VERSION 5.8 ;
BUSBITCHARS "[]" ;
DIVIDERCHAR "/" ;
UNITS
    DATABASE MICRONS 1000 ;
END UNITS

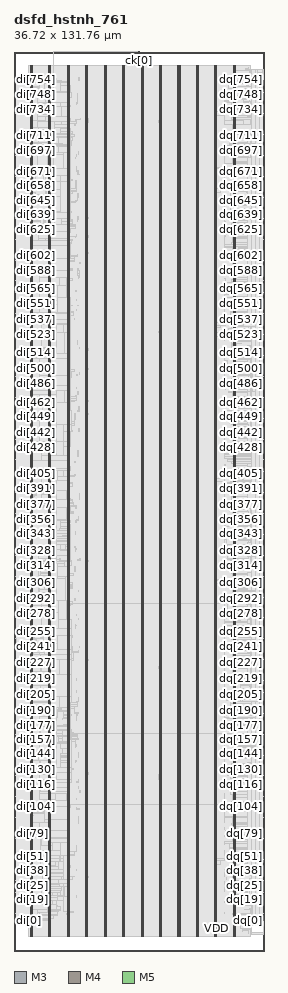
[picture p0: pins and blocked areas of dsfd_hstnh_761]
MACRO dsfd_hstnh_761
  FOREIGN dsfd_hstnh_761 0 0 ;
  CLASS BLOCK ;
  SIZE 36.72 BY 131.76 ;
  PIN ck[0]
    DIRECTION INPUT ;
    USE SIGNAL ;
    PORT
      LAYER M3 ;
        RECT  18.36 131.616 18.378 131.76 ;
    END
    PORT
      LAYER M3 ;
        RECT  18.18 131.593 18.378 131.628 ;
    END
  END ck[0]
  PIN di[0]
    DIRECTION INPUT ;
    USE SIGNAL ;
    PORT
      LAYER M4 ;
        RECT  0 4.416 0.192 4.44 ;
    END
  END di[0]
  PIN di[100]
    DIRECTION INPUT ;
    USE SIGNAL ;
    PORT
      LAYER M4 ;
        RECT  0 20.592 0.192 20.616 ;
    END
  END di[100]
  PIN di[101]
    DIRECTION INPUT ;
    USE SIGNAL ;
    PORT
      LAYER M4 ;
        RECT  0 20.736 0.192 20.76 ;
    END
  END di[101]
  PIN di[102]
    DIRECTION INPUT ;
    USE SIGNAL ;
    PORT
      LAYER M4 ;
        RECT  0 20.928 0.192 20.952 ;
    END
  END di[102]
  PIN di[103]
    DIRECTION INPUT ;
    USE SIGNAL ;
    PORT
      LAYER M4 ;
        RECT  0 21.072 0.192 21.096 ;
    END
  END di[103]
  PIN di[104]
    DIRECTION INPUT ;
    USE SIGNAL ;
    PORT
      LAYER M4 ;
        RECT  0 21.216 0.192 21.24 ;
    END
  END di[104]
  PIN di[105]
    DIRECTION INPUT ;
    USE SIGNAL ;
    PORT
      LAYER M4 ;
        RECT  0 21.408 0.192 21.432 ;
    END
  END di[105]
  PIN di[106]
    DIRECTION INPUT ;
    USE SIGNAL ;
    PORT
      LAYER M4 ;
        RECT  0 21.552 0.192 21.576 ;
    END
  END di[106]
  PIN di[107]
    DIRECTION INPUT ;
    USE SIGNAL ;
    PORT
      LAYER M4 ;
        RECT  0 21.744 0.192 21.768 ;
    END
  END di[107]
  PIN di[108]
    DIRECTION INPUT ;
    USE SIGNAL ;
    PORT
      LAYER M4 ;
        RECT  0 21.888 0.192 21.912 ;
    END
  END di[108]
  PIN di[109]
    DIRECTION INPUT ;
    USE SIGNAL ;
    PORT
      LAYER M4 ;
        RECT  0 22.032 0.192 22.056 ;
    END
  END di[109]
  PIN di[10]
    DIRECTION INPUT ;
    USE SIGNAL ;
    PORT
      LAYER M4 ;
        RECT  0 6.048 0.192 6.072 ;
    END
  END di[10]
  PIN di[110]
    DIRECTION INPUT ;
    USE SIGNAL ;
    PORT
      LAYER M4 ;
        RECT  0 22.224 0.192 22.248 ;
    END
  END di[110]
  PIN di[111]
    DIRECTION INPUT ;
    USE SIGNAL ;
    PORT
      LAYER M4 ;
        RECT  0 22.368 0.192 22.392 ;
    END
  END di[111]
  PIN di[112]
    DIRECTION INPUT ;
    USE SIGNAL ;
    PORT
      LAYER M4 ;
        RECT  0 22.512 0.192 22.536 ;
    END
  END di[112]
  PIN di[113]
    DIRECTION INPUT ;
    USE SIGNAL ;
    PORT
      LAYER M4 ;
        RECT  0 22.704 0.192 22.728 ;
    END
  END di[113]
  PIN di[114]
    DIRECTION INPUT ;
    USE SIGNAL ;
    PORT
      LAYER M4 ;
        RECT  0 22.848 0.192 22.872 ;
    END
  END di[114]
  PIN di[115]
    DIRECTION INPUT ;
    USE SIGNAL ;
    PORT
      LAYER M4 ;
        RECT  0 23.04 0.192 23.064 ;
    END
  END di[115]
  PIN di[116]
    DIRECTION INPUT ;
    USE SIGNAL ;
    PORT
      LAYER M4 ;
        RECT  0 23.184 0.192 23.208 ;
    END
  END di[116]
  PIN di[117]
    DIRECTION INPUT ;
    USE SIGNAL ;
    PORT
      LAYER M4 ;
        RECT  0 23.328 0.192 23.352 ;
    END
  END di[117]
  PIN di[118]
    DIRECTION INPUT ;
    USE SIGNAL ;
    PORT
      LAYER M4 ;
        RECT  0 23.52 0.192 23.544 ;
    END
  END di[118]
  PIN di[119]
    DIRECTION INPUT ;
    USE SIGNAL ;
    PORT
      LAYER M4 ;
        RECT  0 23.664 0.192 23.688 ;
    END
  END di[119]
  PIN di[11]
    DIRECTION INPUT ;
    USE SIGNAL ;
    PORT
      LAYER M4 ;
        RECT  0 6.192 0.192 6.216 ;
    END
  END di[11]
  PIN di[120]
    DIRECTION INPUT ;
    USE SIGNAL ;
    PORT
      LAYER M4 ;
        RECT  0 23.808 0.192 23.832 ;
    END
  END di[120]
  PIN di[121]
    DIRECTION INPUT ;
    USE SIGNAL ;
    PORT
      LAYER M4 ;
        RECT  0 24 0.192 24.024 ;
    END
  END di[121]
  PIN di[122]
    DIRECTION INPUT ;
    USE SIGNAL ;
    PORT
      LAYER M4 ;
        RECT  0 24.144 0.192 24.168 ;
    END
  END di[122]
  PIN di[123]
    DIRECTION INPUT ;
    USE SIGNAL ;
    PORT
      LAYER M4 ;
        RECT  0 24.336 0.192 24.36 ;
    END
  END di[123]
  PIN di[124]
    DIRECTION INPUT ;
    USE SIGNAL ;
    PORT
      LAYER M4 ;
        RECT  0 24.48 0.192 24.504 ;
    END
  END di[124]
  PIN di[125]
    DIRECTION INPUT ;
    USE SIGNAL ;
    PORT
      LAYER M4 ;
        RECT  0 24.624 0.192 24.648 ;
    END
  END di[125]
  PIN di[126]
    DIRECTION INPUT ;
    USE SIGNAL ;
    PORT
      LAYER M4 ;
        RECT  0 24.816 0.192 24.84 ;
    END
  END di[126]
  PIN di[127]
    DIRECTION INPUT ;
    USE SIGNAL ;
    PORT
      LAYER M4 ;
        RECT  0 24.96 0.192 24.984 ;
    END
  END di[127]
  PIN di[128]
    DIRECTION INPUT ;
    USE SIGNAL ;
    PORT
      LAYER M4 ;
        RECT  0 25.104 0.192 25.128 ;
    END
  END di[128]
  PIN di[129]
    DIRECTION INPUT ;
    USE SIGNAL ;
    PORT
      LAYER M4 ;
        RECT  0 25.296 0.192 25.32 ;
    END
  END di[129]
  PIN di[12]
    DIRECTION INPUT ;
    USE SIGNAL ;
    PORT
      LAYER M4 ;
        RECT  0 6.336 0.192 6.36 ;
    END
  END di[12]
  PIN di[130]
    DIRECTION INPUT ;
    USE SIGNAL ;
    PORT
      LAYER M4 ;
        RECT  0 25.44 0.192 25.464 ;
    END
  END di[130]
  PIN di[131]
    DIRECTION INPUT ;
    USE SIGNAL ;
    PORT
      LAYER M4 ;
        RECT  0 25.584 0.192 25.608 ;
    END
  END di[131]
  PIN di[132]
    DIRECTION INPUT ;
    USE SIGNAL ;
    PORT
      LAYER M4 ;
        RECT  0 25.776 0.192 25.8 ;
    END
  END di[132]
  PIN di[133]
    DIRECTION INPUT ;
    USE SIGNAL ;
    PORT
      LAYER M4 ;
        RECT  0 25.92 0.192 25.944 ;
    END
  END di[133]
  PIN di[134]
    DIRECTION INPUT ;
    USE SIGNAL ;
    PORT
      LAYER M4 ;
        RECT  0 26.112 0.192 26.136 ;
    END
  END di[134]
  PIN di[135]
    DIRECTION INPUT ;
    USE SIGNAL ;
    PORT
      LAYER M4 ;
        RECT  0 26.256 0.192 26.28 ;
    END
  END di[135]
  PIN di[136]
    DIRECTION INPUT ;
    USE SIGNAL ;
    PORT
      LAYER M4 ;
        RECT  0 26.4 0.192 26.424 ;
    END
  END di[136]
  PIN di[137]
    DIRECTION INPUT ;
    USE SIGNAL ;
    PORT
      LAYER M4 ;
        RECT  0 26.592 0.192 26.616 ;
    END
  END di[137]
  PIN di[138]
    DIRECTION INPUT ;
    USE SIGNAL ;
    PORT
      LAYER M4 ;
        RECT  0 26.736 0.192 26.76 ;
    END
  END di[138]
  PIN di[139]
    DIRECTION INPUT ;
    USE SIGNAL ;
    PORT
      LAYER M4 ;
        RECT  0 26.88 0.192 26.904 ;
    END
  END di[139]
  PIN di[13]
    DIRECTION INPUT ;
    USE SIGNAL ;
    PORT
      LAYER M4 ;
        RECT  0 6.528 0.192 6.552 ;
    END
  END di[13]
  PIN di[140]
    DIRECTION INPUT ;
    USE SIGNAL ;
    PORT
      LAYER M4 ;
        RECT  0 27.072 0.192 27.096 ;
    END
  END di[140]
  PIN di[141]
    DIRECTION INPUT ;
    USE SIGNAL ;
    PORT
      LAYER M4 ;
        RECT  0 27.216 0.192 27.24 ;
    END
  END di[141]
  PIN di[142]
    DIRECTION INPUT ;
    USE SIGNAL ;
    PORT
      LAYER M4 ;
        RECT  0 27.408 0.192 27.432 ;
    END
  END di[142]
  PIN di[143]
    DIRECTION INPUT ;
    USE SIGNAL ;
    PORT
      LAYER M4 ;
        RECT  0 27.552 0.192 27.576 ;
    END
  END di[143]
  PIN di[144]
    DIRECTION INPUT ;
    USE SIGNAL ;
    PORT
      LAYER M4 ;
        RECT  0 27.696 0.192 27.72 ;
    END
  END di[144]
  PIN di[145]
    DIRECTION INPUT ;
    USE SIGNAL ;
    PORT
      LAYER M4 ;
        RECT  0 27.888 0.192 27.912 ;
    END
  END di[145]
  PIN di[146]
    DIRECTION INPUT ;
    USE SIGNAL ;
    PORT
      LAYER M4 ;
        RECT  0 28.032 0.192 28.056 ;
    END
  END di[146]
  PIN di[147]
    DIRECTION INPUT ;
    USE SIGNAL ;
    PORT
      LAYER M4 ;
        RECT  0 28.176 0.192 28.2 ;
    END
  END di[147]
  PIN di[148]
    DIRECTION INPUT ;
    USE SIGNAL ;
    PORT
      LAYER M4 ;
        RECT  0 28.368 0.192 28.392 ;
    END
  END di[148]
  PIN di[149]
    DIRECTION INPUT ;
    USE SIGNAL ;
    PORT
      LAYER M4 ;
        RECT  0 28.512 0.192 28.536 ;
    END
  END di[149]
  PIN di[14]
    DIRECTION INPUT ;
    USE SIGNAL ;
    PORT
      LAYER M4 ;
        RECT  0 6.672 0.192 6.696 ;
    END
  END di[14]
  PIN di[150]
    DIRECTION INPUT ;
    USE SIGNAL ;
    PORT
      LAYER M4 ;
        RECT  0 28.704 0.192 28.728 ;
    END
  END di[150]
  PIN di[151]
    DIRECTION INPUT ;
    USE SIGNAL ;
    PORT
      LAYER M4 ;
        RECT  0 28.848 0.192 28.872 ;
    END
  END di[151]
  PIN di[152]
    DIRECTION INPUT ;
    USE SIGNAL ;
    PORT
      LAYER M4 ;
        RECT  0 28.992 0.192 29.016 ;
    END
  END di[152]
  PIN di[153]
    DIRECTION INPUT ;
    USE SIGNAL ;
    PORT
      LAYER M4 ;
        RECT  0 29.184 0.192 29.208 ;
    END
  END di[153]
  PIN di[154]
    DIRECTION INPUT ;
    USE SIGNAL ;
    PORT
      LAYER M4 ;
        RECT  0 29.328 0.192 29.352 ;
    END
  END di[154]
  PIN di[155]
    DIRECTION INPUT ;
    USE SIGNAL ;
    PORT
      LAYER M4 ;
        RECT  0 29.472 0.192 29.496 ;
    END
  END di[155]
  PIN di[156]
    DIRECTION INPUT ;
    USE SIGNAL ;
    PORT
      LAYER M4 ;
        RECT  0 29.664 0.192 29.688 ;
    END
  END di[156]
  PIN di[157]
    DIRECTION INPUT ;
    USE SIGNAL ;
    PORT
      LAYER M4 ;
        RECT  0 29.808 0.192 29.832 ;
    END
  END di[157]
  PIN di[158]
    DIRECTION INPUT ;
    USE SIGNAL ;
    PORT
      LAYER M4 ;
        RECT  0 29.952 0.192 29.976 ;
    END
  END di[158]
  PIN di[159]
    DIRECTION INPUT ;
    USE SIGNAL ;
    PORT
      LAYER M4 ;
        RECT  0 30.144 0.192 30.168 ;
    END
  END di[159]
  PIN di[15]
    DIRECTION INPUT ;
    USE SIGNAL ;
    PORT
      LAYER M4 ;
        RECT  0 6.816 0.192 6.84 ;
    END
  END di[15]
  PIN di[160]
    DIRECTION INPUT ;
    USE SIGNAL ;
    PORT
      LAYER M4 ;
        RECT  0 30.288 0.192 30.312 ;
    END
  END di[160]
  PIN di[161]
    DIRECTION INPUT ;
    USE SIGNAL ;
    PORT
      LAYER M4 ;
        RECT  0 30.48 0.192 30.504 ;
    END
  END di[161]
  PIN di[162]
    DIRECTION INPUT ;
    USE SIGNAL ;
    PORT
      LAYER M4 ;
        RECT  0 30.624 0.192 30.648 ;
    END
  END di[162]
  PIN di[163]
    DIRECTION INPUT ;
    USE SIGNAL ;
    PORT
      LAYER M4 ;
        RECT  0 30.768 0.192 30.792 ;
    END
  END di[163]
  PIN di[164]
    DIRECTION INPUT ;
    USE SIGNAL ;
    PORT
      LAYER M4 ;
        RECT  0 30.96 0.192 30.984 ;
    END
  END di[164]
  PIN di[165]
    DIRECTION INPUT ;
    USE SIGNAL ;
    PORT
      LAYER M4 ;
        RECT  0 31.104 0.192 31.128 ;
    END
  END di[165]
  PIN di[166]
    DIRECTION INPUT ;
    USE SIGNAL ;
    PORT
      LAYER M4 ;
        RECT  0 31.248 0.192 31.272 ;
    END
  END di[166]
  PIN di[167]
    DIRECTION INPUT ;
    USE SIGNAL ;
    PORT
      LAYER M4 ;
        RECT  0 31.44 0.192 31.464 ;
    END
  END di[167]
  PIN di[168]
    DIRECTION INPUT ;
    USE SIGNAL ;
    PORT
      LAYER M4 ;
        RECT  0 31.584 0.192 31.608 ;
    END
  END di[168]
  PIN di[169]
    DIRECTION INPUT ;
    USE SIGNAL ;
    PORT
      LAYER M4 ;
        RECT  0 31.776 0.192 31.8 ;
    END
  END di[169]
  PIN di[16]
    DIRECTION INPUT ;
    USE SIGNAL ;
    PORT
      LAYER M4 ;
        RECT  0 7.008 0.192 7.032 ;
    END
  END di[16]
  PIN di[170]
    DIRECTION INPUT ;
    USE SIGNAL ;
    PORT
      LAYER M4 ;
        RECT  0 31.92 0.192 31.944 ;
    END
  END di[170]
  PIN di[171]
    DIRECTION INPUT ;
    USE SIGNAL ;
    PORT
      LAYER M4 ;
        RECT  0 32.064 0.192 32.088 ;
    END
  END di[171]
  PIN di[172]
    DIRECTION INPUT ;
    USE SIGNAL ;
    PORT
      LAYER M4 ;
        RECT  0 32.256 0.192 32.28 ;
    END
  END di[172]
  PIN di[173]
    DIRECTION INPUT ;
    USE SIGNAL ;
    PORT
      LAYER M4 ;
        RECT  0 32.4 0.192 32.424 ;
    END
  END di[173]
  PIN di[174]
    DIRECTION INPUT ;
    USE SIGNAL ;
    PORT
      LAYER M4 ;
        RECT  0 32.544 0.192 32.568 ;
    END
  END di[174]
  PIN di[175]
    DIRECTION INPUT ;
    USE SIGNAL ;
    PORT
      LAYER M4 ;
        RECT  0 32.736 0.192 32.76 ;
    END
  END di[175]
  PIN di[176]
    DIRECTION INPUT ;
    USE SIGNAL ;
    PORT
      LAYER M4 ;
        RECT  0 32.88 0.192 32.904 ;
    END
  END di[176]
  PIN di[177]
    DIRECTION INPUT ;
    USE SIGNAL ;
    PORT
      LAYER M4 ;
        RECT  0 33.072 0.192 33.096 ;
    END
  END di[177]
  PIN di[178]
    DIRECTION INPUT ;
    USE SIGNAL ;
    PORT
      LAYER M4 ;
        RECT  0 33.216 0.192 33.24 ;
    END
  END di[178]
  PIN di[179]
    DIRECTION INPUT ;
    USE SIGNAL ;
    PORT
      LAYER M4 ;
        RECT  0 33.36 0.192 33.384 ;
    END
  END di[179]
  PIN di[17]
    DIRECTION INPUT ;
    USE SIGNAL ;
    PORT
      LAYER M4 ;
        RECT  0 7.152 0.192 7.176 ;
    END
  END di[17]
  PIN di[180]
    DIRECTION INPUT ;
    USE SIGNAL ;
    PORT
      LAYER M4 ;
        RECT  0 33.552 0.192 33.576 ;
    END
  END di[180]
  PIN di[181]
    DIRECTION INPUT ;
    USE SIGNAL ;
    PORT
      LAYER M4 ;
        RECT  0 33.696 0.192 33.72 ;
    END
  END di[181]
  PIN di[182]
    DIRECTION INPUT ;
    USE SIGNAL ;
    PORT
      LAYER M4 ;
        RECT  0 33.84 0.192 33.864 ;
    END
  END di[182]
  PIN di[183]
    DIRECTION INPUT ;
    USE SIGNAL ;
    PORT
      LAYER M4 ;
        RECT  0 34.032 0.192 34.056 ;
    END
  END di[183]
  PIN di[184]
    DIRECTION INPUT ;
    USE SIGNAL ;
    PORT
      LAYER M4 ;
        RECT  0 34.176 0.192 34.2 ;
    END
  END di[184]
  PIN di[185]
    DIRECTION INPUT ;
    USE SIGNAL ;
    PORT
      LAYER M4 ;
        RECT  0 34.32 0.192 34.344 ;
    END
  END di[185]
  PIN di[186]
    DIRECTION INPUT ;
    USE SIGNAL ;
    PORT
      LAYER M4 ;
        RECT  0 34.512 0.192 34.536 ;
    END
  END di[186]
  PIN di[187]
    DIRECTION INPUT ;
    USE SIGNAL ;
    PORT
      LAYER M4 ;
        RECT  0 34.656 0.192 34.68 ;
    END
  END di[187]
  PIN di[188]
    DIRECTION INPUT ;
    USE SIGNAL ;
    PORT
      LAYER M4 ;
        RECT  0 34.848 0.192 34.872 ;
    END
  END di[188]
  PIN di[189]
    DIRECTION INPUT ;
    USE SIGNAL ;
    PORT
      LAYER M4 ;
        RECT  0 34.992 0.192 35.016 ;
    END
  END di[189]
  PIN di[18]
    DIRECTION INPUT ;
    USE SIGNAL ;
    PORT
      LAYER M4 ;
        RECT  0 7.344 0.192 7.368 ;
    END
  END di[18]
  PIN di[190]
    DIRECTION INPUT ;
    USE SIGNAL ;
    PORT
      LAYER M4 ;
        RECT  0 35.136 0.192 35.16 ;
    END
  END di[190]
  PIN di[191]
    DIRECTION INPUT ;
    USE SIGNAL ;
    PORT
      LAYER M4 ;
        RECT  0 35.328 0.192 35.352 ;
    END
  END di[191]
  PIN di[192]
    DIRECTION INPUT ;
    USE SIGNAL ;
    PORT
      LAYER M4 ;
        RECT  0 35.472 0.192 35.496 ;
    END
  END di[192]
  PIN di[193]
    DIRECTION INPUT ;
    USE SIGNAL ;
    PORT
      LAYER M4 ;
        RECT  0 35.616 0.192 35.64 ;
    END
  END di[193]
  PIN di[194]
    DIRECTION INPUT ;
    USE SIGNAL ;
    PORT
      LAYER M4 ;
        RECT  0 35.808 0.192 35.832 ;
    END
  END di[194]
  PIN di[195]
    DIRECTION INPUT ;
    USE SIGNAL ;
    PORT
      LAYER M4 ;
        RECT  0 35.952 0.192 35.976 ;
    END
  END di[195]
  PIN di[196]
    DIRECTION INPUT ;
    USE SIGNAL ;
    PORT
      LAYER M4 ;
        RECT  0 36.144 0.192 36.168 ;
    END
  END di[196]
  PIN di[197]
    DIRECTION INPUT ;
    USE SIGNAL ;
    PORT
      LAYER M4 ;
        RECT  0 36.288 0.192 36.312 ;
    END
  END di[197]
  PIN di[198]
    DIRECTION INPUT ;
    USE SIGNAL ;
    PORT
      LAYER M4 ;
        RECT  0 36.432 0.192 36.456 ;
    END
  END di[198]
  PIN di[199]
    DIRECTION INPUT ;
    USE SIGNAL ;
    PORT
      LAYER M4 ;
        RECT  0 36.624 0.192 36.648 ;
    END
  END di[199]
  PIN di[19]
    DIRECTION INPUT ;
    USE SIGNAL ;
    PORT
      LAYER M4 ;
        RECT  0 7.488 0.192 7.512 ;
    END
  END di[19]
  PIN di[1]
    DIRECTION INPUT ;
    USE SIGNAL ;
    PORT
      LAYER M4 ;
        RECT  0 4.56 0.192 4.584 ;
    END
  END di[1]
  PIN di[200]
    DIRECTION INPUT ;
    USE SIGNAL ;
    PORT
      LAYER M4 ;
        RECT  0 36.768 0.192 36.792 ;
    END
  END di[200]
  PIN di[201]
    DIRECTION INPUT ;
    USE SIGNAL ;
    PORT
      LAYER M4 ;
        RECT  0 36.912 0.192 36.936 ;
    END
  END di[201]
  PIN di[202]
    DIRECTION INPUT ;
    USE SIGNAL ;
    PORT
      LAYER M4 ;
        RECT  0 37.104 0.192 37.128 ;
    END
  END di[202]
  PIN di[203]
    DIRECTION INPUT ;
    USE SIGNAL ;
    PORT
      LAYER M4 ;
        RECT  0 37.248 0.192 37.272 ;
    END
  END di[203]
  PIN di[204]
    DIRECTION INPUT ;
    USE SIGNAL ;
    PORT
      LAYER M4 ;
        RECT  0 37.44 0.192 37.464 ;
    END
  END di[204]
  PIN di[205]
    DIRECTION INPUT ;
    USE SIGNAL ;
    PORT
      LAYER M4 ;
        RECT  0 37.584 0.192 37.608 ;
    END
  END di[205]
  PIN di[206]
    DIRECTION INPUT ;
    USE SIGNAL ;
    PORT
      LAYER M4 ;
        RECT  0 37.728 0.192 37.752 ;
    END
  END di[206]
  PIN di[207]
    DIRECTION INPUT ;
    USE SIGNAL ;
    PORT
      LAYER M4 ;
        RECT  0 37.92 0.192 37.944 ;
    END
  END di[207]
  PIN di[208]
    DIRECTION INPUT ;
    USE SIGNAL ;
    PORT
      LAYER M4 ;
        RECT  0 38.064 0.192 38.088 ;
    END
  END di[208]
  PIN di[209]
    DIRECTION INPUT ;
    USE SIGNAL ;
    PORT
      LAYER M4 ;
        RECT  0 38.208 0.192 38.232 ;
    END
  END di[209]
  PIN di[20]
    DIRECTION INPUT ;
    USE SIGNAL ;
    PORT
      LAYER M4 ;
        RECT  0 7.632 0.192 7.656 ;
    END
  END di[20]
  PIN di[210]
    DIRECTION INPUT ;
    USE SIGNAL ;
    PORT
      LAYER M4 ;
        RECT  0 38.4 0.192 38.424 ;
    END
  END di[210]
  PIN di[211]
    DIRECTION INPUT ;
    USE SIGNAL ;
    PORT
      LAYER M4 ;
        RECT  0 38.544 0.192 38.568 ;
    END
  END di[211]
  PIN di[212]
    DIRECTION INPUT ;
    USE SIGNAL ;
    PORT
      LAYER M4 ;
        RECT  0 38.688 0.192 38.712 ;
    END
  END di[212]
  PIN di[213]
    DIRECTION INPUT ;
    USE SIGNAL ;
    PORT
      LAYER M4 ;
        RECT  0 38.88 0.192 38.904 ;
    END
  END di[213]
  PIN di[214]
    DIRECTION INPUT ;
    USE SIGNAL ;
    PORT
      LAYER M4 ;
        RECT  0 39.024 0.192 39.048 ;
    END
  END di[214]
  PIN di[215]
    DIRECTION INPUT ;
    USE SIGNAL ;
    PORT
      LAYER M4 ;
        RECT  0 39.216 0.192 39.24 ;
    END
  END di[215]
  PIN di[216]
    DIRECTION INPUT ;
    USE SIGNAL ;
    PORT
      LAYER M4 ;
        RECT  0 39.36 0.192 39.384 ;
    END
  END di[216]
  PIN di[217]
    DIRECTION INPUT ;
    USE SIGNAL ;
    PORT
      LAYER M4 ;
        RECT  0 39.504 0.192 39.528 ;
    END
  END di[217]
  PIN di[218]
    DIRECTION INPUT ;
    USE SIGNAL ;
    PORT
      LAYER M4 ;
        RECT  0 39.696 0.192 39.72 ;
    END
  END di[218]
  PIN di[219]
    DIRECTION INPUT ;
    USE SIGNAL ;
    PORT
      LAYER M4 ;
        RECT  0 39.84 0.192 39.864 ;
    END
  END di[219]
  PIN di[21]
    DIRECTION INPUT ;
    USE SIGNAL ;
    PORT
      LAYER M4 ;
        RECT  0 7.824 0.192 7.848 ;
    END
  END di[21]
  PIN di[220]
    DIRECTION INPUT ;
    USE SIGNAL ;
    PORT
      LAYER M4 ;
        RECT  0 39.984 0.192 40.008 ;
    END
  END di[220]
  PIN di[221]
    DIRECTION INPUT ;
    USE SIGNAL ;
    PORT
      LAYER M4 ;
        RECT  0 40.176 0.192 40.2 ;
    END
  END di[221]
  PIN di[222]
    DIRECTION INPUT ;
    USE SIGNAL ;
    PORT
      LAYER M4 ;
        RECT  0 40.32 0.192 40.344 ;
    END
  END di[222]
  PIN di[223]
    DIRECTION INPUT ;
    USE SIGNAL ;
    PORT
      LAYER M4 ;
        RECT  0 40.512 0.192 40.536 ;
    END
  END di[223]
  PIN di[224]
    DIRECTION INPUT ;
    USE SIGNAL ;
    PORT
      LAYER M4 ;
        RECT  0 40.656 0.192 40.68 ;
    END
  END di[224]
  PIN di[225]
    DIRECTION INPUT ;
    USE SIGNAL ;
    PORT
      LAYER M4 ;
        RECT  0 40.8 0.192 40.824 ;
    END
  END di[225]
  PIN di[226]
    DIRECTION INPUT ;
    USE SIGNAL ;
    PORT
      LAYER M4 ;
        RECT  0 40.992 0.192 41.016 ;
    END
  END di[226]
  PIN di[227]
    DIRECTION INPUT ;
    USE SIGNAL ;
    PORT
      LAYER M4 ;
        RECT  0 41.136 0.192 41.16 ;
    END
  END di[227]
  PIN di[228]
    DIRECTION INPUT ;
    USE SIGNAL ;
    PORT
      LAYER M4 ;
        RECT  0 41.28 0.192 41.304 ;
    END
  END di[228]
  PIN di[229]
    DIRECTION INPUT ;
    USE SIGNAL ;
    PORT
      LAYER M4 ;
        RECT  0 41.472 0.192 41.496 ;
    END
  END di[229]
  PIN di[22]
    DIRECTION INPUT ;
    USE SIGNAL ;
    PORT
      LAYER M4 ;
        RECT  0 7.968 0.192 7.992 ;
    END
  END di[22]
  PIN di[230]
    DIRECTION INPUT ;
    USE SIGNAL ;
    PORT
      LAYER M4 ;
        RECT  0 41.616 0.192 41.64 ;
    END
  END di[230]
  PIN di[231]
    DIRECTION INPUT ;
    USE SIGNAL ;
    PORT
      LAYER M4 ;
        RECT  0 41.808 0.192 41.832 ;
    END
  END di[231]
  PIN di[232]
    DIRECTION INPUT ;
    USE SIGNAL ;
    PORT
      LAYER M4 ;
        RECT  0 41.952 0.192 41.976 ;
    END
  END di[232]
  PIN di[233]
    DIRECTION INPUT ;
    USE SIGNAL ;
    PORT
      LAYER M4 ;
        RECT  0 42.096 0.192 42.12 ;
    END
  END di[233]
  PIN di[234]
    DIRECTION INPUT ;
    USE SIGNAL ;
    PORT
      LAYER M4 ;
        RECT  0 42.288 0.192 42.312 ;
    END
  END di[234]
  PIN di[235]
    DIRECTION INPUT ;
    USE SIGNAL ;
    PORT
      LAYER M4 ;
        RECT  0 42.432 0.192 42.456 ;
    END
  END di[235]
  PIN di[236]
    DIRECTION INPUT ;
    USE SIGNAL ;
    PORT
      LAYER M4 ;
        RECT  0 42.576 0.192 42.6 ;
    END
  END di[236]
  PIN di[237]
    DIRECTION INPUT ;
    USE SIGNAL ;
    PORT
      LAYER M4 ;
        RECT  0 42.768 0.192 42.792 ;
    END
  END di[237]
  PIN di[238]
    DIRECTION INPUT ;
    USE SIGNAL ;
    PORT
      LAYER M4 ;
        RECT  0 42.912 0.192 42.936 ;
    END
  END di[238]
  PIN di[239]
    DIRECTION INPUT ;
    USE SIGNAL ;
    PORT
      LAYER M4 ;
        RECT  0 43.104 0.192 43.128 ;
    END
  END di[239]
  PIN di[23]
    DIRECTION INPUT ;
    USE SIGNAL ;
    PORT
      LAYER M4 ;
        RECT  0 8.112 0.192 8.136 ;
    END
  END di[23]
  PIN di[240]
    DIRECTION INPUT ;
    USE SIGNAL ;
    PORT
      LAYER M4 ;
        RECT  0 43.248 0.192 43.272 ;
    END
  END di[240]
  PIN di[241]
    DIRECTION INPUT ;
    USE SIGNAL ;
    PORT
      LAYER M4 ;
        RECT  0 43.392 0.192 43.416 ;
    END
  END di[241]
  PIN di[242]
    DIRECTION INPUT ;
    USE SIGNAL ;
    PORT
      LAYER M4 ;
        RECT  0 43.584 0.192 43.608 ;
    END
  END di[242]
  PIN di[243]
    DIRECTION INPUT ;
    USE SIGNAL ;
    PORT
      LAYER M4 ;
        RECT  0 43.728 0.192 43.752 ;
    END
  END di[243]
  PIN di[244]
    DIRECTION INPUT ;
    USE SIGNAL ;
    PORT
      LAYER M4 ;
        RECT  0 43.872 0.192 43.896 ;
    END
  END di[244]
  PIN di[245]
    DIRECTION INPUT ;
    USE SIGNAL ;
    PORT
      LAYER M4 ;
        RECT  0 44.064 0.192 44.088 ;
    END
  END di[245]
  PIN di[246]
    DIRECTION INPUT ;
    USE SIGNAL ;
    PORT
      LAYER M4 ;
        RECT  0 44.208 0.192 44.232 ;
    END
  END di[246]
  PIN di[247]
    DIRECTION INPUT ;
    USE SIGNAL ;
    PORT
      LAYER M4 ;
        RECT  0 44.352 0.192 44.376 ;
    END
  END di[247]
  PIN di[248]
    DIRECTION INPUT ;
    USE SIGNAL ;
    PORT
      LAYER M4 ;
        RECT  0 44.544 0.192 44.568 ;
    END
  END di[248]
  PIN di[249]
    DIRECTION INPUT ;
    USE SIGNAL ;
    PORT
      LAYER M4 ;
        RECT  0 44.688 0.192 44.712 ;
    END
  END di[249]
  PIN di[24]
    DIRECTION INPUT ;
    USE SIGNAL ;
    PORT
      LAYER M4 ;
        RECT  0 8.304 0.192 8.328 ;
    END
  END di[24]
  PIN di[250]
    DIRECTION INPUT ;
    USE SIGNAL ;
    PORT
      LAYER M4 ;
        RECT  0 44.88 0.192 44.904 ;
    END
  END di[250]
  PIN di[251]
    DIRECTION INPUT ;
    USE SIGNAL ;
    PORT
      LAYER M4 ;
        RECT  0 45.024 0.192 45.048 ;
    END
  END di[251]
  PIN di[252]
    DIRECTION INPUT ;
    USE SIGNAL ;
    PORT
      LAYER M4 ;
        RECT  0 45.168 0.192 45.192 ;
    END
  END di[252]
  PIN di[253]
    DIRECTION INPUT ;
    USE SIGNAL ;
    PORT
      LAYER M4 ;
        RECT  0 45.36 0.192 45.384 ;
    END
  END di[253]
  PIN di[254]
    DIRECTION INPUT ;
    USE SIGNAL ;
    PORT
      LAYER M4 ;
        RECT  0 45.504 0.192 45.528 ;
    END
  END di[254]
  PIN di[255]
    DIRECTION INPUT ;
    USE SIGNAL ;
    PORT
      LAYER M4 ;
        RECT  0 45.648 0.192 45.672 ;
    END
  END di[255]
  PIN di[256]
    DIRECTION INPUT ;
    USE SIGNAL ;
    PORT
      LAYER M4 ;
        RECT  0 45.84 0.192 45.864 ;
    END
  END di[256]
  PIN di[257]
    DIRECTION INPUT ;
    USE SIGNAL ;
    PORT
      LAYER M4 ;
        RECT  0 45.984 0.192 46.008 ;
    END
  END di[257]
  PIN di[258]
    DIRECTION INPUT ;
    USE SIGNAL ;
    PORT
      LAYER M4 ;
        RECT  0 46.176 0.192 46.2 ;
    END
  END di[258]
  PIN di[259]
    DIRECTION INPUT ;
    USE SIGNAL ;
    PORT
      LAYER M4 ;
        RECT  0 46.32 0.192 46.344 ;
    END
  END di[259]
  PIN di[25]
    DIRECTION INPUT ;
    USE SIGNAL ;
    PORT
      LAYER M4 ;
        RECT  0 8.448 0.192 8.472 ;
    END
  END di[25]
  PIN di[260]
    DIRECTION INPUT ;
    USE SIGNAL ;
    PORT
      LAYER M4 ;
        RECT  0 46.464 0.192 46.488 ;
    END
  END di[260]
  PIN di[261]
    DIRECTION INPUT ;
    USE SIGNAL ;
    PORT
      LAYER M4 ;
        RECT  0 46.656 0.192 46.68 ;
    END
  END di[261]
  PIN di[262]
    DIRECTION INPUT ;
    USE SIGNAL ;
    PORT
      LAYER M4 ;
        RECT  0 46.8 0.192 46.824 ;
    END
  END di[262]
  PIN di[263]
    DIRECTION INPUT ;
    USE SIGNAL ;
    PORT
      LAYER M4 ;
        RECT  0 46.944 0.192 46.968 ;
    END
  END di[263]
  PIN di[264]
    DIRECTION INPUT ;
    USE SIGNAL ;
    PORT
      LAYER M4 ;
        RECT  0 47.136 0.192 47.16 ;
    END
  END di[264]
  PIN di[265]
    DIRECTION INPUT ;
    USE SIGNAL ;
    PORT
      LAYER M4 ;
        RECT  0 47.28 0.192 47.304 ;
    END
  END di[265]
  PIN di[266]
    DIRECTION INPUT ;
    USE SIGNAL ;
    PORT
      LAYER M4 ;
        RECT  0 47.472 0.192 47.496 ;
    END
  END di[266]
  PIN di[267]
    DIRECTION INPUT ;
    USE SIGNAL ;
    PORT
      LAYER M4 ;
        RECT  0 47.616 0.192 47.64 ;
    END
  END di[267]
  PIN di[268]
    DIRECTION INPUT ;
    USE SIGNAL ;
    PORT
      LAYER M4 ;
        RECT  0 47.76 0.192 47.784 ;
    END
  END di[268]
  PIN di[269]
    DIRECTION INPUT ;
    USE SIGNAL ;
    PORT
      LAYER M4 ;
        RECT  0 47.952 0.192 47.976 ;
    END
  END di[269]
  PIN di[26]
    DIRECTION INPUT ;
    USE SIGNAL ;
    PORT
      LAYER M4 ;
        RECT  0 8.64 0.192 8.664 ;
    END
  END di[26]
  PIN di[270]
    DIRECTION INPUT ;
    USE SIGNAL ;
    PORT
      LAYER M4 ;
        RECT  0 48.096 0.192 48.12 ;
    END
  END di[270]
  PIN di[271]
    DIRECTION INPUT ;
    USE SIGNAL ;
    PORT
      LAYER M4 ;
        RECT  0 48.24 0.192 48.264 ;
    END
  END di[271]
  PIN di[272]
    DIRECTION INPUT ;
    USE SIGNAL ;
    PORT
      LAYER M4 ;
        RECT  0 48.432 0.192 48.456 ;
    END
  END di[272]
  PIN di[273]
    DIRECTION INPUT ;
    USE SIGNAL ;
    PORT
      LAYER M4 ;
        RECT  0 48.576 0.192 48.6 ;
    END
  END di[273]
  PIN di[274]
    DIRECTION INPUT ;
    USE SIGNAL ;
    PORT
      LAYER M4 ;
        RECT  0 48.72 0.192 48.744 ;
    END
  END di[274]
  PIN di[275]
    DIRECTION INPUT ;
    USE SIGNAL ;
    PORT
      LAYER M4 ;
        RECT  0 48.912 0.192 48.936 ;
    END
  END di[275]
  PIN di[276]
    DIRECTION INPUT ;
    USE SIGNAL ;
    PORT
      LAYER M4 ;
        RECT  0 49.056 0.192 49.08 ;
    END
  END di[276]
  PIN di[277]
    DIRECTION INPUT ;
    USE SIGNAL ;
    PORT
      LAYER M4 ;
        RECT  0 49.248 0.192 49.272 ;
    END
  END di[277]
  PIN di[278]
    DIRECTION INPUT ;
    USE SIGNAL ;
    PORT
      LAYER M4 ;
        RECT  0 49.392 0.192 49.416 ;
    END
  END di[278]
  PIN di[279]
    DIRECTION INPUT ;
    USE SIGNAL ;
    PORT
      LAYER M4 ;
        RECT  0 49.536 0.192 49.56 ;
    END
  END di[279]
  PIN di[27]
    DIRECTION INPUT ;
    USE SIGNAL ;
    PORT
      LAYER M4 ;
        RECT  0 8.784 0.192 8.808 ;
    END
  END di[27]
  PIN di[280]
    DIRECTION INPUT ;
    USE SIGNAL ;
    PORT
      LAYER M4 ;
        RECT  0 49.728 0.192 49.752 ;
    END
  END di[280]
  PIN di[281]
    DIRECTION INPUT ;
    USE SIGNAL ;
    PORT
      LAYER M4 ;
        RECT  0 49.872 0.192 49.896 ;
    END
  END di[281]
  PIN di[282]
    DIRECTION INPUT ;
    USE SIGNAL ;
    PORT
      LAYER M4 ;
        RECT  0 50.016 0.192 50.04 ;
    END
  END di[282]
  PIN di[283]
    DIRECTION INPUT ;
    USE SIGNAL ;
    PORT
      LAYER M4 ;
        RECT  0 50.208 0.192 50.232 ;
    END
  END di[283]
  PIN di[284]
    DIRECTION INPUT ;
    USE SIGNAL ;
    PORT
      LAYER M4 ;
        RECT  0 50.352 0.192 50.376 ;
    END
  END di[284]
  PIN di[285]
    DIRECTION INPUT ;
    USE SIGNAL ;
    PORT
      LAYER M4 ;
        RECT  0 50.544 0.192 50.568 ;
    END
  END di[285]
  PIN di[286]
    DIRECTION INPUT ;
    USE SIGNAL ;
    PORT
      LAYER M4 ;
        RECT  0 50.688 0.192 50.712 ;
    END
  END di[286]
  PIN di[287]
    DIRECTION INPUT ;
    USE SIGNAL ;
    PORT
      LAYER M4 ;
        RECT  0 50.832 0.192 50.856 ;
    END
  END di[287]
  PIN di[288]
    DIRECTION INPUT ;
    USE SIGNAL ;
    PORT
      LAYER M4 ;
        RECT  0 51.024 0.192 51.048 ;
    END
  END di[288]
  PIN di[289]
    DIRECTION INPUT ;
    USE SIGNAL ;
    PORT
      LAYER M4 ;
        RECT  0 51.168 0.192 51.192 ;
    END
  END di[289]
  PIN di[28]
    DIRECTION INPUT ;
    USE SIGNAL ;
    PORT
      LAYER M4 ;
        RECT  0 8.928 0.192 8.952 ;
    END
  END di[28]
  PIN di[290]
    DIRECTION INPUT ;
    USE SIGNAL ;
    PORT
      LAYER M4 ;
        RECT  0 51.312 0.192 51.336 ;
    END
  END di[290]
  PIN di[291]
    DIRECTION INPUT ;
    USE SIGNAL ;
    PORT
      LAYER M4 ;
        RECT  0 51.504 0.192 51.528 ;
    END
  END di[291]
  PIN di[292]
    DIRECTION INPUT ;
    USE SIGNAL ;
    PORT
      LAYER M4 ;
        RECT  0 51.648 0.192 51.672 ;
    END
  END di[292]
  PIN di[293]
    DIRECTION INPUT ;
    USE SIGNAL ;
    PORT
      LAYER M4 ;
        RECT  0 51.84 0.192 51.864 ;
    END
  END di[293]
  PIN di[294]
    DIRECTION INPUT ;
    USE SIGNAL ;
    PORT
      LAYER M4 ;
        RECT  0 51.984 0.192 52.008 ;
    END
  END di[294]
  PIN di[295]
    DIRECTION INPUT ;
    USE SIGNAL ;
    PORT
      LAYER M4 ;
        RECT  0 52.128 0.192 52.152 ;
    END
  END di[295]
  PIN di[296]
    DIRECTION INPUT ;
    USE SIGNAL ;
    PORT
      LAYER M4 ;
        RECT  0 52.32 0.192 52.344 ;
    END
  END di[296]
  PIN di[297]
    DIRECTION INPUT ;
    USE SIGNAL ;
    PORT
      LAYER M4 ;
        RECT  0 52.464 0.192 52.488 ;
    END
  END di[297]
  PIN di[298]
    DIRECTION INPUT ;
    USE SIGNAL ;
    PORT
      LAYER M4 ;
        RECT  0 52.608 0.192 52.632 ;
    END
  END di[298]
  PIN di[299]
    DIRECTION INPUT ;
    USE SIGNAL ;
    PORT
      LAYER M4 ;
        RECT  0 52.8 0.192 52.824 ;
    END
  END di[299]
  PIN di[29]
    DIRECTION INPUT ;
    USE SIGNAL ;
    PORT
      LAYER M4 ;
        RECT  0 9.12 0.192 9.144 ;
    END
  END di[29]
  PIN di[2]
    DIRECTION INPUT ;
    USE SIGNAL ;
    PORT
      LAYER M4 ;
        RECT  0 4.752 0.192 4.776 ;
    END
  END di[2]
  PIN di[300]
    DIRECTION INPUT ;
    USE SIGNAL ;
    PORT
      LAYER M4 ;
        RECT  0 52.944 0.192 52.968 ;
    END
  END di[300]
  PIN di[301]
    DIRECTION INPUT ;
    USE SIGNAL ;
    PORT
      LAYER M4 ;
        RECT  0 53.088 0.192 53.112 ;
    END
  END di[301]
  PIN di[302]
    DIRECTION INPUT ;
    USE SIGNAL ;
    PORT
      LAYER M4 ;
        RECT  0 53.28 0.192 53.304 ;
    END
  END di[302]
  PIN di[303]
    DIRECTION INPUT ;
    USE SIGNAL ;
    PORT
      LAYER M4 ;
        RECT  0 53.424 0.192 53.448 ;
    END
  END di[303]
  PIN di[304]
    DIRECTION INPUT ;
    USE SIGNAL ;
    PORT
      LAYER M4 ;
        RECT  0 53.616 0.192 53.64 ;
    END
  END di[304]
  PIN di[305]
    DIRECTION INPUT ;
    USE SIGNAL ;
    PORT
      LAYER M4 ;
        RECT  0 53.76 0.192 53.784 ;
    END
  END di[305]
  PIN di[306]
    DIRECTION INPUT ;
    USE SIGNAL ;
    PORT
      LAYER M4 ;
        RECT  0 53.904 0.192 53.928 ;
    END
  END di[306]
  PIN di[307]
    DIRECTION INPUT ;
    USE SIGNAL ;
    PORT
      LAYER M4 ;
        RECT  0 54.096 0.192 54.12 ;
    END
  END di[307]
  PIN di[308]
    DIRECTION INPUT ;
    USE SIGNAL ;
    PORT
      LAYER M4 ;
        RECT  0 54.24 0.192 54.264 ;
    END
  END di[308]
  PIN di[309]
    DIRECTION INPUT ;
    USE SIGNAL ;
    PORT
      LAYER M4 ;
        RECT  0 54.384 0.192 54.408 ;
    END
  END di[309]
  PIN di[30]
    DIRECTION INPUT ;
    USE SIGNAL ;
    PORT
      LAYER M4 ;
        RECT  0 9.264 0.192 9.288 ;
    END
  END di[30]
  PIN di[310]
    DIRECTION INPUT ;
    USE SIGNAL ;
    PORT
      LAYER M4 ;
        RECT  0 54.576 0.192 54.6 ;
    END
  END di[310]
  PIN di[311]
    DIRECTION INPUT ;
    USE SIGNAL ;
    PORT
      LAYER M4 ;
        RECT  0 54.72 0.192 54.744 ;
    END
  END di[311]
  PIN di[312]
    DIRECTION INPUT ;
    USE SIGNAL ;
    PORT
      LAYER M4 ;
        RECT  0 54.912 0.192 54.936 ;
    END
  END di[312]
  PIN di[313]
    DIRECTION INPUT ;
    USE SIGNAL ;
    PORT
      LAYER M4 ;
        RECT  0 55.056 0.192 55.08 ;
    END
  END di[313]
  PIN di[314]
    DIRECTION INPUT ;
    USE SIGNAL ;
    PORT
      LAYER M4 ;
        RECT  0 55.2 0.192 55.224 ;
    END
  END di[314]
  PIN di[315]
    DIRECTION INPUT ;
    USE SIGNAL ;
    PORT
      LAYER M4 ;
        RECT  0 55.392 0.192 55.416 ;
    END
  END di[315]
  PIN di[316]
    DIRECTION INPUT ;
    USE SIGNAL ;
    PORT
      LAYER M4 ;
        RECT  0 55.536 0.192 55.56 ;
    END
  END di[316]
  PIN di[317]
    DIRECTION INPUT ;
    USE SIGNAL ;
    PORT
      LAYER M4 ;
        RECT  0 55.68 0.192 55.704 ;
    END
  END di[317]
  PIN di[318]
    DIRECTION INPUT ;
    USE SIGNAL ;
    PORT
      LAYER M4 ;
        RECT  0 55.872 0.192 55.896 ;
    END
  END di[318]
  PIN di[319]
    DIRECTION INPUT ;
    USE SIGNAL ;
    PORT
      LAYER M4 ;
        RECT  0 56.016 0.192 56.04 ;
    END
  END di[319]
  PIN di[31]
    DIRECTION INPUT ;
    USE SIGNAL ;
    PORT
      LAYER M4 ;
        RECT  0 9.408 0.192 9.432 ;
    END
  END di[31]
  PIN di[320]
    DIRECTION INPUT ;
    USE SIGNAL ;
    PORT
      LAYER M4 ;
        RECT  0 56.208 0.192 56.232 ;
    END
  END di[320]
  PIN di[321]
    DIRECTION INPUT ;
    USE SIGNAL ;
    PORT
      LAYER M4 ;
        RECT  0 56.352 0.192 56.376 ;
    END
  END di[321]
  PIN di[322]
    DIRECTION INPUT ;
    USE SIGNAL ;
    PORT
      LAYER M4 ;
        RECT  0 56.496 0.192 56.52 ;
    END
  END di[322]
  PIN di[323]
    DIRECTION INPUT ;
    USE SIGNAL ;
    PORT
      LAYER M4 ;
        RECT  0 56.688 0.192 56.712 ;
    END
  END di[323]
  PIN di[324]
    DIRECTION INPUT ;
    USE SIGNAL ;
    PORT
      LAYER M4 ;
        RECT  0 56.832 0.192 56.856 ;
    END
  END di[324]
  PIN di[325]
    DIRECTION INPUT ;
    USE SIGNAL ;
    PORT
      LAYER M4 ;
        RECT  0 56.976 0.192 57 ;
    END
  END di[325]
  PIN di[326]
    DIRECTION INPUT ;
    USE SIGNAL ;
    PORT
      LAYER M4 ;
        RECT  0 57.168 0.192 57.192 ;
    END
  END di[326]
  PIN di[327]
    DIRECTION INPUT ;
    USE SIGNAL ;
    PORT
      LAYER M4 ;
        RECT  0 57.312 0.192 57.336 ;
    END
  END di[327]
  PIN di[328]
    DIRECTION INPUT ;
    USE SIGNAL ;
    PORT
      LAYER M4 ;
        RECT  0 57.456 0.192 57.48 ;
    END
  END di[328]
  PIN di[329]
    DIRECTION INPUT ;
    USE SIGNAL ;
    PORT
      LAYER M4 ;
        RECT  0 57.648 0.192 57.672 ;
    END
  END di[329]
  PIN di[32]
    DIRECTION INPUT ;
    USE SIGNAL ;
    PORT
      LAYER M4 ;
        RECT  0 9.6 0.192 9.624 ;
    END
  END di[32]
  PIN di[330]
    DIRECTION INPUT ;
    USE SIGNAL ;
    PORT
      LAYER M4 ;
        RECT  0 57.792 0.192 57.816 ;
    END
  END di[330]
  PIN di[331]
    DIRECTION INPUT ;
    USE SIGNAL ;
    PORT
      LAYER M4 ;
        RECT  0 57.984 0.192 58.008 ;
    END
  END di[331]
  PIN di[332]
    DIRECTION INPUT ;
    USE SIGNAL ;
    PORT
      LAYER M4 ;
        RECT  0 58.128 0.192 58.152 ;
    END
  END di[332]
  PIN di[333]
    DIRECTION INPUT ;
    USE SIGNAL ;
    PORT
      LAYER M4 ;
        RECT  0 58.272 0.192 58.296 ;
    END
  END di[333]
  PIN di[334]
    DIRECTION INPUT ;
    USE SIGNAL ;
    PORT
      LAYER M4 ;
        RECT  0 58.464 0.192 58.488 ;
    END
  END di[334]
  PIN di[335]
    DIRECTION INPUT ;
    USE SIGNAL ;
    PORT
      LAYER M4 ;
        RECT  0 58.608 0.192 58.632 ;
    END
  END di[335]
  PIN di[336]
    DIRECTION INPUT ;
    USE SIGNAL ;
    PORT
      LAYER M4 ;
        RECT  0 58.752 0.192 58.776 ;
    END
  END di[336]
  PIN di[337]
    DIRECTION INPUT ;
    USE SIGNAL ;
    PORT
      LAYER M4 ;
        RECT  0 58.944 0.192 58.968 ;
    END
  END di[337]
  PIN di[338]
    DIRECTION INPUT ;
    USE SIGNAL ;
    PORT
      LAYER M4 ;
        RECT  0 59.088 0.192 59.112 ;
    END
  END di[338]
  PIN di[339]
    DIRECTION INPUT ;
    USE SIGNAL ;
    PORT
      LAYER M4 ;
        RECT  0 59.28 0.192 59.304 ;
    END
  END di[339]
  PIN di[33]
    DIRECTION INPUT ;
    USE SIGNAL ;
    PORT
      LAYER M4 ;
        RECT  0 9.744 0.192 9.768 ;
    END
  END di[33]
  PIN di[340]
    DIRECTION INPUT ;
    USE SIGNAL ;
    PORT
      LAYER M4 ;
        RECT  0 59.424 0.192 59.448 ;
    END
  END di[340]
  PIN di[341]
    DIRECTION INPUT ;
    USE SIGNAL ;
    PORT
      LAYER M4 ;
        RECT  0 59.568 0.192 59.592 ;
    END
  END di[341]
  PIN di[342]
    DIRECTION INPUT ;
    USE SIGNAL ;
    PORT
      LAYER M4 ;
        RECT  0 59.76 0.192 59.784 ;
    END
  END di[342]
  PIN di[343]
    DIRECTION INPUT ;
    USE SIGNAL ;
    PORT
      LAYER M4 ;
        RECT  0 59.904 0.192 59.928 ;
    END
  END di[343]
  PIN di[344]
    DIRECTION INPUT ;
    USE SIGNAL ;
    PORT
      LAYER M4 ;
        RECT  0 60.048 0.192 60.072 ;
    END
  END di[344]
  PIN di[345]
    DIRECTION INPUT ;
    USE SIGNAL ;
    PORT
      LAYER M4 ;
        RECT  0 60.24 0.192 60.264 ;
    END
  END di[345]
  PIN di[346]
    DIRECTION INPUT ;
    USE SIGNAL ;
    PORT
      LAYER M4 ;
        RECT  0 60.384 0.192 60.408 ;
    END
  END di[346]
  PIN di[347]
    DIRECTION INPUT ;
    USE SIGNAL ;
    PORT
      LAYER M4 ;
        RECT  0 60.576 0.192 60.6 ;
    END
  END di[347]
  PIN di[348]
    DIRECTION INPUT ;
    USE SIGNAL ;
    PORT
      LAYER M4 ;
        RECT  0 60.72 0.192 60.744 ;
    END
  END di[348]
  PIN di[349]
    DIRECTION INPUT ;
    USE SIGNAL ;
    PORT
      LAYER M4 ;
        RECT  0 60.864 0.192 60.888 ;
    END
  END di[349]
  PIN di[34]
    DIRECTION INPUT ;
    USE SIGNAL ;
    PORT
      LAYER M4 ;
        RECT  0 9.936 0.192 9.96 ;
    END
  END di[34]
  PIN di[350]
    DIRECTION INPUT ;
    USE SIGNAL ;
    PORT
      LAYER M4 ;
        RECT  0 61.056 0.192 61.08 ;
    END
  END di[350]
  PIN di[351]
    DIRECTION INPUT ;
    USE SIGNAL ;
    PORT
      LAYER M4 ;
        RECT  0 61.2 0.192 61.224 ;
    END
  END di[351]
  PIN di[352]
    DIRECTION INPUT ;
    USE SIGNAL ;
    PORT
      LAYER M4 ;
        RECT  0 61.344 0.192 61.368 ;
    END
  END di[352]
  PIN di[353]
    DIRECTION INPUT ;
    USE SIGNAL ;
    PORT
      LAYER M4 ;
        RECT  0 61.536 0.192 61.56 ;
    END
  END di[353]
  PIN di[354]
    DIRECTION INPUT ;
    USE SIGNAL ;
    PORT
      LAYER M4 ;
        RECT  0 61.68 0.192 61.704 ;
    END
  END di[354]
  PIN di[355]
    DIRECTION INPUT ;
    USE SIGNAL ;
    PORT
      LAYER M4 ;
        RECT  0 61.824 0.192 61.848 ;
    END
  END di[355]
  PIN di[356]
    DIRECTION INPUT ;
    USE SIGNAL ;
    PORT
      LAYER M4 ;
        RECT  0 62.016 0.192 62.04 ;
    END
  END di[356]
  PIN di[357]
    DIRECTION INPUT ;
    USE SIGNAL ;
    PORT
      LAYER M4 ;
        RECT  0 62.16 0.192 62.184 ;
    END
  END di[357]
  PIN di[358]
    DIRECTION INPUT ;
    USE SIGNAL ;
    PORT
      LAYER M4 ;
        RECT  0 62.352 0.192 62.376 ;
    END
  END di[358]
  PIN di[359]
    DIRECTION INPUT ;
    USE SIGNAL ;
    PORT
      LAYER M4 ;
        RECT  0 62.496 0.192 62.52 ;
    END
  END di[359]
  PIN di[35]
    DIRECTION INPUT ;
    USE SIGNAL ;
    PORT
      LAYER M4 ;
        RECT  0 10.08 0.192 10.104 ;
    END
  END di[35]
  PIN di[360]
    DIRECTION INPUT ;
    USE SIGNAL ;
    PORT
      LAYER M4 ;
        RECT  0 62.64 0.192 62.664 ;
    END
  END di[360]
  PIN di[361]
    DIRECTION INPUT ;
    USE SIGNAL ;
    PORT
      LAYER M4 ;
        RECT  0 62.832 0.192 62.856 ;
    END
  END di[361]
  PIN di[362]
    DIRECTION INPUT ;
    USE SIGNAL ;
    PORT
      LAYER M4 ;
        RECT  0 62.976 0.192 63 ;
    END
  END di[362]
  PIN di[363]
    DIRECTION INPUT ;
    USE SIGNAL ;
    PORT
      LAYER M4 ;
        RECT  0 63.12 0.192 63.144 ;
    END
  END di[363]
  PIN di[364]
    DIRECTION INPUT ;
    USE SIGNAL ;
    PORT
      LAYER M4 ;
        RECT  0 63.312 0.192 63.336 ;
    END
  END di[364]
  PIN di[365]
    DIRECTION INPUT ;
    USE SIGNAL ;
    PORT
      LAYER M4 ;
        RECT  0 63.456 0.192 63.48 ;
    END
  END di[365]
  PIN di[366]
    DIRECTION INPUT ;
    USE SIGNAL ;
    PORT
      LAYER M4 ;
        RECT  0 63.648 0.192 63.672 ;
    END
  END di[366]
  PIN di[367]
    DIRECTION INPUT ;
    USE SIGNAL ;
    PORT
      LAYER M4 ;
        RECT  0 63.792 0.192 63.816 ;
    END
  END di[367]
  PIN di[368]
    DIRECTION INPUT ;
    USE SIGNAL ;
    PORT
      LAYER M4 ;
        RECT  0 63.936 0.192 63.96 ;
    END
  END di[368]
  PIN di[369]
    DIRECTION INPUT ;
    USE SIGNAL ;
    PORT
      LAYER M4 ;
        RECT  0 64.128 0.192 64.152 ;
    END
  END di[369]
  PIN di[36]
    DIRECTION INPUT ;
    USE SIGNAL ;
    PORT
      LAYER M4 ;
        RECT  0 10.224 0.192 10.248 ;
    END
  END di[36]
  PIN di[370]
    DIRECTION INPUT ;
    USE SIGNAL ;
    PORT
      LAYER M4 ;
        RECT  0 64.272 0.192 64.296 ;
    END
  END di[370]
  PIN di[371]
    DIRECTION INPUT ;
    USE SIGNAL ;
    PORT
      LAYER M4 ;
        RECT  0 64.416 0.192 64.44 ;
    END
  END di[371]
  PIN di[372]
    DIRECTION INPUT ;
    USE SIGNAL ;
    PORT
      LAYER M4 ;
        RECT  0 64.608 0.192 64.632 ;
    END
  END di[372]
  PIN di[373]
    DIRECTION INPUT ;
    USE SIGNAL ;
    PORT
      LAYER M4 ;
        RECT  0 64.752 0.192 64.776 ;
    END
  END di[373]
  PIN di[374]
    DIRECTION INPUT ;
    USE SIGNAL ;
    PORT
      LAYER M4 ;
        RECT  0 64.944 0.192 64.968 ;
    END
  END di[374]
  PIN di[375]
    DIRECTION INPUT ;
    USE SIGNAL ;
    PORT
      LAYER M4 ;
        RECT  0 65.088 0.192 65.112 ;
    END
  END di[375]
  PIN di[376]
    DIRECTION INPUT ;
    USE SIGNAL ;
    PORT
      LAYER M4 ;
        RECT  0 65.232 0.192 65.256 ;
    END
  END di[376]
  PIN di[377]
    DIRECTION INPUT ;
    USE SIGNAL ;
    PORT
      LAYER M4 ;
        RECT  0 65.424 0.192 65.448 ;
    END
  END di[377]
  PIN di[378]
    DIRECTION INPUT ;
    USE SIGNAL ;
    PORT
      LAYER M4 ;
        RECT  0 65.568 0.192 65.592 ;
    END
  END di[378]
  PIN di[379]
    DIRECTION INPUT ;
    USE SIGNAL ;
    PORT
      LAYER M4 ;
        RECT  0 65.712 0.192 65.736 ;
    END
  END di[379]
  PIN di[37]
    DIRECTION INPUT ;
    USE SIGNAL ;
    PORT
      LAYER M4 ;
        RECT  0 10.416 0.192 10.44 ;
    END
  END di[37]
  PIN di[380]
    DIRECTION INPUT ;
    USE SIGNAL ;
    PORT
      LAYER M4 ;
        RECT  0 65.904 0.192 65.928 ;
    END
  END di[380]
  PIN di[381]
    DIRECTION INPUT ;
    USE SIGNAL ;
    PORT
      LAYER M4 ;
        RECT  0 66.048 0.192 66.072 ;
    END
  END di[381]
  PIN di[382]
    DIRECTION INPUT ;
    USE SIGNAL ;
    PORT
      LAYER M4 ;
        RECT  0 66.192 0.192 66.216 ;
    END
  END di[382]
  PIN di[383]
    DIRECTION INPUT ;
    USE SIGNAL ;
    PORT
      LAYER M4 ;
        RECT  0 66.384 0.192 66.408 ;
    END
  END di[383]
  PIN di[384]
    DIRECTION INPUT ;
    USE SIGNAL ;
    PORT
      LAYER M4 ;
        RECT  0 66.528 0.192 66.552 ;
    END
  END di[384]
  PIN di[385]
    DIRECTION INPUT ;
    USE SIGNAL ;
    PORT
      LAYER M4 ;
        RECT  0 66.72 0.192 66.744 ;
    END
  END di[385]
  PIN di[386]
    DIRECTION INPUT ;
    USE SIGNAL ;
    PORT
      LAYER M4 ;
        RECT  0 66.864 0.192 66.888 ;
    END
  END di[386]
  PIN di[387]
    DIRECTION INPUT ;
    USE SIGNAL ;
    PORT
      LAYER M4 ;
        RECT  0 67.008 0.192 67.032 ;
    END
  END di[387]
  PIN di[388]
    DIRECTION INPUT ;
    USE SIGNAL ;
    PORT
      LAYER M4 ;
        RECT  0 67.2 0.192 67.224 ;
    END
  END di[388]
  PIN di[389]
    DIRECTION INPUT ;
    USE SIGNAL ;
    PORT
      LAYER M4 ;
        RECT  0 67.344 0.192 67.368 ;
    END
  END di[389]
  PIN di[38]
    DIRECTION INPUT ;
    USE SIGNAL ;
    PORT
      LAYER M4 ;
        RECT  0 10.56 0.192 10.584 ;
    END
  END di[38]
  PIN di[390]
    DIRECTION INPUT ;
    USE SIGNAL ;
    PORT
      LAYER M4 ;
        RECT  0 67.488 0.192 67.512 ;
    END
  END di[390]
  PIN di[391]
    DIRECTION INPUT ;
    USE SIGNAL ;
    PORT
      LAYER M4 ;
        RECT  0 67.68 0.192 67.704 ;
    END
  END di[391]
  PIN di[392]
    DIRECTION INPUT ;
    USE SIGNAL ;
    PORT
      LAYER M4 ;
        RECT  0 67.824 0.192 67.848 ;
    END
  END di[392]
  PIN di[393]
    DIRECTION INPUT ;
    USE SIGNAL ;
    PORT
      LAYER M4 ;
        RECT  0 68.016 0.192 68.04 ;
    END
  END di[393]
  PIN di[394]
    DIRECTION INPUT ;
    USE SIGNAL ;
    PORT
      LAYER M4 ;
        RECT  0 68.16 0.192 68.184 ;
    END
  END di[394]
  PIN di[395]
    DIRECTION INPUT ;
    USE SIGNAL ;
    PORT
      LAYER M4 ;
        RECT  0 68.304 0.192 68.328 ;
    END
  END di[395]
  PIN di[396]
    DIRECTION INPUT ;
    USE SIGNAL ;
    PORT
      LAYER M4 ;
        RECT  0 68.496 0.192 68.52 ;
    END
  END di[396]
  PIN di[397]
    DIRECTION INPUT ;
    USE SIGNAL ;
    PORT
      LAYER M4 ;
        RECT  0 68.64 0.192 68.664 ;
    END
  END di[397]
  PIN di[398]
    DIRECTION INPUT ;
    USE SIGNAL ;
    PORT
      LAYER M4 ;
        RECT  0 68.784 0.192 68.808 ;
    END
  END di[398]
  PIN di[399]
    DIRECTION INPUT ;
    USE SIGNAL ;
    PORT
      LAYER M4 ;
        RECT  0 68.976 0.192 69 ;
    END
  END di[399]
  PIN di[39]
    DIRECTION INPUT ;
    USE SIGNAL ;
    PORT
      LAYER M4 ;
        RECT  0 10.704 0.192 10.728 ;
    END
  END di[39]
  PIN di[3]
    DIRECTION INPUT ;
    USE SIGNAL ;
    PORT
      LAYER M4 ;
        RECT  0 4.896 0.192 4.92 ;
    END
  END di[3]
  PIN di[400]
    DIRECTION INPUT ;
    USE SIGNAL ;
    PORT
      LAYER M4 ;
        RECT  0 69.12 0.192 69.144 ;
    END
  END di[400]
  PIN di[401]
    DIRECTION INPUT ;
    USE SIGNAL ;
    PORT
      LAYER M4 ;
        RECT  0 69.312 0.192 69.336 ;
    END
  END di[401]
  PIN di[402]
    DIRECTION INPUT ;
    USE SIGNAL ;
    PORT
      LAYER M4 ;
        RECT  0 69.456 0.192 69.48 ;
    END
  END di[402]
  PIN di[403]
    DIRECTION INPUT ;
    USE SIGNAL ;
    PORT
      LAYER M4 ;
        RECT  0 69.6 0.192 69.624 ;
    END
  END di[403]
  PIN di[404]
    DIRECTION INPUT ;
    USE SIGNAL ;
    PORT
      LAYER M4 ;
        RECT  0 69.792 0.192 69.816 ;
    END
  END di[404]
  PIN di[405]
    DIRECTION INPUT ;
    USE SIGNAL ;
    PORT
      LAYER M4 ;
        RECT  0 69.936 0.192 69.96 ;
    END
  END di[405]
  PIN di[406]
    DIRECTION INPUT ;
    USE SIGNAL ;
    PORT
      LAYER M4 ;
        RECT  0 70.08 0.192 70.104 ;
    END
  END di[406]
  PIN di[407]
    DIRECTION INPUT ;
    USE SIGNAL ;
    PORT
      LAYER M4 ;
        RECT  0 70.272 0.192 70.296 ;
    END
  END di[407]
  PIN di[408]
    DIRECTION INPUT ;
    USE SIGNAL ;
    PORT
      LAYER M4 ;
        RECT  0 70.416 0.192 70.44 ;
    END
  END di[408]
  PIN di[409]
    DIRECTION INPUT ;
    USE SIGNAL ;
    PORT
      LAYER M4 ;
        RECT  0 70.56 0.192 70.584 ;
    END
  END di[409]
  PIN di[40]
    DIRECTION INPUT ;
    USE SIGNAL ;
    PORT
      LAYER M4 ;
        RECT  0 10.896 0.192 10.92 ;
    END
  END di[40]
  PIN di[410]
    DIRECTION INPUT ;
    USE SIGNAL ;
    PORT
      LAYER M4 ;
        RECT  0 70.752 0.192 70.776 ;
    END
  END di[410]
  PIN di[411]
    DIRECTION INPUT ;
    USE SIGNAL ;
    PORT
      LAYER M4 ;
        RECT  0 70.896 0.192 70.92 ;
    END
  END di[411]
  PIN di[412]
    DIRECTION INPUT ;
    USE SIGNAL ;
    PORT
      LAYER M4 ;
        RECT  0 71.088 0.192 71.112 ;
    END
  END di[412]
  PIN di[413]
    DIRECTION INPUT ;
    USE SIGNAL ;
    PORT
      LAYER M4 ;
        RECT  0 71.232 0.192 71.256 ;
    END
  END di[413]
  PIN di[414]
    DIRECTION INPUT ;
    USE SIGNAL ;
    PORT
      LAYER M4 ;
        RECT  0 71.376 0.192 71.4 ;
    END
  END di[414]
  PIN di[415]
    DIRECTION INPUT ;
    USE SIGNAL ;
    PORT
      LAYER M4 ;
        RECT  0 71.568 0.192 71.592 ;
    END
  END di[415]
  PIN di[416]
    DIRECTION INPUT ;
    USE SIGNAL ;
    PORT
      LAYER M4 ;
        RECT  0 71.712 0.192 71.736 ;
    END
  END di[416]
  PIN di[417]
    DIRECTION INPUT ;
    USE SIGNAL ;
    PORT
      LAYER M4 ;
        RECT  0 71.856 0.192 71.88 ;
    END
  END di[417]
  PIN di[418]
    DIRECTION INPUT ;
    USE SIGNAL ;
    PORT
      LAYER M4 ;
        RECT  0 72.048 0.192 72.072 ;
    END
  END di[418]
  PIN di[419]
    DIRECTION INPUT ;
    USE SIGNAL ;
    PORT
      LAYER M4 ;
        RECT  0 72.192 0.192 72.216 ;
    END
  END di[419]
  PIN di[41]
    DIRECTION INPUT ;
    USE SIGNAL ;
    PORT
      LAYER M4 ;
        RECT  0 11.04 0.192 11.064 ;
    END
  END di[41]
  PIN di[420]
    DIRECTION INPUT ;
    USE SIGNAL ;
    PORT
      LAYER M4 ;
        RECT  0 72.384 0.192 72.408 ;
    END
  END di[420]
  PIN di[421]
    DIRECTION INPUT ;
    USE SIGNAL ;
    PORT
      LAYER M4 ;
        RECT  0 72.528 0.192 72.552 ;
    END
  END di[421]
  PIN di[422]
    DIRECTION INPUT ;
    USE SIGNAL ;
    PORT
      LAYER M4 ;
        RECT  0 72.672 0.192 72.696 ;
    END
  END di[422]
  PIN di[423]
    DIRECTION INPUT ;
    USE SIGNAL ;
    PORT
      LAYER M4 ;
        RECT  0 72.864 0.192 72.888 ;
    END
  END di[423]
  PIN di[424]
    DIRECTION INPUT ;
    USE SIGNAL ;
    PORT
      LAYER M4 ;
        RECT  0 73.008 0.192 73.032 ;
    END
  END di[424]
  PIN di[425]
    DIRECTION INPUT ;
    USE SIGNAL ;
    PORT
      LAYER M4 ;
        RECT  0 73.152 0.192 73.176 ;
    END
  END di[425]
  PIN di[426]
    DIRECTION INPUT ;
    USE SIGNAL ;
    PORT
      LAYER M4 ;
        RECT  0 73.344 0.192 73.368 ;
    END
  END di[426]
  PIN di[427]
    DIRECTION INPUT ;
    USE SIGNAL ;
    PORT
      LAYER M4 ;
        RECT  0 73.488 0.192 73.512 ;
    END
  END di[427]
  PIN di[428]
    DIRECTION INPUT ;
    USE SIGNAL ;
    PORT
      LAYER M4 ;
        RECT  0 73.68 0.192 73.704 ;
    END
  END di[428]
  PIN di[429]
    DIRECTION INPUT ;
    USE SIGNAL ;
    PORT
      LAYER M4 ;
        RECT  0 73.824 0.192 73.848 ;
    END
  END di[429]
  PIN di[42]
    DIRECTION INPUT ;
    USE SIGNAL ;
    PORT
      LAYER M4 ;
        RECT  0 11.184 0.192 11.208 ;
    END
  END di[42]
  PIN di[430]
    DIRECTION INPUT ;
    USE SIGNAL ;
    PORT
      LAYER M4 ;
        RECT  0 73.968 0.192 73.992 ;
    END
  END di[430]
  PIN di[431]
    DIRECTION INPUT ;
    USE SIGNAL ;
    PORT
      LAYER M4 ;
        RECT  0 74.16 0.192 74.184 ;
    END
  END di[431]
  PIN di[432]
    DIRECTION INPUT ;
    USE SIGNAL ;
    PORT
      LAYER M4 ;
        RECT  0 74.304 0.192 74.328 ;
    END
  END di[432]
  PIN di[433]
    DIRECTION INPUT ;
    USE SIGNAL ;
    PORT
      LAYER M4 ;
        RECT  0 74.448 0.192 74.472 ;
    END
  END di[433]
  PIN di[434]
    DIRECTION INPUT ;
    USE SIGNAL ;
    PORT
      LAYER M4 ;
        RECT  0 74.64 0.192 74.664 ;
    END
  END di[434]
  PIN di[435]
    DIRECTION INPUT ;
    USE SIGNAL ;
    PORT
      LAYER M4 ;
        RECT  0 74.784 0.192 74.808 ;
    END
  END di[435]
  PIN di[436]
    DIRECTION INPUT ;
    USE SIGNAL ;
    PORT
      LAYER M4 ;
        RECT  0 74.976 0.192 75 ;
    END
  END di[436]
  PIN di[437]
    DIRECTION INPUT ;
    USE SIGNAL ;
    PORT
      LAYER M4 ;
        RECT  0 75.12 0.192 75.144 ;
    END
  END di[437]
  PIN di[438]
    DIRECTION INPUT ;
    USE SIGNAL ;
    PORT
      LAYER M4 ;
        RECT  0 75.264 0.192 75.288 ;
    END
  END di[438]
  PIN di[439]
    DIRECTION INPUT ;
    USE SIGNAL ;
    PORT
      LAYER M4 ;
        RECT  0 75.456 0.192 75.48 ;
    END
  END di[439]
  PIN di[43]
    DIRECTION INPUT ;
    USE SIGNAL ;
    PORT
      LAYER M4 ;
        RECT  0 11.376 0.192 11.4 ;
    END
  END di[43]
  PIN di[440]
    DIRECTION INPUT ;
    USE SIGNAL ;
    PORT
      LAYER M4 ;
        RECT  0 75.6 0.192 75.624 ;
    END
  END di[440]
  PIN di[441]
    DIRECTION INPUT ;
    USE SIGNAL ;
    PORT
      LAYER M4 ;
        RECT  0 75.744 0.192 75.768 ;
    END
  END di[441]
  PIN di[442]
    DIRECTION INPUT ;
    USE SIGNAL ;
    PORT
      LAYER M4 ;
        RECT  0 75.936 0.192 75.96 ;
    END
  END di[442]
  PIN di[443]
    DIRECTION INPUT ;
    USE SIGNAL ;
    PORT
      LAYER M4 ;
        RECT  0 76.08 0.192 76.104 ;
    END
  END di[443]
  PIN di[444]
    DIRECTION INPUT ;
    USE SIGNAL ;
    PORT
      LAYER M4 ;
        RECT  0 76.224 0.192 76.248 ;
    END
  END di[444]
  PIN di[445]
    DIRECTION INPUT ;
    USE SIGNAL ;
    PORT
      LAYER M4 ;
        RECT  0 76.416 0.192 76.44 ;
    END
  END di[445]
  PIN di[446]
    DIRECTION INPUT ;
    USE SIGNAL ;
    PORT
      LAYER M4 ;
        RECT  0 76.56 0.192 76.584 ;
    END
  END di[446]
  PIN di[447]
    DIRECTION INPUT ;
    USE SIGNAL ;
    PORT
      LAYER M4 ;
        RECT  0 76.752 0.192 76.776 ;
    END
  END di[447]
  PIN di[448]
    DIRECTION INPUT ;
    USE SIGNAL ;
    PORT
      LAYER M4 ;
        RECT  0 76.896 0.192 76.92 ;
    END
  END di[448]
  PIN di[449]
    DIRECTION INPUT ;
    USE SIGNAL ;
    PORT
      LAYER M4 ;
        RECT  0 77.04 0.192 77.064 ;
    END
  END di[449]
  PIN di[44]
    DIRECTION INPUT ;
    USE SIGNAL ;
    PORT
      LAYER M4 ;
        RECT  0 11.52 0.192 11.544 ;
    END
  END di[44]
  PIN di[450]
    DIRECTION INPUT ;
    USE SIGNAL ;
    PORT
      LAYER M4 ;
        RECT  0 77.232 0.192 77.256 ;
    END
  END di[450]
  PIN di[451]
    DIRECTION INPUT ;
    USE SIGNAL ;
    PORT
      LAYER M4 ;
        RECT  0 77.376 0.192 77.4 ;
    END
  END di[451]
  PIN di[452]
    DIRECTION INPUT ;
    USE SIGNAL ;
    PORT
      LAYER M4 ;
        RECT  0 77.52 0.192 77.544 ;
    END
  END di[452]
  PIN di[453]
    DIRECTION INPUT ;
    USE SIGNAL ;
    PORT
      LAYER M4 ;
        RECT  0 77.712 0.192 77.736 ;
    END
  END di[453]
  PIN di[454]
    DIRECTION INPUT ;
    USE SIGNAL ;
    PORT
      LAYER M4 ;
        RECT  0 77.856 0.192 77.88 ;
    END
  END di[454]
  PIN di[455]
    DIRECTION INPUT ;
    USE SIGNAL ;
    PORT
      LAYER M4 ;
        RECT  0 78.048 0.192 78.072 ;
    END
  END di[455]
  PIN di[456]
    DIRECTION INPUT ;
    USE SIGNAL ;
    PORT
      LAYER M4 ;
        RECT  0 78.192 0.192 78.216 ;
    END
  END di[456]
  PIN di[457]
    DIRECTION INPUT ;
    USE SIGNAL ;
    PORT
      LAYER M4 ;
        RECT  0 78.336 0.192 78.36 ;
    END
  END di[457]
  PIN di[458]
    DIRECTION INPUT ;
    USE SIGNAL ;
    PORT
      LAYER M4 ;
        RECT  0 78.528 0.192 78.552 ;
    END
  END di[458]
  PIN di[459]
    DIRECTION INPUT ;
    USE SIGNAL ;
    PORT
      LAYER M4 ;
        RECT  0 78.672 0.192 78.696 ;
    END
  END di[459]
  PIN di[45]
    DIRECTION INPUT ;
    USE SIGNAL ;
    PORT
      LAYER M4 ;
        RECT  0 11.712 0.192 11.736 ;
    END
  END di[45]
  PIN di[460]
    DIRECTION INPUT ;
    USE SIGNAL ;
    PORT
      LAYER M4 ;
        RECT  0 78.816 0.192 78.84 ;
    END
  END di[460]
  PIN di[461]
    DIRECTION INPUT ;
    USE SIGNAL ;
    PORT
      LAYER M4 ;
        RECT  0 79.008 0.192 79.032 ;
    END
  END di[461]
  PIN di[462]
    DIRECTION INPUT ;
    USE SIGNAL ;
    PORT
      LAYER M4 ;
        RECT  0 79.152 0.192 79.176 ;
    END
  END di[462]
  PIN di[463]
    DIRECTION INPUT ;
    USE SIGNAL ;
    PORT
      LAYER M4 ;
        RECT  0 79.344 0.192 79.368 ;
    END
  END di[463]
  PIN di[464]
    DIRECTION INPUT ;
    USE SIGNAL ;
    PORT
      LAYER M4 ;
        RECT  0 79.488 0.192 79.512 ;
    END
  END di[464]
  PIN di[465]
    DIRECTION INPUT ;
    USE SIGNAL ;
    PORT
      LAYER M4 ;
        RECT  0 79.632 0.192 79.656 ;
    END
  END di[465]
  PIN di[466]
    DIRECTION INPUT ;
    USE SIGNAL ;
    PORT
      LAYER M4 ;
        RECT  0 79.824 0.192 79.848 ;
    END
  END di[466]
  PIN di[467]
    DIRECTION INPUT ;
    USE SIGNAL ;
    PORT
      LAYER M4 ;
        RECT  0 79.968 0.192 79.992 ;
    END
  END di[467]
  PIN di[468]
    DIRECTION INPUT ;
    USE SIGNAL ;
    PORT
      LAYER M4 ;
        RECT  0 80.112 0.192 80.136 ;
    END
  END di[468]
  PIN di[469]
    DIRECTION INPUT ;
    USE SIGNAL ;
    PORT
      LAYER M4 ;
        RECT  0 80.304 0.192 80.328 ;
    END
  END di[469]
  PIN di[46]
    DIRECTION INPUT ;
    USE SIGNAL ;
    PORT
      LAYER M4 ;
        RECT  0 11.856 0.192 11.88 ;
    END
  END di[46]
  PIN di[470]
    DIRECTION INPUT ;
    USE SIGNAL ;
    PORT
      LAYER M4 ;
        RECT  0 80.448 0.192 80.472 ;
    END
  END di[470]
  PIN di[471]
    DIRECTION INPUT ;
    USE SIGNAL ;
    PORT
      LAYER M4 ;
        RECT  0 80.592 0.192 80.616 ;
    END
  END di[471]
  PIN di[472]
    DIRECTION INPUT ;
    USE SIGNAL ;
    PORT
      LAYER M4 ;
        RECT  0 80.784 0.192 80.808 ;
    END
  END di[472]
  PIN di[473]
    DIRECTION INPUT ;
    USE SIGNAL ;
    PORT
      LAYER M4 ;
        RECT  0 80.928 0.192 80.952 ;
    END
  END di[473]
  PIN di[474]
    DIRECTION INPUT ;
    USE SIGNAL ;
    PORT
      LAYER M4 ;
        RECT  0 81.12 0.192 81.144 ;
    END
  END di[474]
  PIN di[475]
    DIRECTION INPUT ;
    USE SIGNAL ;
    PORT
      LAYER M4 ;
        RECT  0 81.264 0.192 81.288 ;
    END
  END di[475]
  PIN di[476]
    DIRECTION INPUT ;
    USE SIGNAL ;
    PORT
      LAYER M4 ;
        RECT  0 81.408 0.192 81.432 ;
    END
  END di[476]
  PIN di[477]
    DIRECTION INPUT ;
    USE SIGNAL ;
    PORT
      LAYER M4 ;
        RECT  0 81.6 0.192 81.624 ;
    END
  END di[477]
  PIN di[478]
    DIRECTION INPUT ;
    USE SIGNAL ;
    PORT
      LAYER M4 ;
        RECT  0 81.744 0.192 81.768 ;
    END
  END di[478]
  PIN di[479]
    DIRECTION INPUT ;
    USE SIGNAL ;
    PORT
      LAYER M4 ;
        RECT  0 81.888 0.192 81.912 ;
    END
  END di[479]
  PIN di[47]
    DIRECTION INPUT ;
    USE SIGNAL ;
    PORT
      LAYER M4 ;
        RECT  0 12 0.192 12.024 ;
    END
  END di[47]
  PIN di[480]
    DIRECTION INPUT ;
    USE SIGNAL ;
    PORT
      LAYER M4 ;
        RECT  0 82.08 0.192 82.104 ;
    END
  END di[480]
  PIN di[481]
    DIRECTION INPUT ;
    USE SIGNAL ;
    PORT
      LAYER M4 ;
        RECT  0 82.224 0.192 82.248 ;
    END
  END di[481]
  PIN di[482]
    DIRECTION INPUT ;
    USE SIGNAL ;
    PORT
      LAYER M4 ;
        RECT  0 82.416 0.192 82.44 ;
    END
  END di[482]
  PIN di[483]
    DIRECTION INPUT ;
    USE SIGNAL ;
    PORT
      LAYER M4 ;
        RECT  0 82.56 0.192 82.584 ;
    END
  END di[483]
  PIN di[484]
    DIRECTION INPUT ;
    USE SIGNAL ;
    PORT
      LAYER M4 ;
        RECT  0 82.704 0.192 82.728 ;
    END
  END di[484]
  PIN di[485]
    DIRECTION INPUT ;
    USE SIGNAL ;
    PORT
      LAYER M4 ;
        RECT  0 82.896 0.192 82.92 ;
    END
  END di[485]
  PIN di[486]
    DIRECTION INPUT ;
    USE SIGNAL ;
    PORT
      LAYER M4 ;
        RECT  0 83.04 0.192 83.064 ;
    END
  END di[486]
  PIN di[487]
    DIRECTION INPUT ;
    USE SIGNAL ;
    PORT
      LAYER M4 ;
        RECT  0 83.184 0.192 83.208 ;
    END
  END di[487]
  PIN di[488]
    DIRECTION INPUT ;
    USE SIGNAL ;
    PORT
      LAYER M4 ;
        RECT  0 83.376 0.192 83.4 ;
    END
  END di[488]
  PIN di[489]
    DIRECTION INPUT ;
    USE SIGNAL ;
    PORT
      LAYER M4 ;
        RECT  0 83.52 0.192 83.544 ;
    END
  END di[489]
  PIN di[48]
    DIRECTION INPUT ;
    USE SIGNAL ;
    PORT
      LAYER M4 ;
        RECT  0 12.192 0.192 12.216 ;
    END
  END di[48]
  PIN di[490]
    DIRECTION INPUT ;
    USE SIGNAL ;
    PORT
      LAYER M4 ;
        RECT  0 83.712 0.192 83.736 ;
    END
  END di[490]
  PIN di[491]
    DIRECTION INPUT ;
    USE SIGNAL ;
    PORT
      LAYER M4 ;
        RECT  0 83.856 0.192 83.88 ;
    END
  END di[491]
  PIN di[492]
    DIRECTION INPUT ;
    USE SIGNAL ;
    PORT
      LAYER M4 ;
        RECT  0 84 0.192 84.024 ;
    END
  END di[492]
  PIN di[493]
    DIRECTION INPUT ;
    USE SIGNAL ;
    PORT
      LAYER M4 ;
        RECT  0 84.192 0.192 84.216 ;
    END
  END di[493]
  PIN di[494]
    DIRECTION INPUT ;
    USE SIGNAL ;
    PORT
      LAYER M4 ;
        RECT  0 84.336 0.192 84.36 ;
    END
  END di[494]
  PIN di[495]
    DIRECTION INPUT ;
    USE SIGNAL ;
    PORT
      LAYER M4 ;
        RECT  0 84.48 0.192 84.504 ;
    END
  END di[495]
  PIN di[496]
    DIRECTION INPUT ;
    USE SIGNAL ;
    PORT
      LAYER M4 ;
        RECT  0 84.672 0.192 84.696 ;
    END
  END di[496]
  PIN di[497]
    DIRECTION INPUT ;
    USE SIGNAL ;
    PORT
      LAYER M4 ;
        RECT  0 84.816 0.192 84.84 ;
    END
  END di[497]
  PIN di[498]
    DIRECTION INPUT ;
    USE SIGNAL ;
    PORT
      LAYER M4 ;
        RECT  0 84.96 0.192 84.984 ;
    END
  END di[498]
  PIN di[499]
    DIRECTION INPUT ;
    USE SIGNAL ;
    PORT
      LAYER M4 ;
        RECT  0 85.152 0.192 85.176 ;
    END
  END di[499]
  PIN di[49]
    DIRECTION INPUT ;
    USE SIGNAL ;
    PORT
      LAYER M4 ;
        RECT  0 12.336 0.192 12.36 ;
    END
  END di[49]
  PIN di[4]
    DIRECTION INPUT ;
    USE SIGNAL ;
    PORT
      LAYER M4 ;
        RECT  0 5.04 0.192 5.064 ;
    END
  END di[4]
  PIN di[500]
    DIRECTION INPUT ;
    USE SIGNAL ;
    PORT
      LAYER M4 ;
        RECT  0 85.296 0.192 85.32 ;
    END
  END di[500]
  PIN di[501]
    DIRECTION INPUT ;
    USE SIGNAL ;
    PORT
      LAYER M4 ;
        RECT  0 85.488 0.192 85.512 ;
    END
  END di[501]
  PIN di[502]
    DIRECTION INPUT ;
    USE SIGNAL ;
    PORT
      LAYER M4 ;
        RECT  0 85.632 0.192 85.656 ;
    END
  END di[502]
  PIN di[503]
    DIRECTION INPUT ;
    USE SIGNAL ;
    PORT
      LAYER M4 ;
        RECT  0 85.776 0.192 85.8 ;
    END
  END di[503]
  PIN di[504]
    DIRECTION INPUT ;
    USE SIGNAL ;
    PORT
      LAYER M4 ;
        RECT  0 85.968 0.192 85.992 ;
    END
  END di[504]
  PIN di[505]
    DIRECTION INPUT ;
    USE SIGNAL ;
    PORT
      LAYER M4 ;
        RECT  0 86.112 0.192 86.136 ;
    END
  END di[505]
  PIN di[506]
    DIRECTION INPUT ;
    USE SIGNAL ;
    PORT
      LAYER M4 ;
        RECT  0 86.256 0.192 86.28 ;
    END
  END di[506]
  PIN di[507]
    DIRECTION INPUT ;
    USE SIGNAL ;
    PORT
      LAYER M4 ;
        RECT  0 86.448 0.192 86.472 ;
    END
  END di[507]
  PIN di[508]
    DIRECTION INPUT ;
    USE SIGNAL ;
    PORT
      LAYER M4 ;
        RECT  0 86.592 0.192 86.616 ;
    END
  END di[508]
  PIN di[509]
    DIRECTION INPUT ;
    USE SIGNAL ;
    PORT
      LAYER M4 ;
        RECT  0 86.784 0.192 86.808 ;
    END
  END di[509]
  PIN di[50]
    DIRECTION INPUT ;
    USE SIGNAL ;
    PORT
      LAYER M4 ;
        RECT  0 12.48 0.192 12.504 ;
    END
  END di[50]
  PIN di[510]
    DIRECTION INPUT ;
    USE SIGNAL ;
    PORT
      LAYER M4 ;
        RECT  0 86.928 0.192 86.952 ;
    END
  END di[510]
  PIN di[511]
    DIRECTION INPUT ;
    USE SIGNAL ;
    PORT
      LAYER M4 ;
        RECT  0 87.072 0.192 87.096 ;
    END
  END di[511]
  PIN di[512]
    DIRECTION INPUT ;
    USE SIGNAL ;
    PORT
      LAYER M4 ;
        RECT  0 87.264 0.192 87.288 ;
    END
  END di[512]
  PIN di[513]
    DIRECTION INPUT ;
    USE SIGNAL ;
    PORT
      LAYER M4 ;
        RECT  0 87.408 0.192 87.432 ;
    END
  END di[513]
  PIN di[514]
    DIRECTION INPUT ;
    USE SIGNAL ;
    PORT
      LAYER M4 ;
        RECT  0 87.552 0.192 87.576 ;
    END
  END di[514]
  PIN di[515]
    DIRECTION INPUT ;
    USE SIGNAL ;
    PORT
      LAYER M4 ;
        RECT  0 87.744 0.192 87.768 ;
    END
  END di[515]
  PIN di[516]
    DIRECTION INPUT ;
    USE SIGNAL ;
    PORT
      LAYER M4 ;
        RECT  0 87.888 0.192 87.912 ;
    END
  END di[516]
  PIN di[517]
    DIRECTION INPUT ;
    USE SIGNAL ;
    PORT
      LAYER M4 ;
        RECT  0 88.08 0.192 88.104 ;
    END
  END di[517]
  PIN di[518]
    DIRECTION INPUT ;
    USE SIGNAL ;
    PORT
      LAYER M4 ;
        RECT  0 88.224 0.192 88.248 ;
    END
  END di[518]
  PIN di[519]
    DIRECTION INPUT ;
    USE SIGNAL ;
    PORT
      LAYER M4 ;
        RECT  0 88.368 0.192 88.392 ;
    END
  END di[519]
  PIN di[51]
    DIRECTION INPUT ;
    USE SIGNAL ;
    PORT
      LAYER M4 ;
        RECT  0 12.672 0.192 12.696 ;
    END
  END di[51]
  PIN di[520]
    DIRECTION INPUT ;
    USE SIGNAL ;
    PORT
      LAYER M4 ;
        RECT  0 88.56 0.192 88.584 ;
    END
  END di[520]
  PIN di[521]
    DIRECTION INPUT ;
    USE SIGNAL ;
    PORT
      LAYER M4 ;
        RECT  0 88.704 0.192 88.728 ;
    END
  END di[521]
  PIN di[522]
    DIRECTION INPUT ;
    USE SIGNAL ;
    PORT
      LAYER M4 ;
        RECT  0 88.848 0.192 88.872 ;
    END
  END di[522]
  PIN di[523]
    DIRECTION INPUT ;
    USE SIGNAL ;
    PORT
      LAYER M4 ;
        RECT  0 89.04 0.192 89.064 ;
    END
  END di[523]
  PIN di[524]
    DIRECTION INPUT ;
    USE SIGNAL ;
    PORT
      LAYER M4 ;
        RECT  0 89.184 0.192 89.208 ;
    END
  END di[524]
  PIN di[525]
    DIRECTION INPUT ;
    USE SIGNAL ;
    PORT
      LAYER M4 ;
        RECT  0 89.328 0.192 89.352 ;
    END
  END di[525]
  PIN di[526]
    DIRECTION INPUT ;
    USE SIGNAL ;
    PORT
      LAYER M4 ;
        RECT  0 89.52 0.192 89.544 ;
    END
  END di[526]
  PIN di[527]
    DIRECTION INPUT ;
    USE SIGNAL ;
    PORT
      LAYER M4 ;
        RECT  0 89.664 0.192 89.688 ;
    END
  END di[527]
  PIN di[528]
    DIRECTION INPUT ;
    USE SIGNAL ;
    PORT
      LAYER M4 ;
        RECT  0 89.856 0.192 89.88 ;
    END
  END di[528]
  PIN di[529]
    DIRECTION INPUT ;
    USE SIGNAL ;
    PORT
      LAYER M4 ;
        RECT  0 90 0.192 90.024 ;
    END
  END di[529]
  PIN di[52]
    DIRECTION INPUT ;
    USE SIGNAL ;
    PORT
      LAYER M4 ;
        RECT  0 12.816 0.192 12.84 ;
    END
  END di[52]
  PIN di[530]
    DIRECTION INPUT ;
    USE SIGNAL ;
    PORT
      LAYER M4 ;
        RECT  0 90.144 0.192 90.168 ;
    END
  END di[530]
  PIN di[531]
    DIRECTION INPUT ;
    USE SIGNAL ;
    PORT
      LAYER M4 ;
        RECT  0 90.336 0.192 90.36 ;
    END
  END di[531]
  PIN di[532]
    DIRECTION INPUT ;
    USE SIGNAL ;
    PORT
      LAYER M4 ;
        RECT  0 90.48 0.192 90.504 ;
    END
  END di[532]
  PIN di[533]
    DIRECTION INPUT ;
    USE SIGNAL ;
    PORT
      LAYER M4 ;
        RECT  0 90.624 0.192 90.648 ;
    END
  END di[533]
  PIN di[534]
    DIRECTION INPUT ;
    USE SIGNAL ;
    PORT
      LAYER M4 ;
        RECT  0 90.816 0.192 90.84 ;
    END
  END di[534]
  PIN di[535]
    DIRECTION INPUT ;
    USE SIGNAL ;
    PORT
      LAYER M4 ;
        RECT  0 90.96 0.192 90.984 ;
    END
  END di[535]
  PIN di[536]
    DIRECTION INPUT ;
    USE SIGNAL ;
    PORT
      LAYER M4 ;
        RECT  0 91.152 0.192 91.176 ;
    END
  END di[536]
  PIN di[537]
    DIRECTION INPUT ;
    USE SIGNAL ;
    PORT
      LAYER M4 ;
        RECT  0 91.296 0.192 91.32 ;
    END
  END di[537]
  PIN di[538]
    DIRECTION INPUT ;
    USE SIGNAL ;
    PORT
      LAYER M4 ;
        RECT  0 91.44 0.192 91.464 ;
    END
  END di[538]
  PIN di[539]
    DIRECTION INPUT ;
    USE SIGNAL ;
    PORT
      LAYER M4 ;
        RECT  0 91.632 0.192 91.656 ;
    END
  END di[539]
  PIN di[53]
    DIRECTION INPUT ;
    USE SIGNAL ;
    PORT
      LAYER M4 ;
        RECT  0 13.008 0.192 13.032 ;
    END
  END di[53]
  PIN di[540]
    DIRECTION INPUT ;
    USE SIGNAL ;
    PORT
      LAYER M4 ;
        RECT  0 91.776 0.192 91.8 ;
    END
  END di[540]
  PIN di[541]
    DIRECTION INPUT ;
    USE SIGNAL ;
    PORT
      LAYER M4 ;
        RECT  0 91.92 0.192 91.944 ;
    END
  END di[541]
  PIN di[542]
    DIRECTION INPUT ;
    USE SIGNAL ;
    PORT
      LAYER M4 ;
        RECT  0 92.112 0.192 92.136 ;
    END
  END di[542]
  PIN di[543]
    DIRECTION INPUT ;
    USE SIGNAL ;
    PORT
      LAYER M4 ;
        RECT  0 92.256 0.192 92.28 ;
    END
  END di[543]
  PIN di[544]
    DIRECTION INPUT ;
    USE SIGNAL ;
    PORT
      LAYER M4 ;
        RECT  0 92.448 0.192 92.472 ;
    END
  END di[544]
  PIN di[545]
    DIRECTION INPUT ;
    USE SIGNAL ;
    PORT
      LAYER M4 ;
        RECT  0 92.592 0.192 92.616 ;
    END
  END di[545]
  PIN di[546]
    DIRECTION INPUT ;
    USE SIGNAL ;
    PORT
      LAYER M4 ;
        RECT  0 92.736 0.192 92.76 ;
    END
  END di[546]
  PIN di[547]
    DIRECTION INPUT ;
    USE SIGNAL ;
    PORT
      LAYER M4 ;
        RECT  0 92.928 0.192 92.952 ;
    END
  END di[547]
  PIN di[548]
    DIRECTION INPUT ;
    USE SIGNAL ;
    PORT
      LAYER M4 ;
        RECT  0 93.072 0.192 93.096 ;
    END
  END di[548]
  PIN di[549]
    DIRECTION INPUT ;
    USE SIGNAL ;
    PORT
      LAYER M4 ;
        RECT  0 93.216 0.192 93.24 ;
    END
  END di[549]
  PIN di[54]
    DIRECTION INPUT ;
    USE SIGNAL ;
    PORT
      LAYER M4 ;
        RECT  0 13.152 0.192 13.176 ;
    END
  END di[54]
  PIN di[550]
    DIRECTION INPUT ;
    USE SIGNAL ;
    PORT
      LAYER M4 ;
        RECT  0 93.408 0.192 93.432 ;
    END
  END di[550]
  PIN di[551]
    DIRECTION INPUT ;
    USE SIGNAL ;
    PORT
      LAYER M4 ;
        RECT  0 93.552 0.192 93.576 ;
    END
  END di[551]
  PIN di[552]
    DIRECTION INPUT ;
    USE SIGNAL ;
    PORT
      LAYER M4 ;
        RECT  0 93.696 0.192 93.72 ;
    END
  END di[552]
  PIN di[553]
    DIRECTION INPUT ;
    USE SIGNAL ;
    PORT
      LAYER M4 ;
        RECT  0 93.888 0.192 93.912 ;
    END
  END di[553]
  PIN di[554]
    DIRECTION INPUT ;
    USE SIGNAL ;
    PORT
      LAYER M4 ;
        RECT  0 94.032 0.192 94.056 ;
    END
  END di[554]
  PIN di[555]
    DIRECTION INPUT ;
    USE SIGNAL ;
    PORT
      LAYER M4 ;
        RECT  0 94.224 0.192 94.248 ;
    END
  END di[555]
  PIN di[556]
    DIRECTION INPUT ;
    USE SIGNAL ;
    PORT
      LAYER M4 ;
        RECT  0 94.368 0.192 94.392 ;
    END
  END di[556]
  PIN di[557]
    DIRECTION INPUT ;
    USE SIGNAL ;
    PORT
      LAYER M4 ;
        RECT  0 94.512 0.192 94.536 ;
    END
  END di[557]
  PIN di[558]
    DIRECTION INPUT ;
    USE SIGNAL ;
    PORT
      LAYER M4 ;
        RECT  0 94.704 0.192 94.728 ;
    END
  END di[558]
  PIN di[559]
    DIRECTION INPUT ;
    USE SIGNAL ;
    PORT
      LAYER M4 ;
        RECT  0 94.848 0.192 94.872 ;
    END
  END di[559]
  PIN di[55]
    DIRECTION INPUT ;
    USE SIGNAL ;
    PORT
      LAYER M4 ;
        RECT  0 13.296 0.192 13.32 ;
    END
  END di[55]
  PIN di[560]
    DIRECTION INPUT ;
    USE SIGNAL ;
    PORT
      LAYER M4 ;
        RECT  0 94.992 0.192 95.016 ;
    END
  END di[560]
  PIN di[561]
    DIRECTION INPUT ;
    USE SIGNAL ;
    PORT
      LAYER M4 ;
        RECT  0 95.184 0.192 95.208 ;
    END
  END di[561]
  PIN di[562]
    DIRECTION INPUT ;
    USE SIGNAL ;
    PORT
      LAYER M4 ;
        RECT  0 95.328 0.192 95.352 ;
    END
  END di[562]
  PIN di[563]
    DIRECTION INPUT ;
    USE SIGNAL ;
    PORT
      LAYER M4 ;
        RECT  0 95.52 0.192 95.544 ;
    END
  END di[563]
  PIN di[564]
    DIRECTION INPUT ;
    USE SIGNAL ;
    PORT
      LAYER M4 ;
        RECT  0 95.664 0.192 95.688 ;
    END
  END di[564]
  PIN di[565]
    DIRECTION INPUT ;
    USE SIGNAL ;
    PORT
      LAYER M4 ;
        RECT  0 95.808 0.192 95.832 ;
    END
  END di[565]
  PIN di[566]
    DIRECTION INPUT ;
    USE SIGNAL ;
    PORT
      LAYER M4 ;
        RECT  0 96 0.192 96.024 ;
    END
  END di[566]
  PIN di[567]
    DIRECTION INPUT ;
    USE SIGNAL ;
    PORT
      LAYER M4 ;
        RECT  0 96.144 0.192 96.168 ;
    END
  END di[567]
  PIN di[568]
    DIRECTION INPUT ;
    USE SIGNAL ;
    PORT
      LAYER M4 ;
        RECT  0 96.288 0.192 96.312 ;
    END
  END di[568]
  PIN di[569]
    DIRECTION INPUT ;
    USE SIGNAL ;
    PORT
      LAYER M4 ;
        RECT  0 96.48 0.192 96.504 ;
    END
  END di[569]
  PIN di[56]
    DIRECTION INPUT ;
    USE SIGNAL ;
    PORT
      LAYER M4 ;
        RECT  0 13.488 0.192 13.512 ;
    END
  END di[56]
  PIN di[570]
    DIRECTION INPUT ;
    USE SIGNAL ;
    PORT
      LAYER M4 ;
        RECT  0 96.624 0.192 96.648 ;
    END
  END di[570]
  PIN di[571]
    DIRECTION INPUT ;
    USE SIGNAL ;
    PORT
      LAYER M4 ;
        RECT  0 96.816 0.192 96.84 ;
    END
  END di[571]
  PIN di[572]
    DIRECTION INPUT ;
    USE SIGNAL ;
    PORT
      LAYER M4 ;
        RECT  0 96.96 0.192 96.984 ;
    END
  END di[572]
  PIN di[573]
    DIRECTION INPUT ;
    USE SIGNAL ;
    PORT
      LAYER M4 ;
        RECT  0 97.104 0.192 97.128 ;
    END
  END di[573]
  PIN di[574]
    DIRECTION INPUT ;
    USE SIGNAL ;
    PORT
      LAYER M4 ;
        RECT  0 97.296 0.192 97.32 ;
    END
  END di[574]
  PIN di[575]
    DIRECTION INPUT ;
    USE SIGNAL ;
    PORT
      LAYER M4 ;
        RECT  0 97.44 0.192 97.464 ;
    END
  END di[575]
  PIN di[576]
    DIRECTION INPUT ;
    USE SIGNAL ;
    PORT
      LAYER M4 ;
        RECT  0 97.584 0.192 97.608 ;
    END
  END di[576]
  PIN di[577]
    DIRECTION INPUT ;
    USE SIGNAL ;
    PORT
      LAYER M4 ;
        RECT  0 97.776 0.192 97.8 ;
    END
  END di[577]
  PIN di[578]
    DIRECTION INPUT ;
    USE SIGNAL ;
    PORT
      LAYER M4 ;
        RECT  0 97.92 0.192 97.944 ;
    END
  END di[578]
  PIN di[579]
    DIRECTION INPUT ;
    USE SIGNAL ;
    PORT
      LAYER M4 ;
        RECT  0 98.064 0.192 98.088 ;
    END
  END di[579]
  PIN di[57]
    DIRECTION INPUT ;
    USE SIGNAL ;
    PORT
      LAYER M4 ;
        RECT  0 13.632 0.192 13.656 ;
    END
  END di[57]
  PIN di[580]
    DIRECTION INPUT ;
    USE SIGNAL ;
    PORT
      LAYER M4 ;
        RECT  0 98.256 0.192 98.28 ;
    END
  END di[580]
  PIN di[581]
    DIRECTION INPUT ;
    USE SIGNAL ;
    PORT
      LAYER M4 ;
        RECT  0 98.4 0.192 98.424 ;
    END
  END di[581]
  PIN di[582]
    DIRECTION INPUT ;
    USE SIGNAL ;
    PORT
      LAYER M4 ;
        RECT  0 98.592 0.192 98.616 ;
    END
  END di[582]
  PIN di[583]
    DIRECTION INPUT ;
    USE SIGNAL ;
    PORT
      LAYER M4 ;
        RECT  0 98.736 0.192 98.76 ;
    END
  END di[583]
  PIN di[584]
    DIRECTION INPUT ;
    USE SIGNAL ;
    PORT
      LAYER M4 ;
        RECT  0 98.88 0.192 98.904 ;
    END
  END di[584]
  PIN di[585]
    DIRECTION INPUT ;
    USE SIGNAL ;
    PORT
      LAYER M4 ;
        RECT  0 99.072 0.192 99.096 ;
    END
  END di[585]
  PIN di[586]
    DIRECTION INPUT ;
    USE SIGNAL ;
    PORT
      LAYER M4 ;
        RECT  0 99.216 0.192 99.24 ;
    END
  END di[586]
  PIN di[587]
    DIRECTION INPUT ;
    USE SIGNAL ;
    PORT
      LAYER M4 ;
        RECT  0 99.36 0.192 99.384 ;
    END
  END di[587]
  PIN di[588]
    DIRECTION INPUT ;
    USE SIGNAL ;
    PORT
      LAYER M4 ;
        RECT  0 99.552 0.192 99.576 ;
    END
  END di[588]
  PIN di[589]
    DIRECTION INPUT ;
    USE SIGNAL ;
    PORT
      LAYER M4 ;
        RECT  0 99.696 0.192 99.72 ;
    END
  END di[589]
  PIN di[58]
    DIRECTION INPUT ;
    USE SIGNAL ;
    PORT
      LAYER M4 ;
        RECT  0 13.776 0.192 13.8 ;
    END
  END di[58]
  PIN di[590]
    DIRECTION INPUT ;
    USE SIGNAL ;
    PORT
      LAYER M4 ;
        RECT  0 99.888 0.192 99.912 ;
    END
  END di[590]
  PIN di[591]
    DIRECTION INPUT ;
    USE SIGNAL ;
    PORT
      LAYER M4 ;
        RECT  0 100.032 0.192 100.056 ;
    END
  END di[591]
  PIN di[592]
    DIRECTION INPUT ;
    USE SIGNAL ;
    PORT
      LAYER M4 ;
        RECT  0 100.176 0.192 100.2 ;
    END
  END di[592]
  PIN di[593]
    DIRECTION INPUT ;
    USE SIGNAL ;
    PORT
      LAYER M4 ;
        RECT  0 100.368 0.192 100.392 ;
    END
  END di[593]
  PIN di[594]
    DIRECTION INPUT ;
    USE SIGNAL ;
    PORT
      LAYER M4 ;
        RECT  0 100.512 0.192 100.536 ;
    END
  END di[594]
  PIN di[595]
    DIRECTION INPUT ;
    USE SIGNAL ;
    PORT
      LAYER M4 ;
        RECT  0 100.656 0.192 100.68 ;
    END
  END di[595]
  PIN di[596]
    DIRECTION INPUT ;
    USE SIGNAL ;
    PORT
      LAYER M4 ;
        RECT  0 100.848 0.192 100.872 ;
    END
  END di[596]
  PIN di[597]
    DIRECTION INPUT ;
    USE SIGNAL ;
    PORT
      LAYER M4 ;
        RECT  0 100.992 0.192 101.016 ;
    END
  END di[597]
  PIN di[598]
    DIRECTION INPUT ;
    USE SIGNAL ;
    PORT
      LAYER M4 ;
        RECT  0 101.184 0.192 101.208 ;
    END
  END di[598]
  PIN di[599]
    DIRECTION INPUT ;
    USE SIGNAL ;
    PORT
      LAYER M4 ;
        RECT  0 101.328 0.192 101.352 ;
    END
  END di[599]
  PIN di[59]
    DIRECTION INPUT ;
    USE SIGNAL ;
    PORT
      LAYER M4 ;
        RECT  0 13.968 0.192 13.992 ;
    END
  END di[59]
  PIN di[5]
    DIRECTION INPUT ;
    USE SIGNAL ;
    PORT
      LAYER M4 ;
        RECT  0 5.232 0.192 5.256 ;
    END
  END di[5]
  PIN di[600]
    DIRECTION INPUT ;
    USE SIGNAL ;
    PORT
      LAYER M4 ;
        RECT  0 101.472 0.192 101.496 ;
    END
  END di[600]
  PIN di[601]
    DIRECTION INPUT ;
    USE SIGNAL ;
    PORT
      LAYER M4 ;
        RECT  0 101.664 0.192 101.688 ;
    END
  END di[601]
  PIN di[602]
    DIRECTION INPUT ;
    USE SIGNAL ;
    PORT
      LAYER M4 ;
        RECT  0 101.808 0.192 101.832 ;
    END
  END di[602]
  PIN di[603]
    DIRECTION INPUT ;
    USE SIGNAL ;
    PORT
      LAYER M4 ;
        RECT  0 101.952 0.192 101.976 ;
    END
  END di[603]
  PIN di[604]
    DIRECTION INPUT ;
    USE SIGNAL ;
    PORT
      LAYER M4 ;
        RECT  0 102.144 0.192 102.168 ;
    END
  END di[604]
  PIN di[605]
    DIRECTION INPUT ;
    USE SIGNAL ;
    PORT
      LAYER M4 ;
        RECT  0 102.288 0.192 102.312 ;
    END
  END di[605]
  PIN di[606]
    DIRECTION INPUT ;
    USE SIGNAL ;
    PORT
      LAYER M4 ;
        RECT  0 102.432 0.192 102.456 ;
    END
  END di[606]
  PIN di[607]
    DIRECTION INPUT ;
    USE SIGNAL ;
    PORT
      LAYER M4 ;
        RECT  0 102.624 0.192 102.648 ;
    END
  END di[607]
  PIN di[608]
    DIRECTION INPUT ;
    USE SIGNAL ;
    PORT
      LAYER M4 ;
        RECT  0 102.768 0.192 102.792 ;
    END
  END di[608]
  PIN di[609]
    DIRECTION INPUT ;
    USE SIGNAL ;
    PORT
      LAYER M4 ;
        RECT  0 102.96 0.192 102.984 ;
    END
  END di[609]
  PIN di[60]
    DIRECTION INPUT ;
    USE SIGNAL ;
    PORT
      LAYER M4 ;
        RECT  0 14.112 0.192 14.136 ;
    END
  END di[60]
  PIN di[610]
    DIRECTION INPUT ;
    USE SIGNAL ;
    PORT
      LAYER M4 ;
        RECT  0 103.104 0.192 103.128 ;
    END
  END di[610]
  PIN di[611]
    DIRECTION INPUT ;
    USE SIGNAL ;
    PORT
      LAYER M4 ;
        RECT  0 103.248 0.192 103.272 ;
    END
  END di[611]
  PIN di[612]
    DIRECTION INPUT ;
    USE SIGNAL ;
    PORT
      LAYER M4 ;
        RECT  0 103.44 0.192 103.464 ;
    END
  END di[612]
  PIN di[613]
    DIRECTION INPUT ;
    USE SIGNAL ;
    PORT
      LAYER M4 ;
        RECT  0 103.584 0.192 103.608 ;
    END
  END di[613]
  PIN di[614]
    DIRECTION INPUT ;
    USE SIGNAL ;
    PORT
      LAYER M4 ;
        RECT  0 103.728 0.192 103.752 ;
    END
  END di[614]
  PIN di[615]
    DIRECTION INPUT ;
    USE SIGNAL ;
    PORT
      LAYER M4 ;
        RECT  0 103.92 0.192 103.944 ;
    END
  END di[615]
  PIN di[616]
    DIRECTION INPUT ;
    USE SIGNAL ;
    PORT
      LAYER M4 ;
        RECT  0 104.064 0.192 104.088 ;
    END
  END di[616]
  PIN di[617]
    DIRECTION INPUT ;
    USE SIGNAL ;
    PORT
      LAYER M4 ;
        RECT  0 104.256 0.192 104.28 ;
    END
  END di[617]
  PIN di[618]
    DIRECTION INPUT ;
    USE SIGNAL ;
    PORT
      LAYER M4 ;
        RECT  0 104.4 0.192 104.424 ;
    END
  END di[618]
  PIN di[619]
    DIRECTION INPUT ;
    USE SIGNAL ;
    PORT
      LAYER M4 ;
        RECT  0 104.544 0.192 104.568 ;
    END
  END di[619]
  PIN di[61]
    DIRECTION INPUT ;
    USE SIGNAL ;
    PORT
      LAYER M4 ;
        RECT  0 14.304 0.192 14.328 ;
    END
  END di[61]
  PIN di[620]
    DIRECTION INPUT ;
    USE SIGNAL ;
    PORT
      LAYER M4 ;
        RECT  0 104.736 0.192 104.76 ;
    END
  END di[620]
  PIN di[621]
    DIRECTION INPUT ;
    USE SIGNAL ;
    PORT
      LAYER M4 ;
        RECT  0 104.88 0.192 104.904 ;
    END
  END di[621]
  PIN di[622]
    DIRECTION INPUT ;
    USE SIGNAL ;
    PORT
      LAYER M4 ;
        RECT  0 105.024 0.192 105.048 ;
    END
  END di[622]
  PIN di[623]
    DIRECTION INPUT ;
    USE SIGNAL ;
    PORT
      LAYER M4 ;
        RECT  0 105.216 0.192 105.24 ;
    END
  END di[623]
  PIN di[624]
    DIRECTION INPUT ;
    USE SIGNAL ;
    PORT
      LAYER M4 ;
        RECT  0 105.36 0.192 105.384 ;
    END
  END di[624]
  PIN di[625]
    DIRECTION INPUT ;
    USE SIGNAL ;
    PORT
      LAYER M4 ;
        RECT  0 105.552 0.192 105.576 ;
    END
  END di[625]
  PIN di[626]
    DIRECTION INPUT ;
    USE SIGNAL ;
    PORT
      LAYER M4 ;
        RECT  0 105.696 0.192 105.72 ;
    END
  END di[626]
  PIN di[627]
    DIRECTION INPUT ;
    USE SIGNAL ;
    PORT
      LAYER M4 ;
        RECT  0 105.84 0.192 105.864 ;
    END
  END di[627]
  PIN di[628]
    DIRECTION INPUT ;
    USE SIGNAL ;
    PORT
      LAYER M4 ;
        RECT  0 106.032 0.192 106.056 ;
    END
  END di[628]
  PIN di[629]
    DIRECTION INPUT ;
    USE SIGNAL ;
    PORT
      LAYER M4 ;
        RECT  0 106.176 0.192 106.2 ;
    END
  END di[629]
  PIN di[62]
    DIRECTION INPUT ;
    USE SIGNAL ;
    PORT
      LAYER M4 ;
        RECT  0 14.448 0.192 14.472 ;
    END
  END di[62]
  PIN di[630]
    DIRECTION INPUT ;
    USE SIGNAL ;
    PORT
      LAYER M4 ;
        RECT  0 106.32 0.192 106.344 ;
    END
  END di[630]
  PIN di[631]
    DIRECTION INPUT ;
    USE SIGNAL ;
    PORT
      LAYER M4 ;
        RECT  0 106.512 0.192 106.536 ;
    END
  END di[631]
  PIN di[632]
    DIRECTION INPUT ;
    USE SIGNAL ;
    PORT
      LAYER M4 ;
        RECT  0 106.656 0.192 106.68 ;
    END
  END di[632]
  PIN di[633]
    DIRECTION INPUT ;
    USE SIGNAL ;
    PORT
      LAYER M4 ;
        RECT  0 106.848 0.192 106.872 ;
    END
  END di[633]
  PIN di[634]
    DIRECTION INPUT ;
    USE SIGNAL ;
    PORT
      LAYER M4 ;
        RECT  0 106.992 0.192 107.016 ;
    END
  END di[634]
  PIN di[635]
    DIRECTION INPUT ;
    USE SIGNAL ;
    PORT
      LAYER M4 ;
        RECT  0 107.136 0.192 107.16 ;
    END
  END di[635]
  PIN di[636]
    DIRECTION INPUT ;
    USE SIGNAL ;
    PORT
      LAYER M4 ;
        RECT  0 107.328 0.192 107.352 ;
    END
  END di[636]
  PIN di[637]
    DIRECTION INPUT ;
    USE SIGNAL ;
    PORT
      LAYER M4 ;
        RECT  0 107.472 0.192 107.496 ;
    END
  END di[637]
  PIN di[638]
    DIRECTION INPUT ;
    USE SIGNAL ;
    PORT
      LAYER M4 ;
        RECT  0 107.616 0.192 107.64 ;
    END
  END di[638]
  PIN di[639]
    DIRECTION INPUT ;
    USE SIGNAL ;
    PORT
      LAYER M4 ;
        RECT  0 107.808 0.192 107.832 ;
    END
  END di[639]
  PIN di[63]
    DIRECTION INPUT ;
    USE SIGNAL ;
    PORT
      LAYER M4 ;
        RECT  0 14.592 0.192 14.616 ;
    END
  END di[63]
  PIN di[640]
    DIRECTION INPUT ;
    USE SIGNAL ;
    PORT
      LAYER M4 ;
        RECT  0 107.952 0.192 107.976 ;
    END
  END di[640]
  PIN di[641]
    DIRECTION INPUT ;
    USE SIGNAL ;
    PORT
      LAYER M4 ;
        RECT  0 108.096 0.192 108.12 ;
    END
  END di[641]
  PIN di[642]
    DIRECTION INPUT ;
    USE SIGNAL ;
    PORT
      LAYER M4 ;
        RECT  0 108.288 0.192 108.312 ;
    END
  END di[642]
  PIN di[643]
    DIRECTION INPUT ;
    USE SIGNAL ;
    PORT
      LAYER M4 ;
        RECT  0 108.432 0.192 108.456 ;
    END
  END di[643]
  PIN di[644]
    DIRECTION INPUT ;
    USE SIGNAL ;
    PORT
      LAYER M4 ;
        RECT  0 108.624 0.192 108.648 ;
    END
  END di[644]
  PIN di[645]
    DIRECTION INPUT ;
    USE SIGNAL ;
    PORT
      LAYER M4 ;
        RECT  0 108.768 0.192 108.792 ;
    END
  END di[645]
  PIN di[646]
    DIRECTION INPUT ;
    USE SIGNAL ;
    PORT
      LAYER M4 ;
        RECT  0 108.912 0.192 108.936 ;
    END
  END di[646]
  PIN di[647]
    DIRECTION INPUT ;
    USE SIGNAL ;
    PORT
      LAYER M4 ;
        RECT  0 109.104 0.192 109.128 ;
    END
  END di[647]
  PIN di[648]
    DIRECTION INPUT ;
    USE SIGNAL ;
    PORT
      LAYER M4 ;
        RECT  0 109.248 0.192 109.272 ;
    END
  END di[648]
  PIN di[649]
    DIRECTION INPUT ;
    USE SIGNAL ;
    PORT
      LAYER M4 ;
        RECT  0 109.392 0.192 109.416 ;
    END
  END di[649]
  PIN di[64]
    DIRECTION INPUT ;
    USE SIGNAL ;
    PORT
      LAYER M4 ;
        RECT  0 14.784 0.192 14.808 ;
    END
  END di[64]
  PIN di[650]
    DIRECTION INPUT ;
    USE SIGNAL ;
    PORT
      LAYER M4 ;
        RECT  0 109.584 0.192 109.608 ;
    END
  END di[650]
  PIN di[651]
    DIRECTION INPUT ;
    USE SIGNAL ;
    PORT
      LAYER M4 ;
        RECT  0 109.728 0.192 109.752 ;
    END
  END di[651]
  PIN di[652]
    DIRECTION INPUT ;
    USE SIGNAL ;
    PORT
      LAYER M4 ;
        RECT  0 109.92 0.192 109.944 ;
    END
  END di[652]
  PIN di[653]
    DIRECTION INPUT ;
    USE SIGNAL ;
    PORT
      LAYER M4 ;
        RECT  0 110.064 0.192 110.088 ;
    END
  END di[653]
  PIN di[654]
    DIRECTION INPUT ;
    USE SIGNAL ;
    PORT
      LAYER M4 ;
        RECT  0 110.208 0.192 110.232 ;
    END
  END di[654]
  PIN di[655]
    DIRECTION INPUT ;
    USE SIGNAL ;
    PORT
      LAYER M4 ;
        RECT  0 110.4 0.192 110.424 ;
    END
  END di[655]
  PIN di[656]
    DIRECTION INPUT ;
    USE SIGNAL ;
    PORT
      LAYER M4 ;
        RECT  0 110.544 0.192 110.568 ;
    END
  END di[656]
  PIN di[657]
    DIRECTION INPUT ;
    USE SIGNAL ;
    PORT
      LAYER M4 ;
        RECT  0 110.688 0.192 110.712 ;
    END
  END di[657]
  PIN di[658]
    DIRECTION INPUT ;
    USE SIGNAL ;
    PORT
      LAYER M4 ;
        RECT  0 110.88 0.192 110.904 ;
    END
  END di[658]
  PIN di[659]
    DIRECTION INPUT ;
    USE SIGNAL ;
    PORT
      LAYER M4 ;
        RECT  0 111.024 0.192 111.048 ;
    END
  END di[659]
  PIN di[65]
    DIRECTION INPUT ;
    USE SIGNAL ;
    PORT
      LAYER M4 ;
        RECT  0 14.928 0.192 14.952 ;
    END
  END di[65]
  PIN di[660]
    DIRECTION INPUT ;
    USE SIGNAL ;
    PORT
      LAYER M4 ;
        RECT  0 111.216 0.192 111.24 ;
    END
  END di[660]
  PIN di[661]
    DIRECTION INPUT ;
    USE SIGNAL ;
    PORT
      LAYER M4 ;
        RECT  0 111.36 0.192 111.384 ;
    END
  END di[661]
  PIN di[662]
    DIRECTION INPUT ;
    USE SIGNAL ;
    PORT
      LAYER M4 ;
        RECT  0 111.504 0.192 111.528 ;
    END
  END di[662]
  PIN di[663]
    DIRECTION INPUT ;
    USE SIGNAL ;
    PORT
      LAYER M4 ;
        RECT  0 111.696 0.192 111.72 ;
    END
  END di[663]
  PIN di[664]
    DIRECTION INPUT ;
    USE SIGNAL ;
    PORT
      LAYER M4 ;
        RECT  0 111.84 0.192 111.864 ;
    END
  END di[664]
  PIN di[665]
    DIRECTION INPUT ;
    USE SIGNAL ;
    PORT
      LAYER M4 ;
        RECT  0 111.984 0.192 112.008 ;
    END
  END di[665]
  PIN di[666]
    DIRECTION INPUT ;
    USE SIGNAL ;
    PORT
      LAYER M4 ;
        RECT  0 112.176 0.192 112.2 ;
    END
  END di[666]
  PIN di[667]
    DIRECTION INPUT ;
    USE SIGNAL ;
    PORT
      LAYER M4 ;
        RECT  0 112.32 0.192 112.344 ;
    END
  END di[667]
  PIN di[668]
    DIRECTION INPUT ;
    USE SIGNAL ;
    PORT
      LAYER M4 ;
        RECT  0 112.464 0.192 112.488 ;
    END
  END di[668]
  PIN di[669]
    DIRECTION INPUT ;
    USE SIGNAL ;
    PORT
      LAYER M4 ;
        RECT  0 112.656 0.192 112.68 ;
    END
  END di[669]
  PIN di[66]
    DIRECTION INPUT ;
    USE SIGNAL ;
    PORT
      LAYER M4 ;
        RECT  0 15.072 0.192 15.096 ;
    END
  END di[66]
  PIN di[670]
    DIRECTION INPUT ;
    USE SIGNAL ;
    PORT
      LAYER M4 ;
        RECT  0 112.8 0.192 112.824 ;
    END
  END di[670]
  PIN di[671]
    DIRECTION INPUT ;
    USE SIGNAL ;
    PORT
      LAYER M4 ;
        RECT  0 112.992 0.192 113.016 ;
    END
  END di[671]
  PIN di[672]
    DIRECTION INPUT ;
    USE SIGNAL ;
    PORT
      LAYER M4 ;
        RECT  0 113.136 0.192 113.16 ;
    END
  END di[672]
  PIN di[673]
    DIRECTION INPUT ;
    USE SIGNAL ;
    PORT
      LAYER M4 ;
        RECT  0 113.28 0.192 113.304 ;
    END
  END di[673]
  PIN di[674]
    DIRECTION INPUT ;
    USE SIGNAL ;
    PORT
      LAYER M4 ;
        RECT  0 113.472 0.192 113.496 ;
    END
  END di[674]
  PIN di[675]
    DIRECTION INPUT ;
    USE SIGNAL ;
    PORT
      LAYER M4 ;
        RECT  0 113.616 0.192 113.64 ;
    END
  END di[675]
  PIN di[676]
    DIRECTION INPUT ;
    USE SIGNAL ;
    PORT
      LAYER M4 ;
        RECT  0 113.76 0.192 113.784 ;
    END
  END di[676]
  PIN di[677]
    DIRECTION INPUT ;
    USE SIGNAL ;
    PORT
      LAYER M4 ;
        RECT  0 113.952 0.192 113.976 ;
    END
  END di[677]
  PIN di[678]
    DIRECTION INPUT ;
    USE SIGNAL ;
    PORT
      LAYER M4 ;
        RECT  0 114.096 0.192 114.12 ;
    END
  END di[678]
  PIN di[679]
    DIRECTION INPUT ;
    USE SIGNAL ;
    PORT
      LAYER M4 ;
        RECT  0 114.288 0.192 114.312 ;
    END
  END di[679]
  PIN di[67]
    DIRECTION INPUT ;
    USE SIGNAL ;
    PORT
      LAYER M4 ;
        RECT  0 15.264 0.192 15.288 ;
    END
  END di[67]
  PIN di[680]
    DIRECTION INPUT ;
    USE SIGNAL ;
    PORT
      LAYER M4 ;
        RECT  0 114.432 0.192 114.456 ;
    END
  END di[680]
  PIN di[681]
    DIRECTION INPUT ;
    USE SIGNAL ;
    PORT
      LAYER M4 ;
        RECT  0 114.576 0.192 114.6 ;
    END
  END di[681]
  PIN di[682]
    DIRECTION INPUT ;
    USE SIGNAL ;
    PORT
      LAYER M4 ;
        RECT  0 114.768 0.192 114.792 ;
    END
  END di[682]
  PIN di[683]
    DIRECTION INPUT ;
    USE SIGNAL ;
    PORT
      LAYER M4 ;
        RECT  0 114.912 0.192 114.936 ;
    END
  END di[683]
  PIN di[684]
    DIRECTION INPUT ;
    USE SIGNAL ;
    PORT
      LAYER M4 ;
        RECT  0 115.056 0.192 115.08 ;
    END
  END di[684]
  PIN di[685]
    DIRECTION INPUT ;
    USE SIGNAL ;
    PORT
      LAYER M4 ;
        RECT  0 115.248 0.192 115.272 ;
    END
  END di[685]
  PIN di[686]
    DIRECTION INPUT ;
    USE SIGNAL ;
    PORT
      LAYER M4 ;
        RECT  0 115.392 0.192 115.416 ;
    END
  END di[686]
  PIN di[687]
    DIRECTION INPUT ;
    USE SIGNAL ;
    PORT
      LAYER M4 ;
        RECT  0 115.584 0.192 115.608 ;
    END
  END di[687]
  PIN di[688]
    DIRECTION INPUT ;
    USE SIGNAL ;
    PORT
      LAYER M4 ;
        RECT  0 115.728 0.192 115.752 ;
    END
  END di[688]
  PIN di[689]
    DIRECTION INPUT ;
    USE SIGNAL ;
    PORT
      LAYER M4 ;
        RECT  0 115.872 0.192 115.896 ;
    END
  END di[689]
  PIN di[68]
    DIRECTION INPUT ;
    USE SIGNAL ;
    PORT
      LAYER M4 ;
        RECT  0 15.408 0.192 15.432 ;
    END
  END di[68]
  PIN di[690]
    DIRECTION INPUT ;
    USE SIGNAL ;
    PORT
      LAYER M4 ;
        RECT  0 116.064 0.192 116.088 ;
    END
  END di[690]
  PIN di[691]
    DIRECTION INPUT ;
    USE SIGNAL ;
    PORT
      LAYER M4 ;
        RECT  0 116.208 0.192 116.232 ;
    END
  END di[691]
  PIN di[692]
    DIRECTION INPUT ;
    USE SIGNAL ;
    PORT
      LAYER M4 ;
        RECT  0 116.352 0.192 116.376 ;
    END
  END di[692]
  PIN di[693]
    DIRECTION INPUT ;
    USE SIGNAL ;
    PORT
      LAYER M4 ;
        RECT  0 116.544 0.192 116.568 ;
    END
  END di[693]
  PIN di[694]
    DIRECTION INPUT ;
    USE SIGNAL ;
    PORT
      LAYER M4 ;
        RECT  0 116.688 0.192 116.712 ;
    END
  END di[694]
  PIN di[695]
    DIRECTION INPUT ;
    USE SIGNAL ;
    PORT
      LAYER M4 ;
        RECT  0 116.832 0.192 116.856 ;
    END
  END di[695]
  PIN di[696]
    DIRECTION INPUT ;
    USE SIGNAL ;
    PORT
      LAYER M4 ;
        RECT  0 117.024 0.192 117.048 ;
    END
  END di[696]
  PIN di[697]
    DIRECTION INPUT ;
    USE SIGNAL ;
    PORT
      LAYER M4 ;
        RECT  0 117.168 0.192 117.192 ;
    END
  END di[697]
  PIN di[698]
    DIRECTION INPUT ;
    USE SIGNAL ;
    PORT
      LAYER M4 ;
        RECT  0 117.36 0.192 117.384 ;
    END
  END di[698]
  PIN di[699]
    DIRECTION INPUT ;
    USE SIGNAL ;
    PORT
      LAYER M4 ;
        RECT  0 117.504 0.192 117.528 ;
    END
  END di[699]
  PIN di[69]
    DIRECTION INPUT ;
    USE SIGNAL ;
    PORT
      LAYER M4 ;
        RECT  0 15.6 0.192 15.624 ;
    END
  END di[69]
  PIN di[6]
    DIRECTION INPUT ;
    USE SIGNAL ;
    PORT
      LAYER M4 ;
        RECT  0 5.376 0.192 5.4 ;
    END
  END di[6]
  PIN di[700]
    DIRECTION INPUT ;
    USE SIGNAL ;
    PORT
      LAYER M4 ;
        RECT  0 117.648 0.192 117.672 ;
    END
  END di[700]
  PIN di[701]
    DIRECTION INPUT ;
    USE SIGNAL ;
    PORT
      LAYER M4 ;
        RECT  0 117.84 0.192 117.864 ;
    END
  END di[701]
  PIN di[702]
    DIRECTION INPUT ;
    USE SIGNAL ;
    PORT
      LAYER M4 ;
        RECT  0 117.984 0.192 118.008 ;
    END
  END di[702]
  PIN di[703]
    DIRECTION INPUT ;
    USE SIGNAL ;
    PORT
      LAYER M4 ;
        RECT  0 118.128 0.192 118.152 ;
    END
  END di[703]
  PIN di[704]
    DIRECTION INPUT ;
    USE SIGNAL ;
    PORT
      LAYER M4 ;
        RECT  0 118.32 0.192 118.344 ;
    END
  END di[704]
  PIN di[705]
    DIRECTION INPUT ;
    USE SIGNAL ;
    PORT
      LAYER M4 ;
        RECT  0 118.464 0.192 118.488 ;
    END
  END di[705]
  PIN di[706]
    DIRECTION INPUT ;
    USE SIGNAL ;
    PORT
      LAYER M4 ;
        RECT  0 118.656 0.192 118.68 ;
    END
  END di[706]
  PIN di[707]
    DIRECTION INPUT ;
    USE SIGNAL ;
    PORT
      LAYER M4 ;
        RECT  0 118.8 0.192 118.824 ;
    END
  END di[707]
  PIN di[708]
    DIRECTION INPUT ;
    USE SIGNAL ;
    PORT
      LAYER M4 ;
        RECT  0 118.944 0.192 118.968 ;
    END
  END di[708]
  PIN di[709]
    DIRECTION INPUT ;
    USE SIGNAL ;
    PORT
      LAYER M4 ;
        RECT  0 119.136 0.192 119.16 ;
    END
  END di[709]
  PIN di[70]
    DIRECTION INPUT ;
    USE SIGNAL ;
    PORT
      LAYER M4 ;
        RECT  0 15.744 0.192 15.768 ;
    END
  END di[70]
  PIN di[710]
    DIRECTION INPUT ;
    USE SIGNAL ;
    PORT
      LAYER M4 ;
        RECT  0 119.28 0.192 119.304 ;
    END
  END di[710]
  PIN di[711]
    DIRECTION INPUT ;
    USE SIGNAL ;
    PORT
      LAYER M4 ;
        RECT  0 119.424 0.192 119.448 ;
    END
  END di[711]
  PIN di[712]
    DIRECTION INPUT ;
    USE SIGNAL ;
    PORT
      LAYER M4 ;
        RECT  0 119.616 0.192 119.64 ;
    END
  END di[712]
  PIN di[713]
    DIRECTION INPUT ;
    USE SIGNAL ;
    PORT
      LAYER M4 ;
        RECT  0 119.76 0.192 119.784 ;
    END
  END di[713]
  PIN di[714]
    DIRECTION INPUT ;
    USE SIGNAL ;
    PORT
      LAYER M4 ;
        RECT  0 119.952 0.192 119.976 ;
    END
  END di[714]
  PIN di[715]
    DIRECTION INPUT ;
    USE SIGNAL ;
    PORT
      LAYER M4 ;
        RECT  0 120.096 0.192 120.12 ;
    END
  END di[715]
  PIN di[716]
    DIRECTION INPUT ;
    USE SIGNAL ;
    PORT
      LAYER M4 ;
        RECT  0 120.24 0.192 120.264 ;
    END
  END di[716]
  PIN di[717]
    DIRECTION INPUT ;
    USE SIGNAL ;
    PORT
      LAYER M4 ;
        RECT  0 120.432 0.192 120.456 ;
    END
  END di[717]
  PIN di[718]
    DIRECTION INPUT ;
    USE SIGNAL ;
    PORT
      LAYER M4 ;
        RECT  0 120.576 0.192 120.6 ;
    END
  END di[718]
  PIN di[719]
    DIRECTION INPUT ;
    USE SIGNAL ;
    PORT
      LAYER M4 ;
        RECT  0 120.72 0.192 120.744 ;
    END
  END di[719]
  PIN di[71]
    DIRECTION INPUT ;
    USE SIGNAL ;
    PORT
      LAYER M4 ;
        RECT  0 15.888 0.192 15.912 ;
    END
  END di[71]
  PIN di[720]
    DIRECTION INPUT ;
    USE SIGNAL ;
    PORT
      LAYER M4 ;
        RECT  0 120.912 0.192 120.936 ;
    END
  END di[720]
  PIN di[721]
    DIRECTION INPUT ;
    USE SIGNAL ;
    PORT
      LAYER M4 ;
        RECT  0 121.056 0.192 121.08 ;
    END
  END di[721]
  PIN di[722]
    DIRECTION INPUT ;
    USE SIGNAL ;
    PORT
      LAYER M4 ;
        RECT  0 121.2 0.192 121.224 ;
    END
  END di[722]
  PIN di[723]
    DIRECTION INPUT ;
    USE SIGNAL ;
    PORT
      LAYER M4 ;
        RECT  0 121.392 0.192 121.416 ;
    END
  END di[723]
  PIN di[724]
    DIRECTION INPUT ;
    USE SIGNAL ;
    PORT
      LAYER M4 ;
        RECT  0 121.536 0.192 121.56 ;
    END
  END di[724]
  PIN di[725]
    DIRECTION INPUT ;
    USE SIGNAL ;
    PORT
      LAYER M4 ;
        RECT  0 121.728 0.192 121.752 ;
    END
  END di[725]
  PIN di[726]
    DIRECTION INPUT ;
    USE SIGNAL ;
    PORT
      LAYER M4 ;
        RECT  0 121.872 0.192 121.896 ;
    END
  END di[726]
  PIN di[727]
    DIRECTION INPUT ;
    USE SIGNAL ;
    PORT
      LAYER M4 ;
        RECT  0 122.016 0.192 122.04 ;
    END
  END di[727]
  PIN di[728]
    DIRECTION INPUT ;
    USE SIGNAL ;
    PORT
      LAYER M4 ;
        RECT  0 122.208 0.192 122.232 ;
    END
  END di[728]
  PIN di[729]
    DIRECTION INPUT ;
    USE SIGNAL ;
    PORT
      LAYER M4 ;
        RECT  0 122.352 0.192 122.376 ;
    END
  END di[729]
  PIN di[72]
    DIRECTION INPUT ;
    USE SIGNAL ;
    PORT
      LAYER M4 ;
        RECT  0 16.08 0.192 16.104 ;
    END
  END di[72]
  PIN di[730]
    DIRECTION INPUT ;
    USE SIGNAL ;
    PORT
      LAYER M4 ;
        RECT  0 122.496 0.192 122.52 ;
    END
  END di[730]
  PIN di[731]
    DIRECTION INPUT ;
    USE SIGNAL ;
    PORT
      LAYER M4 ;
        RECT  0 122.688 0.192 122.712 ;
    END
  END di[731]
  PIN di[732]
    DIRECTION INPUT ;
    USE SIGNAL ;
    PORT
      LAYER M4 ;
        RECT  0 122.832 0.192 122.856 ;
    END
  END di[732]
  PIN di[733]
    DIRECTION INPUT ;
    USE SIGNAL ;
    PORT
      LAYER M4 ;
        RECT  0 123.024 0.192 123.048 ;
    END
  END di[733]
  PIN di[734]
    DIRECTION INPUT ;
    USE SIGNAL ;
    PORT
      LAYER M4 ;
        RECT  0 123.168 0.192 123.192 ;
    END
  END di[734]
  PIN di[735]
    DIRECTION INPUT ;
    USE SIGNAL ;
    PORT
      LAYER M4 ;
        RECT  0 123.312 0.192 123.336 ;
    END
  END di[735]
  PIN di[736]
    DIRECTION INPUT ;
    USE SIGNAL ;
    PORT
      LAYER M4 ;
        RECT  0 123.504 0.192 123.528 ;
    END
  END di[736]
  PIN di[737]
    DIRECTION INPUT ;
    USE SIGNAL ;
    PORT
      LAYER M4 ;
        RECT  0 123.648 0.192 123.672 ;
    END
  END di[737]
  PIN di[738]
    DIRECTION INPUT ;
    USE SIGNAL ;
    PORT
      LAYER M4 ;
        RECT  0 123.792 0.192 123.816 ;
    END
  END di[738]
  PIN di[739]
    DIRECTION INPUT ;
    USE SIGNAL ;
    PORT
      LAYER M4 ;
        RECT  0 123.984 0.192 124.008 ;
    END
  END di[739]
  PIN di[73]
    DIRECTION INPUT ;
    USE SIGNAL ;
    PORT
      LAYER M4 ;
        RECT  0 16.224 0.192 16.248 ;
    END
  END di[73]
  PIN di[740]
    DIRECTION INPUT ;
    USE SIGNAL ;
    PORT
      LAYER M4 ;
        RECT  0 124.128 0.192 124.152 ;
    END
  END di[740]
  PIN di[741]
    DIRECTION INPUT ;
    USE SIGNAL ;
    PORT
      LAYER M4 ;
        RECT  0 124.32 0.192 124.344 ;
    END
  END di[741]
  PIN di[742]
    DIRECTION INPUT ;
    USE SIGNAL ;
    PORT
      LAYER M4 ;
        RECT  0 124.464 0.192 124.488 ;
    END
  END di[742]
  PIN di[743]
    DIRECTION INPUT ;
    USE SIGNAL ;
    PORT
      LAYER M4 ;
        RECT  0 124.608 0.192 124.632 ;
    END
  END di[743]
  PIN di[744]
    DIRECTION INPUT ;
    USE SIGNAL ;
    PORT
      LAYER M4 ;
        RECT  0 124.8 0.192 124.824 ;
    END
  END di[744]
  PIN di[745]
    DIRECTION INPUT ;
    USE SIGNAL ;
    PORT
      LAYER M4 ;
        RECT  0 124.944 0.192 124.968 ;
    END
  END di[745]
  PIN di[746]
    DIRECTION INPUT ;
    USE SIGNAL ;
    PORT
      LAYER M4 ;
        RECT  0 125.088 0.192 125.112 ;
    END
  END di[746]
  PIN di[747]
    DIRECTION INPUT ;
    USE SIGNAL ;
    PORT
      LAYER M4 ;
        RECT  0 125.28 0.192 125.304 ;
    END
  END di[747]
  PIN di[748]
    DIRECTION INPUT ;
    USE SIGNAL ;
    PORT
      LAYER M4 ;
        RECT  0 125.424 0.192 125.448 ;
    END
  END di[748]
  PIN di[749]
    DIRECTION INPUT ;
    USE SIGNAL ;
    PORT
      LAYER M4 ;
        RECT  0 125.568 0.192 125.592 ;
    END
  END di[749]
  PIN di[74]
    DIRECTION INPUT ;
    USE SIGNAL ;
    PORT
      LAYER M4 ;
        RECT  0 16.368 0.192 16.392 ;
    END
  END di[74]
  PIN di[750]
    DIRECTION INPUT ;
    USE SIGNAL ;
    PORT
      LAYER M4 ;
        RECT  0 125.76 0.192 125.784 ;
    END
  END di[750]
  PIN di[751]
    DIRECTION INPUT ;
    USE SIGNAL ;
    PORT
      LAYER M4 ;
        RECT  0 125.904 0.192 125.928 ;
    END
  END di[751]
  PIN di[752]
    DIRECTION INPUT ;
    USE SIGNAL ;
    PORT
      LAYER M4 ;
        RECT  0 126.096 0.192 126.12 ;
    END
  END di[752]
  PIN di[753]
    DIRECTION INPUT ;
    USE SIGNAL ;
    PORT
      LAYER M4 ;
        RECT  0 126.24 0.192 126.264 ;
    END
  END di[753]
  PIN di[754]
    DIRECTION INPUT ;
    USE SIGNAL ;
    PORT
      LAYER M4 ;
        RECT  0 126.384 0.192 126.408 ;
    END
  END di[754]
  PIN di[755]
    DIRECTION INPUT ;
    USE SIGNAL ;
    PORT
      LAYER M4 ;
        RECT  0 126.576 0.192 126.6 ;
    END
  END di[755]
  PIN di[756]
    DIRECTION INPUT ;
    USE SIGNAL ;
    PORT
      LAYER M4 ;
        RECT  0 126.72 0.192 126.744 ;
    END
  END di[756]
  PIN di[757]
    DIRECTION INPUT ;
    USE SIGNAL ;
    PORT
      LAYER M4 ;
        RECT  0 126.864 0.192 126.888 ;
    END
  END di[757]
  PIN di[758]
    DIRECTION INPUT ;
    USE SIGNAL ;
    PORT
      LAYER M4 ;
        RECT  0 127.056 0.192 127.08 ;
    END
  END di[758]
  PIN di[759]
    DIRECTION INPUT ;
    USE SIGNAL ;
    PORT
      LAYER M4 ;
        RECT  0 127.2 0.192 127.224 ;
    END
  END di[759]
  PIN di[75]
    DIRECTION INPUT ;
    USE SIGNAL ;
    PORT
      LAYER M4 ;
        RECT  0 16.56 0.192 16.584 ;
    END
  END di[75]
  PIN di[760]
    DIRECTION INPUT ;
    USE SIGNAL ;
    PORT
      LAYER M4 ;
        RECT  0 127.392 0.192 127.416 ;
    END
  END di[760]
  PIN di[76]
    DIRECTION INPUT ;
    USE SIGNAL ;
    PORT
      LAYER M4 ;
        RECT  0 16.704 0.192 16.728 ;
    END
  END di[76]
  PIN di[77]
    DIRECTION INPUT ;
    USE SIGNAL ;
    PORT
      LAYER M4 ;
        RECT  0 16.848 0.192 16.872 ;
    END
  END di[77]
  PIN di[78]
    DIRECTION INPUT ;
    USE SIGNAL ;
    PORT
      LAYER M4 ;
        RECT  0 17.04 0.192 17.064 ;
    END
  END di[78]
  PIN di[79]
    DIRECTION INPUT ;
    USE SIGNAL ;
    PORT
      LAYER M4 ;
        RECT  0 17.184 0.192 17.208 ;
    END
  END di[79]
  PIN di[7]
    DIRECTION INPUT ;
    USE SIGNAL ;
    PORT
      LAYER M4 ;
        RECT  0 5.568 0.192 5.592 ;
    END
  END di[7]
  PIN di[80]
    DIRECTION INPUT ;
    USE SIGNAL ;
    PORT
      LAYER M4 ;
        RECT  0 17.376 0.192 17.4 ;
    END
  END di[80]
  PIN di[81]
    DIRECTION INPUT ;
    USE SIGNAL ;
    PORT
      LAYER M4 ;
        RECT  0 17.52 0.192 17.544 ;
    END
  END di[81]
  PIN di[82]
    DIRECTION INPUT ;
    USE SIGNAL ;
    PORT
      LAYER M4 ;
        RECT  0 17.664 0.192 17.688 ;
    END
  END di[82]
  PIN di[83]
    DIRECTION INPUT ;
    USE SIGNAL ;
    PORT
      LAYER M4 ;
        RECT  0 17.856 0.192 17.88 ;
    END
  END di[83]
  PIN di[84]
    DIRECTION INPUT ;
    USE SIGNAL ;
    PORT
      LAYER M4 ;
        RECT  0 18 0.192 18.024 ;
    END
  END di[84]
  PIN di[85]
    DIRECTION INPUT ;
    USE SIGNAL ;
    PORT
      LAYER M4 ;
        RECT  0 18.144 0.192 18.168 ;
    END
  END di[85]
  PIN di[86]
    DIRECTION INPUT ;
    USE SIGNAL ;
    PORT
      LAYER M4 ;
        RECT  0 18.336 0.192 18.36 ;
    END
  END di[86]
  PIN di[87]
    DIRECTION INPUT ;
    USE SIGNAL ;
    PORT
      LAYER M4 ;
        RECT  0 18.48 0.192 18.504 ;
    END
  END di[87]
  PIN di[88]
    DIRECTION INPUT ;
    USE SIGNAL ;
    PORT
      LAYER M4 ;
        RECT  0 18.672 0.192 18.696 ;
    END
  END di[88]
  PIN di[89]
    DIRECTION INPUT ;
    USE SIGNAL ;
    PORT
      LAYER M4 ;
        RECT  0 18.816 0.192 18.84 ;
    END
  END di[89]
  PIN di[8]
    DIRECTION INPUT ;
    USE SIGNAL ;
    PORT
      LAYER M4 ;
        RECT  0 5.712 0.192 5.736 ;
    END
  END di[8]
  PIN di[90]
    DIRECTION INPUT ;
    USE SIGNAL ;
    PORT
      LAYER M4 ;
        RECT  0 18.96 0.192 18.984 ;
    END
  END di[90]
  PIN di[91]
    DIRECTION INPUT ;
    USE SIGNAL ;
    PORT
      LAYER M4 ;
        RECT  0 19.152 0.192 19.176 ;
    END
  END di[91]
  PIN di[92]
    DIRECTION INPUT ;
    USE SIGNAL ;
    PORT
      LAYER M4 ;
        RECT  0 19.296 0.192 19.32 ;
    END
  END di[92]
  PIN di[93]
    DIRECTION INPUT ;
    USE SIGNAL ;
    PORT
      LAYER M4 ;
        RECT  0 19.44 0.192 19.464 ;
    END
  END di[93]
  PIN di[94]
    DIRECTION INPUT ;
    USE SIGNAL ;
    PORT
      LAYER M4 ;
        RECT  0 19.632 0.192 19.656 ;
    END
  END di[94]
  PIN di[95]
    DIRECTION INPUT ;
    USE SIGNAL ;
    PORT
      LAYER M4 ;
        RECT  0 19.776 0.192 19.8 ;
    END
  END di[95]
  PIN di[96]
    DIRECTION INPUT ;
    USE SIGNAL ;
    PORT
      LAYER M4 ;
        RECT  0 19.968 0.192 19.992 ;
    END
  END di[96]
  PIN di[97]
    DIRECTION INPUT ;
    USE SIGNAL ;
    PORT
      LAYER M4 ;
        RECT  0 20.112 0.192 20.136 ;
    END
  END di[97]
  PIN di[98]
    DIRECTION INPUT ;
    USE SIGNAL ;
    PORT
      LAYER M4 ;
        RECT  0 20.256 0.192 20.28 ;
    END
  END di[98]
  PIN di[99]
    DIRECTION INPUT ;
    USE SIGNAL ;
    PORT
      LAYER M4 ;
        RECT  0 20.448 0.192 20.472 ;
    END
  END di[99]
  PIN di[9]
    DIRECTION INPUT ;
    USE SIGNAL ;
    PORT
      LAYER M4 ;
        RECT  0 5.856 0.192 5.88 ;
    END
  END di[9]
  PIN dq[0]
    DIRECTION OUTPUT ;
    USE SIGNAL ;
    PORT
      LAYER M4 ;
        RECT  36.528 4.416 36.72 4.44 ;
    END
  END dq[0]
  PIN dq[100]
    DIRECTION OUTPUT ;
    USE SIGNAL ;
    PORT
      LAYER M4 ;
        RECT  36.528 20.592 36.72 20.616 ;
    END
  END dq[100]
  PIN dq[101]
    DIRECTION OUTPUT ;
    USE SIGNAL ;
    PORT
      LAYER M4 ;
        RECT  36.528 20.736 36.72 20.76 ;
    END
  END dq[101]
  PIN dq[102]
    DIRECTION OUTPUT ;
    USE SIGNAL ;
    PORT
      LAYER M4 ;
        RECT  36.528 20.928 36.72 20.952 ;
    END
  END dq[102]
  PIN dq[103]
    DIRECTION OUTPUT ;
    USE SIGNAL ;
    PORT
      LAYER M4 ;
        RECT  36.528 21.072 36.72 21.096 ;
    END
  END dq[103]
  PIN dq[104]
    DIRECTION OUTPUT ;
    USE SIGNAL ;
    PORT
      LAYER M4 ;
        RECT  36.528 21.216 36.72 21.24 ;
    END
  END dq[104]
  PIN dq[105]
    DIRECTION OUTPUT ;
    USE SIGNAL ;
    PORT
      LAYER M4 ;
        RECT  36.528 21.408 36.72 21.432 ;
    END
  END dq[105]
  PIN dq[106]
    DIRECTION OUTPUT ;
    USE SIGNAL ;
    PORT
      LAYER M4 ;
        RECT  36.528 21.552 36.72 21.576 ;
    END
  END dq[106]
  PIN dq[107]
    DIRECTION OUTPUT ;
    USE SIGNAL ;
    PORT
      LAYER M4 ;
        RECT  36.528 21.744 36.72 21.768 ;
    END
  END dq[107]
  PIN dq[108]
    DIRECTION OUTPUT ;
    USE SIGNAL ;
    PORT
      LAYER M4 ;
        RECT  36.528 21.888 36.72 21.912 ;
    END
  END dq[108]
  PIN dq[109]
    DIRECTION OUTPUT ;
    USE SIGNAL ;
    PORT
      LAYER M4 ;
        RECT  36.528 22.032 36.72 22.056 ;
    END
  END dq[109]
  PIN dq[10]
    DIRECTION OUTPUT ;
    USE SIGNAL ;
    PORT
      LAYER M4 ;
        RECT  36.528 6.048 36.72 6.072 ;
    END
  END dq[10]
  PIN dq[110]
    DIRECTION OUTPUT ;
    USE SIGNAL ;
    PORT
      LAYER M4 ;
        RECT  36.528 22.224 36.72 22.248 ;
    END
  END dq[110]
  PIN dq[111]
    DIRECTION OUTPUT ;
    USE SIGNAL ;
    PORT
      LAYER M4 ;
        RECT  36.528 22.368 36.72 22.392 ;
    END
  END dq[111]
  PIN dq[112]
    DIRECTION OUTPUT ;
    USE SIGNAL ;
    PORT
      LAYER M4 ;
        RECT  36.528 22.512 36.72 22.536 ;
    END
  END dq[112]
  PIN dq[113]
    DIRECTION OUTPUT ;
    USE SIGNAL ;
    PORT
      LAYER M4 ;
        RECT  36.528 22.704 36.72 22.728 ;
    END
  END dq[113]
  PIN dq[114]
    DIRECTION OUTPUT ;
    USE SIGNAL ;
    PORT
      LAYER M4 ;
        RECT  36.528 22.848 36.72 22.872 ;
    END
  END dq[114]
  PIN dq[115]
    DIRECTION OUTPUT ;
    USE SIGNAL ;
    PORT
      LAYER M4 ;
        RECT  36.528 23.04 36.72 23.064 ;
    END
  END dq[115]
  PIN dq[116]
    DIRECTION OUTPUT ;
    USE SIGNAL ;
    PORT
      LAYER M4 ;
        RECT  36.528 23.184 36.72 23.208 ;
    END
  END dq[116]
  PIN dq[117]
    DIRECTION OUTPUT ;
    USE SIGNAL ;
    PORT
      LAYER M4 ;
        RECT  36.528 23.328 36.72 23.352 ;
    END
  END dq[117]
  PIN dq[118]
    DIRECTION OUTPUT ;
    USE SIGNAL ;
    PORT
      LAYER M4 ;
        RECT  36.528 23.52 36.72 23.544 ;
    END
  END dq[118]
  PIN dq[119]
    DIRECTION OUTPUT ;
    USE SIGNAL ;
    PORT
      LAYER M4 ;
        RECT  36.528 23.664 36.72 23.688 ;
    END
  END dq[119]
  PIN dq[11]
    DIRECTION OUTPUT ;
    USE SIGNAL ;
    PORT
      LAYER M4 ;
        RECT  36.528 6.192 36.72 6.216 ;
    END
  END dq[11]
  PIN dq[120]
    DIRECTION OUTPUT ;
    USE SIGNAL ;
    PORT
      LAYER M4 ;
        RECT  36.528 23.808 36.72 23.832 ;
    END
  END dq[120]
  PIN dq[121]
    DIRECTION OUTPUT ;
    USE SIGNAL ;
    PORT
      LAYER M4 ;
        RECT  36.528 24 36.72 24.024 ;
    END
  END dq[121]
  PIN dq[122]
    DIRECTION OUTPUT ;
    USE SIGNAL ;
    PORT
      LAYER M4 ;
        RECT  36.528 24.144 36.72 24.168 ;
    END
  END dq[122]
  PIN dq[123]
    DIRECTION OUTPUT ;
    USE SIGNAL ;
    PORT
      LAYER M4 ;
        RECT  36.528 24.336 36.72 24.36 ;
    END
  END dq[123]
  PIN dq[124]
    DIRECTION OUTPUT ;
    USE SIGNAL ;
    PORT
      LAYER M4 ;
        RECT  36.528 24.48 36.72 24.504 ;
    END
  END dq[124]
  PIN dq[125]
    DIRECTION OUTPUT ;
    USE SIGNAL ;
    PORT
      LAYER M4 ;
        RECT  36.528 24.624 36.72 24.648 ;
    END
  END dq[125]
  PIN dq[126]
    DIRECTION OUTPUT ;
    USE SIGNAL ;
    PORT
      LAYER M4 ;
        RECT  36.528 24.816 36.72 24.84 ;
    END
  END dq[126]
  PIN dq[127]
    DIRECTION OUTPUT ;
    USE SIGNAL ;
    PORT
      LAYER M4 ;
        RECT  36.528 24.96 36.72 24.984 ;
    END
  END dq[127]
  PIN dq[128]
    DIRECTION OUTPUT ;
    USE SIGNAL ;
    PORT
      LAYER M4 ;
        RECT  36.528 25.104 36.72 25.128 ;
    END
  END dq[128]
  PIN dq[129]
    DIRECTION OUTPUT ;
    USE SIGNAL ;
    PORT
      LAYER M4 ;
        RECT  36.528 25.296 36.72 25.32 ;
    END
  END dq[129]
  PIN dq[12]
    DIRECTION OUTPUT ;
    USE SIGNAL ;
    PORT
      LAYER M4 ;
        RECT  36.528 6.336 36.72 6.36 ;
    END
  END dq[12]
  PIN dq[130]
    DIRECTION OUTPUT ;
    USE SIGNAL ;
    PORT
      LAYER M4 ;
        RECT  36.528 25.44 36.72 25.464 ;
    END
  END dq[130]
  PIN dq[131]
    DIRECTION OUTPUT ;
    USE SIGNAL ;
    PORT
      LAYER M4 ;
        RECT  36.528 25.584 36.72 25.608 ;
    END
  END dq[131]
  PIN dq[132]
    DIRECTION OUTPUT ;
    USE SIGNAL ;
    PORT
      LAYER M4 ;
        RECT  36.528 25.776 36.72 25.8 ;
    END
  END dq[132]
  PIN dq[133]
    DIRECTION OUTPUT ;
    USE SIGNAL ;
    PORT
      LAYER M4 ;
        RECT  36.528 25.92 36.72 25.944 ;
    END
  END dq[133]
  PIN dq[134]
    DIRECTION OUTPUT ;
    USE SIGNAL ;
    PORT
      LAYER M4 ;
        RECT  36.528 26.112 36.72 26.136 ;
    END
  END dq[134]
  PIN dq[135]
    DIRECTION OUTPUT ;
    USE SIGNAL ;
    PORT
      LAYER M4 ;
        RECT  36.528 26.256 36.72 26.28 ;
    END
  END dq[135]
  PIN dq[136]
    DIRECTION OUTPUT ;
    USE SIGNAL ;
    PORT
      LAYER M4 ;
        RECT  36.528 26.4 36.72 26.424 ;
    END
  END dq[136]
  PIN dq[137]
    DIRECTION OUTPUT ;
    USE SIGNAL ;
    PORT
      LAYER M4 ;
        RECT  36.528 26.592 36.72 26.616 ;
    END
  END dq[137]
  PIN dq[138]
    DIRECTION OUTPUT ;
    USE SIGNAL ;
    PORT
      LAYER M4 ;
        RECT  36.528 26.736 36.72 26.76 ;
    END
  END dq[138]
  PIN dq[139]
    DIRECTION OUTPUT ;
    USE SIGNAL ;
    PORT
      LAYER M4 ;
        RECT  36.528 26.88 36.72 26.904 ;
    END
  END dq[139]
  PIN dq[13]
    DIRECTION OUTPUT ;
    USE SIGNAL ;
    PORT
      LAYER M4 ;
        RECT  36.528 6.528 36.72 6.552 ;
    END
  END dq[13]
  PIN dq[140]
    DIRECTION OUTPUT ;
    USE SIGNAL ;
    PORT
      LAYER M4 ;
        RECT  36.528 27.072 36.72 27.096 ;
    END
  END dq[140]
  PIN dq[141]
    DIRECTION OUTPUT ;
    USE SIGNAL ;
    PORT
      LAYER M4 ;
        RECT  36.528 27.216 36.72 27.24 ;
    END
  END dq[141]
  PIN dq[142]
    DIRECTION OUTPUT ;
    USE SIGNAL ;
    PORT
      LAYER M4 ;
        RECT  36.528 27.408 36.72 27.432 ;
    END
  END dq[142]
  PIN dq[143]
    DIRECTION OUTPUT ;
    USE SIGNAL ;
    PORT
      LAYER M4 ;
        RECT  36.528 27.552 36.72 27.576 ;
    END
  END dq[143]
  PIN dq[144]
    DIRECTION OUTPUT ;
    USE SIGNAL ;
    PORT
      LAYER M4 ;
        RECT  36.528 27.696 36.72 27.72 ;
    END
  END dq[144]
  PIN dq[145]
    DIRECTION OUTPUT ;
    USE SIGNAL ;
    PORT
      LAYER M4 ;
        RECT  36.528 27.888 36.72 27.912 ;
    END
  END dq[145]
  PIN dq[146]
    DIRECTION OUTPUT ;
    USE SIGNAL ;
    PORT
      LAYER M4 ;
        RECT  36.528 28.032 36.72 28.056 ;
    END
  END dq[146]
  PIN dq[147]
    DIRECTION OUTPUT ;
    USE SIGNAL ;
    PORT
      LAYER M4 ;
        RECT  36.528 28.176 36.72 28.2 ;
    END
  END dq[147]
  PIN dq[148]
    DIRECTION OUTPUT ;
    USE SIGNAL ;
    PORT
      LAYER M4 ;
        RECT  36.528 28.368 36.72 28.392 ;
    END
  END dq[148]
  PIN dq[149]
    DIRECTION OUTPUT ;
    USE SIGNAL ;
    PORT
      LAYER M4 ;
        RECT  36.528 28.512 36.72 28.536 ;
    END
  END dq[149]
  PIN dq[14]
    DIRECTION OUTPUT ;
    USE SIGNAL ;
    PORT
      LAYER M4 ;
        RECT  36.528 6.672 36.72 6.696 ;
    END
  END dq[14]
  PIN dq[150]
    DIRECTION OUTPUT ;
    USE SIGNAL ;
    PORT
      LAYER M4 ;
        RECT  36.528 28.704 36.72 28.728 ;
    END
  END dq[150]
  PIN dq[151]
    DIRECTION OUTPUT ;
    USE SIGNAL ;
    PORT
      LAYER M4 ;
        RECT  36.528 28.848 36.72 28.872 ;
    END
  END dq[151]
  PIN dq[152]
    DIRECTION OUTPUT ;
    USE SIGNAL ;
    PORT
      LAYER M4 ;
        RECT  36.528 28.992 36.72 29.016 ;
    END
  END dq[152]
  PIN dq[153]
    DIRECTION OUTPUT ;
    USE SIGNAL ;
    PORT
      LAYER M4 ;
        RECT  36.528 29.184 36.72 29.208 ;
    END
  END dq[153]
  PIN dq[154]
    DIRECTION OUTPUT ;
    USE SIGNAL ;
    PORT
      LAYER M4 ;
        RECT  36.528 29.328 36.72 29.352 ;
    END
  END dq[154]
  PIN dq[155]
    DIRECTION OUTPUT ;
    USE SIGNAL ;
    PORT
      LAYER M4 ;
        RECT  36.528 29.472 36.72 29.496 ;
    END
  END dq[155]
  PIN dq[156]
    DIRECTION OUTPUT ;
    USE SIGNAL ;
    PORT
      LAYER M4 ;
        RECT  36.528 29.664 36.72 29.688 ;
    END
  END dq[156]
  PIN dq[157]
    DIRECTION OUTPUT ;
    USE SIGNAL ;
    PORT
      LAYER M4 ;
        RECT  36.528 29.808 36.72 29.832 ;
    END
  END dq[157]
  PIN dq[158]
    DIRECTION OUTPUT ;
    USE SIGNAL ;
    PORT
      LAYER M4 ;
        RECT  36.528 29.952 36.72 29.976 ;
    END
  END dq[158]
  PIN dq[159]
    DIRECTION OUTPUT ;
    USE SIGNAL ;
    PORT
      LAYER M4 ;
        RECT  36.528 30.144 36.72 30.168 ;
    END
  END dq[159]
  PIN dq[15]
    DIRECTION OUTPUT ;
    USE SIGNAL ;
    PORT
      LAYER M4 ;
        RECT  36.528 6.816 36.72 6.84 ;
    END
  END dq[15]
  PIN dq[160]
    DIRECTION OUTPUT ;
    USE SIGNAL ;
    PORT
      LAYER M4 ;
        RECT  36.528 30.288 36.72 30.312 ;
    END
  END dq[160]
  PIN dq[161]
    DIRECTION OUTPUT ;
    USE SIGNAL ;
    PORT
      LAYER M4 ;
        RECT  36.528 30.48 36.72 30.504 ;
    END
  END dq[161]
  PIN dq[162]
    DIRECTION OUTPUT ;
    USE SIGNAL ;
    PORT
      LAYER M4 ;
        RECT  36.528 30.624 36.72 30.648 ;
    END
  END dq[162]
  PIN dq[163]
    DIRECTION OUTPUT ;
    USE SIGNAL ;
    PORT
      LAYER M4 ;
        RECT  36.528 30.768 36.72 30.792 ;
    END
  END dq[163]
  PIN dq[164]
    DIRECTION OUTPUT ;
    USE SIGNAL ;
    PORT
      LAYER M4 ;
        RECT  36.528 30.96 36.72 30.984 ;
    END
  END dq[164]
  PIN dq[165]
    DIRECTION OUTPUT ;
    USE SIGNAL ;
    PORT
      LAYER M4 ;
        RECT  36.528 31.104 36.72 31.128 ;
    END
  END dq[165]
  PIN dq[166]
    DIRECTION OUTPUT ;
    USE SIGNAL ;
    PORT
      LAYER M4 ;
        RECT  36.528 31.248 36.72 31.272 ;
    END
  END dq[166]
  PIN dq[167]
    DIRECTION OUTPUT ;
    USE SIGNAL ;
    PORT
      LAYER M4 ;
        RECT  36.528 31.44 36.72 31.464 ;
    END
  END dq[167]
  PIN dq[168]
    DIRECTION OUTPUT ;
    USE SIGNAL ;
    PORT
      LAYER M4 ;
        RECT  36.528 31.584 36.72 31.608 ;
    END
  END dq[168]
  PIN dq[169]
    DIRECTION OUTPUT ;
    USE SIGNAL ;
    PORT
      LAYER M4 ;
        RECT  36.528 31.776 36.72 31.8 ;
    END
  END dq[169]
  PIN dq[16]
    DIRECTION OUTPUT ;
    USE SIGNAL ;
    PORT
      LAYER M4 ;
        RECT  36.528 7.008 36.72 7.032 ;
    END
  END dq[16]
  PIN dq[170]
    DIRECTION OUTPUT ;
    USE SIGNAL ;
    PORT
      LAYER M4 ;
        RECT  36.528 31.92 36.72 31.944 ;
    END
  END dq[170]
  PIN dq[171]
    DIRECTION OUTPUT ;
    USE SIGNAL ;
    PORT
      LAYER M4 ;
        RECT  36.528 32.064 36.72 32.088 ;
    END
  END dq[171]
  PIN dq[172]
    DIRECTION OUTPUT ;
    USE SIGNAL ;
    PORT
      LAYER M4 ;
        RECT  36.528 32.256 36.72 32.28 ;
    END
  END dq[172]
  PIN dq[173]
    DIRECTION OUTPUT ;
    USE SIGNAL ;
    PORT
      LAYER M4 ;
        RECT  36.528 32.4 36.72 32.424 ;
    END
  END dq[173]
  PIN dq[174]
    DIRECTION OUTPUT ;
    USE SIGNAL ;
    PORT
      LAYER M4 ;
        RECT  36.528 32.544 36.72 32.568 ;
    END
  END dq[174]
  PIN dq[175]
    DIRECTION OUTPUT ;
    USE SIGNAL ;
    PORT
      LAYER M4 ;
        RECT  36.528 32.736 36.72 32.76 ;
    END
  END dq[175]
  PIN dq[176]
    DIRECTION OUTPUT ;
    USE SIGNAL ;
    PORT
      LAYER M4 ;
        RECT  36.528 32.88 36.72 32.904 ;
    END
  END dq[176]
  PIN dq[177]
    DIRECTION OUTPUT ;
    USE SIGNAL ;
    PORT
      LAYER M4 ;
        RECT  36.528 33.072 36.72 33.096 ;
    END
  END dq[177]
  PIN dq[178]
    DIRECTION OUTPUT ;
    USE SIGNAL ;
    PORT
      LAYER M4 ;
        RECT  36.528 33.216 36.72 33.24 ;
    END
  END dq[178]
  PIN dq[179]
    DIRECTION OUTPUT ;
    USE SIGNAL ;
    PORT
      LAYER M4 ;
        RECT  36.528 33.36 36.72 33.384 ;
    END
  END dq[179]
  PIN dq[17]
    DIRECTION OUTPUT ;
    USE SIGNAL ;
    PORT
      LAYER M4 ;
        RECT  36.528 7.152 36.72 7.176 ;
    END
  END dq[17]
  PIN dq[180]
    DIRECTION OUTPUT ;
    USE SIGNAL ;
    PORT
      LAYER M4 ;
        RECT  36.528 33.552 36.72 33.576 ;
    END
  END dq[180]
  PIN dq[181]
    DIRECTION OUTPUT ;
    USE SIGNAL ;
    PORT
      LAYER M4 ;
        RECT  36.528 33.696 36.72 33.72 ;
    END
  END dq[181]
  PIN dq[182]
    DIRECTION OUTPUT ;
    USE SIGNAL ;
    PORT
      LAYER M4 ;
        RECT  36.528 33.84 36.72 33.864 ;
    END
  END dq[182]
  PIN dq[183]
    DIRECTION OUTPUT ;
    USE SIGNAL ;
    PORT
      LAYER M4 ;
        RECT  36.528 34.032 36.72 34.056 ;
    END
  END dq[183]
  PIN dq[184]
    DIRECTION OUTPUT ;
    USE SIGNAL ;
    PORT
      LAYER M4 ;
        RECT  36.528 34.176 36.72 34.2 ;
    END
  END dq[184]
  PIN dq[185]
    DIRECTION OUTPUT ;
    USE SIGNAL ;
    PORT
      LAYER M4 ;
        RECT  36.528 34.32 36.72 34.344 ;
    END
  END dq[185]
  PIN dq[186]
    DIRECTION OUTPUT ;
    USE SIGNAL ;
    PORT
      LAYER M4 ;
        RECT  36.528 34.512 36.72 34.536 ;
    END
  END dq[186]
  PIN dq[187]
    DIRECTION OUTPUT ;
    USE SIGNAL ;
    PORT
      LAYER M4 ;
        RECT  36.528 34.656 36.72 34.68 ;
    END
  END dq[187]
  PIN dq[188]
    DIRECTION OUTPUT ;
    USE SIGNAL ;
    PORT
      LAYER M4 ;
        RECT  36.528 34.848 36.72 34.872 ;
    END
  END dq[188]
  PIN dq[189]
    DIRECTION OUTPUT ;
    USE SIGNAL ;
    PORT
      LAYER M4 ;
        RECT  36.528 34.992 36.72 35.016 ;
    END
  END dq[189]
  PIN dq[18]
    DIRECTION OUTPUT ;
    USE SIGNAL ;
    PORT
      LAYER M4 ;
        RECT  36.528 7.344 36.72 7.368 ;
    END
  END dq[18]
  PIN dq[190]
    DIRECTION OUTPUT ;
    USE SIGNAL ;
    PORT
      LAYER M4 ;
        RECT  36.528 35.136 36.72 35.16 ;
    END
  END dq[190]
  PIN dq[191]
    DIRECTION OUTPUT ;
    USE SIGNAL ;
    PORT
      LAYER M4 ;
        RECT  36.528 35.328 36.72 35.352 ;
    END
  END dq[191]
  PIN dq[192]
    DIRECTION OUTPUT ;
    USE SIGNAL ;
    PORT
      LAYER M4 ;
        RECT  36.528 35.472 36.72 35.496 ;
    END
  END dq[192]
  PIN dq[193]
    DIRECTION OUTPUT ;
    USE SIGNAL ;
    PORT
      LAYER M4 ;
        RECT  36.528 35.616 36.72 35.64 ;
    END
  END dq[193]
  PIN dq[194]
    DIRECTION OUTPUT ;
    USE SIGNAL ;
    PORT
      LAYER M4 ;
        RECT  36.528 35.808 36.72 35.832 ;
    END
  END dq[194]
  PIN dq[195]
    DIRECTION OUTPUT ;
    USE SIGNAL ;
    PORT
      LAYER M4 ;
        RECT  36.528 35.952 36.72 35.976 ;
    END
  END dq[195]
  PIN dq[196]
    DIRECTION OUTPUT ;
    USE SIGNAL ;
    PORT
      LAYER M4 ;
        RECT  36.528 36.144 36.72 36.168 ;
    END
  END dq[196]
  PIN dq[197]
    DIRECTION OUTPUT ;
    USE SIGNAL ;
    PORT
      LAYER M4 ;
        RECT  36.528 36.288 36.72 36.312 ;
    END
  END dq[197]
  PIN dq[198]
    DIRECTION OUTPUT ;
    USE SIGNAL ;
    PORT
      LAYER M4 ;
        RECT  36.528 36.432 36.72 36.456 ;
    END
  END dq[198]
  PIN dq[199]
    DIRECTION OUTPUT ;
    USE SIGNAL ;
    PORT
      LAYER M4 ;
        RECT  36.528 36.624 36.72 36.648 ;
    END
  END dq[199]
  PIN dq[19]
    DIRECTION OUTPUT ;
    USE SIGNAL ;
    PORT
      LAYER M4 ;
        RECT  36.528 7.488 36.72 7.512 ;
    END
  END dq[19]
  PIN dq[1]
    DIRECTION OUTPUT ;
    USE SIGNAL ;
    PORT
      LAYER M4 ;
        RECT  36.528 4.56 36.72 4.584 ;
    END
  END dq[1]
  PIN dq[200]
    DIRECTION OUTPUT ;
    USE SIGNAL ;
    PORT
      LAYER M4 ;
        RECT  36.528 36.768 36.72 36.792 ;
    END
  END dq[200]
  PIN dq[201]
    DIRECTION OUTPUT ;
    USE SIGNAL ;
    PORT
      LAYER M4 ;
        RECT  36.528 36.912 36.72 36.936 ;
    END
  END dq[201]
  PIN dq[202]
    DIRECTION OUTPUT ;
    USE SIGNAL ;
    PORT
      LAYER M4 ;
        RECT  36.528 37.104 36.72 37.128 ;
    END
  END dq[202]
  PIN dq[203]
    DIRECTION OUTPUT ;
    USE SIGNAL ;
    PORT
      LAYER M4 ;
        RECT  36.528 37.248 36.72 37.272 ;
    END
  END dq[203]
  PIN dq[204]
    DIRECTION OUTPUT ;
    USE SIGNAL ;
    PORT
      LAYER M4 ;
        RECT  36.528 37.44 36.72 37.464 ;
    END
  END dq[204]
  PIN dq[205]
    DIRECTION OUTPUT ;
    USE SIGNAL ;
    PORT
      LAYER M4 ;
        RECT  36.528 37.584 36.72 37.608 ;
    END
  END dq[205]
  PIN dq[206]
    DIRECTION OUTPUT ;
    USE SIGNAL ;
    PORT
      LAYER M4 ;
        RECT  36.528 37.728 36.72 37.752 ;
    END
  END dq[206]
  PIN dq[207]
    DIRECTION OUTPUT ;
    USE SIGNAL ;
    PORT
      LAYER M4 ;
        RECT  36.528 37.92 36.72 37.944 ;
    END
  END dq[207]
  PIN dq[208]
    DIRECTION OUTPUT ;
    USE SIGNAL ;
    PORT
      LAYER M4 ;
        RECT  36.528 38.064 36.72 38.088 ;
    END
  END dq[208]
  PIN dq[209]
    DIRECTION OUTPUT ;
    USE SIGNAL ;
    PORT
      LAYER M4 ;
        RECT  36.528 38.208 36.72 38.232 ;
    END
  END dq[209]
  PIN dq[20]
    DIRECTION OUTPUT ;
    USE SIGNAL ;
    PORT
      LAYER M4 ;
        RECT  36.528 7.632 36.72 7.656 ;
    END
  END dq[20]
  PIN dq[210]
    DIRECTION OUTPUT ;
    USE SIGNAL ;
    PORT
      LAYER M4 ;
        RECT  36.528 38.4 36.72 38.424 ;
    END
  END dq[210]
  PIN dq[211]
    DIRECTION OUTPUT ;
    USE SIGNAL ;
    PORT
      LAYER M4 ;
        RECT  36.528 38.544 36.72 38.568 ;
    END
  END dq[211]
  PIN dq[212]
    DIRECTION OUTPUT ;
    USE SIGNAL ;
    PORT
      LAYER M4 ;
        RECT  36.528 38.688 36.72 38.712 ;
    END
  END dq[212]
  PIN dq[213]
    DIRECTION OUTPUT ;
    USE SIGNAL ;
    PORT
      LAYER M4 ;
        RECT  36.528 38.88 36.72 38.904 ;
    END
  END dq[213]
  PIN dq[214]
    DIRECTION OUTPUT ;
    USE SIGNAL ;
    PORT
      LAYER M4 ;
        RECT  36.528 39.024 36.72 39.048 ;
    END
  END dq[214]
  PIN dq[215]
    DIRECTION OUTPUT ;
    USE SIGNAL ;
    PORT
      LAYER M4 ;
        RECT  36.528 39.216 36.72 39.24 ;
    END
  END dq[215]
  PIN dq[216]
    DIRECTION OUTPUT ;
    USE SIGNAL ;
    PORT
      LAYER M4 ;
        RECT  36.528 39.36 36.72 39.384 ;
    END
  END dq[216]
  PIN dq[217]
    DIRECTION OUTPUT ;
    USE SIGNAL ;
    PORT
      LAYER M4 ;
        RECT  36.528 39.504 36.72 39.528 ;
    END
  END dq[217]
  PIN dq[218]
    DIRECTION OUTPUT ;
    USE SIGNAL ;
    PORT
      LAYER M4 ;
        RECT  36.528 39.696 36.72 39.72 ;
    END
  END dq[218]
  PIN dq[219]
    DIRECTION OUTPUT ;
    USE SIGNAL ;
    PORT
      LAYER M4 ;
        RECT  36.528 39.84 36.72 39.864 ;
    END
  END dq[219]
  PIN dq[21]
    DIRECTION OUTPUT ;
    USE SIGNAL ;
    PORT
      LAYER M4 ;
        RECT  36.528 7.824 36.72 7.848 ;
    END
  END dq[21]
  PIN dq[220]
    DIRECTION OUTPUT ;
    USE SIGNAL ;
    PORT
      LAYER M4 ;
        RECT  36.528 39.984 36.72 40.008 ;
    END
  END dq[220]
  PIN dq[221]
    DIRECTION OUTPUT ;
    USE SIGNAL ;
    PORT
      LAYER M4 ;
        RECT  36.528 40.176 36.72 40.2 ;
    END
  END dq[221]
  PIN dq[222]
    DIRECTION OUTPUT ;
    USE SIGNAL ;
    PORT
      LAYER M4 ;
        RECT  36.528 40.32 36.72 40.344 ;
    END
  END dq[222]
  PIN dq[223]
    DIRECTION OUTPUT ;
    USE SIGNAL ;
    PORT
      LAYER M4 ;
        RECT  36.528 40.512 36.72 40.536 ;
    END
  END dq[223]
  PIN dq[224]
    DIRECTION OUTPUT ;
    USE SIGNAL ;
    PORT
      LAYER M4 ;
        RECT  36.528 40.656 36.72 40.68 ;
    END
  END dq[224]
  PIN dq[225]
    DIRECTION OUTPUT ;
    USE SIGNAL ;
    PORT
      LAYER M4 ;
        RECT  36.528 40.8 36.72 40.824 ;
    END
  END dq[225]
  PIN dq[226]
    DIRECTION OUTPUT ;
    USE SIGNAL ;
    PORT
      LAYER M4 ;
        RECT  36.528 40.992 36.72 41.016 ;
    END
  END dq[226]
  PIN dq[227]
    DIRECTION OUTPUT ;
    USE SIGNAL ;
    PORT
      LAYER M4 ;
        RECT  36.528 41.136 36.72 41.16 ;
    END
  END dq[227]
  PIN dq[228]
    DIRECTION OUTPUT ;
    USE SIGNAL ;
    PORT
      LAYER M4 ;
        RECT  36.528 41.28 36.72 41.304 ;
    END
  END dq[228]
  PIN dq[229]
    DIRECTION OUTPUT ;
    USE SIGNAL ;
    PORT
      LAYER M4 ;
        RECT  36.528 41.472 36.72 41.496 ;
    END
  END dq[229]
  PIN dq[22]
    DIRECTION OUTPUT ;
    USE SIGNAL ;
    PORT
      LAYER M4 ;
        RECT  36.528 7.968 36.72 7.992 ;
    END
  END dq[22]
  PIN dq[230]
    DIRECTION OUTPUT ;
    USE SIGNAL ;
    PORT
      LAYER M4 ;
        RECT  36.528 41.616 36.72 41.64 ;
    END
  END dq[230]
  PIN dq[231]
    DIRECTION OUTPUT ;
    USE SIGNAL ;
    PORT
      LAYER M4 ;
        RECT  36.528 41.808 36.72 41.832 ;
    END
  END dq[231]
  PIN dq[232]
    DIRECTION OUTPUT ;
    USE SIGNAL ;
    PORT
      LAYER M4 ;
        RECT  36.528 41.952 36.72 41.976 ;
    END
  END dq[232]
  PIN dq[233]
    DIRECTION OUTPUT ;
    USE SIGNAL ;
    PORT
      LAYER M4 ;
        RECT  36.528 42.096 36.72 42.12 ;
    END
  END dq[233]
  PIN dq[234]
    DIRECTION OUTPUT ;
    USE SIGNAL ;
    PORT
      LAYER M4 ;
        RECT  36.528 42.288 36.72 42.312 ;
    END
  END dq[234]
  PIN dq[235]
    DIRECTION OUTPUT ;
    USE SIGNAL ;
    PORT
      LAYER M4 ;
        RECT  36.528 42.432 36.72 42.456 ;
    END
  END dq[235]
  PIN dq[236]
    DIRECTION OUTPUT ;
    USE SIGNAL ;
    PORT
      LAYER M4 ;
        RECT  36.528 42.576 36.72 42.6 ;
    END
  END dq[236]
  PIN dq[237]
    DIRECTION OUTPUT ;
    USE SIGNAL ;
    PORT
      LAYER M4 ;
        RECT  36.528 42.768 36.72 42.792 ;
    END
  END dq[237]
  PIN dq[238]
    DIRECTION OUTPUT ;
    USE SIGNAL ;
    PORT
      LAYER M4 ;
        RECT  36.528 42.912 36.72 42.936 ;
    END
  END dq[238]
  PIN dq[239]
    DIRECTION OUTPUT ;
    USE SIGNAL ;
    PORT
      LAYER M4 ;
        RECT  36.528 43.104 36.72 43.128 ;
    END
  END dq[239]
  PIN dq[23]
    DIRECTION OUTPUT ;
    USE SIGNAL ;
    PORT
      LAYER M4 ;
        RECT  36.528 8.112 36.72 8.136 ;
    END
  END dq[23]
  PIN dq[240]
    DIRECTION OUTPUT ;
    USE SIGNAL ;
    PORT
      LAYER M4 ;
        RECT  36.528 43.248 36.72 43.272 ;
    END
  END dq[240]
  PIN dq[241]
    DIRECTION OUTPUT ;
    USE SIGNAL ;
    PORT
      LAYER M4 ;
        RECT  36.528 43.392 36.72 43.416 ;
    END
  END dq[241]
  PIN dq[242]
    DIRECTION OUTPUT ;
    USE SIGNAL ;
    PORT
      LAYER M4 ;
        RECT  36.528 43.584 36.72 43.608 ;
    END
  END dq[242]
  PIN dq[243]
    DIRECTION OUTPUT ;
    USE SIGNAL ;
    PORT
      LAYER M4 ;
        RECT  36.528 43.728 36.72 43.752 ;
    END
  END dq[243]
  PIN dq[244]
    DIRECTION OUTPUT ;
    USE SIGNAL ;
    PORT
      LAYER M4 ;
        RECT  36.528 43.872 36.72 43.896 ;
    END
  END dq[244]
  PIN dq[245]
    DIRECTION OUTPUT ;
    USE SIGNAL ;
    PORT
      LAYER M4 ;
        RECT  36.528 44.064 36.72 44.088 ;
    END
  END dq[245]
  PIN dq[246]
    DIRECTION OUTPUT ;
    USE SIGNAL ;
    PORT
      LAYER M4 ;
        RECT  36.528 44.208 36.72 44.232 ;
    END
  END dq[246]
  PIN dq[247]
    DIRECTION OUTPUT ;
    USE SIGNAL ;
    PORT
      LAYER M4 ;
        RECT  36.528 44.352 36.72 44.376 ;
    END
  END dq[247]
  PIN dq[248]
    DIRECTION OUTPUT ;
    USE SIGNAL ;
    PORT
      LAYER M4 ;
        RECT  36.528 44.544 36.72 44.568 ;
    END
  END dq[248]
  PIN dq[249]
    DIRECTION OUTPUT ;
    USE SIGNAL ;
    PORT
      LAYER M4 ;
        RECT  36.528 44.688 36.72 44.712 ;
    END
  END dq[249]
  PIN dq[24]
    DIRECTION OUTPUT ;
    USE SIGNAL ;
    PORT
      LAYER M4 ;
        RECT  36.528 8.304 36.72 8.328 ;
    END
  END dq[24]
  PIN dq[250]
    DIRECTION OUTPUT ;
    USE SIGNAL ;
    PORT
      LAYER M4 ;
        RECT  36.528 44.88 36.72 44.904 ;
    END
  END dq[250]
  PIN dq[251]
    DIRECTION OUTPUT ;
    USE SIGNAL ;
    PORT
      LAYER M4 ;
        RECT  36.528 45.024 36.72 45.048 ;
    END
  END dq[251]
  PIN dq[252]
    DIRECTION OUTPUT ;
    USE SIGNAL ;
    PORT
      LAYER M4 ;
        RECT  36.528 45.168 36.72 45.192 ;
    END
  END dq[252]
  PIN dq[253]
    DIRECTION OUTPUT ;
    USE SIGNAL ;
    PORT
      LAYER M4 ;
        RECT  36.528 45.36 36.72 45.384 ;
    END
  END dq[253]
  PIN dq[254]
    DIRECTION OUTPUT ;
    USE SIGNAL ;
    PORT
      LAYER M4 ;
        RECT  36.528 45.504 36.72 45.528 ;
    END
  END dq[254]
  PIN dq[255]
    DIRECTION OUTPUT ;
    USE SIGNAL ;
    PORT
      LAYER M4 ;
        RECT  36.528 45.648 36.72 45.672 ;
    END
  END dq[255]
  PIN dq[256]
    DIRECTION OUTPUT ;
    USE SIGNAL ;
    PORT
      LAYER M4 ;
        RECT  36.528 45.84 36.72 45.864 ;
    END
  END dq[256]
  PIN dq[257]
    DIRECTION OUTPUT ;
    USE SIGNAL ;
    PORT
      LAYER M4 ;
        RECT  36.528 45.984 36.72 46.008 ;
    END
  END dq[257]
  PIN dq[258]
    DIRECTION OUTPUT ;
    USE SIGNAL ;
    PORT
      LAYER M4 ;
        RECT  36.528 46.176 36.72 46.2 ;
    END
  END dq[258]
  PIN dq[259]
    DIRECTION OUTPUT ;
    USE SIGNAL ;
    PORT
      LAYER M4 ;
        RECT  36.528 46.32 36.72 46.344 ;
    END
  END dq[259]
  PIN dq[25]
    DIRECTION OUTPUT ;
    USE SIGNAL ;
    PORT
      LAYER M4 ;
        RECT  36.528 8.448 36.72 8.472 ;
    END
  END dq[25]
  PIN dq[260]
    DIRECTION OUTPUT ;
    USE SIGNAL ;
    PORT
      LAYER M4 ;
        RECT  36.528 46.464 36.72 46.488 ;
    END
  END dq[260]
  PIN dq[261]
    DIRECTION OUTPUT ;
    USE SIGNAL ;
    PORT
      LAYER M4 ;
        RECT  36.528 46.656 36.72 46.68 ;
    END
  END dq[261]
  PIN dq[262]
    DIRECTION OUTPUT ;
    USE SIGNAL ;
    PORT
      LAYER M4 ;
        RECT  36.528 46.8 36.72 46.824 ;
    END
  END dq[262]
  PIN dq[263]
    DIRECTION OUTPUT ;
    USE SIGNAL ;
    PORT
      LAYER M4 ;
        RECT  36.528 46.944 36.72 46.968 ;
    END
  END dq[263]
  PIN dq[264]
    DIRECTION OUTPUT ;
    USE SIGNAL ;
    PORT
      LAYER M4 ;
        RECT  36.528 47.136 36.72 47.16 ;
    END
  END dq[264]
  PIN dq[265]
    DIRECTION OUTPUT ;
    USE SIGNAL ;
    PORT
      LAYER M4 ;
        RECT  36.528 47.28 36.72 47.304 ;
    END
  END dq[265]
  PIN dq[266]
    DIRECTION OUTPUT ;
    USE SIGNAL ;
    PORT
      LAYER M4 ;
        RECT  36.528 47.472 36.72 47.496 ;
    END
  END dq[266]
  PIN dq[267]
    DIRECTION OUTPUT ;
    USE SIGNAL ;
    PORT
      LAYER M4 ;
        RECT  36.528 47.616 36.72 47.64 ;
    END
  END dq[267]
  PIN dq[268]
    DIRECTION OUTPUT ;
    USE SIGNAL ;
    PORT
      LAYER M4 ;
        RECT  36.528 47.76 36.72 47.784 ;
    END
  END dq[268]
  PIN dq[269]
    DIRECTION OUTPUT ;
    USE SIGNAL ;
    PORT
      LAYER M4 ;
        RECT  36.528 47.952 36.72 47.976 ;
    END
  END dq[269]
  PIN dq[26]
    DIRECTION OUTPUT ;
    USE SIGNAL ;
    PORT
      LAYER M4 ;
        RECT  36.528 8.64 36.72 8.664 ;
    END
  END dq[26]
  PIN dq[270]
    DIRECTION OUTPUT ;
    USE SIGNAL ;
    PORT
      LAYER M4 ;
        RECT  36.528 48.096 36.72 48.12 ;
    END
  END dq[270]
  PIN dq[271]
    DIRECTION OUTPUT ;
    USE SIGNAL ;
    PORT
      LAYER M4 ;
        RECT  36.528 48.24 36.72 48.264 ;
    END
  END dq[271]
  PIN dq[272]
    DIRECTION OUTPUT ;
    USE SIGNAL ;
    PORT
      LAYER M4 ;
        RECT  36.528 48.432 36.72 48.456 ;
    END
  END dq[272]
  PIN dq[273]
    DIRECTION OUTPUT ;
    USE SIGNAL ;
    PORT
      LAYER M4 ;
        RECT  36.528 48.576 36.72 48.6 ;
    END
  END dq[273]
  PIN dq[274]
    DIRECTION OUTPUT ;
    USE SIGNAL ;
    PORT
      LAYER M4 ;
        RECT  36.528 48.72 36.72 48.744 ;
    END
  END dq[274]
  PIN dq[275]
    DIRECTION OUTPUT ;
    USE SIGNAL ;
    PORT
      LAYER M4 ;
        RECT  36.528 48.912 36.72 48.936 ;
    END
  END dq[275]
  PIN dq[276]
    DIRECTION OUTPUT ;
    USE SIGNAL ;
    PORT
      LAYER M4 ;
        RECT  36.528 49.056 36.72 49.08 ;
    END
  END dq[276]
  PIN dq[277]
    DIRECTION OUTPUT ;
    USE SIGNAL ;
    PORT
      LAYER M4 ;
        RECT  36.528 49.248 36.72 49.272 ;
    END
  END dq[277]
  PIN dq[278]
    DIRECTION OUTPUT ;
    USE SIGNAL ;
    PORT
      LAYER M4 ;
        RECT  36.528 49.392 36.72 49.416 ;
    END
  END dq[278]
  PIN dq[279]
    DIRECTION OUTPUT ;
    USE SIGNAL ;
    PORT
      LAYER M4 ;
        RECT  36.528 49.536 36.72 49.56 ;
    END
  END dq[279]
  PIN dq[27]
    DIRECTION OUTPUT ;
    USE SIGNAL ;
    PORT
      LAYER M4 ;
        RECT  36.528 8.784 36.72 8.808 ;
    END
  END dq[27]
  PIN dq[280]
    DIRECTION OUTPUT ;
    USE SIGNAL ;
    PORT
      LAYER M4 ;
        RECT  36.528 49.728 36.72 49.752 ;
    END
  END dq[280]
  PIN dq[281]
    DIRECTION OUTPUT ;
    USE SIGNAL ;
    PORT
      LAYER M4 ;
        RECT  36.528 49.872 36.72 49.896 ;
    END
  END dq[281]
  PIN dq[282]
    DIRECTION OUTPUT ;
    USE SIGNAL ;
    PORT
      LAYER M4 ;
        RECT  36.528 50.016 36.72 50.04 ;
    END
  END dq[282]
  PIN dq[283]
    DIRECTION OUTPUT ;
    USE SIGNAL ;
    PORT
      LAYER M4 ;
        RECT  36.528 50.208 36.72 50.232 ;
    END
  END dq[283]
  PIN dq[284]
    DIRECTION OUTPUT ;
    USE SIGNAL ;
    PORT
      LAYER M4 ;
        RECT  36.528 50.352 36.72 50.376 ;
    END
  END dq[284]
  PIN dq[285]
    DIRECTION OUTPUT ;
    USE SIGNAL ;
    PORT
      LAYER M4 ;
        RECT  36.528 50.544 36.72 50.568 ;
    END
  END dq[285]
  PIN dq[286]
    DIRECTION OUTPUT ;
    USE SIGNAL ;
    PORT
      LAYER M4 ;
        RECT  36.528 50.688 36.72 50.712 ;
    END
  END dq[286]
  PIN dq[287]
    DIRECTION OUTPUT ;
    USE SIGNAL ;
    PORT
      LAYER M4 ;
        RECT  36.528 50.832 36.72 50.856 ;
    END
  END dq[287]
  PIN dq[288]
    DIRECTION OUTPUT ;
    USE SIGNAL ;
    PORT
      LAYER M4 ;
        RECT  36.528 51.024 36.72 51.048 ;
    END
  END dq[288]
  PIN dq[289]
    DIRECTION OUTPUT ;
    USE SIGNAL ;
    PORT
      LAYER M4 ;
        RECT  36.528 51.168 36.72 51.192 ;
    END
  END dq[289]
  PIN dq[28]
    DIRECTION OUTPUT ;
    USE SIGNAL ;
    PORT
      LAYER M4 ;
        RECT  36.528 8.928 36.72 8.952 ;
    END
  END dq[28]
  PIN dq[290]
    DIRECTION OUTPUT ;
    USE SIGNAL ;
    PORT
      LAYER M4 ;
        RECT  36.528 51.312 36.72 51.336 ;
    END
  END dq[290]
  PIN dq[291]
    DIRECTION OUTPUT ;
    USE SIGNAL ;
    PORT
      LAYER M4 ;
        RECT  36.528 51.504 36.72 51.528 ;
    END
  END dq[291]
  PIN dq[292]
    DIRECTION OUTPUT ;
    USE SIGNAL ;
    PORT
      LAYER M4 ;
        RECT  36.528 51.648 36.72 51.672 ;
    END
  END dq[292]
  PIN dq[293]
    DIRECTION OUTPUT ;
    USE SIGNAL ;
    PORT
      LAYER M4 ;
        RECT  36.528 51.84 36.72 51.864 ;
    END
  END dq[293]
  PIN dq[294]
    DIRECTION OUTPUT ;
    USE SIGNAL ;
    PORT
      LAYER M4 ;
        RECT  36.528 51.984 36.72 52.008 ;
    END
  END dq[294]
  PIN dq[295]
    DIRECTION OUTPUT ;
    USE SIGNAL ;
    PORT
      LAYER M4 ;
        RECT  36.528 52.128 36.72 52.152 ;
    END
  END dq[295]
  PIN dq[296]
    DIRECTION OUTPUT ;
    USE SIGNAL ;
    PORT
      LAYER M4 ;
        RECT  36.528 52.32 36.72 52.344 ;
    END
  END dq[296]
  PIN dq[297]
    DIRECTION OUTPUT ;
    USE SIGNAL ;
    PORT
      LAYER M4 ;
        RECT  36.528 52.464 36.72 52.488 ;
    END
  END dq[297]
  PIN dq[298]
    DIRECTION OUTPUT ;
    USE SIGNAL ;
    PORT
      LAYER M4 ;
        RECT  36.528 52.608 36.72 52.632 ;
    END
  END dq[298]
  PIN dq[299]
    DIRECTION OUTPUT ;
    USE SIGNAL ;
    PORT
      LAYER M4 ;
        RECT  36.528 52.8 36.72 52.824 ;
    END
  END dq[299]
  PIN dq[29]
    DIRECTION OUTPUT ;
    USE SIGNAL ;
    PORT
      LAYER M4 ;
        RECT  36.528 9.12 36.72 9.144 ;
    END
  END dq[29]
  PIN dq[2]
    DIRECTION OUTPUT ;
    USE SIGNAL ;
    PORT
      LAYER M4 ;
        RECT  36.528 4.752 36.72 4.776 ;
    END
  END dq[2]
  PIN dq[300]
    DIRECTION OUTPUT ;
    USE SIGNAL ;
    PORT
      LAYER M4 ;
        RECT  36.528 52.944 36.72 52.968 ;
    END
  END dq[300]
  PIN dq[301]
    DIRECTION OUTPUT ;
    USE SIGNAL ;
    PORT
      LAYER M4 ;
        RECT  36.528 53.088 36.72 53.112 ;
    END
  END dq[301]
  PIN dq[302]
    DIRECTION OUTPUT ;
    USE SIGNAL ;
    PORT
      LAYER M4 ;
        RECT  36.528 53.28 36.72 53.304 ;
    END
  END dq[302]
  PIN dq[303]
    DIRECTION OUTPUT ;
    USE SIGNAL ;
    PORT
      LAYER M4 ;
        RECT  36.528 53.424 36.72 53.448 ;
    END
  END dq[303]
  PIN dq[304]
    DIRECTION OUTPUT ;
    USE SIGNAL ;
    PORT
      LAYER M4 ;
        RECT  36.528 53.616 36.72 53.64 ;
    END
  END dq[304]
  PIN dq[305]
    DIRECTION OUTPUT ;
    USE SIGNAL ;
    PORT
      LAYER M4 ;
        RECT  36.528 53.76 36.72 53.784 ;
    END
  END dq[305]
  PIN dq[306]
    DIRECTION OUTPUT ;
    USE SIGNAL ;
    PORT
      LAYER M4 ;
        RECT  36.528 53.904 36.72 53.928 ;
    END
  END dq[306]
  PIN dq[307]
    DIRECTION OUTPUT ;
    USE SIGNAL ;
    PORT
      LAYER M4 ;
        RECT  36.528 54.096 36.72 54.12 ;
    END
  END dq[307]
  PIN dq[308]
    DIRECTION OUTPUT ;
    USE SIGNAL ;
    PORT
      LAYER M4 ;
        RECT  36.528 54.24 36.72 54.264 ;
    END
  END dq[308]
  PIN dq[309]
    DIRECTION OUTPUT ;
    USE SIGNAL ;
    PORT
      LAYER M4 ;
        RECT  36.528 54.384 36.72 54.408 ;
    END
  END dq[309]
  PIN dq[30]
    DIRECTION OUTPUT ;
    USE SIGNAL ;
    PORT
      LAYER M4 ;
        RECT  36.528 9.264 36.72 9.288 ;
    END
  END dq[30]
  PIN dq[310]
    DIRECTION OUTPUT ;
    USE SIGNAL ;
    PORT
      LAYER M4 ;
        RECT  36.528 54.576 36.72 54.6 ;
    END
  END dq[310]
  PIN dq[311]
    DIRECTION OUTPUT ;
    USE SIGNAL ;
    PORT
      LAYER M4 ;
        RECT  36.528 54.72 36.72 54.744 ;
    END
  END dq[311]
  PIN dq[312]
    DIRECTION OUTPUT ;
    USE SIGNAL ;
    PORT
      LAYER M4 ;
        RECT  36.528 54.912 36.72 54.936 ;
    END
  END dq[312]
  PIN dq[313]
    DIRECTION OUTPUT ;
    USE SIGNAL ;
    PORT
      LAYER M4 ;
        RECT  36.528 55.056 36.72 55.08 ;
    END
  END dq[313]
  PIN dq[314]
    DIRECTION OUTPUT ;
    USE SIGNAL ;
    PORT
      LAYER M4 ;
        RECT  36.528 55.2 36.72 55.224 ;
    END
  END dq[314]
  PIN dq[315]
    DIRECTION OUTPUT ;
    USE SIGNAL ;
    PORT
      LAYER M4 ;
        RECT  36.528 55.392 36.72 55.416 ;
    END
  END dq[315]
  PIN dq[316]
    DIRECTION OUTPUT ;
    USE SIGNAL ;
    PORT
      LAYER M4 ;
        RECT  36.528 55.536 36.72 55.56 ;
    END
  END dq[316]
  PIN dq[317]
    DIRECTION OUTPUT ;
    USE SIGNAL ;
    PORT
      LAYER M4 ;
        RECT  36.528 55.68 36.72 55.704 ;
    END
  END dq[317]
  PIN dq[318]
    DIRECTION OUTPUT ;
    USE SIGNAL ;
    PORT
      LAYER M4 ;
        RECT  36.528 55.872 36.72 55.896 ;
    END
  END dq[318]
  PIN dq[319]
    DIRECTION OUTPUT ;
    USE SIGNAL ;
    PORT
      LAYER M4 ;
        RECT  36.528 56.016 36.72 56.04 ;
    END
  END dq[319]
  PIN dq[31]
    DIRECTION OUTPUT ;
    USE SIGNAL ;
    PORT
      LAYER M4 ;
        RECT  36.528 9.408 36.72 9.432 ;
    END
  END dq[31]
  PIN dq[320]
    DIRECTION OUTPUT ;
    USE SIGNAL ;
    PORT
      LAYER M4 ;
        RECT  36.528 56.208 36.72 56.232 ;
    END
  END dq[320]
  PIN dq[321]
    DIRECTION OUTPUT ;
    USE SIGNAL ;
    PORT
      LAYER M4 ;
        RECT  36.528 56.352 36.72 56.376 ;
    END
  END dq[321]
  PIN dq[322]
    DIRECTION OUTPUT ;
    USE SIGNAL ;
    PORT
      LAYER M4 ;
        RECT  36.528 56.496 36.72 56.52 ;
    END
  END dq[322]
  PIN dq[323]
    DIRECTION OUTPUT ;
    USE SIGNAL ;
    PORT
      LAYER M4 ;
        RECT  36.528 56.688 36.72 56.712 ;
    END
  END dq[323]
  PIN dq[324]
    DIRECTION OUTPUT ;
    USE SIGNAL ;
    PORT
      LAYER M4 ;
        RECT  36.528 56.832 36.72 56.856 ;
    END
  END dq[324]
  PIN dq[325]
    DIRECTION OUTPUT ;
    USE SIGNAL ;
    PORT
      LAYER M4 ;
        RECT  36.528 56.976 36.72 57 ;
    END
  END dq[325]
  PIN dq[326]
    DIRECTION OUTPUT ;
    USE SIGNAL ;
    PORT
      LAYER M4 ;
        RECT  36.528 57.168 36.72 57.192 ;
    END
  END dq[326]
  PIN dq[327]
    DIRECTION OUTPUT ;
    USE SIGNAL ;
    PORT
      LAYER M4 ;
        RECT  36.528 57.312 36.72 57.336 ;
    END
  END dq[327]
  PIN dq[328]
    DIRECTION OUTPUT ;
    USE SIGNAL ;
    PORT
      LAYER M4 ;
        RECT  36.528 57.456 36.72 57.48 ;
    END
  END dq[328]
  PIN dq[329]
    DIRECTION OUTPUT ;
    USE SIGNAL ;
    PORT
      LAYER M4 ;
        RECT  36.528 57.648 36.72 57.672 ;
    END
  END dq[329]
  PIN dq[32]
    DIRECTION OUTPUT ;
    USE SIGNAL ;
    PORT
      LAYER M4 ;
        RECT  36.528 9.6 36.72 9.624 ;
    END
  END dq[32]
  PIN dq[330]
    DIRECTION OUTPUT ;
    USE SIGNAL ;
    PORT
      LAYER M4 ;
        RECT  36.528 57.792 36.72 57.816 ;
    END
  END dq[330]
  PIN dq[331]
    DIRECTION OUTPUT ;
    USE SIGNAL ;
    PORT
      LAYER M4 ;
        RECT  36.528 57.984 36.72 58.008 ;
    END
  END dq[331]
  PIN dq[332]
    DIRECTION OUTPUT ;
    USE SIGNAL ;
    PORT
      LAYER M4 ;
        RECT  36.528 58.128 36.72 58.152 ;
    END
  END dq[332]
  PIN dq[333]
    DIRECTION OUTPUT ;
    USE SIGNAL ;
    PORT
      LAYER M4 ;
        RECT  36.528 58.272 36.72 58.296 ;
    END
  END dq[333]
  PIN dq[334]
    DIRECTION OUTPUT ;
    USE SIGNAL ;
    PORT
      LAYER M4 ;
        RECT  36.528 58.464 36.72 58.488 ;
    END
  END dq[334]
  PIN dq[335]
    DIRECTION OUTPUT ;
    USE SIGNAL ;
    PORT
      LAYER M4 ;
        RECT  36.528 58.608 36.72 58.632 ;
    END
  END dq[335]
  PIN dq[336]
    DIRECTION OUTPUT ;
    USE SIGNAL ;
    PORT
      LAYER M4 ;
        RECT  36.528 58.752 36.72 58.776 ;
    END
  END dq[336]
  PIN dq[337]
    DIRECTION OUTPUT ;
    USE SIGNAL ;
    PORT
      LAYER M4 ;
        RECT  36.528 58.944 36.72 58.968 ;
    END
  END dq[337]
  PIN dq[338]
    DIRECTION OUTPUT ;
    USE SIGNAL ;
    PORT
      LAYER M4 ;
        RECT  36.528 59.088 36.72 59.112 ;
    END
  END dq[338]
  PIN dq[339]
    DIRECTION OUTPUT ;
    USE SIGNAL ;
    PORT
      LAYER M4 ;
        RECT  36.528 59.28 36.72 59.304 ;
    END
  END dq[339]
  PIN dq[33]
    DIRECTION OUTPUT ;
    USE SIGNAL ;
    PORT
      LAYER M4 ;
        RECT  36.528 9.744 36.72 9.768 ;
    END
  END dq[33]
  PIN dq[340]
    DIRECTION OUTPUT ;
    USE SIGNAL ;
    PORT
      LAYER M4 ;
        RECT  36.528 59.424 36.72 59.448 ;
    END
  END dq[340]
  PIN dq[341]
    DIRECTION OUTPUT ;
    USE SIGNAL ;
    PORT
      LAYER M4 ;
        RECT  36.528 59.568 36.72 59.592 ;
    END
  END dq[341]
  PIN dq[342]
    DIRECTION OUTPUT ;
    USE SIGNAL ;
    PORT
      LAYER M4 ;
        RECT  36.528 59.76 36.72 59.784 ;
    END
  END dq[342]
  PIN dq[343]
    DIRECTION OUTPUT ;
    USE SIGNAL ;
    PORT
      LAYER M4 ;
        RECT  36.528 59.904 36.72 59.928 ;
    END
  END dq[343]
  PIN dq[344]
    DIRECTION OUTPUT ;
    USE SIGNAL ;
    PORT
      LAYER M4 ;
        RECT  36.528 60.048 36.72 60.072 ;
    END
  END dq[344]
  PIN dq[345]
    DIRECTION OUTPUT ;
    USE SIGNAL ;
    PORT
      LAYER M4 ;
        RECT  36.528 60.24 36.72 60.264 ;
    END
  END dq[345]
  PIN dq[346]
    DIRECTION OUTPUT ;
    USE SIGNAL ;
    PORT
      LAYER M4 ;
        RECT  36.528 60.384 36.72 60.408 ;
    END
  END dq[346]
  PIN dq[347]
    DIRECTION OUTPUT ;
    USE SIGNAL ;
    PORT
      LAYER M4 ;
        RECT  36.528 60.576 36.72 60.6 ;
    END
  END dq[347]
  PIN dq[348]
    DIRECTION OUTPUT ;
    USE SIGNAL ;
    PORT
      LAYER M4 ;
        RECT  36.528 60.72 36.72 60.744 ;
    END
  END dq[348]
  PIN dq[349]
    DIRECTION OUTPUT ;
    USE SIGNAL ;
    PORT
      LAYER M4 ;
        RECT  36.528 60.864 36.72 60.888 ;
    END
  END dq[349]
  PIN dq[34]
    DIRECTION OUTPUT ;
    USE SIGNAL ;
    PORT
      LAYER M4 ;
        RECT  36.528 9.936 36.72 9.96 ;
    END
  END dq[34]
  PIN dq[350]
    DIRECTION OUTPUT ;
    USE SIGNAL ;
    PORT
      LAYER M4 ;
        RECT  36.528 61.056 36.72 61.08 ;
    END
  END dq[350]
  PIN dq[351]
    DIRECTION OUTPUT ;
    USE SIGNAL ;
    PORT
      LAYER M4 ;
        RECT  36.528 61.2 36.72 61.224 ;
    END
  END dq[351]
  PIN dq[352]
    DIRECTION OUTPUT ;
    USE SIGNAL ;
    PORT
      LAYER M4 ;
        RECT  36.528 61.344 36.72 61.368 ;
    END
  END dq[352]
  PIN dq[353]
    DIRECTION OUTPUT ;
    USE SIGNAL ;
    PORT
      LAYER M4 ;
        RECT  36.528 61.536 36.72 61.56 ;
    END
  END dq[353]
  PIN dq[354]
    DIRECTION OUTPUT ;
    USE SIGNAL ;
    PORT
      LAYER M4 ;
        RECT  36.528 61.68 36.72 61.704 ;
    END
  END dq[354]
  PIN dq[355]
    DIRECTION OUTPUT ;
    USE SIGNAL ;
    PORT
      LAYER M4 ;
        RECT  36.528 61.824 36.72 61.848 ;
    END
  END dq[355]
  PIN dq[356]
    DIRECTION OUTPUT ;
    USE SIGNAL ;
    PORT
      LAYER M4 ;
        RECT  36.528 62.016 36.72 62.04 ;
    END
  END dq[356]
  PIN dq[357]
    DIRECTION OUTPUT ;
    USE SIGNAL ;
    PORT
      LAYER M4 ;
        RECT  36.528 62.16 36.72 62.184 ;
    END
  END dq[357]
  PIN dq[358]
    DIRECTION OUTPUT ;
    USE SIGNAL ;
    PORT
      LAYER M4 ;
        RECT  36.528 62.352 36.72 62.376 ;
    END
  END dq[358]
  PIN dq[359]
    DIRECTION OUTPUT ;
    USE SIGNAL ;
    PORT
      LAYER M4 ;
        RECT  36.528 62.496 36.72 62.52 ;
    END
  END dq[359]
  PIN dq[35]
    DIRECTION OUTPUT ;
    USE SIGNAL ;
    PORT
      LAYER M4 ;
        RECT  36.528 10.08 36.72 10.104 ;
    END
  END dq[35]
  PIN dq[360]
    DIRECTION OUTPUT ;
    USE SIGNAL ;
    PORT
      LAYER M4 ;
        RECT  36.528 62.64 36.72 62.664 ;
    END
  END dq[360]
  PIN dq[361]
    DIRECTION OUTPUT ;
    USE SIGNAL ;
    PORT
      LAYER M4 ;
        RECT  36.528 62.832 36.72 62.856 ;
    END
  END dq[361]
  PIN dq[362]
    DIRECTION OUTPUT ;
    USE SIGNAL ;
    PORT
      LAYER M4 ;
        RECT  36.528 62.976 36.72 63 ;
    END
  END dq[362]
  PIN dq[363]
    DIRECTION OUTPUT ;
    USE SIGNAL ;
    PORT
      LAYER M4 ;
        RECT  36.528 63.12 36.72 63.144 ;
    END
  END dq[363]
  PIN dq[364]
    DIRECTION OUTPUT ;
    USE SIGNAL ;
    PORT
      LAYER M4 ;
        RECT  36.528 63.312 36.72 63.336 ;
    END
  END dq[364]
  PIN dq[365]
    DIRECTION OUTPUT ;
    USE SIGNAL ;
    PORT
      LAYER M4 ;
        RECT  36.528 63.456 36.72 63.48 ;
    END
  END dq[365]
  PIN dq[366]
    DIRECTION OUTPUT ;
    USE SIGNAL ;
    PORT
      LAYER M4 ;
        RECT  36.528 63.648 36.72 63.672 ;
    END
  END dq[366]
  PIN dq[367]
    DIRECTION OUTPUT ;
    USE SIGNAL ;
    PORT
      LAYER M4 ;
        RECT  36.528 63.792 36.72 63.816 ;
    END
  END dq[367]
  PIN dq[368]
    DIRECTION OUTPUT ;
    USE SIGNAL ;
    PORT
      LAYER M4 ;
        RECT  36.528 63.936 36.72 63.96 ;
    END
  END dq[368]
  PIN dq[369]
    DIRECTION OUTPUT ;
    USE SIGNAL ;
    PORT
      LAYER M4 ;
        RECT  36.528 64.128 36.72 64.152 ;
    END
  END dq[369]
  PIN dq[36]
    DIRECTION OUTPUT ;
    USE SIGNAL ;
    PORT
      LAYER M4 ;
        RECT  36.528 10.224 36.72 10.248 ;
    END
  END dq[36]
  PIN dq[370]
    DIRECTION OUTPUT ;
    USE SIGNAL ;
    PORT
      LAYER M4 ;
        RECT  36.528 64.272 36.72 64.296 ;
    END
  END dq[370]
  PIN dq[371]
    DIRECTION OUTPUT ;
    USE SIGNAL ;
    PORT
      LAYER M4 ;
        RECT  36.528 64.416 36.72 64.44 ;
    END
  END dq[371]
  PIN dq[372]
    DIRECTION OUTPUT ;
    USE SIGNAL ;
    PORT
      LAYER M4 ;
        RECT  36.528 64.608 36.72 64.632 ;
    END
  END dq[372]
  PIN dq[373]
    DIRECTION OUTPUT ;
    USE SIGNAL ;
    PORT
      LAYER M4 ;
        RECT  36.528 64.752 36.72 64.776 ;
    END
  END dq[373]
  PIN dq[374]
    DIRECTION OUTPUT ;
    USE SIGNAL ;
    PORT
      LAYER M4 ;
        RECT  36.528 64.944 36.72 64.968 ;
    END
  END dq[374]
  PIN dq[375]
    DIRECTION OUTPUT ;
    USE SIGNAL ;
    PORT
      LAYER M4 ;
        RECT  36.528 65.088 36.72 65.112 ;
    END
  END dq[375]
  PIN dq[376]
    DIRECTION OUTPUT ;
    USE SIGNAL ;
    PORT
      LAYER M4 ;
        RECT  36.528 65.232 36.72 65.256 ;
    END
  END dq[376]
  PIN dq[377]
    DIRECTION OUTPUT ;
    USE SIGNAL ;
    PORT
      LAYER M4 ;
        RECT  36.528 65.424 36.72 65.448 ;
    END
  END dq[377]
  PIN dq[378]
    DIRECTION OUTPUT ;
    USE SIGNAL ;
    PORT
      LAYER M4 ;
        RECT  36.528 65.568 36.72 65.592 ;
    END
  END dq[378]
  PIN dq[379]
    DIRECTION OUTPUT ;
    USE SIGNAL ;
    PORT
      LAYER M4 ;
        RECT  36.528 65.712 36.72 65.736 ;
    END
  END dq[379]
  PIN dq[37]
    DIRECTION OUTPUT ;
    USE SIGNAL ;
    PORT
      LAYER M4 ;
        RECT  36.528 10.416 36.72 10.44 ;
    END
  END dq[37]
  PIN dq[380]
    DIRECTION OUTPUT ;
    USE SIGNAL ;
    PORT
      LAYER M4 ;
        RECT  36.528 65.904 36.72 65.928 ;
    END
  END dq[380]
  PIN dq[381]
    DIRECTION OUTPUT ;
    USE SIGNAL ;
    PORT
      LAYER M4 ;
        RECT  36.528 66.048 36.72 66.072 ;
    END
  END dq[381]
  PIN dq[382]
    DIRECTION OUTPUT ;
    USE SIGNAL ;
    PORT
      LAYER M4 ;
        RECT  36.528 66.192 36.72 66.216 ;
    END
  END dq[382]
  PIN dq[383]
    DIRECTION OUTPUT ;
    USE SIGNAL ;
    PORT
      LAYER M4 ;
        RECT  36.528 66.384 36.72 66.408 ;
    END
  END dq[383]
  PIN dq[384]
    DIRECTION OUTPUT ;
    USE SIGNAL ;
    PORT
      LAYER M4 ;
        RECT  36.528 66.528 36.72 66.552 ;
    END
  END dq[384]
  PIN dq[385]
    DIRECTION OUTPUT ;
    USE SIGNAL ;
    PORT
      LAYER M4 ;
        RECT  36.528 66.72 36.72 66.744 ;
    END
  END dq[385]
  PIN dq[386]
    DIRECTION OUTPUT ;
    USE SIGNAL ;
    PORT
      LAYER M4 ;
        RECT  36.528 66.864 36.72 66.888 ;
    END
  END dq[386]
  PIN dq[387]
    DIRECTION OUTPUT ;
    USE SIGNAL ;
    PORT
      LAYER M4 ;
        RECT  36.528 67.008 36.72 67.032 ;
    END
  END dq[387]
  PIN dq[388]
    DIRECTION OUTPUT ;
    USE SIGNAL ;
    PORT
      LAYER M4 ;
        RECT  36.528 67.2 36.72 67.224 ;
    END
  END dq[388]
  PIN dq[389]
    DIRECTION OUTPUT ;
    USE SIGNAL ;
    PORT
      LAYER M4 ;
        RECT  36.528 67.344 36.72 67.368 ;
    END
  END dq[389]
  PIN dq[38]
    DIRECTION OUTPUT ;
    USE SIGNAL ;
    PORT
      LAYER M4 ;
        RECT  36.528 10.56 36.72 10.584 ;
    END
  END dq[38]
  PIN dq[390]
    DIRECTION OUTPUT ;
    USE SIGNAL ;
    PORT
      LAYER M4 ;
        RECT  36.528 67.488 36.72 67.512 ;
    END
  END dq[390]
  PIN dq[391]
    DIRECTION OUTPUT ;
    USE SIGNAL ;
    PORT
      LAYER M4 ;
        RECT  36.528 67.68 36.72 67.704 ;
    END
  END dq[391]
  PIN dq[392]
    DIRECTION OUTPUT ;
    USE SIGNAL ;
    PORT
      LAYER M4 ;
        RECT  36.528 67.824 36.72 67.848 ;
    END
  END dq[392]
  PIN dq[393]
    DIRECTION OUTPUT ;
    USE SIGNAL ;
    PORT
      LAYER M4 ;
        RECT  36.528 68.016 36.72 68.04 ;
    END
  END dq[393]
  PIN dq[394]
    DIRECTION OUTPUT ;
    USE SIGNAL ;
    PORT
      LAYER M4 ;
        RECT  36.528 68.16 36.72 68.184 ;
    END
  END dq[394]
  PIN dq[395]
    DIRECTION OUTPUT ;
    USE SIGNAL ;
    PORT
      LAYER M4 ;
        RECT  36.528 68.304 36.72 68.328 ;
    END
  END dq[395]
  PIN dq[396]
    DIRECTION OUTPUT ;
    USE SIGNAL ;
    PORT
      LAYER M4 ;
        RECT  36.528 68.496 36.72 68.52 ;
    END
  END dq[396]
  PIN dq[397]
    DIRECTION OUTPUT ;
    USE SIGNAL ;
    PORT
      LAYER M4 ;
        RECT  36.528 68.64 36.72 68.664 ;
    END
  END dq[397]
  PIN dq[398]
    DIRECTION OUTPUT ;
    USE SIGNAL ;
    PORT
      LAYER M4 ;
        RECT  36.528 68.784 36.72 68.808 ;
    END
  END dq[398]
  PIN dq[399]
    DIRECTION OUTPUT ;
    USE SIGNAL ;
    PORT
      LAYER M4 ;
        RECT  36.528 68.976 36.72 69 ;
    END
  END dq[399]
  PIN dq[39]
    DIRECTION OUTPUT ;
    USE SIGNAL ;
    PORT
      LAYER M4 ;
        RECT  36.528 10.704 36.72 10.728 ;
    END
  END dq[39]
  PIN dq[3]
    DIRECTION OUTPUT ;
    USE SIGNAL ;
    PORT
      LAYER M4 ;
        RECT  36.528 4.896 36.72 4.92 ;
    END
  END dq[3]
  PIN dq[400]
    DIRECTION OUTPUT ;
    USE SIGNAL ;
    PORT
      LAYER M4 ;
        RECT  36.528 69.12 36.72 69.144 ;
    END
  END dq[400]
  PIN dq[401]
    DIRECTION OUTPUT ;
    USE SIGNAL ;
    PORT
      LAYER M4 ;
        RECT  36.528 69.312 36.72 69.336 ;
    END
  END dq[401]
  PIN dq[402]
    DIRECTION OUTPUT ;
    USE SIGNAL ;
    PORT
      LAYER M4 ;
        RECT  36.528 69.456 36.72 69.48 ;
    END
  END dq[402]
  PIN dq[403]
    DIRECTION OUTPUT ;
    USE SIGNAL ;
    PORT
      LAYER M4 ;
        RECT  36.528 69.6 36.72 69.624 ;
    END
  END dq[403]
  PIN dq[404]
    DIRECTION OUTPUT ;
    USE SIGNAL ;
    PORT
      LAYER M4 ;
        RECT  36.528 69.792 36.72 69.816 ;
    END
  END dq[404]
  PIN dq[405]
    DIRECTION OUTPUT ;
    USE SIGNAL ;
    PORT
      LAYER M4 ;
        RECT  36.528 69.936 36.72 69.96 ;
    END
  END dq[405]
  PIN dq[406]
    DIRECTION OUTPUT ;
    USE SIGNAL ;
    PORT
      LAYER M4 ;
        RECT  36.528 70.08 36.72 70.104 ;
    END
  END dq[406]
  PIN dq[407]
    DIRECTION OUTPUT ;
    USE SIGNAL ;
    PORT
      LAYER M4 ;
        RECT  36.528 70.272 36.72 70.296 ;
    END
  END dq[407]
  PIN dq[408]
    DIRECTION OUTPUT ;
    USE SIGNAL ;
    PORT
      LAYER M4 ;
        RECT  36.528 70.416 36.72 70.44 ;
    END
  END dq[408]
  PIN dq[409]
    DIRECTION OUTPUT ;
    USE SIGNAL ;
    PORT
      LAYER M4 ;
        RECT  36.528 70.56 36.72 70.584 ;
    END
  END dq[409]
  PIN dq[40]
    DIRECTION OUTPUT ;
    USE SIGNAL ;
    PORT
      LAYER M4 ;
        RECT  36.528 10.896 36.72 10.92 ;
    END
  END dq[40]
  PIN dq[410]
    DIRECTION OUTPUT ;
    USE SIGNAL ;
    PORT
      LAYER M4 ;
        RECT  36.528 70.752 36.72 70.776 ;
    END
  END dq[410]
  PIN dq[411]
    DIRECTION OUTPUT ;
    USE SIGNAL ;
    PORT
      LAYER M4 ;
        RECT  36.528 70.896 36.72 70.92 ;
    END
  END dq[411]
  PIN dq[412]
    DIRECTION OUTPUT ;
    USE SIGNAL ;
    PORT
      LAYER M4 ;
        RECT  36.528 71.088 36.72 71.112 ;
    END
  END dq[412]
  PIN dq[413]
    DIRECTION OUTPUT ;
    USE SIGNAL ;
    PORT
      LAYER M4 ;
        RECT  36.528 71.232 36.72 71.256 ;
    END
  END dq[413]
  PIN dq[414]
    DIRECTION OUTPUT ;
    USE SIGNAL ;
    PORT
      LAYER M4 ;
        RECT  36.528 71.376 36.72 71.4 ;
    END
  END dq[414]
  PIN dq[415]
    DIRECTION OUTPUT ;
    USE SIGNAL ;
    PORT
      LAYER M4 ;
        RECT  36.528 71.568 36.72 71.592 ;
    END
  END dq[415]
  PIN dq[416]
    DIRECTION OUTPUT ;
    USE SIGNAL ;
    PORT
      LAYER M4 ;
        RECT  36.528 71.712 36.72 71.736 ;
    END
  END dq[416]
  PIN dq[417]
    DIRECTION OUTPUT ;
    USE SIGNAL ;
    PORT
      LAYER M4 ;
        RECT  36.528 71.856 36.72 71.88 ;
    END
  END dq[417]
  PIN dq[418]
    DIRECTION OUTPUT ;
    USE SIGNAL ;
    PORT
      LAYER M4 ;
        RECT  36.528 72.048 36.72 72.072 ;
    END
  END dq[418]
  PIN dq[419]
    DIRECTION OUTPUT ;
    USE SIGNAL ;
    PORT
      LAYER M4 ;
        RECT  36.528 72.192 36.72 72.216 ;
    END
  END dq[419]
  PIN dq[41]
    DIRECTION OUTPUT ;
    USE SIGNAL ;
    PORT
      LAYER M4 ;
        RECT  36.528 11.04 36.72 11.064 ;
    END
  END dq[41]
  PIN dq[420]
    DIRECTION OUTPUT ;
    USE SIGNAL ;
    PORT
      LAYER M4 ;
        RECT  36.528 72.384 36.72 72.408 ;
    END
  END dq[420]
  PIN dq[421]
    DIRECTION OUTPUT ;
    USE SIGNAL ;
    PORT
      LAYER M4 ;
        RECT  36.528 72.528 36.72 72.552 ;
    END
  END dq[421]
  PIN dq[422]
    DIRECTION OUTPUT ;
    USE SIGNAL ;
    PORT
      LAYER M4 ;
        RECT  36.528 72.672 36.72 72.696 ;
    END
  END dq[422]
  PIN dq[423]
    DIRECTION OUTPUT ;
    USE SIGNAL ;
    PORT
      LAYER M4 ;
        RECT  36.528 72.864 36.72 72.888 ;
    END
  END dq[423]
  PIN dq[424]
    DIRECTION OUTPUT ;
    USE SIGNAL ;
    PORT
      LAYER M4 ;
        RECT  36.528 73.008 36.72 73.032 ;
    END
  END dq[424]
  PIN dq[425]
    DIRECTION OUTPUT ;
    USE SIGNAL ;
    PORT
      LAYER M4 ;
        RECT  36.528 73.152 36.72 73.176 ;
    END
  END dq[425]
  PIN dq[426]
    DIRECTION OUTPUT ;
    USE SIGNAL ;
    PORT
      LAYER M4 ;
        RECT  36.528 73.344 36.72 73.368 ;
    END
  END dq[426]
  PIN dq[427]
    DIRECTION OUTPUT ;
    USE SIGNAL ;
    PORT
      LAYER M4 ;
        RECT  36.528 73.488 36.72 73.512 ;
    END
  END dq[427]
  PIN dq[428]
    DIRECTION OUTPUT ;
    USE SIGNAL ;
    PORT
      LAYER M4 ;
        RECT  36.528 73.68 36.72 73.704 ;
    END
  END dq[428]
  PIN dq[429]
    DIRECTION OUTPUT ;
    USE SIGNAL ;
    PORT
      LAYER M4 ;
        RECT  36.528 73.824 36.72 73.848 ;
    END
  END dq[429]
  PIN dq[42]
    DIRECTION OUTPUT ;
    USE SIGNAL ;
    PORT
      LAYER M4 ;
        RECT  36.528 11.184 36.72 11.208 ;
    END
  END dq[42]
  PIN dq[430]
    DIRECTION OUTPUT ;
    USE SIGNAL ;
    PORT
      LAYER M4 ;
        RECT  36.528 73.968 36.72 73.992 ;
    END
  END dq[430]
  PIN dq[431]
    DIRECTION OUTPUT ;
    USE SIGNAL ;
    PORT
      LAYER M4 ;
        RECT  36.528 74.16 36.72 74.184 ;
    END
  END dq[431]
  PIN dq[432]
    DIRECTION OUTPUT ;
    USE SIGNAL ;
    PORT
      LAYER M4 ;
        RECT  36.528 74.304 36.72 74.328 ;
    END
  END dq[432]
  PIN dq[433]
    DIRECTION OUTPUT ;
    USE SIGNAL ;
    PORT
      LAYER M4 ;
        RECT  36.528 74.448 36.72 74.472 ;
    END
  END dq[433]
  PIN dq[434]
    DIRECTION OUTPUT ;
    USE SIGNAL ;
    PORT
      LAYER M4 ;
        RECT  36.528 74.64 36.72 74.664 ;
    END
  END dq[434]
  PIN dq[435]
    DIRECTION OUTPUT ;
    USE SIGNAL ;
    PORT
      LAYER M4 ;
        RECT  36.528 74.784 36.72 74.808 ;
    END
  END dq[435]
  PIN dq[436]
    DIRECTION OUTPUT ;
    USE SIGNAL ;
    PORT
      LAYER M4 ;
        RECT  36.528 74.976 36.72 75 ;
    END
  END dq[436]
  PIN dq[437]
    DIRECTION OUTPUT ;
    USE SIGNAL ;
    PORT
      LAYER M4 ;
        RECT  36.528 75.12 36.72 75.144 ;
    END
  END dq[437]
  PIN dq[438]
    DIRECTION OUTPUT ;
    USE SIGNAL ;
    PORT
      LAYER M4 ;
        RECT  36.528 75.264 36.72 75.288 ;
    END
  END dq[438]
  PIN dq[439]
    DIRECTION OUTPUT ;
    USE SIGNAL ;
    PORT
      LAYER M4 ;
        RECT  36.528 75.456 36.72 75.48 ;
    END
  END dq[439]
  PIN dq[43]
    DIRECTION OUTPUT ;
    USE SIGNAL ;
    PORT
      LAYER M4 ;
        RECT  36.528 11.376 36.72 11.4 ;
    END
  END dq[43]
  PIN dq[440]
    DIRECTION OUTPUT ;
    USE SIGNAL ;
    PORT
      LAYER M4 ;
        RECT  36.528 75.6 36.72 75.624 ;
    END
  END dq[440]
  PIN dq[441]
    DIRECTION OUTPUT ;
    USE SIGNAL ;
    PORT
      LAYER M4 ;
        RECT  36.528 75.744 36.72 75.768 ;
    END
  END dq[441]
  PIN dq[442]
    DIRECTION OUTPUT ;
    USE SIGNAL ;
    PORT
      LAYER M4 ;
        RECT  36.528 75.936 36.72 75.96 ;
    END
  END dq[442]
  PIN dq[443]
    DIRECTION OUTPUT ;
    USE SIGNAL ;
    PORT
      LAYER M4 ;
        RECT  36.528 76.08 36.72 76.104 ;
    END
  END dq[443]
  PIN dq[444]
    DIRECTION OUTPUT ;
    USE SIGNAL ;
    PORT
      LAYER M4 ;
        RECT  36.528 76.224 36.72 76.248 ;
    END
  END dq[444]
  PIN dq[445]
    DIRECTION OUTPUT ;
    USE SIGNAL ;
    PORT
      LAYER M4 ;
        RECT  36.528 76.416 36.72 76.44 ;
    END
  END dq[445]
  PIN dq[446]
    DIRECTION OUTPUT ;
    USE SIGNAL ;
    PORT
      LAYER M4 ;
        RECT  36.528 76.56 36.72 76.584 ;
    END
  END dq[446]
  PIN dq[447]
    DIRECTION OUTPUT ;
    USE SIGNAL ;
    PORT
      LAYER M4 ;
        RECT  36.528 76.752 36.72 76.776 ;
    END
  END dq[447]
  PIN dq[448]
    DIRECTION OUTPUT ;
    USE SIGNAL ;
    PORT
      LAYER M4 ;
        RECT  36.528 76.896 36.72 76.92 ;
    END
  END dq[448]
  PIN dq[449]
    DIRECTION OUTPUT ;
    USE SIGNAL ;
    PORT
      LAYER M4 ;
        RECT  36.528 77.04 36.72 77.064 ;
    END
  END dq[449]
  PIN dq[44]
    DIRECTION OUTPUT ;
    USE SIGNAL ;
    PORT
      LAYER M4 ;
        RECT  36.528 11.52 36.72 11.544 ;
    END
  END dq[44]
  PIN dq[450]
    DIRECTION OUTPUT ;
    USE SIGNAL ;
    PORT
      LAYER M4 ;
        RECT  36.528 77.232 36.72 77.256 ;
    END
  END dq[450]
  PIN dq[451]
    DIRECTION OUTPUT ;
    USE SIGNAL ;
    PORT
      LAYER M4 ;
        RECT  36.528 77.376 36.72 77.4 ;
    END
  END dq[451]
  PIN dq[452]
    DIRECTION OUTPUT ;
    USE SIGNAL ;
    PORT
      LAYER M4 ;
        RECT  36.528 77.52 36.72 77.544 ;
    END
  END dq[452]
  PIN dq[453]
    DIRECTION OUTPUT ;
    USE SIGNAL ;
    PORT
      LAYER M4 ;
        RECT  36.528 77.712 36.72 77.736 ;
    END
  END dq[453]
  PIN dq[454]
    DIRECTION OUTPUT ;
    USE SIGNAL ;
    PORT
      LAYER M4 ;
        RECT  36.528 77.856 36.72 77.88 ;
    END
  END dq[454]
  PIN dq[455]
    DIRECTION OUTPUT ;
    USE SIGNAL ;
    PORT
      LAYER M4 ;
        RECT  36.528 78.048 36.72 78.072 ;
    END
  END dq[455]
  PIN dq[456]
    DIRECTION OUTPUT ;
    USE SIGNAL ;
    PORT
      LAYER M4 ;
        RECT  36.528 78.192 36.72 78.216 ;
    END
  END dq[456]
  PIN dq[457]
    DIRECTION OUTPUT ;
    USE SIGNAL ;
    PORT
      LAYER M4 ;
        RECT  36.528 78.336 36.72 78.36 ;
    END
  END dq[457]
  PIN dq[458]
    DIRECTION OUTPUT ;
    USE SIGNAL ;
    PORT
      LAYER M4 ;
        RECT  36.528 78.528 36.72 78.552 ;
    END
  END dq[458]
  PIN dq[459]
    DIRECTION OUTPUT ;
    USE SIGNAL ;
    PORT
      LAYER M4 ;
        RECT  36.528 78.672 36.72 78.696 ;
    END
  END dq[459]
  PIN dq[45]
    DIRECTION OUTPUT ;
    USE SIGNAL ;
    PORT
      LAYER M4 ;
        RECT  36.528 11.712 36.72 11.736 ;
    END
  END dq[45]
  PIN dq[460]
    DIRECTION OUTPUT ;
    USE SIGNAL ;
    PORT
      LAYER M4 ;
        RECT  36.528 78.816 36.72 78.84 ;
    END
  END dq[460]
  PIN dq[461]
    DIRECTION OUTPUT ;
    USE SIGNAL ;
    PORT
      LAYER M4 ;
        RECT  36.528 79.008 36.72 79.032 ;
    END
  END dq[461]
  PIN dq[462]
    DIRECTION OUTPUT ;
    USE SIGNAL ;
    PORT
      LAYER M4 ;
        RECT  36.528 79.152 36.72 79.176 ;
    END
  END dq[462]
  PIN dq[463]
    DIRECTION OUTPUT ;
    USE SIGNAL ;
    PORT
      LAYER M4 ;
        RECT  36.528 79.344 36.72 79.368 ;
    END
  END dq[463]
  PIN dq[464]
    DIRECTION OUTPUT ;
    USE SIGNAL ;
    PORT
      LAYER M4 ;
        RECT  36.528 79.488 36.72 79.512 ;
    END
  END dq[464]
  PIN dq[465]
    DIRECTION OUTPUT ;
    USE SIGNAL ;
    PORT
      LAYER M4 ;
        RECT  36.528 79.632 36.72 79.656 ;
    END
  END dq[465]
  PIN dq[466]
    DIRECTION OUTPUT ;
    USE SIGNAL ;
    PORT
      LAYER M4 ;
        RECT  36.528 79.824 36.72 79.848 ;
    END
  END dq[466]
  PIN dq[467]
    DIRECTION OUTPUT ;
    USE SIGNAL ;
    PORT
      LAYER M4 ;
        RECT  36.528 79.968 36.72 79.992 ;
    END
  END dq[467]
  PIN dq[468]
    DIRECTION OUTPUT ;
    USE SIGNAL ;
    PORT
      LAYER M4 ;
        RECT  36.528 80.112 36.72 80.136 ;
    END
  END dq[468]
  PIN dq[469]
    DIRECTION OUTPUT ;
    USE SIGNAL ;
    PORT
      LAYER M4 ;
        RECT  36.528 80.304 36.72 80.328 ;
    END
  END dq[469]
  PIN dq[46]
    DIRECTION OUTPUT ;
    USE SIGNAL ;
    PORT
      LAYER M4 ;
        RECT  36.528 11.856 36.72 11.88 ;
    END
  END dq[46]
  PIN dq[470]
    DIRECTION OUTPUT ;
    USE SIGNAL ;
    PORT
      LAYER M4 ;
        RECT  36.528 80.448 36.72 80.472 ;
    END
  END dq[470]
  PIN dq[471]
    DIRECTION OUTPUT ;
    USE SIGNAL ;
    PORT
      LAYER M4 ;
        RECT  36.528 80.592 36.72 80.616 ;
    END
  END dq[471]
  PIN dq[472]
    DIRECTION OUTPUT ;
    USE SIGNAL ;
    PORT
      LAYER M4 ;
        RECT  36.528 80.784 36.72 80.808 ;
    END
  END dq[472]
  PIN dq[473]
    DIRECTION OUTPUT ;
    USE SIGNAL ;
    PORT
      LAYER M4 ;
        RECT  36.528 80.928 36.72 80.952 ;
    END
  END dq[473]
  PIN dq[474]
    DIRECTION OUTPUT ;
    USE SIGNAL ;
    PORT
      LAYER M4 ;
        RECT  36.528 81.12 36.72 81.144 ;
    END
  END dq[474]
  PIN dq[475]
    DIRECTION OUTPUT ;
    USE SIGNAL ;
    PORT
      LAYER M4 ;
        RECT  36.528 81.264 36.72 81.288 ;
    END
  END dq[475]
  PIN dq[476]
    DIRECTION OUTPUT ;
    USE SIGNAL ;
    PORT
      LAYER M4 ;
        RECT  36.528 81.408 36.72 81.432 ;
    END
  END dq[476]
  PIN dq[477]
    DIRECTION OUTPUT ;
    USE SIGNAL ;
    PORT
      LAYER M4 ;
        RECT  36.528 81.6 36.72 81.624 ;
    END
  END dq[477]
  PIN dq[478]
    DIRECTION OUTPUT ;
    USE SIGNAL ;
    PORT
      LAYER M4 ;
        RECT  36.528 81.744 36.72 81.768 ;
    END
  END dq[478]
  PIN dq[479]
    DIRECTION OUTPUT ;
    USE SIGNAL ;
    PORT
      LAYER M4 ;
        RECT  36.528 81.888 36.72 81.912 ;
    END
  END dq[479]
  PIN dq[47]
    DIRECTION OUTPUT ;
    USE SIGNAL ;
    PORT
      LAYER M4 ;
        RECT  36.528 12 36.72 12.024 ;
    END
  END dq[47]
  PIN dq[480]
    DIRECTION OUTPUT ;
    USE SIGNAL ;
    PORT
      LAYER M4 ;
        RECT  36.528 82.08 36.72 82.104 ;
    END
  END dq[480]
  PIN dq[481]
    DIRECTION OUTPUT ;
    USE SIGNAL ;
    PORT
      LAYER M4 ;
        RECT  36.528 82.224 36.72 82.248 ;
    END
  END dq[481]
  PIN dq[482]
    DIRECTION OUTPUT ;
    USE SIGNAL ;
    PORT
      LAYER M4 ;
        RECT  36.528 82.416 36.72 82.44 ;
    END
  END dq[482]
  PIN dq[483]
    DIRECTION OUTPUT ;
    USE SIGNAL ;
    PORT
      LAYER M4 ;
        RECT  36.528 82.56 36.72 82.584 ;
    END
  END dq[483]
  PIN dq[484]
    DIRECTION OUTPUT ;
    USE SIGNAL ;
    PORT
      LAYER M4 ;
        RECT  36.528 82.704 36.72 82.728 ;
    END
  END dq[484]
  PIN dq[485]
    DIRECTION OUTPUT ;
    USE SIGNAL ;
    PORT
      LAYER M4 ;
        RECT  36.528 82.896 36.72 82.92 ;
    END
  END dq[485]
  PIN dq[486]
    DIRECTION OUTPUT ;
    USE SIGNAL ;
    PORT
      LAYER M4 ;
        RECT  36.528 83.04 36.72 83.064 ;
    END
  END dq[486]
  PIN dq[487]
    DIRECTION OUTPUT ;
    USE SIGNAL ;
    PORT
      LAYER M4 ;
        RECT  36.528 83.184 36.72 83.208 ;
    END
  END dq[487]
  PIN dq[488]
    DIRECTION OUTPUT ;
    USE SIGNAL ;
    PORT
      LAYER M4 ;
        RECT  36.528 83.376 36.72 83.4 ;
    END
  END dq[488]
  PIN dq[489]
    DIRECTION OUTPUT ;
    USE SIGNAL ;
    PORT
      LAYER M4 ;
        RECT  36.528 83.52 36.72 83.544 ;
    END
  END dq[489]
  PIN dq[48]
    DIRECTION OUTPUT ;
    USE SIGNAL ;
    PORT
      LAYER M4 ;
        RECT  36.528 12.192 36.72 12.216 ;
    END
  END dq[48]
  PIN dq[490]
    DIRECTION OUTPUT ;
    USE SIGNAL ;
    PORT
      LAYER M4 ;
        RECT  36.528 83.712 36.72 83.736 ;
    END
  END dq[490]
  PIN dq[491]
    DIRECTION OUTPUT ;
    USE SIGNAL ;
    PORT
      LAYER M4 ;
        RECT  36.528 83.856 36.72 83.88 ;
    END
  END dq[491]
  PIN dq[492]
    DIRECTION OUTPUT ;
    USE SIGNAL ;
    PORT
      LAYER M4 ;
        RECT  36.528 84 36.72 84.024 ;
    END
  END dq[492]
  PIN dq[493]
    DIRECTION OUTPUT ;
    USE SIGNAL ;
    PORT
      LAYER M4 ;
        RECT  36.528 84.192 36.72 84.216 ;
    END
  END dq[493]
  PIN dq[494]
    DIRECTION OUTPUT ;
    USE SIGNAL ;
    PORT
      LAYER M4 ;
        RECT  36.528 84.336 36.72 84.36 ;
    END
  END dq[494]
  PIN dq[495]
    DIRECTION OUTPUT ;
    USE SIGNAL ;
    PORT
      LAYER M4 ;
        RECT  36.528 84.48 36.72 84.504 ;
    END
  END dq[495]
  PIN dq[496]
    DIRECTION OUTPUT ;
    USE SIGNAL ;
    PORT
      LAYER M4 ;
        RECT  36.528 84.672 36.72 84.696 ;
    END
  END dq[496]
  PIN dq[497]
    DIRECTION OUTPUT ;
    USE SIGNAL ;
    PORT
      LAYER M4 ;
        RECT  36.528 84.816 36.72 84.84 ;
    END
  END dq[497]
  PIN dq[498]
    DIRECTION OUTPUT ;
    USE SIGNAL ;
    PORT
      LAYER M4 ;
        RECT  36.528 84.96 36.72 84.984 ;
    END
  END dq[498]
  PIN dq[499]
    DIRECTION OUTPUT ;
    USE SIGNAL ;
    PORT
      LAYER M4 ;
        RECT  36.528 85.152 36.72 85.176 ;
    END
  END dq[499]
  PIN dq[49]
    DIRECTION OUTPUT ;
    USE SIGNAL ;
    PORT
      LAYER M4 ;
        RECT  36.528 12.336 36.72 12.36 ;
    END
  END dq[49]
  PIN dq[4]
    DIRECTION OUTPUT ;
    USE SIGNAL ;
    PORT
      LAYER M4 ;
        RECT  36.528 5.04 36.72 5.064 ;
    END
  END dq[4]
  PIN dq[500]
    DIRECTION OUTPUT ;
    USE SIGNAL ;
    PORT
      LAYER M4 ;
        RECT  36.528 85.296 36.72 85.32 ;
    END
  END dq[500]
  PIN dq[501]
    DIRECTION OUTPUT ;
    USE SIGNAL ;
    PORT
      LAYER M4 ;
        RECT  36.528 85.488 36.72 85.512 ;
    END
  END dq[501]
  PIN dq[502]
    DIRECTION OUTPUT ;
    USE SIGNAL ;
    PORT
      LAYER M4 ;
        RECT  36.528 85.632 36.72 85.656 ;
    END
  END dq[502]
  PIN dq[503]
    DIRECTION OUTPUT ;
    USE SIGNAL ;
    PORT
      LAYER M4 ;
        RECT  36.528 85.776 36.72 85.8 ;
    END
  END dq[503]
  PIN dq[504]
    DIRECTION OUTPUT ;
    USE SIGNAL ;
    PORT
      LAYER M4 ;
        RECT  36.528 85.968 36.72 85.992 ;
    END
  END dq[504]
  PIN dq[505]
    DIRECTION OUTPUT ;
    USE SIGNAL ;
    PORT
      LAYER M4 ;
        RECT  36.528 86.112 36.72 86.136 ;
    END
  END dq[505]
  PIN dq[506]
    DIRECTION OUTPUT ;
    USE SIGNAL ;
    PORT
      LAYER M4 ;
        RECT  36.528 86.256 36.72 86.28 ;
    END
  END dq[506]
  PIN dq[507]
    DIRECTION OUTPUT ;
    USE SIGNAL ;
    PORT
      LAYER M4 ;
        RECT  36.528 86.448 36.72 86.472 ;
    END
  END dq[507]
  PIN dq[508]
    DIRECTION OUTPUT ;
    USE SIGNAL ;
    PORT
      LAYER M4 ;
        RECT  36.528 86.592 36.72 86.616 ;
    END
  END dq[508]
  PIN dq[509]
    DIRECTION OUTPUT ;
    USE SIGNAL ;
    PORT
      LAYER M4 ;
        RECT  36.528 86.784 36.72 86.808 ;
    END
  END dq[509]
  PIN dq[50]
    DIRECTION OUTPUT ;
    USE SIGNAL ;
    PORT
      LAYER M4 ;
        RECT  36.528 12.48 36.72 12.504 ;
    END
  END dq[50]
  PIN dq[510]
    DIRECTION OUTPUT ;
    USE SIGNAL ;
    PORT
      LAYER M4 ;
        RECT  36.528 86.928 36.72 86.952 ;
    END
  END dq[510]
  PIN dq[511]
    DIRECTION OUTPUT ;
    USE SIGNAL ;
    PORT
      LAYER M4 ;
        RECT  36.528 87.072 36.72 87.096 ;
    END
  END dq[511]
  PIN dq[512]
    DIRECTION OUTPUT ;
    USE SIGNAL ;
    PORT
      LAYER M4 ;
        RECT  36.528 87.264 36.72 87.288 ;
    END
  END dq[512]
  PIN dq[513]
    DIRECTION OUTPUT ;
    USE SIGNAL ;
    PORT
      LAYER M4 ;
        RECT  36.528 87.408 36.72 87.432 ;
    END
  END dq[513]
  PIN dq[514]
    DIRECTION OUTPUT ;
    USE SIGNAL ;
    PORT
      LAYER M4 ;
        RECT  36.528 87.552 36.72 87.576 ;
    END
  END dq[514]
  PIN dq[515]
    DIRECTION OUTPUT ;
    USE SIGNAL ;
    PORT
      LAYER M4 ;
        RECT  36.528 87.744 36.72 87.768 ;
    END
  END dq[515]
  PIN dq[516]
    DIRECTION OUTPUT ;
    USE SIGNAL ;
    PORT
      LAYER M4 ;
        RECT  36.528 87.888 36.72 87.912 ;
    END
  END dq[516]
  PIN dq[517]
    DIRECTION OUTPUT ;
    USE SIGNAL ;
    PORT
      LAYER M4 ;
        RECT  36.528 88.08 36.72 88.104 ;
    END
  END dq[517]
  PIN dq[518]
    DIRECTION OUTPUT ;
    USE SIGNAL ;
    PORT
      LAYER M4 ;
        RECT  36.528 88.224 36.72 88.248 ;
    END
  END dq[518]
  PIN dq[519]
    DIRECTION OUTPUT ;
    USE SIGNAL ;
    PORT
      LAYER M4 ;
        RECT  36.528 88.368 36.72 88.392 ;
    END
  END dq[519]
  PIN dq[51]
    DIRECTION OUTPUT ;
    USE SIGNAL ;
    PORT
      LAYER M4 ;
        RECT  36.528 12.672 36.72 12.696 ;
    END
  END dq[51]
  PIN dq[520]
    DIRECTION OUTPUT ;
    USE SIGNAL ;
    PORT
      LAYER M4 ;
        RECT  36.528 88.56 36.72 88.584 ;
    END
  END dq[520]
  PIN dq[521]
    DIRECTION OUTPUT ;
    USE SIGNAL ;
    PORT
      LAYER M4 ;
        RECT  36.528 88.704 36.72 88.728 ;
    END
  END dq[521]
  PIN dq[522]
    DIRECTION OUTPUT ;
    USE SIGNAL ;
    PORT
      LAYER M4 ;
        RECT  36.528 88.848 36.72 88.872 ;
    END
  END dq[522]
  PIN dq[523]
    DIRECTION OUTPUT ;
    USE SIGNAL ;
    PORT
      LAYER M4 ;
        RECT  36.528 89.04 36.72 89.064 ;
    END
  END dq[523]
  PIN dq[524]
    DIRECTION OUTPUT ;
    USE SIGNAL ;
    PORT
      LAYER M4 ;
        RECT  36.528 89.184 36.72 89.208 ;
    END
  END dq[524]
  PIN dq[525]
    DIRECTION OUTPUT ;
    USE SIGNAL ;
    PORT
      LAYER M4 ;
        RECT  36.528 89.328 36.72 89.352 ;
    END
  END dq[525]
  PIN dq[526]
    DIRECTION OUTPUT ;
    USE SIGNAL ;
    PORT
      LAYER M4 ;
        RECT  36.528 89.52 36.72 89.544 ;
    END
  END dq[526]
  PIN dq[527]
    DIRECTION OUTPUT ;
    USE SIGNAL ;
    PORT
      LAYER M4 ;
        RECT  36.528 89.664 36.72 89.688 ;
    END
  END dq[527]
  PIN dq[528]
    DIRECTION OUTPUT ;
    USE SIGNAL ;
    PORT
      LAYER M4 ;
        RECT  36.528 89.856 36.72 89.88 ;
    END
  END dq[528]
  PIN dq[529]
    DIRECTION OUTPUT ;
    USE SIGNAL ;
    PORT
      LAYER M4 ;
        RECT  36.528 90 36.72 90.024 ;
    END
  END dq[529]
  PIN dq[52]
    DIRECTION OUTPUT ;
    USE SIGNAL ;
    PORT
      LAYER M4 ;
        RECT  36.528 12.816 36.72 12.84 ;
    END
  END dq[52]
  PIN dq[530]
    DIRECTION OUTPUT ;
    USE SIGNAL ;
    PORT
      LAYER M4 ;
        RECT  36.528 90.144 36.72 90.168 ;
    END
  END dq[530]
  PIN dq[531]
    DIRECTION OUTPUT ;
    USE SIGNAL ;
    PORT
      LAYER M4 ;
        RECT  36.528 90.336 36.72 90.36 ;
    END
  END dq[531]
  PIN dq[532]
    DIRECTION OUTPUT ;
    USE SIGNAL ;
    PORT
      LAYER M4 ;
        RECT  36.528 90.48 36.72 90.504 ;
    END
  END dq[532]
  PIN dq[533]
    DIRECTION OUTPUT ;
    USE SIGNAL ;
    PORT
      LAYER M4 ;
        RECT  36.528 90.624 36.72 90.648 ;
    END
  END dq[533]
  PIN dq[534]
    DIRECTION OUTPUT ;
    USE SIGNAL ;
    PORT
      LAYER M4 ;
        RECT  36.528 90.816 36.72 90.84 ;
    END
  END dq[534]
  PIN dq[535]
    DIRECTION OUTPUT ;
    USE SIGNAL ;
    PORT
      LAYER M4 ;
        RECT  36.528 90.96 36.72 90.984 ;
    END
  END dq[535]
  PIN dq[536]
    DIRECTION OUTPUT ;
    USE SIGNAL ;
    PORT
      LAYER M4 ;
        RECT  36.528 91.152 36.72 91.176 ;
    END
  END dq[536]
  PIN dq[537]
    DIRECTION OUTPUT ;
    USE SIGNAL ;
    PORT
      LAYER M4 ;
        RECT  36.528 91.296 36.72 91.32 ;
    END
  END dq[537]
  PIN dq[538]
    DIRECTION OUTPUT ;
    USE SIGNAL ;
    PORT
      LAYER M4 ;
        RECT  36.528 91.44 36.72 91.464 ;
    END
  END dq[538]
  PIN dq[539]
    DIRECTION OUTPUT ;
    USE SIGNAL ;
    PORT
      LAYER M4 ;
        RECT  36.528 91.632 36.72 91.656 ;
    END
  END dq[539]
  PIN dq[53]
    DIRECTION OUTPUT ;
    USE SIGNAL ;
    PORT
      LAYER M4 ;
        RECT  36.528 13.008 36.72 13.032 ;
    END
  END dq[53]
  PIN dq[540]
    DIRECTION OUTPUT ;
    USE SIGNAL ;
    PORT
      LAYER M4 ;
        RECT  36.528 91.776 36.72 91.8 ;
    END
  END dq[540]
  PIN dq[541]
    DIRECTION OUTPUT ;
    USE SIGNAL ;
    PORT
      LAYER M4 ;
        RECT  36.528 91.92 36.72 91.944 ;
    END
  END dq[541]
  PIN dq[542]
    DIRECTION OUTPUT ;
    USE SIGNAL ;
    PORT
      LAYER M4 ;
        RECT  36.528 92.112 36.72 92.136 ;
    END
  END dq[542]
  PIN dq[543]
    DIRECTION OUTPUT ;
    USE SIGNAL ;
    PORT
      LAYER M4 ;
        RECT  36.528 92.256 36.72 92.28 ;
    END
  END dq[543]
  PIN dq[544]
    DIRECTION OUTPUT ;
    USE SIGNAL ;
    PORT
      LAYER M4 ;
        RECT  36.528 92.448 36.72 92.472 ;
    END
  END dq[544]
  PIN dq[545]
    DIRECTION OUTPUT ;
    USE SIGNAL ;
    PORT
      LAYER M4 ;
        RECT  36.528 92.592 36.72 92.616 ;
    END
  END dq[545]
  PIN dq[546]
    DIRECTION OUTPUT ;
    USE SIGNAL ;
    PORT
      LAYER M4 ;
        RECT  36.528 92.736 36.72 92.76 ;
    END
  END dq[546]
  PIN dq[547]
    DIRECTION OUTPUT ;
    USE SIGNAL ;
    PORT
      LAYER M4 ;
        RECT  36.528 92.928 36.72 92.952 ;
    END
  END dq[547]
  PIN dq[548]
    DIRECTION OUTPUT ;
    USE SIGNAL ;
    PORT
      LAYER M4 ;
        RECT  36.528 93.072 36.72 93.096 ;
    END
  END dq[548]
  PIN dq[549]
    DIRECTION OUTPUT ;
    USE SIGNAL ;
    PORT
      LAYER M4 ;
        RECT  36.528 93.216 36.72 93.24 ;
    END
  END dq[549]
  PIN dq[54]
    DIRECTION OUTPUT ;
    USE SIGNAL ;
    PORT
      LAYER M4 ;
        RECT  36.528 13.152 36.72 13.176 ;
    END
  END dq[54]
  PIN dq[550]
    DIRECTION OUTPUT ;
    USE SIGNAL ;
    PORT
      LAYER M4 ;
        RECT  36.528 93.408 36.72 93.432 ;
    END
  END dq[550]
  PIN dq[551]
    DIRECTION OUTPUT ;
    USE SIGNAL ;
    PORT
      LAYER M4 ;
        RECT  36.528 93.552 36.72 93.576 ;
    END
  END dq[551]
  PIN dq[552]
    DIRECTION OUTPUT ;
    USE SIGNAL ;
    PORT
      LAYER M4 ;
        RECT  36.528 93.696 36.72 93.72 ;
    END
  END dq[552]
  PIN dq[553]
    DIRECTION OUTPUT ;
    USE SIGNAL ;
    PORT
      LAYER M4 ;
        RECT  36.528 93.888 36.72 93.912 ;
    END
  END dq[553]
  PIN dq[554]
    DIRECTION OUTPUT ;
    USE SIGNAL ;
    PORT
      LAYER M4 ;
        RECT  36.528 94.032 36.72 94.056 ;
    END
  END dq[554]
  PIN dq[555]
    DIRECTION OUTPUT ;
    USE SIGNAL ;
    PORT
      LAYER M4 ;
        RECT  36.528 94.224 36.72 94.248 ;
    END
  END dq[555]
  PIN dq[556]
    DIRECTION OUTPUT ;
    USE SIGNAL ;
    PORT
      LAYER M4 ;
        RECT  36.528 94.368 36.72 94.392 ;
    END
  END dq[556]
  PIN dq[557]
    DIRECTION OUTPUT ;
    USE SIGNAL ;
    PORT
      LAYER M4 ;
        RECT  36.528 94.512 36.72 94.536 ;
    END
  END dq[557]
  PIN dq[558]
    DIRECTION OUTPUT ;
    USE SIGNAL ;
    PORT
      LAYER M4 ;
        RECT  36.528 94.704 36.72 94.728 ;
    END
  END dq[558]
  PIN dq[559]
    DIRECTION OUTPUT ;
    USE SIGNAL ;
    PORT
      LAYER M4 ;
        RECT  36.528 94.848 36.72 94.872 ;
    END
  END dq[559]
  PIN dq[55]
    DIRECTION OUTPUT ;
    USE SIGNAL ;
    PORT
      LAYER M4 ;
        RECT  36.528 13.296 36.72 13.32 ;
    END
  END dq[55]
  PIN dq[560]
    DIRECTION OUTPUT ;
    USE SIGNAL ;
    PORT
      LAYER M4 ;
        RECT  36.528 94.992 36.72 95.016 ;
    END
  END dq[560]
  PIN dq[561]
    DIRECTION OUTPUT ;
    USE SIGNAL ;
    PORT
      LAYER M4 ;
        RECT  36.528 95.184 36.72 95.208 ;
    END
  END dq[561]
  PIN dq[562]
    DIRECTION OUTPUT ;
    USE SIGNAL ;
    PORT
      LAYER M4 ;
        RECT  36.528 95.328 36.72 95.352 ;
    END
  END dq[562]
  PIN dq[563]
    DIRECTION OUTPUT ;
    USE SIGNAL ;
    PORT
      LAYER M4 ;
        RECT  36.528 95.52 36.72 95.544 ;
    END
  END dq[563]
  PIN dq[564]
    DIRECTION OUTPUT ;
    USE SIGNAL ;
    PORT
      LAYER M4 ;
        RECT  36.528 95.664 36.72 95.688 ;
    END
  END dq[564]
  PIN dq[565]
    DIRECTION OUTPUT ;
    USE SIGNAL ;
    PORT
      LAYER M4 ;
        RECT  36.528 95.808 36.72 95.832 ;
    END
  END dq[565]
  PIN dq[566]
    DIRECTION OUTPUT ;
    USE SIGNAL ;
    PORT
      LAYER M4 ;
        RECT  36.528 96 36.72 96.024 ;
    END
  END dq[566]
  PIN dq[567]
    DIRECTION OUTPUT ;
    USE SIGNAL ;
    PORT
      LAYER M4 ;
        RECT  36.528 96.144 36.72 96.168 ;
    END
  END dq[567]
  PIN dq[568]
    DIRECTION OUTPUT ;
    USE SIGNAL ;
    PORT
      LAYER M4 ;
        RECT  36.528 96.288 36.72 96.312 ;
    END
  END dq[568]
  PIN dq[569]
    DIRECTION OUTPUT ;
    USE SIGNAL ;
    PORT
      LAYER M4 ;
        RECT  36.528 96.48 36.72 96.504 ;
    END
  END dq[569]
  PIN dq[56]
    DIRECTION OUTPUT ;
    USE SIGNAL ;
    PORT
      LAYER M4 ;
        RECT  36.528 13.488 36.72 13.512 ;
    END
  END dq[56]
  PIN dq[570]
    DIRECTION OUTPUT ;
    USE SIGNAL ;
    PORT
      LAYER M4 ;
        RECT  36.528 96.624 36.72 96.648 ;
    END
  END dq[570]
  PIN dq[571]
    DIRECTION OUTPUT ;
    USE SIGNAL ;
    PORT
      LAYER M4 ;
        RECT  36.528 96.816 36.72 96.84 ;
    END
  END dq[571]
  PIN dq[572]
    DIRECTION OUTPUT ;
    USE SIGNAL ;
    PORT
      LAYER M4 ;
        RECT  36.528 96.96 36.72 96.984 ;
    END
  END dq[572]
  PIN dq[573]
    DIRECTION OUTPUT ;
    USE SIGNAL ;
    PORT
      LAYER M4 ;
        RECT  36.528 97.104 36.72 97.128 ;
    END
  END dq[573]
  PIN dq[574]
    DIRECTION OUTPUT ;
    USE SIGNAL ;
    PORT
      LAYER M4 ;
        RECT  36.528 97.296 36.72 97.32 ;
    END
  END dq[574]
  PIN dq[575]
    DIRECTION OUTPUT ;
    USE SIGNAL ;
    PORT
      LAYER M4 ;
        RECT  36.528 97.44 36.72 97.464 ;
    END
  END dq[575]
  PIN dq[576]
    DIRECTION OUTPUT ;
    USE SIGNAL ;
    PORT
      LAYER M4 ;
        RECT  36.528 97.584 36.72 97.608 ;
    END
  END dq[576]
  PIN dq[577]
    DIRECTION OUTPUT ;
    USE SIGNAL ;
    PORT
      LAYER M4 ;
        RECT  36.528 97.776 36.72 97.8 ;
    END
  END dq[577]
  PIN dq[578]
    DIRECTION OUTPUT ;
    USE SIGNAL ;
    PORT
      LAYER M4 ;
        RECT  36.528 97.92 36.72 97.944 ;
    END
  END dq[578]
  PIN dq[579]
    DIRECTION OUTPUT ;
    USE SIGNAL ;
    PORT
      LAYER M4 ;
        RECT  36.528 98.064 36.72 98.088 ;
    END
  END dq[579]
  PIN dq[57]
    DIRECTION OUTPUT ;
    USE SIGNAL ;
    PORT
      LAYER M4 ;
        RECT  36.528 13.632 36.72 13.656 ;
    END
  END dq[57]
  PIN dq[580]
    DIRECTION OUTPUT ;
    USE SIGNAL ;
    PORT
      LAYER M4 ;
        RECT  36.528 98.256 36.72 98.28 ;
    END
  END dq[580]
  PIN dq[581]
    DIRECTION OUTPUT ;
    USE SIGNAL ;
    PORT
      LAYER M4 ;
        RECT  36.528 98.4 36.72 98.424 ;
    END
  END dq[581]
  PIN dq[582]
    DIRECTION OUTPUT ;
    USE SIGNAL ;
    PORT
      LAYER M4 ;
        RECT  36.528 98.592 36.72 98.616 ;
    END
  END dq[582]
  PIN dq[583]
    DIRECTION OUTPUT ;
    USE SIGNAL ;
    PORT
      LAYER M4 ;
        RECT  36.528 98.736 36.72 98.76 ;
    END
  END dq[583]
  PIN dq[584]
    DIRECTION OUTPUT ;
    USE SIGNAL ;
    PORT
      LAYER M4 ;
        RECT  36.528 98.88 36.72 98.904 ;
    END
  END dq[584]
  PIN dq[585]
    DIRECTION OUTPUT ;
    USE SIGNAL ;
    PORT
      LAYER M4 ;
        RECT  36.528 99.072 36.72 99.096 ;
    END
  END dq[585]
  PIN dq[586]
    DIRECTION OUTPUT ;
    USE SIGNAL ;
    PORT
      LAYER M4 ;
        RECT  36.528 99.216 36.72 99.24 ;
    END
  END dq[586]
  PIN dq[587]
    DIRECTION OUTPUT ;
    USE SIGNAL ;
    PORT
      LAYER M4 ;
        RECT  36.528 99.36 36.72 99.384 ;
    END
  END dq[587]
  PIN dq[588]
    DIRECTION OUTPUT ;
    USE SIGNAL ;
    PORT
      LAYER M4 ;
        RECT  36.528 99.552 36.72 99.576 ;
    END
  END dq[588]
  PIN dq[589]
    DIRECTION OUTPUT ;
    USE SIGNAL ;
    PORT
      LAYER M4 ;
        RECT  36.528 99.696 36.72 99.72 ;
    END
  END dq[589]
  PIN dq[58]
    DIRECTION OUTPUT ;
    USE SIGNAL ;
    PORT
      LAYER M4 ;
        RECT  36.528 13.776 36.72 13.8 ;
    END
  END dq[58]
  PIN dq[590]
    DIRECTION OUTPUT ;
    USE SIGNAL ;
    PORT
      LAYER M4 ;
        RECT  36.528 99.888 36.72 99.912 ;
    END
  END dq[590]
  PIN dq[591]
    DIRECTION OUTPUT ;
    USE SIGNAL ;
    PORT
      LAYER M4 ;
        RECT  36.528 100.032 36.72 100.056 ;
    END
  END dq[591]
  PIN dq[592]
    DIRECTION OUTPUT ;
    USE SIGNAL ;
    PORT
      LAYER M4 ;
        RECT  36.528 100.176 36.72 100.2 ;
    END
  END dq[592]
  PIN dq[593]
    DIRECTION OUTPUT ;
    USE SIGNAL ;
    PORT
      LAYER M4 ;
        RECT  36.528 100.368 36.72 100.392 ;
    END
  END dq[593]
  PIN dq[594]
    DIRECTION OUTPUT ;
    USE SIGNAL ;
    PORT
      LAYER M4 ;
        RECT  36.528 100.512 36.72 100.536 ;
    END
  END dq[594]
  PIN dq[595]
    DIRECTION OUTPUT ;
    USE SIGNAL ;
    PORT
      LAYER M4 ;
        RECT  36.528 100.656 36.72 100.68 ;
    END
  END dq[595]
  PIN dq[596]
    DIRECTION OUTPUT ;
    USE SIGNAL ;
    PORT
      LAYER M4 ;
        RECT  36.528 100.848 36.72 100.872 ;
    END
  END dq[596]
  PIN dq[597]
    DIRECTION OUTPUT ;
    USE SIGNAL ;
    PORT
      LAYER M4 ;
        RECT  36.528 100.992 36.72 101.016 ;
    END
  END dq[597]
  PIN dq[598]
    DIRECTION OUTPUT ;
    USE SIGNAL ;
    PORT
      LAYER M4 ;
        RECT  36.528 101.184 36.72 101.208 ;
    END
  END dq[598]
  PIN dq[599]
    DIRECTION OUTPUT ;
    USE SIGNAL ;
    PORT
      LAYER M4 ;
        RECT  36.528 101.328 36.72 101.352 ;
    END
  END dq[599]
  PIN dq[59]
    DIRECTION OUTPUT ;
    USE SIGNAL ;
    PORT
      LAYER M4 ;
        RECT  36.528 13.968 36.72 13.992 ;
    END
  END dq[59]
  PIN dq[5]
    DIRECTION OUTPUT ;
    USE SIGNAL ;
    PORT
      LAYER M4 ;
        RECT  36.528 5.232 36.72 5.256 ;
    END
  END dq[5]
  PIN dq[600]
    DIRECTION OUTPUT ;
    USE SIGNAL ;
    PORT
      LAYER M4 ;
        RECT  36.528 101.472 36.72 101.496 ;
    END
  END dq[600]
  PIN dq[601]
    DIRECTION OUTPUT ;
    USE SIGNAL ;
    PORT
      LAYER M4 ;
        RECT  36.528 101.664 36.72 101.688 ;
    END
  END dq[601]
  PIN dq[602]
    DIRECTION OUTPUT ;
    USE SIGNAL ;
    PORT
      LAYER M4 ;
        RECT  36.528 101.808 36.72 101.832 ;
    END
  END dq[602]
  PIN dq[603]
    DIRECTION OUTPUT ;
    USE SIGNAL ;
    PORT
      LAYER M4 ;
        RECT  36.528 101.952 36.72 101.976 ;
    END
  END dq[603]
  PIN dq[604]
    DIRECTION OUTPUT ;
    USE SIGNAL ;
    PORT
      LAYER M4 ;
        RECT  36.528 102.144 36.72 102.168 ;
    END
  END dq[604]
  PIN dq[605]
    DIRECTION OUTPUT ;
    USE SIGNAL ;
    PORT
      LAYER M4 ;
        RECT  36.528 102.288 36.72 102.312 ;
    END
  END dq[605]
  PIN dq[606]
    DIRECTION OUTPUT ;
    USE SIGNAL ;
    PORT
      LAYER M4 ;
        RECT  36.528 102.432 36.72 102.456 ;
    END
  END dq[606]
  PIN dq[607]
    DIRECTION OUTPUT ;
    USE SIGNAL ;
    PORT
      LAYER M4 ;
        RECT  36.528 102.624 36.72 102.648 ;
    END
  END dq[607]
  PIN dq[608]
    DIRECTION OUTPUT ;
    USE SIGNAL ;
    PORT
      LAYER M4 ;
        RECT  36.528 102.768 36.72 102.792 ;
    END
  END dq[608]
  PIN dq[609]
    DIRECTION OUTPUT ;
    USE SIGNAL ;
    PORT
      LAYER M4 ;
        RECT  36.528 102.96 36.72 102.984 ;
    END
  END dq[609]
  PIN dq[60]
    DIRECTION OUTPUT ;
    USE SIGNAL ;
    PORT
      LAYER M4 ;
        RECT  36.528 14.112 36.72 14.136 ;
    END
  END dq[60]
  PIN dq[610]
    DIRECTION OUTPUT ;
    USE SIGNAL ;
    PORT
      LAYER M4 ;
        RECT  36.528 103.104 36.72 103.128 ;
    END
  END dq[610]
  PIN dq[611]
    DIRECTION OUTPUT ;
    USE SIGNAL ;
    PORT
      LAYER M4 ;
        RECT  36.528 103.248 36.72 103.272 ;
    END
  END dq[611]
  PIN dq[612]
    DIRECTION OUTPUT ;
    USE SIGNAL ;
    PORT
      LAYER M4 ;
        RECT  36.528 103.44 36.72 103.464 ;
    END
  END dq[612]
  PIN dq[613]
    DIRECTION OUTPUT ;
    USE SIGNAL ;
    PORT
      LAYER M4 ;
        RECT  36.528 103.584 36.72 103.608 ;
    END
  END dq[613]
  PIN dq[614]
    DIRECTION OUTPUT ;
    USE SIGNAL ;
    PORT
      LAYER M4 ;
        RECT  36.528 103.728 36.72 103.752 ;
    END
  END dq[614]
  PIN dq[615]
    DIRECTION OUTPUT ;
    USE SIGNAL ;
    PORT
      LAYER M4 ;
        RECT  36.528 103.92 36.72 103.944 ;
    END
  END dq[615]
  PIN dq[616]
    DIRECTION OUTPUT ;
    USE SIGNAL ;
    PORT
      LAYER M4 ;
        RECT  36.528 104.064 36.72 104.088 ;
    END
  END dq[616]
  PIN dq[617]
    DIRECTION OUTPUT ;
    USE SIGNAL ;
    PORT
      LAYER M4 ;
        RECT  36.528 104.256 36.72 104.28 ;
    END
  END dq[617]
  PIN dq[618]
    DIRECTION OUTPUT ;
    USE SIGNAL ;
    PORT
      LAYER M4 ;
        RECT  36.528 104.4 36.72 104.424 ;
    END
  END dq[618]
  PIN dq[619]
    DIRECTION OUTPUT ;
    USE SIGNAL ;
    PORT
      LAYER M4 ;
        RECT  36.528 104.544 36.72 104.568 ;
    END
  END dq[619]
  PIN dq[61]
    DIRECTION OUTPUT ;
    USE SIGNAL ;
    PORT
      LAYER M4 ;
        RECT  36.528 14.304 36.72 14.328 ;
    END
  END dq[61]
  PIN dq[620]
    DIRECTION OUTPUT ;
    USE SIGNAL ;
    PORT
      LAYER M4 ;
        RECT  36.528 104.736 36.72 104.76 ;
    END
  END dq[620]
  PIN dq[621]
    DIRECTION OUTPUT ;
    USE SIGNAL ;
    PORT
      LAYER M4 ;
        RECT  36.528 104.88 36.72 104.904 ;
    END
  END dq[621]
  PIN dq[622]
    DIRECTION OUTPUT ;
    USE SIGNAL ;
    PORT
      LAYER M4 ;
        RECT  36.528 105.024 36.72 105.048 ;
    END
  END dq[622]
  PIN dq[623]
    DIRECTION OUTPUT ;
    USE SIGNAL ;
    PORT
      LAYER M4 ;
        RECT  36.528 105.216 36.72 105.24 ;
    END
  END dq[623]
  PIN dq[624]
    DIRECTION OUTPUT ;
    USE SIGNAL ;
    PORT
      LAYER M4 ;
        RECT  36.528 105.36 36.72 105.384 ;
    END
  END dq[624]
  PIN dq[625]
    DIRECTION OUTPUT ;
    USE SIGNAL ;
    PORT
      LAYER M4 ;
        RECT  36.528 105.552 36.72 105.576 ;
    END
  END dq[625]
  PIN dq[626]
    DIRECTION OUTPUT ;
    USE SIGNAL ;
    PORT
      LAYER M4 ;
        RECT  36.528 105.696 36.72 105.72 ;
    END
  END dq[626]
  PIN dq[627]
    DIRECTION OUTPUT ;
    USE SIGNAL ;
    PORT
      LAYER M4 ;
        RECT  36.528 105.84 36.72 105.864 ;
    END
  END dq[627]
  PIN dq[628]
    DIRECTION OUTPUT ;
    USE SIGNAL ;
    PORT
      LAYER M4 ;
        RECT  36.528 106.032 36.72 106.056 ;
    END
  END dq[628]
  PIN dq[629]
    DIRECTION OUTPUT ;
    USE SIGNAL ;
    PORT
      LAYER M4 ;
        RECT  36.528 106.176 36.72 106.2 ;
    END
  END dq[629]
  PIN dq[62]
    DIRECTION OUTPUT ;
    USE SIGNAL ;
    PORT
      LAYER M4 ;
        RECT  36.528 14.448 36.72 14.472 ;
    END
  END dq[62]
  PIN dq[630]
    DIRECTION OUTPUT ;
    USE SIGNAL ;
    PORT
      LAYER M4 ;
        RECT  36.528 106.32 36.72 106.344 ;
    END
  END dq[630]
  PIN dq[631]
    DIRECTION OUTPUT ;
    USE SIGNAL ;
    PORT
      LAYER M4 ;
        RECT  36.528 106.512 36.72 106.536 ;
    END
  END dq[631]
  PIN dq[632]
    DIRECTION OUTPUT ;
    USE SIGNAL ;
    PORT
      LAYER M4 ;
        RECT  36.528 106.656 36.72 106.68 ;
    END
  END dq[632]
  PIN dq[633]
    DIRECTION OUTPUT ;
    USE SIGNAL ;
    PORT
      LAYER M4 ;
        RECT  36.528 106.848 36.72 106.872 ;
    END
  END dq[633]
  PIN dq[634]
    DIRECTION OUTPUT ;
    USE SIGNAL ;
    PORT
      LAYER M4 ;
        RECT  36.528 106.992 36.72 107.016 ;
    END
  END dq[634]
  PIN dq[635]
    DIRECTION OUTPUT ;
    USE SIGNAL ;
    PORT
      LAYER M4 ;
        RECT  36.528 107.136 36.72 107.16 ;
    END
  END dq[635]
  PIN dq[636]
    DIRECTION OUTPUT ;
    USE SIGNAL ;
    PORT
      LAYER M4 ;
        RECT  36.528 107.328 36.72 107.352 ;
    END
  END dq[636]
  PIN dq[637]
    DIRECTION OUTPUT ;
    USE SIGNAL ;
    PORT
      LAYER M4 ;
        RECT  36.528 107.472 36.72 107.496 ;
    END
  END dq[637]
  PIN dq[638]
    DIRECTION OUTPUT ;
    USE SIGNAL ;
    PORT
      LAYER M4 ;
        RECT  36.528 107.616 36.72 107.64 ;
    END
  END dq[638]
  PIN dq[639]
    DIRECTION OUTPUT ;
    USE SIGNAL ;
    PORT
      LAYER M4 ;
        RECT  36.528 107.808 36.72 107.832 ;
    END
  END dq[639]
  PIN dq[63]
    DIRECTION OUTPUT ;
    USE SIGNAL ;
    PORT
      LAYER M4 ;
        RECT  36.528 14.592 36.72 14.616 ;
    END
  END dq[63]
  PIN dq[640]
    DIRECTION OUTPUT ;
    USE SIGNAL ;
    PORT
      LAYER M4 ;
        RECT  36.528 107.952 36.72 107.976 ;
    END
  END dq[640]
  PIN dq[641]
    DIRECTION OUTPUT ;
    USE SIGNAL ;
    PORT
      LAYER M4 ;
        RECT  36.528 108.096 36.72 108.12 ;
    END
  END dq[641]
  PIN dq[642]
    DIRECTION OUTPUT ;
    USE SIGNAL ;
    PORT
      LAYER M4 ;
        RECT  36.528 108.288 36.72 108.312 ;
    END
  END dq[642]
  PIN dq[643]
    DIRECTION OUTPUT ;
    USE SIGNAL ;
    PORT
      LAYER M4 ;
        RECT  36.528 108.432 36.72 108.456 ;
    END
  END dq[643]
  PIN dq[644]
    DIRECTION OUTPUT ;
    USE SIGNAL ;
    PORT
      LAYER M4 ;
        RECT  36.528 108.624 36.72 108.648 ;
    END
  END dq[644]
  PIN dq[645]
    DIRECTION OUTPUT ;
    USE SIGNAL ;
    PORT
      LAYER M4 ;
        RECT  36.528 108.768 36.72 108.792 ;
    END
  END dq[645]
  PIN dq[646]
    DIRECTION OUTPUT ;
    USE SIGNAL ;
    PORT
      LAYER M4 ;
        RECT  36.528 108.912 36.72 108.936 ;
    END
  END dq[646]
  PIN dq[647]
    DIRECTION OUTPUT ;
    USE SIGNAL ;
    PORT
      LAYER M4 ;
        RECT  36.528 109.104 36.72 109.128 ;
    END
  END dq[647]
  PIN dq[648]
    DIRECTION OUTPUT ;
    USE SIGNAL ;
    PORT
      LAYER M4 ;
        RECT  36.528 109.248 36.72 109.272 ;
    END
  END dq[648]
  PIN dq[649]
    DIRECTION OUTPUT ;
    USE SIGNAL ;
    PORT
      LAYER M4 ;
        RECT  36.528 109.392 36.72 109.416 ;
    END
  END dq[649]
  PIN dq[64]
    DIRECTION OUTPUT ;
    USE SIGNAL ;
    PORT
      LAYER M4 ;
        RECT  36.528 14.784 36.72 14.808 ;
    END
  END dq[64]
  PIN dq[650]
    DIRECTION OUTPUT ;
    USE SIGNAL ;
    PORT
      LAYER M4 ;
        RECT  36.528 109.584 36.72 109.608 ;
    END
  END dq[650]
  PIN dq[651]
    DIRECTION OUTPUT ;
    USE SIGNAL ;
    PORT
      LAYER M4 ;
        RECT  36.528 109.728 36.72 109.752 ;
    END
  END dq[651]
  PIN dq[652]
    DIRECTION OUTPUT ;
    USE SIGNAL ;
    PORT
      LAYER M4 ;
        RECT  36.528 109.92 36.72 109.944 ;
    END
  END dq[652]
  PIN dq[653]
    DIRECTION OUTPUT ;
    USE SIGNAL ;
    PORT
      LAYER M4 ;
        RECT  36.528 110.064 36.72 110.088 ;
    END
  END dq[653]
  PIN dq[654]
    DIRECTION OUTPUT ;
    USE SIGNAL ;
    PORT
      LAYER M4 ;
        RECT  36.528 110.208 36.72 110.232 ;
    END
  END dq[654]
  PIN dq[655]
    DIRECTION OUTPUT ;
    USE SIGNAL ;
    PORT
      LAYER M4 ;
        RECT  36.528 110.4 36.72 110.424 ;
    END
  END dq[655]
  PIN dq[656]
    DIRECTION OUTPUT ;
    USE SIGNAL ;
    PORT
      LAYER M4 ;
        RECT  36.528 110.544 36.72 110.568 ;
    END
  END dq[656]
  PIN dq[657]
    DIRECTION OUTPUT ;
    USE SIGNAL ;
    PORT
      LAYER M4 ;
        RECT  36.528 110.688 36.72 110.712 ;
    END
  END dq[657]
  PIN dq[658]
    DIRECTION OUTPUT ;
    USE SIGNAL ;
    PORT
      LAYER M4 ;
        RECT  36.528 110.88 36.72 110.904 ;
    END
  END dq[658]
  PIN dq[659]
    DIRECTION OUTPUT ;
    USE SIGNAL ;
    PORT
      LAYER M4 ;
        RECT  36.528 111.024 36.72 111.048 ;
    END
  END dq[659]
  PIN dq[65]
    DIRECTION OUTPUT ;
    USE SIGNAL ;
    PORT
      LAYER M4 ;
        RECT  36.528 14.928 36.72 14.952 ;
    END
  END dq[65]
  PIN dq[660]
    DIRECTION OUTPUT ;
    USE SIGNAL ;
    PORT
      LAYER M4 ;
        RECT  36.528 111.216 36.72 111.24 ;
    END
  END dq[660]
  PIN dq[661]
    DIRECTION OUTPUT ;
    USE SIGNAL ;
    PORT
      LAYER M4 ;
        RECT  36.528 111.36 36.72 111.384 ;
    END
  END dq[661]
  PIN dq[662]
    DIRECTION OUTPUT ;
    USE SIGNAL ;
    PORT
      LAYER M4 ;
        RECT  36.528 111.504 36.72 111.528 ;
    END
  END dq[662]
  PIN dq[663]
    DIRECTION OUTPUT ;
    USE SIGNAL ;
    PORT
      LAYER M4 ;
        RECT  36.528 111.696 36.72 111.72 ;
    END
  END dq[663]
  PIN dq[664]
    DIRECTION OUTPUT ;
    USE SIGNAL ;
    PORT
      LAYER M4 ;
        RECT  36.528 111.84 36.72 111.864 ;
    END
  END dq[664]
  PIN dq[665]
    DIRECTION OUTPUT ;
    USE SIGNAL ;
    PORT
      LAYER M4 ;
        RECT  36.528 111.984 36.72 112.008 ;
    END
  END dq[665]
  PIN dq[666]
    DIRECTION OUTPUT ;
    USE SIGNAL ;
    PORT
      LAYER M4 ;
        RECT  36.528 112.176 36.72 112.2 ;
    END
  END dq[666]
  PIN dq[667]
    DIRECTION OUTPUT ;
    USE SIGNAL ;
    PORT
      LAYER M4 ;
        RECT  36.528 112.32 36.72 112.344 ;
    END
  END dq[667]
  PIN dq[668]
    DIRECTION OUTPUT ;
    USE SIGNAL ;
    PORT
      LAYER M4 ;
        RECT  36.528 112.464 36.72 112.488 ;
    END
  END dq[668]
  PIN dq[669]
    DIRECTION OUTPUT ;
    USE SIGNAL ;
    PORT
      LAYER M4 ;
        RECT  36.528 112.656 36.72 112.68 ;
    END
  END dq[669]
  PIN dq[66]
    DIRECTION OUTPUT ;
    USE SIGNAL ;
    PORT
      LAYER M4 ;
        RECT  36.528 15.072 36.72 15.096 ;
    END
  END dq[66]
  PIN dq[670]
    DIRECTION OUTPUT ;
    USE SIGNAL ;
    PORT
      LAYER M4 ;
        RECT  36.528 112.8 36.72 112.824 ;
    END
  END dq[670]
  PIN dq[671]
    DIRECTION OUTPUT ;
    USE SIGNAL ;
    PORT
      LAYER M4 ;
        RECT  36.528 112.992 36.72 113.016 ;
    END
  END dq[671]
  PIN dq[672]
    DIRECTION OUTPUT ;
    USE SIGNAL ;
    PORT
      LAYER M4 ;
        RECT  36.528 113.136 36.72 113.16 ;
    END
  END dq[672]
  PIN dq[673]
    DIRECTION OUTPUT ;
    USE SIGNAL ;
    PORT
      LAYER M4 ;
        RECT  36.528 113.28 36.72 113.304 ;
    END
  END dq[673]
  PIN dq[674]
    DIRECTION OUTPUT ;
    USE SIGNAL ;
    PORT
      LAYER M4 ;
        RECT  36.528 113.472 36.72 113.496 ;
    END
  END dq[674]
  PIN dq[675]
    DIRECTION OUTPUT ;
    USE SIGNAL ;
    PORT
      LAYER M4 ;
        RECT  36.528 113.616 36.72 113.64 ;
    END
  END dq[675]
  PIN dq[676]
    DIRECTION OUTPUT ;
    USE SIGNAL ;
    PORT
      LAYER M4 ;
        RECT  36.528 113.76 36.72 113.784 ;
    END
  END dq[676]
  PIN dq[677]
    DIRECTION OUTPUT ;
    USE SIGNAL ;
    PORT
      LAYER M4 ;
        RECT  36.528 113.952 36.72 113.976 ;
    END
  END dq[677]
  PIN dq[678]
    DIRECTION OUTPUT ;
    USE SIGNAL ;
    PORT
      LAYER M4 ;
        RECT  36.528 114.096 36.72 114.12 ;
    END
  END dq[678]
  PIN dq[679]
    DIRECTION OUTPUT ;
    USE SIGNAL ;
    PORT
      LAYER M4 ;
        RECT  36.528 114.288 36.72 114.312 ;
    END
  END dq[679]
  PIN dq[67]
    DIRECTION OUTPUT ;
    USE SIGNAL ;
    PORT
      LAYER M4 ;
        RECT  36.528 15.264 36.72 15.288 ;
    END
  END dq[67]
  PIN dq[680]
    DIRECTION OUTPUT ;
    USE SIGNAL ;
    PORT
      LAYER M4 ;
        RECT  36.528 114.432 36.72 114.456 ;
    END
  END dq[680]
  PIN dq[681]
    DIRECTION OUTPUT ;
    USE SIGNAL ;
    PORT
      LAYER M4 ;
        RECT  36.528 114.576 36.72 114.6 ;
    END
  END dq[681]
  PIN dq[682]
    DIRECTION OUTPUT ;
    USE SIGNAL ;
    PORT
      LAYER M4 ;
        RECT  36.528 114.768 36.72 114.792 ;
    END
  END dq[682]
  PIN dq[683]
    DIRECTION OUTPUT ;
    USE SIGNAL ;
    PORT
      LAYER M4 ;
        RECT  36.528 114.912 36.72 114.936 ;
    END
  END dq[683]
  PIN dq[684]
    DIRECTION OUTPUT ;
    USE SIGNAL ;
    PORT
      LAYER M4 ;
        RECT  36.528 115.056 36.72 115.08 ;
    END
  END dq[684]
  PIN dq[685]
    DIRECTION OUTPUT ;
    USE SIGNAL ;
    PORT
      LAYER M4 ;
        RECT  36.528 115.248 36.72 115.272 ;
    END
  END dq[685]
  PIN dq[686]
    DIRECTION OUTPUT ;
    USE SIGNAL ;
    PORT
      LAYER M4 ;
        RECT  36.528 115.392 36.72 115.416 ;
    END
  END dq[686]
  PIN dq[687]
    DIRECTION OUTPUT ;
    USE SIGNAL ;
    PORT
      LAYER M4 ;
        RECT  36.528 115.584 36.72 115.608 ;
    END
  END dq[687]
  PIN dq[688]
    DIRECTION OUTPUT ;
    USE SIGNAL ;
    PORT
      LAYER M4 ;
        RECT  36.528 115.728 36.72 115.752 ;
    END
  END dq[688]
  PIN dq[689]
    DIRECTION OUTPUT ;
    USE SIGNAL ;
    PORT
      LAYER M4 ;
        RECT  36.528 115.872 36.72 115.896 ;
    END
  END dq[689]
  PIN dq[68]
    DIRECTION OUTPUT ;
    USE SIGNAL ;
    PORT
      LAYER M4 ;
        RECT  36.528 15.408 36.72 15.432 ;
    END
  END dq[68]
  PIN dq[690]
    DIRECTION OUTPUT ;
    USE SIGNAL ;
    PORT
      LAYER M4 ;
        RECT  36.528 116.064 36.72 116.088 ;
    END
  END dq[690]
  PIN dq[691]
    DIRECTION OUTPUT ;
    USE SIGNAL ;
    PORT
      LAYER M4 ;
        RECT  36.528 116.208 36.72 116.232 ;
    END
  END dq[691]
  PIN dq[692]
    DIRECTION OUTPUT ;
    USE SIGNAL ;
    PORT
      LAYER M4 ;
        RECT  36.528 116.352 36.72 116.376 ;
    END
  END dq[692]
  PIN dq[693]
    DIRECTION OUTPUT ;
    USE SIGNAL ;
    PORT
      LAYER M4 ;
        RECT  36.528 116.544 36.72 116.568 ;
    END
  END dq[693]
  PIN dq[694]
    DIRECTION OUTPUT ;
    USE SIGNAL ;
    PORT
      LAYER M4 ;
        RECT  36.528 116.688 36.72 116.712 ;
    END
  END dq[694]
  PIN dq[695]
    DIRECTION OUTPUT ;
    USE SIGNAL ;
    PORT
      LAYER M4 ;
        RECT  36.528 116.832 36.72 116.856 ;
    END
  END dq[695]
  PIN dq[696]
    DIRECTION OUTPUT ;
    USE SIGNAL ;
    PORT
      LAYER M4 ;
        RECT  36.528 117.024 36.72 117.048 ;
    END
  END dq[696]
  PIN dq[697]
    DIRECTION OUTPUT ;
    USE SIGNAL ;
    PORT
      LAYER M4 ;
        RECT  36.528 117.168 36.72 117.192 ;
    END
  END dq[697]
  PIN dq[698]
    DIRECTION OUTPUT ;
    USE SIGNAL ;
    PORT
      LAYER M4 ;
        RECT  36.528 117.36 36.72 117.384 ;
    END
  END dq[698]
  PIN dq[699]
    DIRECTION OUTPUT ;
    USE SIGNAL ;
    PORT
      LAYER M4 ;
        RECT  36.528 117.504 36.72 117.528 ;
    END
  END dq[699]
  PIN dq[69]
    DIRECTION OUTPUT ;
    USE SIGNAL ;
    PORT
      LAYER M4 ;
        RECT  36.528 15.6 36.72 15.624 ;
    END
  END dq[69]
  PIN dq[6]
    DIRECTION OUTPUT ;
    USE SIGNAL ;
    PORT
      LAYER M4 ;
        RECT  36.528 5.376 36.72 5.4 ;
    END
  END dq[6]
  PIN dq[700]
    DIRECTION OUTPUT ;
    USE SIGNAL ;
    PORT
      LAYER M4 ;
        RECT  36.528 117.648 36.72 117.672 ;
    END
  END dq[700]
  PIN dq[701]
    DIRECTION OUTPUT ;
    USE SIGNAL ;
    PORT
      LAYER M4 ;
        RECT  36.528 117.84 36.72 117.864 ;
    END
  END dq[701]
  PIN dq[702]
    DIRECTION OUTPUT ;
    USE SIGNAL ;
    PORT
      LAYER M4 ;
        RECT  36.528 117.984 36.72 118.008 ;
    END
  END dq[702]
  PIN dq[703]
    DIRECTION OUTPUT ;
    USE SIGNAL ;
    PORT
      LAYER M4 ;
        RECT  36.528 118.128 36.72 118.152 ;
    END
  END dq[703]
  PIN dq[704]
    DIRECTION OUTPUT ;
    USE SIGNAL ;
    PORT
      LAYER M4 ;
        RECT  36.528 118.32 36.72 118.344 ;
    END
  END dq[704]
  PIN dq[705]
    DIRECTION OUTPUT ;
    USE SIGNAL ;
    PORT
      LAYER M4 ;
        RECT  36.528 118.464 36.72 118.488 ;
    END
  END dq[705]
  PIN dq[706]
    DIRECTION OUTPUT ;
    USE SIGNAL ;
    PORT
      LAYER M4 ;
        RECT  36.528 118.656 36.72 118.68 ;
    END
  END dq[706]
  PIN dq[707]
    DIRECTION OUTPUT ;
    USE SIGNAL ;
    PORT
      LAYER M4 ;
        RECT  36.528 118.8 36.72 118.824 ;
    END
  END dq[707]
  PIN dq[708]
    DIRECTION OUTPUT ;
    USE SIGNAL ;
    PORT
      LAYER M4 ;
        RECT  36.528 118.944 36.72 118.968 ;
    END
  END dq[708]
  PIN dq[709]
    DIRECTION OUTPUT ;
    USE SIGNAL ;
    PORT
      LAYER M4 ;
        RECT  36.528 119.136 36.72 119.16 ;
    END
  END dq[709]
  PIN dq[70]
    DIRECTION OUTPUT ;
    USE SIGNAL ;
    PORT
      LAYER M4 ;
        RECT  36.528 15.744 36.72 15.768 ;
    END
  END dq[70]
  PIN dq[710]
    DIRECTION OUTPUT ;
    USE SIGNAL ;
    PORT
      LAYER M4 ;
        RECT  36.528 119.28 36.72 119.304 ;
    END
  END dq[710]
  PIN dq[711]
    DIRECTION OUTPUT ;
    USE SIGNAL ;
    PORT
      LAYER M4 ;
        RECT  36.528 119.424 36.72 119.448 ;
    END
  END dq[711]
  PIN dq[712]
    DIRECTION OUTPUT ;
    USE SIGNAL ;
    PORT
      LAYER M4 ;
        RECT  36.528 119.616 36.72 119.64 ;
    END
  END dq[712]
  PIN dq[713]
    DIRECTION OUTPUT ;
    USE SIGNAL ;
    PORT
      LAYER M4 ;
        RECT  36.528 119.76 36.72 119.784 ;
    END
  END dq[713]
  PIN dq[714]
    DIRECTION OUTPUT ;
    USE SIGNAL ;
    PORT
      LAYER M4 ;
        RECT  36.528 119.952 36.72 119.976 ;
    END
  END dq[714]
  PIN dq[715]
    DIRECTION OUTPUT ;
    USE SIGNAL ;
    PORT
      LAYER M4 ;
        RECT  36.528 120.096 36.72 120.12 ;
    END
  END dq[715]
  PIN dq[716]
    DIRECTION OUTPUT ;
    USE SIGNAL ;
    PORT
      LAYER M4 ;
        RECT  36.528 120.24 36.72 120.264 ;
    END
  END dq[716]
  PIN dq[717]
    DIRECTION OUTPUT ;
    USE SIGNAL ;
    PORT
      LAYER M4 ;
        RECT  36.528 120.432 36.72 120.456 ;
    END
  END dq[717]
  PIN dq[718]
    DIRECTION OUTPUT ;
    USE SIGNAL ;
    PORT
      LAYER M4 ;
        RECT  36.528 120.576 36.72 120.6 ;
    END
  END dq[718]
  PIN dq[719]
    DIRECTION OUTPUT ;
    USE SIGNAL ;
    PORT
      LAYER M4 ;
        RECT  36.528 120.72 36.72 120.744 ;
    END
  END dq[719]
  PIN dq[71]
    DIRECTION OUTPUT ;
    USE SIGNAL ;
    PORT
      LAYER M4 ;
        RECT  36.528 15.888 36.72 15.912 ;
    END
  END dq[71]
  PIN dq[720]
    DIRECTION OUTPUT ;
    USE SIGNAL ;
    PORT
      LAYER M4 ;
        RECT  36.528 120.912 36.72 120.936 ;
    END
  END dq[720]
  PIN dq[721]
    DIRECTION OUTPUT ;
    USE SIGNAL ;
    PORT
      LAYER M4 ;
        RECT  36.528 121.056 36.72 121.08 ;
    END
  END dq[721]
  PIN dq[722]
    DIRECTION OUTPUT ;
    USE SIGNAL ;
    PORT
      LAYER M4 ;
        RECT  36.528 121.2 36.72 121.224 ;
    END
  END dq[722]
  PIN dq[723]
    DIRECTION OUTPUT ;
    USE SIGNAL ;
    PORT
      LAYER M4 ;
        RECT  36.528 121.392 36.72 121.416 ;
    END
  END dq[723]
  PIN dq[724]
    DIRECTION OUTPUT ;
    USE SIGNAL ;
    PORT
      LAYER M4 ;
        RECT  36.528 121.536 36.72 121.56 ;
    END
  END dq[724]
  PIN dq[725]
    DIRECTION OUTPUT ;
    USE SIGNAL ;
    PORT
      LAYER M4 ;
        RECT  36.528 121.728 36.72 121.752 ;
    END
  END dq[725]
  PIN dq[726]
    DIRECTION OUTPUT ;
    USE SIGNAL ;
    PORT
      LAYER M4 ;
        RECT  36.528 121.872 36.72 121.896 ;
    END
  END dq[726]
  PIN dq[727]
    DIRECTION OUTPUT ;
    USE SIGNAL ;
    PORT
      LAYER M4 ;
        RECT  36.528 122.016 36.72 122.04 ;
    END
  END dq[727]
  PIN dq[728]
    DIRECTION OUTPUT ;
    USE SIGNAL ;
    PORT
      LAYER M4 ;
        RECT  36.528 122.208 36.72 122.232 ;
    END
  END dq[728]
  PIN dq[729]
    DIRECTION OUTPUT ;
    USE SIGNAL ;
    PORT
      LAYER M4 ;
        RECT  36.528 122.352 36.72 122.376 ;
    END
  END dq[729]
  PIN dq[72]
    DIRECTION OUTPUT ;
    USE SIGNAL ;
    PORT
      LAYER M4 ;
        RECT  36.528 16.08 36.72 16.104 ;
    END
  END dq[72]
  PIN dq[730]
    DIRECTION OUTPUT ;
    USE SIGNAL ;
    PORT
      LAYER M4 ;
        RECT  36.528 122.496 36.72 122.52 ;
    END
  END dq[730]
  PIN dq[731]
    DIRECTION OUTPUT ;
    USE SIGNAL ;
    PORT
      LAYER M4 ;
        RECT  36.528 122.688 36.72 122.712 ;
    END
  END dq[731]
  PIN dq[732]
    DIRECTION OUTPUT ;
    USE SIGNAL ;
    PORT
      LAYER M4 ;
        RECT  36.528 122.832 36.72 122.856 ;
    END
  END dq[732]
  PIN dq[733]
    DIRECTION OUTPUT ;
    USE SIGNAL ;
    PORT
      LAYER M4 ;
        RECT  36.528 123.024 36.72 123.048 ;
    END
  END dq[733]
  PIN dq[734]
    DIRECTION OUTPUT ;
    USE SIGNAL ;
    PORT
      LAYER M4 ;
        RECT  36.528 123.168 36.72 123.192 ;
    END
  END dq[734]
  PIN dq[735]
    DIRECTION OUTPUT ;
    USE SIGNAL ;
    PORT
      LAYER M4 ;
        RECT  36.528 123.312 36.72 123.336 ;
    END
  END dq[735]
  PIN dq[736]
    DIRECTION OUTPUT ;
    USE SIGNAL ;
    PORT
      LAYER M4 ;
        RECT  36.528 123.504 36.72 123.528 ;
    END
  END dq[736]
  PIN dq[737]
    DIRECTION OUTPUT ;
    USE SIGNAL ;
    PORT
      LAYER M4 ;
        RECT  36.528 123.648 36.72 123.672 ;
    END
  END dq[737]
  PIN dq[738]
    DIRECTION OUTPUT ;
    USE SIGNAL ;
    PORT
      LAYER M4 ;
        RECT  36.528 123.792 36.72 123.816 ;
    END
  END dq[738]
  PIN dq[739]
    DIRECTION OUTPUT ;
    USE SIGNAL ;
    PORT
      LAYER M4 ;
        RECT  36.528 123.984 36.72 124.008 ;
    END
  END dq[739]
  PIN dq[73]
    DIRECTION OUTPUT ;
    USE SIGNAL ;
    PORT
      LAYER M4 ;
        RECT  36.528 16.224 36.72 16.248 ;
    END
  END dq[73]
  PIN dq[740]
    DIRECTION OUTPUT ;
    USE SIGNAL ;
    PORT
      LAYER M4 ;
        RECT  36.528 124.128 36.72 124.152 ;
    END
  END dq[740]
  PIN dq[741]
    DIRECTION OUTPUT ;
    USE SIGNAL ;
    PORT
      LAYER M4 ;
        RECT  36.528 124.32 36.72 124.344 ;
    END
  END dq[741]
  PIN dq[742]
    DIRECTION OUTPUT ;
    USE SIGNAL ;
    PORT
      LAYER M4 ;
        RECT  36.528 124.464 36.72 124.488 ;
    END
  END dq[742]
  PIN dq[743]
    DIRECTION OUTPUT ;
    USE SIGNAL ;
    PORT
      LAYER M4 ;
        RECT  36.528 124.608 36.72 124.632 ;
    END
  END dq[743]
  PIN dq[744]
    DIRECTION OUTPUT ;
    USE SIGNAL ;
    PORT
      LAYER M4 ;
        RECT  36.528 124.8 36.72 124.824 ;
    END
  END dq[744]
  PIN dq[745]
    DIRECTION OUTPUT ;
    USE SIGNAL ;
    PORT
      LAYER M4 ;
        RECT  36.528 124.944 36.72 124.968 ;
    END
  END dq[745]
  PIN dq[746]
    DIRECTION OUTPUT ;
    USE SIGNAL ;
    PORT
      LAYER M4 ;
        RECT  36.528 125.088 36.72 125.112 ;
    END
  END dq[746]
  PIN dq[747]
    DIRECTION OUTPUT ;
    USE SIGNAL ;
    PORT
      LAYER M4 ;
        RECT  36.528 125.28 36.72 125.304 ;
    END
  END dq[747]
  PIN dq[748]
    DIRECTION OUTPUT ;
    USE SIGNAL ;
    PORT
      LAYER M4 ;
        RECT  36.528 125.424 36.72 125.448 ;
    END
  END dq[748]
  PIN dq[749]
    DIRECTION OUTPUT ;
    USE SIGNAL ;
    PORT
      LAYER M4 ;
        RECT  36.528 125.568 36.72 125.592 ;
    END
  END dq[749]
  PIN dq[74]
    DIRECTION OUTPUT ;
    USE SIGNAL ;
    PORT
      LAYER M4 ;
        RECT  36.528 16.368 36.72 16.392 ;
    END
  END dq[74]
  PIN dq[750]
    DIRECTION OUTPUT ;
    USE SIGNAL ;
    PORT
      LAYER M4 ;
        RECT  36.528 125.76 36.72 125.784 ;
    END
  END dq[750]
  PIN dq[751]
    DIRECTION OUTPUT ;
    USE SIGNAL ;
    PORT
      LAYER M4 ;
        RECT  36.528 125.904 36.72 125.928 ;
    END
  END dq[751]
  PIN dq[752]
    DIRECTION OUTPUT ;
    USE SIGNAL ;
    PORT
      LAYER M4 ;
        RECT  36.528 126.096 36.72 126.12 ;
    END
  END dq[752]
  PIN dq[753]
    DIRECTION OUTPUT ;
    USE SIGNAL ;
    PORT
      LAYER M4 ;
        RECT  36.528 126.24 36.72 126.264 ;
    END
  END dq[753]
  PIN dq[754]
    DIRECTION OUTPUT ;
    USE SIGNAL ;
    PORT
      LAYER M4 ;
        RECT  36.528 126.384 36.72 126.408 ;
    END
  END dq[754]
  PIN dq[755]
    DIRECTION OUTPUT ;
    USE SIGNAL ;
    PORT
      LAYER M4 ;
        RECT  36.528 126.576 36.72 126.6 ;
    END
  END dq[755]
  PIN dq[756]
    DIRECTION OUTPUT ;
    USE SIGNAL ;
    PORT
      LAYER M4 ;
        RECT  36.528 126.72 36.72 126.744 ;
    END
  END dq[756]
  PIN dq[757]
    DIRECTION OUTPUT ;
    USE SIGNAL ;
    PORT
      LAYER M4 ;
        RECT  36.528 126.864 36.72 126.888 ;
    END
  END dq[757]
  PIN dq[758]
    DIRECTION OUTPUT ;
    USE SIGNAL ;
    PORT
      LAYER M4 ;
        RECT  36.528 127.056 36.72 127.08 ;
    END
  END dq[758]
  PIN dq[759]
    DIRECTION OUTPUT ;
    USE SIGNAL ;
    PORT
      LAYER M4 ;
        RECT  36.528 127.2 36.72 127.224 ;
    END
  END dq[759]
  PIN dq[75]
    DIRECTION OUTPUT ;
    USE SIGNAL ;
    PORT
      LAYER M4 ;
        RECT  36.528 16.56 36.72 16.584 ;
    END
  END dq[75]
  PIN dq[760]
    DIRECTION OUTPUT ;
    USE SIGNAL ;
    PORT
      LAYER M4 ;
        RECT  36.528 127.392 36.72 127.416 ;
    END
  END dq[760]
  PIN dq[76]
    DIRECTION OUTPUT ;
    USE SIGNAL ;
    PORT
      LAYER M4 ;
        RECT  36.528 16.704 36.72 16.728 ;
    END
  END dq[76]
  PIN dq[77]
    DIRECTION OUTPUT ;
    USE SIGNAL ;
    PORT
      LAYER M4 ;
        RECT  36.528 16.848 36.72 16.872 ;
    END
  END dq[77]
  PIN dq[78]
    DIRECTION OUTPUT ;
    USE SIGNAL ;
    PORT
      LAYER M4 ;
        RECT  36.528 17.04 36.72 17.064 ;
    END
  END dq[78]
  PIN dq[79]
    DIRECTION OUTPUT ;
    USE SIGNAL ;
    PORT
      LAYER M4 ;
        RECT  36.528 17.184 36.72 17.208 ;
    END
  END dq[79]
  PIN dq[7]
    DIRECTION OUTPUT ;
    USE SIGNAL ;
    PORT
      LAYER M4 ;
        RECT  36.528 5.568 36.72 5.592 ;
    END
  END dq[7]
  PIN dq[80]
    DIRECTION OUTPUT ;
    USE SIGNAL ;
    PORT
      LAYER M4 ;
        RECT  36.528 17.376 36.72 17.4 ;
    END
  END dq[80]
  PIN dq[81]
    DIRECTION OUTPUT ;
    USE SIGNAL ;
    PORT
      LAYER M4 ;
        RECT  36.528 17.52 36.72 17.544 ;
    END
  END dq[81]
  PIN dq[82]
    DIRECTION OUTPUT ;
    USE SIGNAL ;
    PORT
      LAYER M4 ;
        RECT  36.528 17.664 36.72 17.688 ;
    END
  END dq[82]
  PIN dq[83]
    DIRECTION OUTPUT ;
    USE SIGNAL ;
    PORT
      LAYER M4 ;
        RECT  36.528 17.856 36.72 17.88 ;
    END
  END dq[83]
  PIN dq[84]
    DIRECTION OUTPUT ;
    USE SIGNAL ;
    PORT
      LAYER M4 ;
        RECT  36.528 18 36.72 18.024 ;
    END
  END dq[84]
  PIN dq[85]
    DIRECTION OUTPUT ;
    USE SIGNAL ;
    PORT
      LAYER M4 ;
        RECT  36.528 18.144 36.72 18.168 ;
    END
  END dq[85]
  PIN dq[86]
    DIRECTION OUTPUT ;
    USE SIGNAL ;
    PORT
      LAYER M4 ;
        RECT  36.528 18.336 36.72 18.36 ;
    END
  END dq[86]
  PIN dq[87]
    DIRECTION OUTPUT ;
    USE SIGNAL ;
    PORT
      LAYER M4 ;
        RECT  36.528 18.48 36.72 18.504 ;
    END
  END dq[87]
  PIN dq[88]
    DIRECTION OUTPUT ;
    USE SIGNAL ;
    PORT
      LAYER M4 ;
        RECT  36.528 18.672 36.72 18.696 ;
    END
  END dq[88]
  PIN dq[89]
    DIRECTION OUTPUT ;
    USE SIGNAL ;
    PORT
      LAYER M4 ;
        RECT  36.528 18.816 36.72 18.84 ;
    END
  END dq[89]
  PIN dq[8]
    DIRECTION OUTPUT ;
    USE SIGNAL ;
    PORT
      LAYER M4 ;
        RECT  36.528 5.712 36.72 5.736 ;
    END
  END dq[8]
  PIN dq[90]
    DIRECTION OUTPUT ;
    USE SIGNAL ;
    PORT
      LAYER M4 ;
        RECT  36.528 18.96 36.72 18.984 ;
    END
  END dq[90]
  PIN dq[91]
    DIRECTION OUTPUT ;
    USE SIGNAL ;
    PORT
      LAYER M4 ;
        RECT  36.528 19.152 36.72 19.176 ;
    END
  END dq[91]
  PIN dq[92]
    DIRECTION OUTPUT ;
    USE SIGNAL ;
    PORT
      LAYER M4 ;
        RECT  36.528 19.296 36.72 19.32 ;
    END
  END dq[92]
  PIN dq[93]
    DIRECTION OUTPUT ;
    USE SIGNAL ;
    PORT
      LAYER M4 ;
        RECT  36.528 19.44 36.72 19.464 ;
    END
  END dq[93]
  PIN dq[94]
    DIRECTION OUTPUT ;
    USE SIGNAL ;
    PORT
      LAYER M4 ;
        RECT  36.528 19.632 36.72 19.656 ;
    END
  END dq[94]
  PIN dq[95]
    DIRECTION OUTPUT ;
    USE SIGNAL ;
    PORT
      LAYER M4 ;
        RECT  36.528 19.776 36.72 19.8 ;
    END
  END dq[95]
  PIN dq[96]
    DIRECTION OUTPUT ;
    USE SIGNAL ;
    PORT
      LAYER M4 ;
        RECT  36.528 19.968 36.72 19.992 ;
    END
  END dq[96]
  PIN dq[97]
    DIRECTION OUTPUT ;
    USE SIGNAL ;
    PORT
      LAYER M4 ;
        RECT  36.528 20.112 36.72 20.136 ;
    END
  END dq[97]
  PIN dq[98]
    DIRECTION OUTPUT ;
    USE SIGNAL ;
    PORT
      LAYER M4 ;
        RECT  36.528 20.256 36.72 20.28 ;
    END
  END dq[98]
  PIN dq[99]
    DIRECTION OUTPUT ;
    USE SIGNAL ;
    PORT
      LAYER M4 ;
        RECT  36.528 20.448 36.72 20.472 ;
    END
  END dq[99]
  PIN dq[9]
    DIRECTION OUTPUT ;
    USE SIGNAL ;
    PORT
      LAYER M4 ;
        RECT  36.528 5.856 36.72 5.88 ;
    END
  END dq[9]
  PIN VDD
    DIRECTION INOUT ;
    USE POWER ;
    PORT
      LAYER M5 ;
        RECT  32.292 2.151 32.412 129.609 ;
        RECT  29.592 2.151 29.712 129.609 ;
        RECT  26.892 2.151 27.012 129.609 ;
        RECT  24.192 2.151 24.312 129.609 ;
        RECT  21.492 2.151 21.612 129.609 ;
        RECT  18.792 2.151 18.912 129.609 ;
        RECT  16.092 2.151 16.212 129.609 ;
        RECT  13.392 2.151 13.512 129.609 ;
        RECT  10.692 2.151 10.812 129.609 ;
        RECT  7.992 2.151 8.112 129.609 ;
        RECT  5.292 2.151 5.412 129.609 ;
        RECT  2.592 2.151 2.712 129.609 ;
    END
  END VDD
  PIN VSS
    DIRECTION INOUT ;
    USE GROUND ;
    PORT
      LAYER M5 ;
        RECT  32.1 2.137 32.22 129.623 ;
        RECT  29.4 2.137 29.52 129.623 ;
        RECT  26.7 2.137 26.82 129.623 ;
        RECT  24 2.137 24.12 129.623 ;
        RECT  21.3 2.137 21.42 129.623 ;
        RECT  18.6 2.137 18.72 129.623 ;
        RECT  15.9 2.137 16.02 129.623 ;
        RECT  13.2 2.137 13.32 129.623 ;
        RECT  10.5 2.137 10.62 129.623 ;
        RECT  7.8 2.137 7.92 129.623 ;
        RECT  5.1 2.137 5.22 129.623 ;
        RECT  2.4 2.137 2.52 129.623 ;
    END
  END VSS
  # OT_OBS_CLOSED layer=M5 d_um=1.536 added=115
  OBS
    LAYER RVTN ;
     RECT  2.16 2.16 34.56 2.295 ;
     RECT  2.16 2.565 34.56 2.835 ;
     RECT  2.16 3.105 34.56 3.375 ;
     RECT  2.16 3.645 34.56 3.915 ;
     RECT  2.16 4.185 34.56 4.455 ;
     RECT  2.16 4.725 34.56 4.995 ;
     RECT  2.16 5.265 34.56 5.535 ;
     RECT  2.16 5.805 34.56 6.075 ;
     RECT  2.16 6.345 34.56 6.615 ;
     RECT  2.16 6.885 34.56 7.155 ;
     RECT  2.16 7.425 34.56 7.695 ;
     RECT  2.16 7.965 34.56 8.235 ;
     RECT  2.16 8.505 34.56 8.775 ;
     RECT  2.16 9.045 34.56 9.315 ;
     RECT  2.16 9.585 34.56 9.855 ;
     RECT  2.16 10.125 34.56 10.395 ;
     RECT  2.16 10.665 34.56 10.935 ;
     RECT  2.16 11.205 34.56 11.475 ;
     RECT  2.16 11.745 34.56 12.015 ;
     RECT  2.16 12.285 34.56 12.555 ;
     RECT  2.16 12.825 34.56 13.095 ;
     RECT  2.16 13.365 34.56 13.635 ;
     RECT  2.16 13.905 34.56 14.175 ;
     RECT  2.16 14.445 34.56 14.715 ;
     RECT  2.16 14.985 34.56 15.255 ;
     RECT  2.16 15.525 34.56 15.795 ;
     RECT  2.16 16.065 34.56 16.335 ;
     RECT  2.16 16.605 34.56 16.875 ;
     RECT  2.16 17.145 34.56 17.415 ;
     RECT  2.16 17.685 34.56 17.955 ;
     RECT  2.16 18.225 34.56 18.495 ;
     RECT  2.16 18.765 34.56 19.035 ;
     RECT  2.16 19.305 34.56 19.575 ;
     RECT  2.16 19.845 34.56 20.115 ;
     RECT  2.16 20.385 34.56 20.655 ;
     RECT  2.16 20.925 34.56 21.195 ;
     RECT  2.16 21.465 34.56 21.735 ;
     RECT  2.16 22.005 34.56 22.275 ;
     RECT  2.16 22.545 34.56 22.815 ;
     RECT  2.16 23.085 34.56 23.355 ;
     RECT  2.16 23.625 34.56 23.895 ;
     RECT  2.16 24.165 34.56 24.435 ;
     RECT  2.16 24.705 34.56 24.975 ;
     RECT  2.16 25.245 34.56 25.515 ;
     RECT  2.16 25.785 34.56 26.055 ;
     RECT  2.16 26.325 34.56 26.595 ;
     RECT  2.16 26.865 34.56 27.135 ;
     RECT  2.16 27.405 34.56 27.675 ;
     RECT  2.16 27.945 34.56 28.215 ;
     RECT  2.16 28.485 34.56 28.755 ;
     RECT  2.16 29.025 34.56 29.295 ;
     RECT  2.16 29.565 34.56 29.835 ;
     RECT  2.16 30.105 34.56 30.375 ;
     RECT  2.16 30.645 34.56 30.915 ;
     RECT  2.16 31.185 34.56 31.455 ;
     RECT  2.16 31.725 34.56 31.995 ;
     RECT  2.16 32.265 34.56 32.535 ;
     RECT  2.16 32.805 34.56 33.075 ;
     RECT  2.16 33.345 34.56 33.615 ;
     RECT  2.16 33.885 34.56 34.155 ;
     RECT  2.16 34.425 34.56 34.695 ;
     RECT  2.16 34.965 34.56 35.235 ;
     RECT  2.16 35.505 34.56 35.775 ;
     RECT  2.16 36.045 34.56 36.315 ;
     RECT  2.16 36.585 34.56 36.855 ;
     RECT  2.16 37.125 34.56 37.395 ;
     RECT  2.16 37.665 34.56 37.935 ;
     RECT  2.16 38.205 34.56 38.475 ;
     RECT  2.16 38.745 34.56 39.015 ;
     RECT  2.16 39.285 34.56 39.555 ;
     RECT  2.16 39.825 34.56 40.095 ;
     RECT  2.16 40.365 34.56 40.635 ;
     RECT  2.16 40.905 34.56 41.175 ;
     RECT  2.16 41.445 34.56 41.715 ;
     RECT  2.16 41.985 34.56 42.255 ;
     RECT  2.16 42.525 34.56 42.795 ;
     RECT  2.16 43.065 34.56 43.335 ;
     RECT  2.16 43.605 34.56 43.875 ;
     RECT  2.16 44.145 34.56 44.415 ;
     RECT  2.16 44.685 34.56 44.955 ;
     RECT  2.16 45.225 34.56 45.495 ;
     RECT  2.16 45.765 34.56 46.035 ;
     RECT  2.16 46.305 34.56 46.575 ;
     RECT  2.16 46.845 34.56 47.115 ;
     RECT  2.16 47.385 34.56 47.655 ;
     RECT  2.16 47.925 34.56 48.195 ;
     RECT  2.16 48.465 34.56 48.735 ;
     RECT  2.16 49.005 34.56 49.275 ;
     RECT  2.16 49.545 34.56 49.815 ;
     RECT  2.16 50.085 34.56 50.355 ;
     RECT  2.16 50.625 34.56 50.895 ;
     RECT  2.16 51.165 34.56 51.435 ;
     RECT  2.16 51.705 34.56 51.975 ;
     RECT  2.16 52.245 34.56 52.515 ;
     RECT  2.16 52.785 34.56 53.055 ;
     RECT  2.16 53.325 34.56 53.595 ;
     RECT  2.16 53.865 34.56 54.135 ;
     RECT  2.16 54.405 34.56 54.675 ;
     RECT  2.16 54.945 34.56 55.215 ;
     RECT  2.16 55.485 34.56 55.755 ;
     RECT  2.16 56.025 34.56 56.295 ;
     RECT  2.16 56.565 34.56 56.835 ;
     RECT  2.16 57.105 34.56 57.375 ;
     RECT  2.16 57.645 34.56 57.915 ;
     RECT  2.16 58.185 34.56 58.455 ;
     RECT  2.16 58.725 34.56 58.995 ;
     RECT  2.16 59.265 34.56 59.535 ;
     RECT  2.16 59.805 34.56 60.075 ;
     RECT  2.16 60.345 34.56 60.615 ;
     RECT  2.16 60.885 34.56 61.155 ;
     RECT  2.16 61.425 34.56 61.695 ;
     RECT  2.16 61.965 34.56 62.235 ;
     RECT  2.16 62.505 34.56 62.775 ;
     RECT  2.16 63.045 34.56 63.315 ;
     RECT  2.16 63.585 34.56 63.855 ;
     RECT  2.16 64.125 34.56 64.395 ;
     RECT  2.16 64.665 34.56 64.935 ;
     RECT  2.16 65.205 34.56 65.475 ;
     RECT  2.16 65.745 34.56 66.015 ;
     RECT  2.16 66.285 34.56 66.555 ;
     RECT  2.16 66.825 34.56 67.095 ;
     RECT  2.16 67.365 34.56 67.635 ;
     RECT  2.16 67.905 34.56 68.175 ;
     RECT  2.16 68.445 34.56 68.715 ;
     RECT  2.16 68.985 34.56 69.255 ;
     RECT  2.16 69.525 34.56 69.795 ;
     RECT  2.16 70.065 34.56 70.335 ;
     RECT  2.16 70.605 34.56 70.875 ;
     RECT  2.16 71.145 34.56 71.415 ;
     RECT  2.16 71.685 34.56 71.955 ;
     RECT  2.16 72.225 34.56 72.495 ;
     RECT  2.16 72.765 34.56 73.035 ;
     RECT  2.16 73.305 34.56 73.575 ;
     RECT  2.16 73.845 34.56 74.115 ;
     RECT  2.16 74.385 34.56 74.655 ;
     RECT  2.16 74.925 34.56 75.195 ;
     RECT  2.16 75.465 34.56 75.735 ;
     RECT  2.16 76.005 34.56 76.275 ;
     RECT  2.16 76.545 34.56 76.815 ;
     RECT  2.16 77.085 34.56 77.355 ;
     RECT  2.16 77.625 34.56 77.895 ;
     RECT  2.16 78.165 34.56 78.435 ;
     RECT  2.16 78.705 34.56 78.975 ;
     RECT  2.16 79.245 34.56 79.515 ;
     RECT  2.16 79.785 34.56 80.055 ;
     RECT  2.16 80.325 34.56 80.595 ;
     RECT  2.16 80.865 34.56 81.135 ;
     RECT  2.16 81.405 34.56 81.675 ;
     RECT  2.16 81.945 34.56 82.215 ;
     RECT  2.16 82.485 34.56 82.755 ;
     RECT  2.16 83.025 34.56 83.295 ;
     RECT  2.16 83.565 34.56 83.835 ;
     RECT  2.16 84.105 34.56 84.375 ;
     RECT  2.16 84.645 34.56 84.915 ;
     RECT  2.16 85.185 34.56 85.455 ;
     RECT  2.16 85.725 34.56 85.995 ;
     RECT  2.16 86.265 34.56 86.535 ;
     RECT  2.16 86.805 34.56 87.075 ;
     RECT  2.16 87.345 34.56 87.615 ;
     RECT  2.16 87.885 34.56 88.155 ;
     RECT  2.16 88.425 34.56 88.695 ;
     RECT  2.16 88.965 34.56 89.235 ;
     RECT  2.16 89.505 34.56 89.775 ;
     RECT  2.16 90.045 34.56 90.315 ;
     RECT  2.16 90.585 34.56 90.855 ;
     RECT  2.16 91.125 34.56 91.395 ;
     RECT  2.16 91.665 34.56 91.935 ;
     RECT  2.16 92.205 34.56 92.475 ;
     RECT  2.16 92.745 34.56 93.015 ;
     RECT  2.16 93.285 34.56 93.555 ;
     RECT  2.16 93.825 34.56 94.095 ;
     RECT  2.16 94.365 34.56 94.635 ;
     RECT  2.16 94.905 34.56 95.175 ;
     RECT  2.16 95.445 34.56 95.715 ;
     RECT  2.16 95.985 34.56 96.255 ;
     RECT  2.16 96.525 34.56 96.795 ;
     RECT  2.16 97.065 34.56 97.335 ;
     RECT  2.16 97.605 34.56 97.875 ;
     RECT  2.16 98.145 34.56 98.415 ;
     RECT  2.16 98.685 34.56 98.955 ;
     RECT  2.16 99.225 34.56 99.495 ;
     RECT  2.16 99.765 34.56 100.035 ;
     RECT  2.16 100.305 34.56 100.575 ;
     RECT  2.16 100.845 34.56 101.115 ;
     RECT  2.16 101.385 34.56 101.655 ;
     RECT  2.16 101.925 34.56 102.195 ;
     RECT  2.16 102.465 34.56 102.735 ;
     RECT  2.16 103.005 34.56 103.275 ;
     RECT  2.16 103.545 34.56 103.815 ;
     RECT  2.16 104.085 34.56 104.355 ;
     RECT  2.16 104.625 34.56 104.895 ;
     RECT  2.16 105.165 34.56 105.435 ;
     RECT  2.16 105.705 34.56 105.975 ;
     RECT  2.16 106.245 34.56 106.515 ;
     RECT  2.16 106.785 34.56 107.055 ;
     RECT  2.16 107.325 34.56 107.595 ;
     RECT  2.16 107.865 34.56 108.135 ;
     RECT  2.16 108.405 34.56 108.675 ;
     RECT  2.16 108.945 34.56 109.215 ;
     RECT  2.16 109.485 34.56 109.755 ;
     RECT  2.16 110.025 34.56 110.295 ;
     RECT  2.16 110.565 34.56 110.835 ;
     RECT  2.16 111.105 34.56 111.375 ;
     RECT  2.16 111.645 34.56 111.915 ;
     RECT  2.16 112.185 34.56 112.455 ;
     RECT  2.16 112.725 34.56 112.995 ;
     RECT  2.16 113.265 34.56 113.535 ;
     RECT  2.16 113.805 34.56 114.075 ;
     RECT  2.16 114.345 34.56 114.615 ;
     RECT  2.16 114.885 34.56 115.155 ;
     RECT  2.16 115.425 34.56 115.695 ;
     RECT  2.16 115.965 34.56 116.235 ;
     RECT  2.16 116.505 34.56 116.775 ;
     RECT  2.16 117.045 34.56 117.315 ;
     RECT  2.16 117.585 34.56 117.855 ;
     RECT  2.16 118.125 34.56 118.395 ;
     RECT  2.16 118.665 34.56 118.935 ;
     RECT  2.16 119.205 34.56 119.475 ;
     RECT  2.16 119.745 34.56 120.015 ;
     RECT  2.16 120.285 34.56 120.555 ;
     RECT  2.16 120.825 34.56 121.095 ;
     RECT  2.16 121.365 34.56 121.635 ;
     RECT  2.16 121.905 34.56 122.175 ;
     RECT  2.16 122.445 34.56 122.715 ;
     RECT  2.16 122.985 34.56 123.255 ;
     RECT  2.16 123.525 34.56 123.795 ;
     RECT  2.16 124.065 34.56 124.335 ;
     RECT  2.16 124.605 34.56 124.875 ;
     RECT  2.16 125.145 34.56 125.415 ;
     RECT  2.16 125.685 34.56 125.955 ;
     RECT  2.16 126.225 34.56 126.495 ;
     RECT  2.16 126.765 34.56 127.035 ;
     RECT  2.16 127.305 34.56 127.575 ;
     RECT  2.16 127.845 34.56 128.115 ;
     RECT  2.16 128.385 34.56 128.655 ;
     RECT  2.16 128.925 34.56 129.195 ;
     RECT  2.16 129.465 34.56 129.6 ;
    LAYER RVTP ;
     RECT  2.16 2.295 34.56 2.565 ;
     RECT  2.16 2.835 34.56 3.105 ;
     RECT  2.16 3.375 34.56 3.645 ;
     RECT  2.16 3.915 34.56 4.185 ;
     RECT  2.16 4.455 34.56 4.725 ;
     RECT  2.16 4.995 34.56 5.265 ;
     RECT  2.16 5.535 34.56 5.805 ;
     RECT  2.16 6.075 34.56 6.345 ;
     RECT  2.16 6.615 34.56 6.885 ;
     RECT  2.16 7.155 34.56 7.425 ;
     RECT  2.16 7.695 34.56 7.965 ;
     RECT  2.16 8.235 34.56 8.505 ;
     RECT  2.16 8.775 34.56 9.045 ;
     RECT  2.16 9.315 34.56 9.585 ;
     RECT  2.16 9.855 34.56 10.125 ;
     RECT  2.16 10.395 34.56 10.665 ;
     RECT  2.16 10.935 34.56 11.205 ;
     RECT  2.16 11.475 34.56 11.745 ;
     RECT  2.16 12.015 34.56 12.285 ;
     RECT  2.16 12.555 34.56 12.825 ;
     RECT  2.16 13.095 34.56 13.365 ;
     RECT  2.16 13.635 34.56 13.905 ;
     RECT  2.16 14.175 34.56 14.445 ;
     RECT  2.16 14.715 34.56 14.985 ;
     RECT  2.16 15.255 34.56 15.525 ;
     RECT  2.16 15.795 34.56 16.065 ;
     RECT  2.16 16.335 34.56 16.605 ;
     RECT  2.16 16.875 34.56 17.145 ;
     RECT  2.16 17.415 34.56 17.685 ;
     RECT  2.16 17.955 34.56 18.225 ;
     RECT  2.16 18.495 34.56 18.765 ;
     RECT  2.16 19.035 34.56 19.305 ;
     RECT  2.16 19.575 34.56 19.845 ;
     RECT  2.16 20.115 34.56 20.385 ;
     RECT  2.16 20.655 34.56 20.925 ;
     RECT  2.16 21.195 34.56 21.465 ;
     RECT  2.16 21.735 34.56 22.005 ;
     RECT  2.16 22.275 34.56 22.545 ;
     RECT  2.16 22.815 34.56 23.085 ;
     RECT  2.16 23.355 34.56 23.625 ;
     RECT  2.16 23.895 34.56 24.165 ;
     RECT  2.16 24.435 34.56 24.705 ;
     RECT  2.16 24.975 34.56 25.245 ;
     RECT  2.16 25.515 34.56 25.785 ;
     RECT  2.16 26.055 34.56 26.325 ;
     RECT  2.16 26.595 34.56 26.865 ;
     RECT  2.16 27.135 34.56 27.405 ;
     RECT  2.16 27.675 34.56 27.945 ;
     RECT  2.16 28.215 34.56 28.485 ;
     RECT  2.16 28.755 34.56 29.025 ;
     RECT  2.16 29.295 34.56 29.565 ;
     RECT  2.16 29.835 34.56 30.105 ;
     RECT  2.16 30.375 34.56 30.645 ;
     RECT  2.16 30.915 34.56 31.185 ;
     RECT  2.16 31.455 34.56 31.725 ;
     RECT  2.16 31.995 34.56 32.265 ;
     RECT  2.16 32.535 34.56 32.805 ;
     RECT  2.16 33.075 34.56 33.345 ;
     RECT  2.16 33.615 34.56 33.885 ;
     RECT  2.16 34.155 34.56 34.425 ;
     RECT  2.16 34.695 34.56 34.965 ;
     RECT  2.16 35.235 34.56 35.505 ;
     RECT  2.16 35.775 34.56 36.045 ;
     RECT  2.16 36.315 34.56 36.585 ;
     RECT  2.16 36.855 34.56 37.125 ;
     RECT  2.16 37.395 34.56 37.665 ;
     RECT  2.16 37.935 34.56 38.205 ;
     RECT  2.16 38.475 34.56 38.745 ;
     RECT  2.16 39.015 34.56 39.285 ;
     RECT  2.16 39.555 34.56 39.825 ;
     RECT  2.16 40.095 34.56 40.365 ;
     RECT  2.16 40.635 34.56 40.905 ;
     RECT  2.16 41.175 34.56 41.445 ;
     RECT  2.16 41.715 34.56 41.985 ;
     RECT  2.16 42.255 34.56 42.525 ;
     RECT  2.16 42.795 34.56 43.065 ;
     RECT  2.16 43.335 34.56 43.605 ;
     RECT  2.16 43.875 34.56 44.145 ;
     RECT  2.16 44.415 34.56 44.685 ;
     RECT  2.16 44.955 34.56 45.225 ;
     RECT  2.16 45.495 34.56 45.765 ;
     RECT  2.16 46.035 34.56 46.305 ;
     RECT  2.16 46.575 34.56 46.845 ;
     RECT  2.16 47.115 34.56 47.385 ;
     RECT  2.16 47.655 34.56 47.925 ;
     RECT  2.16 48.195 34.56 48.465 ;
     RECT  2.16 48.735 34.56 49.005 ;
     RECT  2.16 49.275 34.56 49.545 ;
     RECT  2.16 49.815 34.56 50.085 ;
     RECT  2.16 50.355 34.56 50.625 ;
     RECT  2.16 50.895 34.56 51.165 ;
     RECT  2.16 51.435 34.56 51.705 ;
     RECT  2.16 51.975 34.56 52.245 ;
     RECT  2.16 52.515 34.56 52.785 ;
     RECT  2.16 53.055 34.56 53.325 ;
     RECT  2.16 53.595 34.56 53.865 ;
     RECT  2.16 54.135 34.56 54.405 ;
     RECT  2.16 54.675 34.56 54.945 ;
     RECT  2.16 55.215 34.56 55.485 ;
     RECT  2.16 55.755 34.56 56.025 ;
     RECT  2.16 56.295 34.56 56.565 ;
     RECT  2.16 56.835 34.56 57.105 ;
     RECT  2.16 57.375 34.56 57.645 ;
     RECT  2.16 57.915 34.56 58.185 ;
     RECT  2.16 58.455 34.56 58.725 ;
     RECT  2.16 58.995 34.56 59.265 ;
     RECT  2.16 59.535 34.56 59.805 ;
     RECT  2.16 60.075 34.56 60.345 ;
     RECT  2.16 60.615 34.56 60.885 ;
     RECT  2.16 61.155 34.56 61.425 ;
     RECT  2.16 61.695 34.56 61.965 ;
     RECT  2.16 62.235 34.56 62.505 ;
     RECT  2.16 62.775 34.56 63.045 ;
     RECT  2.16 63.315 34.56 63.585 ;
     RECT  2.16 63.855 34.56 64.125 ;
     RECT  2.16 64.395 34.56 64.665 ;
     RECT  2.16 64.935 34.56 65.205 ;
     RECT  2.16 65.475 34.56 65.745 ;
     RECT  2.16 66.015 34.56 66.285 ;
     RECT  2.16 66.555 34.56 66.825 ;
     RECT  2.16 67.095 34.56 67.365 ;
     RECT  2.16 67.635 34.56 67.905 ;
     RECT  2.16 68.175 34.56 68.445 ;
     RECT  2.16 68.715 34.56 68.985 ;
     RECT  2.16 69.255 34.56 69.525 ;
     RECT  2.16 69.795 34.56 70.065 ;
     RECT  2.16 70.335 34.56 70.605 ;
     RECT  2.16 70.875 34.56 71.145 ;
     RECT  2.16 71.415 34.56 71.685 ;
     RECT  2.16 71.955 34.56 72.225 ;
     RECT  2.16 72.495 34.56 72.765 ;
     RECT  2.16 73.035 34.56 73.305 ;
     RECT  2.16 73.575 34.56 73.845 ;
     RECT  2.16 74.115 34.56 74.385 ;
     RECT  2.16 74.655 34.56 74.925 ;
     RECT  2.16 75.195 34.56 75.465 ;
     RECT  2.16 75.735 34.56 76.005 ;
     RECT  2.16 76.275 34.56 76.545 ;
     RECT  2.16 76.815 34.56 77.085 ;
     RECT  2.16 77.355 34.56 77.625 ;
     RECT  2.16 77.895 34.56 78.165 ;
     RECT  2.16 78.435 34.56 78.705 ;
     RECT  2.16 78.975 34.56 79.245 ;
     RECT  2.16 79.515 34.56 79.785 ;
     RECT  2.16 80.055 34.56 80.325 ;
     RECT  2.16 80.595 34.56 80.865 ;
     RECT  2.16 81.135 34.56 81.405 ;
     RECT  2.16 81.675 34.56 81.945 ;
     RECT  2.16 82.215 34.56 82.485 ;
     RECT  2.16 82.755 34.56 83.025 ;
     RECT  2.16 83.295 34.56 83.565 ;
     RECT  2.16 83.835 34.56 84.105 ;
     RECT  2.16 84.375 34.56 84.645 ;
     RECT  2.16 84.915 34.56 85.185 ;
     RECT  2.16 85.455 34.56 85.725 ;
     RECT  2.16 85.995 34.56 86.265 ;
     RECT  2.16 86.535 34.56 86.805 ;
     RECT  2.16 87.075 34.56 87.345 ;
     RECT  2.16 87.615 34.56 87.885 ;
     RECT  2.16 88.155 34.56 88.425 ;
     RECT  2.16 88.695 34.56 88.965 ;
     RECT  2.16 89.235 34.56 89.505 ;
     RECT  2.16 89.775 34.56 90.045 ;
     RECT  2.16 90.315 34.56 90.585 ;
     RECT  2.16 90.855 34.56 91.125 ;
     RECT  2.16 91.395 34.56 91.665 ;
     RECT  2.16 91.935 34.56 92.205 ;
     RECT  2.16 92.475 34.56 92.745 ;
     RECT  2.16 93.015 34.56 93.285 ;
     RECT  2.16 93.555 34.56 93.825 ;
     RECT  2.16 94.095 34.56 94.365 ;
     RECT  2.16 94.635 34.56 94.905 ;
     RECT  2.16 95.175 34.56 95.445 ;
     RECT  2.16 95.715 34.56 95.985 ;
     RECT  2.16 96.255 34.56 96.525 ;
     RECT  2.16 96.795 34.56 97.065 ;
     RECT  2.16 97.335 34.56 97.605 ;
     RECT  2.16 97.875 34.56 98.145 ;
     RECT  2.16 98.415 34.56 98.685 ;
     RECT  2.16 98.955 34.56 99.225 ;
     RECT  2.16 99.495 34.56 99.765 ;
     RECT  2.16 100.035 34.56 100.305 ;
     RECT  2.16 100.575 34.56 100.845 ;
     RECT  2.16 101.115 34.56 101.385 ;
     RECT  2.16 101.655 34.56 101.925 ;
     RECT  2.16 102.195 34.56 102.465 ;
     RECT  2.16 102.735 34.56 103.005 ;
     RECT  2.16 103.275 34.56 103.545 ;
     RECT  2.16 103.815 34.56 104.085 ;
     RECT  2.16 104.355 34.56 104.625 ;
     RECT  2.16 104.895 34.56 105.165 ;
     RECT  2.16 105.435 34.56 105.705 ;
     RECT  2.16 105.975 34.56 106.245 ;
     RECT  2.16 106.515 34.56 106.785 ;
     RECT  2.16 107.055 34.56 107.325 ;
     RECT  2.16 107.595 34.56 107.865 ;
     RECT  2.16 108.135 34.56 108.405 ;
     RECT  2.16 108.675 34.56 108.945 ;
     RECT  2.16 109.215 34.56 109.485 ;
     RECT  2.16 109.755 34.56 110.025 ;
     RECT  2.16 110.295 34.56 110.565 ;
     RECT  2.16 110.835 34.56 111.105 ;
     RECT  2.16 111.375 34.56 111.645 ;
     RECT  2.16 111.915 34.56 112.185 ;
     RECT  2.16 112.455 34.56 112.725 ;
     RECT  2.16 112.995 34.56 113.265 ;
     RECT  2.16 113.535 34.56 113.805 ;
     RECT  2.16 114.075 34.56 114.345 ;
     RECT  2.16 114.615 34.56 114.885 ;
     RECT  2.16 115.155 34.56 115.425 ;
     RECT  2.16 115.695 34.56 115.965 ;
     RECT  2.16 116.235 34.56 116.505 ;
     RECT  2.16 116.775 34.56 117.045 ;
     RECT  2.16 117.315 34.56 117.585 ;
     RECT  2.16 117.855 34.56 118.125 ;
     RECT  2.16 118.395 34.56 118.665 ;
     RECT  2.16 118.935 34.56 119.205 ;
     RECT  2.16 119.475 34.56 119.745 ;
     RECT  2.16 120.015 34.56 120.285 ;
     RECT  2.16 120.555 34.56 120.825 ;
     RECT  2.16 121.095 34.56 121.365 ;
     RECT  2.16 121.635 34.56 121.905 ;
     RECT  2.16 122.175 34.56 122.445 ;
     RECT  2.16 122.715 34.56 122.985 ;
     RECT  2.16 123.255 34.56 123.525 ;
     RECT  2.16 123.795 34.56 124.065 ;
     RECT  2.16 124.335 34.56 124.605 ;
     RECT  2.16 124.875 34.56 125.145 ;
     RECT  2.16 125.415 34.56 125.685 ;
     RECT  2.16 125.955 34.56 126.225 ;
     RECT  2.16 126.495 34.56 126.765 ;
     RECT  2.16 127.035 34.56 127.305 ;
     RECT  2.16 127.575 34.56 127.845 ;
     RECT  2.16 128.115 34.56 128.385 ;
     RECT  2.16 128.655 34.56 128.925 ;
     RECT  2.16 129.195 34.56 129.465 ;
    LAYER M1 ;
     RECT  2.16 2.151 34.56 129.609 ;
    LAYER M2 ;
     RECT  0.535 11.952 2.16 11.97 ;
     RECT  0.211 17.658 2.16 18.216 ;
     RECT  0.211 19.89 2.16 19.908 ;
     RECT  0.211 38.682 2.16 38.7 ;
     RECT  0.535 63.126 2.16 63.144 ;
     RECT  0.211 69.462 2.16 69.48 ;
     RECT  0.211 99.162 2.16 99.18 ;
     RECT  18.175 131.598 18.383 131.616 ;
     RECT  2.16 2.151 34.56 129.609 ;
     RECT  34.56 5.076 34.655 5.256 ;
     RECT  34.56 2.466 34.691 4.284 ;
     RECT  34.691 2.466 34.763 3.978 ;
     RECT  34.56 6.624 34.763 100.296 ;
     RECT  34.56 111.888 34.763 126.324 ;
     RECT  34.56 127.476 34.763 129.024 ;
     RECT  34.763 3.726 34.799 3.978 ;
     RECT  34.655 5.238 34.799 5.256 ;
     RECT  34.763 14.958 34.799 31.824 ;
     RECT  34.763 32.616 34.799 78.084 ;
     RECT  34.763 78.984 34.799 100.296 ;
     RECT  34.56 101.124 34.799 110.934 ;
     RECT  34.763 125.388 34.799 126.324 ;
     RECT  34.763 6.624 34.835 14.004 ;
     RECT  34.799 20.466 34.835 29.394 ;
     RECT  34.799 48.78 34.835 78.084 ;
     RECT  34.799 78.984 34.835 95.814 ;
     RECT  34.799 32.616 34.871 47.682 ;
     RECT  34.835 78.984 34.871 89.532 ;
     RECT  34.799 3.726 34.907 3.942 ;
     RECT  34.907 3.726 35.375 3.834 ;
     RECT  34.835 6.624 35.375 7.884 ;
     RECT  34.835 8.676 35.375 14.004 ;
     RECT  34.799 15.066 35.375 19.638 ;
     RECT  34.835 20.466 35.375 27.234 ;
     RECT  34.799 30.186 35.375 31.824 ;
     RECT  34.871 32.616 35.375 47.646 ;
     RECT  34.835 48.816 35.375 78.084 ;
     RECT  34.871 78.984 35.375 87.372 ;
     RECT  34.799 106.29 35.375 110.934 ;
     RECT  34.763 111.888 35.375 124.632 ;
     RECT  34.799 125.388 35.375 125.784 ;
     RECT  34.763 127.746 35.375 129.024 ;
     RECT  35.375 26.406 35.411 27.234 ;
     RECT  35.375 32.616 35.411 38.844 ;
     RECT  35.375 41.418 35.411 42.624 ;
     RECT  35.375 48.816 35.411 52.776 ;
     RECT  35.375 54.18 35.411 60.174 ;
     RECT  35.375 79.524 35.411 87.372 ;
     RECT  34.799 97.038 35.411 100.296 ;
     RECT  34.799 101.124 35.411 105.534 ;
     RECT  35.375 125.766 35.411 125.784 ;
     RECT  35.375 74.16 35.447 78.084 ;
     RECT  35.411 101.124 35.447 104.454 ;
     RECT  35.375 127.854 35.627 129.024 ;
     RECT  35.411 49.626 35.879 51.156 ;
     RECT  35.375 61.398 35.879 65.034 ;
     RECT  35.375 65.826 35.879 68.202 ;
     RECT  35.879 50.904 35.915 51.156 ;
     RECT  35.411 54.18 35.915 54.234 ;
     RECT  35.447 102.204 35.915 104.454 ;
     RECT  35.375 110.07 35.915 110.124 ;
     RECT  35.375 3.816 35.951 3.834 ;
     RECT  35.375 6.624 35.951 7.794 ;
     RECT  35.375 8.676 35.951 9.414 ;
     RECT  35.375 10.476 35.951 10.656 ;
     RECT  35.375 11.484 35.951 14.004 ;
     RECT  35.375 15.066 35.951 17.748 ;
     RECT  35.375 18.504 35.951 19.638 ;
     RECT  35.375 20.466 35.951 25.002 ;
     RECT  35.411 26.604 35.951 27.234 ;
     RECT  34.835 28.026 35.951 29.124 ;
     RECT  35.375 30.42 35.951 31.824 ;
     RECT  35.411 33.93 35.951 38.844 ;
     RECT  35.375 39.726 35.951 40.662 ;
     RECT  35.411 41.526 35.951 42.624 ;
     RECT  35.375 43.686 35.951 47.646 ;
     RECT  35.411 48.816 35.951 48.834 ;
     RECT  35.879 49.626 35.951 50.148 ;
     RECT  35.915 51.138 35.951 51.156 ;
     RECT  35.411 51.984 35.951 52.776 ;
     RECT  35.915 54.216 35.951 54.234 ;
     RECT  35.411 55.26 35.951 56.124 ;
     RECT  35.411 57.078 35.951 60.174 ;
     RECT  35.879 63.63 35.951 65.034 ;
     RECT  35.879 65.826 35.951 66.582 ;
     RECT  35.879 67.41 35.951 68.202 ;
     RECT  35.375 68.958 35.951 73.296 ;
     RECT  35.447 74.16 35.951 77.922 ;
     RECT  35.411 79.866 35.951 87.372 ;
     RECT  34.871 88.128 35.951 89.532 ;
     RECT  34.835 90.396 35.951 95.814 ;
     RECT  35.411 97.038 35.951 99.522 ;
     RECT  35.411 100.278 35.951 100.296 ;
     RECT  35.447 101.124 35.951 101.142 ;
     RECT  35.915 102.24 35.951 104.454 ;
     RECT  35.375 106.29 35.951 109.242 ;
     RECT  35.915 110.106 35.951 110.124 ;
     RECT  35.375 110.916 35.951 110.934 ;
     RECT  35.375 111.888 35.951 111.942 ;
     RECT  35.375 112.77 35.951 114.912 ;
     RECT  35.375 116.01 35.951 122.004 ;
     RECT  35.375 122.796 35.951 124.632 ;
     RECT  35.951 8.676 35.987 8.694 ;
     RECT  35.951 11.484 35.987 11.502 ;
     RECT  35.951 12.906 35.987 12.969 ;
     RECT  35.951 13.914 35.987 13.932 ;
     RECT  35.951 15.156 35.987 15.282 ;
     RECT  35.951 19.548 35.987 19.566 ;
     RECT  35.951 20.736 35.987 21.222 ;
     RECT  35.951 22.284 35.987 23.148 ;
     RECT  35.951 23.976 35.987 24.084 ;
     RECT  35.951 24.948 35.987 25.002 ;
     RECT  35.951 26.604 35.987 26.622 ;
     RECT  35.951 28.296 35.987 28.314 ;
     RECT  35.951 29.106 35.987 29.124 ;
     RECT  35.951 31.194 35.987 31.752 ;
     RECT  35.411 32.616 35.987 33.066 ;
     RECT  35.951 33.93 35.987 35.064 ;
     RECT  35.951 36.054 35.987 36.072 ;
     RECT  35.951 37.368 35.987 37.494 ;
     RECT  35.951 38.25 35.987 38.268 ;
     RECT  35.951 41.796 35.987 42.354 ;
     RECT  35.951 43.956 35.987 43.974 ;
     RECT  35.951 44.766 35.987 46.134 ;
     RECT  35.951 47.088 35.987 47.106 ;
     RECT  35.951 52.218 35.987 52.542 ;
     RECT  35.951 55.26 35.987 56.016 ;
     RECT  35.951 57.996 35.987 58.212 ;
     RECT  35.951 59.346 35.987 59.904 ;
     RECT  35.879 61.398 35.987 62.874 ;
     RECT  35.951 63.63 35.987 64.386 ;
     RECT  35.951 66.024 35.987 66.042 ;
     RECT  35.951 67.68 35.987 67.734 ;
     RECT  35.951 68.958 35.987 70.434 ;
     RECT  35.951 72 35.987 72.954 ;
     RECT  35.951 76.824 35.987 77.418 ;
     RECT  35.951 80.136 35.987 80.154 ;
     RECT  35.951 81.756 35.987 82.278 ;
     RECT  35.951 83.034 35.987 83.754 ;
     RECT  35.951 84.69 35.987 86.994 ;
     RECT  35.951 88.236 35.987 88.254 ;
     RECT  35.951 89.28 35.987 89.298 ;
     RECT  35.951 90.666 35.987 91.764 ;
     RECT  35.951 93.258 35.987 93.852 ;
     RECT  35.951 94.878 35.987 94.896 ;
     RECT  35.951 97.578 35.987 97.704 ;
     RECT  35.951 102.744 35.987 102.834 ;
     RECT  35.951 103.626 35.987 103.644 ;
     RECT  35.411 105.516 35.987 105.534 ;
     RECT  35.951 107.568 35.987 107.622 ;
     RECT  35.951 108.72 35.987 109.008 ;
     RECT  35.951 117.666 35.987 118.494 ;
     RECT  35.951 119.52 35.987 119.538 ;
     RECT  35.951 120.87 35.987 121.662 ;
     RECT  35.951 123.3 35.987 124.092 ;
     RECT  35.987 12.951 36.023 12.969 ;
     RECT  35.987 15.156 36.023 15.174 ;
     RECT  35.987 23.13 36.023 23.148 ;
     RECT  35.987 23.976 36.023 23.994 ;
     RECT  35.987 31.5 36.023 31.752 ;
     RECT  35.987 33.048 36.023 33.066 ;
     RECT  35.987 33.93 36.023 33.948 ;
     RECT  35.987 34.704 36.023 34.722 ;
     RECT  35.987 37.368 36.023 37.422 ;
     RECT  35.951 39.726 36.023 40.158 ;
     RECT  35.987 45.468 36.023 45.486 ;
     RECT  35.987 57.996 36.023 58.014 ;
     RECT  35.987 62.28 36.023 62.298 ;
     RECT  35.987 63.63 36.023 63.648 ;
     RECT  35.987 68.958 36.023 69.516 ;
     RECT  35.987 70.416 36.023 70.434 ;
     RECT  35.987 72.738 36.023 72.954 ;
     RECT  35.951 74.16 36.023 74.646 ;
     RECT  35.987 77.4 36.023 77.418 ;
     RECT  35.987 81.756 36.023 81.774 ;
     RECT  35.987 84.69 36.023 84.978 ;
     RECT  35.987 85.734 36.023 85.752 ;
     RECT  35.987 91.71 36.023 91.728 ;
     RECT  35.987 93.366 36.023 93.852 ;
     RECT  35.987 97.686 36.023 97.704 ;
     RECT  35.987 102.744 36.023 102.762 ;
     RECT  35.987 108.72 36.023 108.738 ;
     RECT  35.951 111.924 36.023 111.942 ;
     RECT  35.951 113.274 36.023 114.174 ;
     RECT  35.987 121.644 36.023 121.662 ;
     RECT  35.987 124.074 36.023 124.092 ;
     RECT  35.987 24.984 36.059 25.002 ;
     RECT  36.023 31.5 36.059 31.518 ;
     RECT  36.023 39.726 36.059 39.744 ;
     RECT  35.987 42.264 36.059 42.282 ;
     RECT  35.951 57.186 36.059 57.204 ;
     RECT  35.987 67.68 36.059 67.698 ;
     RECT  36.023 69.498 36.059 69.516 ;
     RECT  36.023 72.936 36.059 72.954 ;
     RECT  36.023 84.96 36.059 84.978 ;
     RECT  36.023 93.834 36.059 93.852 ;
     RECT  35.987 107.604 36.059 107.622 ;
     RECT  36.023 113.58 36.059 113.598 ;
     RECT  35.987 118.476 36.059 118.494 ;
     RECT  36.023 37.368 36.095 37.386 ;
     RECT  34.763 2.466 36.491 2.754 ;
     RECT  35.627 128.556 36.527 129.024 ;
     RECT  36.491 2.466 36.563 2.484 ;
     RECT  35.951 6.822 36.563 6.84 ;
     RECT  36.527 128.556 36.563 128.574 ;
    LAYER M3 ;
     RECT  2.415 2.143 2.505 2.413 ;
     RECT  5.115 2.143 5.205 2.413 ;
     RECT  7.815 2.143 7.905 2.413 ;
     RECT  10.515 2.143 10.605 2.413 ;
     RECT  13.215 2.143 13.305 2.413 ;
     RECT  15.915 2.143 16.005 2.413 ;
     RECT  18.615 2.143 18.705 2.413 ;
     RECT  21.315 2.143 21.405 2.413 ;
     RECT  24.015 2.143 24.105 2.413 ;
     RECT  26.715 2.143 26.805 2.413 ;
     RECT  29.415 2.143 29.505 2.413 ;
     RECT  32.115 2.143 32.205 2.413 ;
     RECT  36.54 2.461 36.558 2.731 ;
     RECT  33.444 2.803 33.462 3.037 ;
     RECT  34.308 2.605 34.326 3.037 ;
     RECT  33.444 3.037 34.326 3.181 ;
     RECT  33.444 3.181 34.758 3.307 ;
     RECT  33.156 3.307 34.758 3.721 ;
     RECT  33.156 3.721 35.37 3.811 ;
     RECT  36.468 2.731 36.558 3.811 ;
     RECT  2.415 2.413 2.697 4.225 ;
     RECT  2.304 4.225 2.697 4.261 ;
     RECT  33.156 3.811 36.558 4.445 ;
     RECT  2.304 4.261 3.618 4.495 ;
     RECT  2.304 4.495 4.122 4.531 ;
     RECT  5.115 2.413 5.397 4.531 ;
     RECT  2.304 4.531 5.397 4.541 ;
     RECT  32.115 2.413 32.397 4.765 ;
     RECT  33.156 4.445 34.902 4.765 ;
     RECT  3.672 4.541 5.397 4.801 ;
     RECT  3.672 4.801 5.814 5.161 ;
     RECT  3.672 5.161 6.318 5.305 ;
     RECT  7.815 2.413 8.097 5.341 ;
     RECT  32.115 4.765 34.902 5.341 ;
     RECT  32.04 5.341 34.902 5.459 ;
     RECT  10.515 2.413 10.797 5.467 ;
     RECT  30.78 5.467 30.798 5.503 ;
     RECT  7.668 5.341 8.097 5.531 ;
     RECT  30.78 5.503 30.87 5.603 ;
     RECT  30.852 5.603 30.87 5.639 ;
     RECT  7.812 5.531 8.097 5.701 ;
     RECT  7.812 5.701 8.694 5.837 ;
     RECT  2.304 4.541 2.862 5.845 ;
     RECT  3.672 5.305 6.426 5.845 ;
     RECT  2.304 5.845 6.57 5.881 ;
     RECT  7.812 5.837 8.097 5.885 ;
     RECT  35.928 4.445 36.558 5.885 ;
     RECT  2.304 5.881 6.822 6.035 ;
     RECT  10.515 5.467 10.818 6.107 ;
     RECT  6.192 6.035 6.822 6.539 ;
     RECT  6.192 6.539 6.426 6.575 ;
     RECT  36.54 5.885 36.558 6.619 ;
     RECT  6.192 6.575 6.318 6.647 ;
     RECT  32.115 5.459 34.902 6.655 ;
     RECT  2.304 6.035 5.397 6.808 ;
     RECT  6.192 6.647 6.282 6.808 ;
     RECT  2.304 6.808 6.282 6.845 ;
     RECT  32.115 6.655 34.938 6.845 ;
     RECT  35.928 6.619 36.558 6.845 ;
     RECT  7.815 5.885 8.097 6.889 ;
     RECT  7.56 6.889 8.097 6.989 ;
     RECT  35.928 6.845 36.486 7.147 ;
     RECT  30.78 7.087 30.798 7.187 ;
     RECT  32.115 6.845 34.326 7.231 ;
     RECT  2.304 6.845 5.397 7.259 ;
     RECT  2.304 7.259 3.222 7.349 ;
     RECT  32.04 7.231 34.326 7.393 ;
     RECT  6.192 6.845 6.282 7.501 ;
     RECT  6.192 7.501 6.894 7.619 ;
     RECT  35.352 7.147 36.486 7.661 ;
     RECT  3.996 7.259 5.397 7.663 ;
     RECT  2.304 7.349 3.15 7.691 ;
     RECT  35.352 7.661 35.946 7.853 ;
     RECT  31.068 7.393 34.326 7.889 ;
     RECT  7.815 6.989 8.097 7.897 ;
     RECT  0.252 7.819 0.27 7.949 ;
     RECT  7.272 7.897 8.097 7.949 ;
     RECT  35.352 7.853 35.37 7.997 ;
     RECT  3.996 7.663 6.066 8.041 ;
     RECT  9.108 7.861 9.126 8.041 ;
     RECT  9.108 8.041 9.198 8.159 ;
     RECT  32.004 7.889 34.326 8.159 ;
     RECT  32.04 8.159 34.326 8.299 ;
     RECT  2.304 7.691 2.97 8.509 ;
     RECT  32.04 8.299 34.83 8.537 ;
     RECT  3.96 8.041 6.066 8.539 ;
     RECT  2.304 8.509 3.222 8.545 ;
     RECT  3.96 8.539 6.75 8.545 ;
     RECT  2.304 8.545 6.75 8.851 ;
     RECT  7.815 7.949 8.097 8.851 ;
     RECT  32.04 8.537 34.758 8.879 ;
     RECT  35.964 8.671 35.982 8.923 ;
     RECT  7.815 8.851 8.19 8.969 ;
     RECT  35.928 8.923 35.982 9.149 ;
     RECT  2.304 8.851 6.894 9.211 ;
     RECT  32.04 8.879 34.29 9.355 ;
     RECT  2.304 9.211 7.002 9.391 ;
     RECT  7.815 8.969 8.097 9.391 ;
     RECT  2.304 9.391 8.097 9.437 ;
     RECT  35.928 9.149 35.946 9.437 ;
     RECT  2.304 9.437 6.606 9.739 ;
     RECT  31.932 9.355 34.29 9.859 ;
     RECT  2.268 9.739 6.606 9.923 ;
     RECT  7.416 9.437 8.097 10.049 ;
     RECT  31.932 9.859 34.326 10.075 ;
     RECT  35.352 9.595 35.37 10.075 ;
     RECT  30.78 8.707 30.798 10.157 ;
     RECT  7.815 10.049 8.097 10.201 ;
     RECT  31.932 10.075 35.37 10.219 ;
     RECT  0.252 10.123 0.27 10.253 ;
     RECT  2.304 9.923 6.606 10.291 ;
     RECT  31.932 10.219 35.946 10.319 ;
     RECT  7.815 10.201 8.154 10.471 ;
     RECT  31.14 10.471 31.158 10.733 ;
     RECT  10.515 6.107 10.797 10.831 ;
     RECT  7.815 10.471 8.514 10.867 ;
     RECT  10.515 10.831 10.854 10.931 ;
     RECT  7.815 10.867 8.838 10.967 ;
     RECT  2.304 10.291 6.966 10.975 ;
     RECT  7.815 10.967 8.097 10.975 ;
     RECT  32.004 10.319 35.946 11.069 ;
     RECT  30.78 10.903 30.834 11.273 ;
     RECT  2.304 10.975 8.097 11.371 ;
     RECT  32.004 11.069 34.794 11.371 ;
     RECT  2.268 11.371 8.097 11.435 ;
     RECT  31.968 11.371 34.794 11.479 ;
     RECT  35.928 11.069 35.946 11.479 ;
     RECT  31.86 11.479 34.794 11.551 ;
     RECT  2.268 11.435 2.697 11.705 ;
     RECT  31.68 11.551 34.794 11.705 ;
     RECT  35.928 11.479 35.982 11.741 ;
     RECT  32.04 11.705 34.794 11.777 ;
     RECT  32.04 11.777 34.578 11.849 ;
     RECT  3.42 11.435 8.097 11.939 ;
     RECT  9.108 11.749 9.126 11.939 ;
     RECT  30.78 11.273 30.798 11.939 ;
     RECT  0.54 11.947 0.558 12.029 ;
     RECT  7.236 11.939 8.097 12.217 ;
     RECT  2.304 11.705 2.697 12.361 ;
     RECT  3.42 11.939 6.462 12.361 ;
     RECT  10.515 10.931 10.797 12.451 ;
     RECT  35.928 11.741 35.946 12.475 ;
     RECT  7.236 12.217 8.262 12.479 ;
     RECT  10.515 12.451 10.818 12.551 ;
     RECT  29.415 2.413 29.697 12.721 ;
     RECT  32.04 11.849 34.254 12.865 ;
     RECT  35.928 12.475 35.982 12.928 ;
     RECT  32.004 12.865 34.794 12.974 ;
     RECT  0.252 12.859 0.27 13.037 ;
     RECT  2.304 12.361 6.462 13.099 ;
     RECT  7.236 12.479 8.097 13.099 ;
     RECT  32.004 12.974 34.362 13.261 ;
     RECT  29.415 12.721 30.222 13.297 ;
     RECT  35.928 12.928 36.018 13.325 ;
     RECT  29.415 13.297 30.798 13.559 ;
     RECT  2.304 13.099 8.097 13.603 ;
     RECT  31.932 13.261 34.362 13.603 ;
     RECT  31.608 13.603 34.362 13.801 ;
     RECT  35.928 13.325 35.982 13.937 ;
     RECT  2.304 13.603 8.154 13.981 ;
     RECT  2.304 13.981 8.838 14.045 ;
     RECT  2.304 14.045 6.066 14.099 ;
     RECT  6.804 14.045 8.838 14.099 ;
     RECT  31.608 13.801 34.794 14.141 ;
     RECT  7.596 14.099 8.838 14.171 ;
     RECT  30.78 13.559 30.798 14.413 ;
     RECT  6.804 14.099 6.822 14.513 ;
     RECT  30.78 14.413 30.87 14.513 ;
     RECT  2.304 14.099 5.886 14.587 ;
     RECT  7.632 14.171 8.838 14.611 ;
     RECT  7.632 14.611 9.126 14.639 ;
     RECT  2.268 14.587 5.886 14.747 ;
     RECT  30.78 14.513 30.798 14.747 ;
     RECT  35.928 13.937 35.946 14.779 ;
     RECT  3.528 14.747 5.886 14.909 ;
     RECT  31.608 14.141 34.758 14.953 ;
     RECT  7.632 14.639 8.097 15.061 ;
     RECT  9.108 14.639 9.126 15.061 ;
     RECT  31.608 14.953 34.794 15.101 ;
     RECT  3.6 14.909 5.886 15.151 ;
     RECT  35.928 14.779 35.982 15.151 ;
     RECT  9.108 15.061 9.162 15.287 ;
     RECT  3.6 15.151 6.534 15.331 ;
     RECT  7.272 15.061 8.097 15.331 ;
     RECT  3.6 15.331 8.097 15.389 ;
     RECT  35.928 15.151 36.018 15.437 ;
     RECT  9.144 15.287 9.162 15.449 ;
     RECT  7.272 15.389 8.097 15.719 ;
     RECT  2.304 14.747 2.79 15.739 ;
     RECT  3.6 15.389 6.174 15.739 ;
     RECT  30.852 15.565 30.87 15.763 ;
     RECT  31.608 15.101 34.362 15.763 ;
     RECT  30.852 15.763 34.362 15.989 ;
     RECT  35.928 15.437 35.946 16.219 ;
     RECT  7.416 15.719 8.097 16.259 ;
     RECT  31.932 15.989 34.362 16.339 ;
     RECT  35.352 16.219 35.946 16.339 ;
     RECT  30.78 16.267 30.798 16.367 ;
     RECT  2.304 15.739 6.174 16.375 ;
     RECT  31.932 16.339 35.946 16.397 ;
     RECT  7.56 16.259 8.097 16.411 ;
     RECT  2.304 16.375 6.21 16.501 ;
     RECT  2.304 16.501 6.246 16.507 ;
     RECT  31.932 16.397 34.29 16.529 ;
     RECT  7.56 16.411 8.154 16.601 ;
     RECT  35.352 16.397 35.946 16.637 ;
     RECT  30.852 16.807 30.942 16.943 ;
     RECT  31.932 16.529 34.254 16.951 ;
     RECT  2.304 16.507 6.606 17.069 ;
     RECT  30.96 16.951 34.254 17.069 ;
     RECT  7.56 16.601 8.097 17.077 ;
     RECT  30.96 17.069 34.218 17.609 ;
     RECT  35.928 16.637 35.946 17.845 ;
     RECT  32.04 17.609 34.218 17.959 ;
     RECT  30.78 17.725 30.87 18.023 ;
     RECT  2.304 17.069 5.994 18.193 ;
     RECT  6.732 17.077 8.097 18.193 ;
     RECT  32.04 17.959 34.326 18.571 ;
     RECT  31.788 18.571 34.326 18.689 ;
     RECT  35.352 17.845 35.946 18.701 ;
     RECT  31.932 18.689 34.326 18.801 ;
     RECT  30.852 18.841 30.87 19.003 ;
     RECT  35.928 18.701 35.946 19.435 ;
     RECT  30.78 19.003 30.87 19.507 ;
     RECT  31.932 18.801 34.362 19.507 ;
     RECT  30.78 19.507 34.362 19.627 ;
     RECT  9.396 18.661 9.414 19.679 ;
     RECT  0.216 17.653 0.234 19.997 ;
     RECT  2.304 18.193 8.097 20.083 ;
     RECT  2.304 20.083 8.154 20.219 ;
     RECT  2.304 20.219 8.097 20.443 ;
     RECT  30.78 19.627 34.794 20.443 ;
     RECT  35.928 19.435 35.982 20.443 ;
     RECT  2.268 20.443 8.097 20.489 ;
     RECT  30.78 20.443 35.982 20.489 ;
     RECT  2.268 20.489 6.966 20.615 ;
     RECT  9.18 20.731 9.522 20.849 ;
     RECT  9.18 20.849 9.198 20.957 ;
     RECT  7.815 20.489 8.097 20.965 ;
     RECT  7.815 20.965 8.19 21.005 ;
     RECT  2.304 20.615 6.966 21.119 ;
     RECT  35.352 20.489 35.982 21.227 ;
     RECT  30.78 20.489 34.254 21.403 ;
     RECT  35.352 21.227 35.946 21.403 ;
     RECT  0.252 20.971 0.27 21.581 ;
     RECT  30.78 21.403 35.946 21.581 ;
     RECT  2.304 21.119 6.894 21.659 ;
     RECT  30.78 21.581 34.794 21.659 ;
     RECT  31.824 21.659 34.794 21.929 ;
     RECT  6.84 21.659 6.894 21.931 ;
     RECT  2.304 21.659 6.102 21.965 ;
     RECT  35.928 21.581 35.946 22.279 ;
     RECT  3.456 21.965 6.102 22.379 ;
     RECT  9.108 22.207 9.126 22.379 ;
     RECT  32.004 21.929 34.794 22.541 ;
     RECT  6.84 21.931 7.002 22.585 ;
     RECT  7.815 21.005 8.097 22.585 ;
     RECT  30.78 21.659 30.87 22.613 ;
     RECT  2.304 21.965 2.697 22.621 ;
     RECT  2.268 22.621 2.697 22.733 ;
     RECT  3.744 22.379 6.102 22.739 ;
     RECT  2.304 22.733 2.697 22.747 ;
     RECT  3.744 22.739 6.03 22.775 ;
     RECT  35.928 22.279 35.982 22.843 ;
     RECT  32.004 22.541 34.758 22.855 ;
     RECT  6.84 22.585 8.097 22.891 ;
     RECT  6.768 22.891 8.097 23.009 ;
     RECT  30.852 22.613 30.87 23.081 ;
     RECT  2.304 22.747 2.862 23.275 ;
     RECT  3.816 22.775 6.03 23.279 ;
     RECT  31.68 22.855 34.758 23.279 ;
     RECT  0.252 23.179 0.27 23.309 ;
     RECT  9.648 23.161 9.666 23.323 ;
     RECT  31.824 23.279 34.758 23.323 ;
     RECT  9.576 23.323 9.666 23.431 ;
     RECT  9.576 23.431 9.702 23.549 ;
     RECT  2.304 23.275 2.898 23.557 ;
     RECT  3.816 23.279 5.778 23.557 ;
     RECT  10.515 12.551 10.797 23.593 ;
     RECT  10.515 23.593 10.818 23.729 ;
     RECT  2.304 23.557 5.778 23.803 ;
     RECT  6.804 23.009 8.097 23.819 ;
     RECT  31.824 23.323 34.794 23.819 ;
     RECT  2.268 23.803 5.778 23.855 ;
     RECT  32.076 23.819 34.794 24.029 ;
     RECT  9.432 23.791 9.45 24.089 ;
     RECT  4.5 23.855 5.778 24.161 ;
     RECT  4.536 24.161 5.778 24.241 ;
     RECT  7.128 23.819 8.097 24.269 ;
     RECT  35.928 22.843 36.018 24.475 ;
     RECT  2.268 23.855 3.474 24.503 ;
     RECT  4.536 24.241 5.958 24.511 ;
     RECT  7.38 24.269 8.097 24.539 ;
     RECT  7.815 24.539 8.097 24.637 ;
     RECT  2.304 24.503 3.474 24.665 ;
     RECT  7.815 24.637 8.154 24.667 ;
     RECT  32.076 24.029 34.362 24.673 ;
     RECT  7.815 24.667 8.226 24.737 ;
     RECT  7.815 24.737 8.154 24.749 ;
     RECT  2.34 24.665 3.474 24.781 ;
     RECT  9.108 24.709 9.414 24.809 ;
     RECT  0.252 24.811 0.27 24.941 ;
     RECT  31.968 24.673 34.362 24.943 ;
     RECT  35.928 24.475 36.054 25.007 ;
     RECT  2.34 24.781 3.582 25.015 ;
     RECT  4.536 24.511 6.282 25.015 ;
     RECT  9.396 24.809 9.414 25.043 ;
     RECT  2.34 25.015 6.282 25.099 ;
     RECT  31.968 24.943 34.722 25.099 ;
     RECT  21.315 2.413 21.597 25.141 ;
     RECT  31.968 25.099 35.37 25.285 ;
     RECT  31.716 25.285 35.37 25.511 ;
     RECT  7.815 24.749 8.097 25.591 ;
     RECT  31.716 25.511 34.254 25.717 ;
     RECT  31.68 25.717 34.254 25.753 ;
     RECT  2.34 25.099 7.002 25.771 ;
     RECT  2.304 25.771 7.002 25.789 ;
     RECT  7.815 25.591 8.154 25.789 ;
     RECT  31.32 25.753 34.254 25.825 ;
     RECT  21.096 25.141 21.597 25.853 ;
     RECT  2.304 25.789 8.154 25.861 ;
     RECT  10.515 23.729 10.797 25.861 ;
     RECT  2.304 25.861 8.37 25.915 ;
     RECT  35.352 25.511 35.37 25.915 ;
     RECT  2.268 25.915 8.37 25.951 ;
     RECT  31.248 25.825 34.254 25.979 ;
     RECT  10.515 25.861 10.854 25.987 ;
     RECT  30.924 25.987 30.978 26.023 ;
     RECT  35.352 25.915 35.406 26.107 ;
     RECT  10.515 25.987 10.926 26.159 ;
     RECT  31.896 25.979 34.254 26.257 ;
     RECT  30.852 26.023 30.978 26.293 ;
     RECT  31.896 26.257 34.29 26.365 ;
     RECT  35.352 26.107 35.946 26.365 ;
     RECT  2.268 25.951 8.478 26.519 ;
     RECT  30.78 26.293 30.978 26.519 ;
     RECT  31.896 26.365 35.946 26.587 ;
     RECT  10.515 26.159 10.818 26.591 ;
     RECT  30.78 26.519 30.906 26.591 ;
     RECT  31.896 26.587 35.982 26.627 ;
     RECT  6.84 26.519 8.478 26.635 ;
     RECT  30.816 26.591 30.906 26.663 ;
     RECT  6.84 26.635 8.658 26.789 ;
     RECT  2.268 26.519 6.03 26.825 ;
     RECT  2.304 26.825 6.03 27.095 ;
     RECT  31.896 26.627 35.946 27.101 ;
     RECT  31.896 27.101 34.83 27.301 ;
     RECT  31.824 27.301 34.83 27.401 ;
     RECT  6.84 26.789 8.154 27.599 ;
     RECT  30.852 27.607 30.87 27.643 ;
     RECT  9.036 27.643 9.054 27.751 ;
     RECT  3.528 27.095 6.03 27.835 ;
     RECT  2.304 27.095 2.718 27.841 ;
     RECT  3.492 27.835 6.03 27.841 ;
     RECT  6.84 27.599 8.097 27.841 ;
     RECT  9.036 27.751 9.126 27.869 ;
     RECT  35.928 27.101 35.946 27.883 ;
     RECT  6.768 27.841 8.097 27.941 ;
     RECT  2.304 27.841 6.03 27.949 ;
     RECT  2.304 27.949 6.066 28.021 ;
     RECT  2.268 28.021 6.066 28.061 ;
     RECT  2.304 28.061 6.066 28.139 ;
     RECT  32.076 27.401 34.83 28.171 ;
     RECT  35.928 27.883 35.982 28.171 ;
     RECT  32.076 28.171 35.982 28.283 ;
     RECT  30.78 27.643 30.87 28.319 ;
     RECT  6.84 27.941 8.097 28.363 ;
     RECT  6.84 28.363 8.334 28.409 ;
     RECT  30.78 28.319 30.798 28.481 ;
     RECT  32.076 28.283 34.83 28.525 ;
     RECT  6.84 28.409 8.19 28.589 ;
     RECT  6.84 28.589 8.097 28.859 ;
     RECT  35.928 28.283 35.982 28.859 ;
     RECT  2.304 28.139 5.85 28.949 ;
     RECT  0.252 28.843 0.27 28.973 ;
     RECT  2.304 28.949 3.726 28.985 ;
     RECT  4.464 28.949 5.85 29.101 ;
     RECT  9.396 28.381 9.414 29.129 ;
     RECT  35.964 28.859 35.982 29.129 ;
     RECT  32.04 28.525 34.83 29.179 ;
     RECT  32.04 29.179 34.866 29.191 ;
     RECT  31.716 29.191 34.866 29.291 ;
     RECT  4.464 29.101 6.102 29.371 ;
     RECT  4.464 29.371 6.246 29.489 ;
     RECT  7.092 28.859 8.097 29.641 ;
     RECT  32.004 29.291 34.866 29.759 ;
     RECT  2.304 28.985 3.69 29.767 ;
     RECT  4.464 29.489 5.958 29.767 ;
     RECT  9.036 29.803 9.054 29.911 ;
     RECT  32.04 29.759 34.866 29.947 ;
     RECT  9 29.911 9.09 30.109 ;
     RECT  32.04 29.947 35.37 30.139 ;
     RECT  9 30.109 9.162 30.209 ;
     RECT  2.304 29.767 5.958 30.373 ;
     RECT  6.84 29.641 8.097 30.373 ;
     RECT  2.304 30.373 8.097 30.611 ;
     RECT  32.04 30.139 35.946 30.619 ;
     RECT  7.815 30.611 8.097 30.721 ;
     RECT  9 30.209 9.018 30.721 ;
     RECT  32.04 30.619 35.982 30.763 ;
     RECT  32.04 30.763 36.522 30.811 ;
     RECT  31.572 30.811 36.522 30.893 ;
     RECT  31.572 30.893 36.054 30.947 ;
     RECT  7.815 30.721 9.018 30.955 ;
     RECT  7.815 30.955 9.486 31.109 ;
     RECT  31.572 30.947 34.794 31.109 ;
     RECT  35.856 30.947 36.054 31.109 ;
     RECT  2.304 30.611 7.074 31.145 ;
     RECT  2.304 31.145 3.186 31.243 ;
     RECT  30.78 29.803 30.798 31.289 ;
     RECT  2.268 31.243 3.186 31.415 ;
     RECT  4.068 31.145 7.074 31.423 ;
     RECT  7.815 31.109 9.234 31.423 ;
     RECT  2.304 31.415 3.186 31.559 ;
     RECT  4.068 31.423 9.234 31.559 ;
     RECT  35.928 31.109 36.054 31.613 ;
     RECT  7.815 31.559 9.234 31.649 ;
     RECT  35.928 31.613 36.018 31.757 ;
     RECT  30.852 31.423 30.87 31.793 ;
     RECT  31.932 31.109 34.794 31.805 ;
     RECT  4.068 31.559 7.074 31.891 ;
     RECT  7.815 31.649 8.658 31.919 ;
     RECT  2.304 31.559 2.934 32.341 ;
     RECT  3.78 31.891 7.074 32.341 ;
     RECT  7.815 31.919 8.37 32.341 ;
     RECT  31.932 31.805 34.758 32.369 ;
     RECT  2.304 32.341 8.37 32.395 ;
     RECT  2.268 32.395 8.37 32.495 ;
     RECT  35.928 31.757 35.982 32.539 ;
     RECT  32.115 32.369 34.758 32.731 ;
     RECT  35.928 32.539 36.018 32.731 ;
     RECT  2.304 32.495 8.226 32.837 ;
     RECT  2.304 32.837 8.154 32.999 ;
     RECT  30.78 32.881 30.87 33.035 ;
     RECT  32.115 32.731 36.018 33.071 ;
     RECT  32.115 33.071 35.946 33.115 ;
     RECT  7.308 32.999 8.097 33.143 ;
     RECT  32.076 33.115 35.946 33.241 ;
     RECT  32.004 33.241 35.946 33.341 ;
     RECT  35.316 33.341 35.946 33.413 ;
     RECT  30.78 33.035 30.798 33.449 ;
     RECT  2.304 32.999 6.174 33.817 ;
     RECT  35.352 33.413 35.946 33.835 ;
     RECT  35.352 33.835 35.982 33.925 ;
     RECT  9.18 33.691 9.198 33.961 ;
     RECT  7.056 33.961 7.074 33.979 ;
     RECT  7.815 33.143 8.097 33.979 ;
     RECT  7.056 33.979 8.097 34.013 ;
     RECT  2.304 33.817 6.21 34.087 ;
     RECT  30.852 33.961 30.87 34.087 ;
     RECT  32.115 33.341 34.182 34.087 ;
     RECT  7.2 34.013 8.097 34.195 ;
     RECT  30.852 34.087 34.182 34.195 ;
     RECT  2.304 34.087 6.246 34.231 ;
     RECT  30.852 34.195 34.254 34.231 ;
     RECT  35.352 33.925 36.018 34.231 ;
     RECT  30.852 34.231 36.018 34.421 ;
     RECT  30.852 34.421 34.326 34.429 ;
     RECT  30.78 34.429 34.326 34.457 ;
     RECT  2.304 34.231 6.426 34.492 ;
     RECT  7.2 34.195 8.226 34.501 ;
     RECT  9.108 33.961 9.198 34.501 ;
     RECT  7.2 34.501 8.37 34.619 ;
     RECT  2.268 34.492 6.426 34.655 ;
     RECT  35.352 34.421 36.018 34.727 ;
     RECT  30.78 34.457 30.798 34.763 ;
     RECT  9.108 34.501 9.342 34.771 ;
     RECT  8.82 34.771 9.414 34.889 ;
     RECT  8.82 34.889 8.874 34.997 ;
     RECT  10.515 26.591 10.797 35.005 ;
     RECT  2.304 34.655 6.426 35.033 ;
     RECT  3.42 35.033 6.426 35.131 ;
     RECT  7.2 34.619 8.097 35.131 ;
     RECT  3.42 35.131 8.097 35.159 ;
     RECT  32.004 34.457 34.326 35.203 ;
     RECT  30.852 35.203 30.87 35.303 ;
     RECT  3.42 35.159 6.93 35.357 ;
     RECT  6.588 35.357 6.93 35.429 ;
     RECT  3.42 35.357 5.634 35.465 ;
     RECT  7.815 35.159 8.097 35.509 ;
     RECT  8.82 34.997 8.838 35.509 ;
     RECT  10.515 35.005 10.818 35.609 ;
     RECT  2.304 35.033 2.697 35.611 ;
     RECT  6.624 35.429 6.93 35.645 ;
     RECT  2.268 35.611 2.697 35.803 ;
     RECT  3.42 35.465 5.418 35.803 ;
     RECT  31.716 35.203 34.326 35.803 ;
     RECT  35.352 34.727 35.982 35.803 ;
     RECT  7.815 35.509 8.838 35.815 ;
     RECT  6.768 35.645 6.93 36.121 ;
     RECT  7.815 35.815 9.306 36.121 ;
     RECT  31.716 35.803 35.982 36.247 ;
     RECT  2.268 35.803 5.418 36.319 ;
     RECT  2.268 36.319 5.742 36.391 ;
     RECT  6.768 36.121 9.306 36.391 ;
     RECT  2.268 36.391 9.306 36.419 ;
     RECT  2.268 36.419 8.226 36.509 ;
     RECT  9.18 36.419 9.306 36.509 ;
     RECT  31.68 36.247 35.982 36.509 ;
     RECT  31.968 36.509 35.982 36.779 ;
     RECT  32.04 36.779 35.982 36.907 ;
     RECT  31.068 36.661 31.194 36.959 ;
     RECT  32.04 36.907 36.018 36.959 ;
     RECT  9.396 36.517 9.414 37.049 ;
     RECT  6.804 36.509 8.226 37.165 ;
     RECT  35.352 36.959 36.018 37.243 ;
     RECT  2.268 36.509 6.066 37.291 ;
     RECT  6.804 37.165 8.478 37.291 ;
     RECT  35.352 37.243 36.09 37.391 ;
     RECT  30.78 37.291 30.798 37.427 ;
     RECT  35.352 37.391 36.018 37.427 ;
     RECT  35.352 37.427 35.982 37.469 ;
     RECT  2.268 37.291 8.478 37.589 ;
     RECT  32.04 36.959 34.434 37.597 ;
     RECT  31.932 37.597 34.434 37.723 ;
     RECT  31.932 37.723 34.758 37.903 ;
     RECT  2.268 37.589 7.002 37.967 ;
     RECT  35.928 37.469 35.982 38.039 ;
     RECT  9.108 37.903 9.126 38.129 ;
     RECT  31.176 37.903 34.758 38.129 ;
     RECT  35.964 38.039 35.982 38.273 ;
     RECT  2.304 37.967 7.002 38.399 ;
     RECT  7.815 37.589 8.097 38.479 ;
     RECT  30.78 38.407 30.87 38.579 ;
     RECT  7.74 38.479 8.097 38.677 ;
     RECT  32.115 38.129 34.758 38.875 ;
     RECT  35.928 38.821 35.946 38.875 ;
     RECT  0.216 38.677 0.234 38.909 ;
     RECT  32.115 38.875 35.946 39.055 ;
     RECT  31.68 39.055 35.946 39.119 ;
     RECT  2.304 38.399 6.858 39.181 ;
     RECT  7.596 38.677 8.097 39.181 ;
     RECT  31.68 39.119 34.794 39.209 ;
     RECT  31.752 39.209 34.794 39.281 ;
     RECT  32.004 39.281 34.794 39.293 ;
     RECT  10.515 35.609 10.797 39.451 ;
     RECT  35.928 39.119 35.946 39.499 ;
     RECT  2.304 39.181 8.097 39.551 ;
     RECT  10.515 39.451 10.818 39.551 ;
     RECT  7.815 39.551 8.097 39.721 ;
     RECT  35.928 39.499 35.982 39.721 ;
     RECT  9.108 39.631 9.126 39.857 ;
     RECT  32.04 39.293 34.794 39.857 ;
     RECT  2.304 39.551 6.894 39.979 ;
     RECT  35.928 39.721 36.054 40.013 ;
     RECT  2.268 39.979 6.894 40.127 ;
     RECT  35.928 40.013 36.018 40.163 ;
     RECT  32.04 39.857 34.29 40.171 ;
     RECT  31.824 40.171 34.29 40.289 ;
     RECT  6.588 40.127 6.894 40.459 ;
     RECT  35.928 40.163 35.946 40.507 ;
     RECT  2.304 40.127 5.85 40.981 ;
     RECT  6.588 40.459 7.074 40.981 ;
     RECT  7.815 39.721 8.154 40.981 ;
     RECT  7.815 40.981 8.334 41.099 ;
     RECT  2.304 40.981 7.074 41.135 ;
     RECT  3.42 41.135 7.074 41.369 ;
     RECT  21.315 25.853 21.597 41.413 ;
     RECT  32.04 40.289 34.29 41.413 ;
     RECT  35.352 40.507 35.946 41.467 ;
     RECT  7.815 41.099 8.262 41.477 ;
     RECT  21.096 41.413 21.597 41.639 ;
     RECT  31.896 41.413 34.29 41.639 ;
     RECT  35.352 41.467 35.982 41.747 ;
     RECT  6.588 41.369 7.074 41.791 ;
     RECT  7.815 41.477 8.097 41.791 ;
     RECT  6.588 41.791 8.097 41.909 ;
     RECT  31.932 41.639 34.29 41.947 ;
     RECT  30.78 38.579 30.798 41.953 ;
     RECT  30.78 41.953 30.87 42.053 ;
     RECT  6.588 41.909 7.074 42.089 ;
     RECT  3.42 41.369 5.85 42.187 ;
     RECT  35.928 41.747 35.982 42.259 ;
     RECT  2.304 41.135 2.697 42.283 ;
     RECT  3.42 42.187 6.318 42.283 ;
     RECT  7.815 41.909 8.097 42.529 ;
     RECT  10.515 39.551 10.797 42.601 ;
     RECT  10.515 42.601 10.854 42.719 ;
     RECT  7.056 42.089 7.074 42.749 ;
     RECT  2.304 42.283 6.318 42.755 ;
     RECT  7.815 42.529 8.694 42.871 ;
     RECT  35.928 42.259 36.054 42.941 ;
     RECT  30.852 42.997 30.87 43.033 ;
     RECT  30.78 43.033 30.87 43.169 ;
     RECT  31.932 41.947 34.758 43.231 ;
     RECT  35.928 42.941 35.982 43.231 ;
     RECT  2.304 42.755 2.898 43.243 ;
     RECT  3.78 42.755 6.318 43.267 ;
     RECT  31.932 43.231 35.982 43.277 ;
     RECT  3.78 43.267 6.642 43.325 ;
     RECT  2.268 43.243 2.898 43.367 ;
     RECT  31.932 43.277 34.758 43.601 ;
     RECT  2.304 43.367 2.898 43.681 ;
     RECT  3.78 43.325 5.85 43.681 ;
     RECT  7.815 42.871 8.766 43.681 ;
     RECT  6.66 43.681 6.678 43.723 ;
     RECT  7.815 43.681 9.486 43.835 ;
     RECT  7.815 43.835 8.586 43.843 ;
     RECT  9.396 43.835 9.486 43.979 ;
     RECT  6.66 43.723 6.822 44.059 ;
     RECT  7.776 43.843 8.586 44.059 ;
     RECT  31.968 43.601 34.758 44.059 ;
     RECT  35.928 43.277 35.982 44.059 ;
     RECT  2.304 43.681 5.85 44.221 ;
     RECT  6.66 44.059 8.586 44.221 ;
     RECT  31.968 44.059 35.982 44.249 ;
     RECT  2.304 44.221 8.586 44.609 ;
     RECT  9.612 44.491 9.63 44.609 ;
     RECT  31.968 44.249 34.254 44.609 ;
     RECT  30.852 43.169 30.87 44.761 ;
     RECT  2.304 44.609 8.298 44.879 ;
     RECT  30.78 44.761 30.87 44.923 ;
     RECT  32.076 44.609 34.254 44.995 ;
     RECT  30.78 44.923 30.906 45.023 ;
     RECT  35.352 44.249 35.982 45.463 ;
     RECT  32.076 44.995 34.362 45.499 ;
     RECT  35.352 45.463 36.018 45.533 ;
     RECT  32.076 45.499 34.434 45.643 ;
     RECT  35.352 45.533 35.982 45.643 ;
     RECT  32.076 45.643 35.982 45.661 ;
     RECT  2.304 44.879 8.226 45.725 ;
     RECT  31.86 45.661 35.982 45.833 ;
     RECT  3.852 45.725 8.226 45.841 ;
     RECT  3.852 45.841 8.622 46.067 ;
     RECT  3.96 46.067 8.622 46.139 ;
     RECT  3.996 46.139 8.622 46.157 ;
     RECT  7.38 46.157 8.622 46.229 ;
     RECT  2.304 45.725 2.97 46.265 ;
     RECT  2.304 46.265 2.79 46.459 ;
     RECT  2.268 46.459 2.79 46.535 ;
     RECT  31.896 45.833 35.982 46.615 ;
     RECT  7.38 46.229 8.097 46.885 ;
     RECT  3.996 46.157 6.354 46.921 ;
     RECT  31.824 46.615 35.982 46.973 ;
     RECT  2.304 46.535 2.79 47.075 ;
     RECT  3.78 46.921 6.354 47.083 ;
     RECT  35.928 46.973 35.982 47.111 ;
     RECT  3.636 47.083 6.39 47.155 ;
     RECT  7.308 46.885 8.097 47.155 ;
     RECT  9.036 47.281 9.054 47.551 ;
     RECT  8.964 47.551 9.054 47.587 ;
     RECT  30.78 45.023 30.87 47.587 ;
     RECT  31.824 46.973 34.866 47.587 ;
     RECT  8.964 47.587 9.162 47.687 ;
     RECT  3.636 47.155 8.097 47.731 ;
     RECT  8.964 47.687 8.982 47.759 ;
     RECT  2.304 47.075 2.754 47.929 ;
     RECT  3.492 47.731 8.154 47.929 ;
     RECT  2.304 47.929 8.154 47.957 ;
     RECT  3.996 47.957 8.154 48.001 ;
     RECT  3.996 48.001 8.19 48.119 ;
     RECT  30.78 47.587 34.866 48.119 ;
     RECT  3.996 48.119 8.154 48.191 ;
     RECT  0.252 48.091 0.27 48.221 ;
     RECT  30.852 48.119 34.866 48.235 ;
     RECT  35.928 47.111 35.946 48.235 ;
     RECT  3.996 48.191 8.097 48.263 ;
     RECT  9.468 48.505 9.486 48.659 ;
     RECT  30.852 48.235 35.946 48.659 ;
     RECT  30.852 48.659 30.87 48.767 ;
     RECT  2.304 47.957 3.114 48.811 ;
     RECT  3.996 48.263 6.858 48.811 ;
     RECT  2.304 48.811 6.858 49.009 ;
     RECT  7.632 48.263 8.097 49.009 ;
     RECT  9.144 49.045 9.162 49.199 ;
     RECT  2.304 49.009 8.097 49.379 ;
     RECT  31.824 48.659 35.946 49.469 ;
     RECT  31.968 49.469 35.946 49.541 ;
     RECT  6.948 49.379 8.097 49.577 ;
     RECT  31.176 49.477 31.194 49.747 ;
     RECT  30.852 49.747 31.194 49.783 ;
     RECT  32.115 49.541 35.946 49.919 ;
     RECT  2.304 49.379 6.138 50.107 ;
     RECT  30.78 49.783 31.194 50.117 ;
     RECT  35.352 49.919 35.946 50.153 ;
     RECT  2.304 50.107 6.174 50.323 ;
     RECT  7.308 49.577 8.097 50.323 ;
     RECT  35.352 50.153 35.91 50.387 ;
     RECT  32.115 49.919 34.326 50.395 ;
     RECT  2.304 50.323 8.097 50.459 ;
     RECT  7.308 50.459 8.097 50.629 ;
     RECT  7.308 50.629 8.262 50.701 ;
     RECT  2.304 50.459 6.354 50.819 ;
     RECT  32.004 50.395 34.326 50.899 ;
     RECT  30.816 50.117 31.194 50.971 ;
     RECT  31.968 50.899 34.326 50.971 ;
     RECT  35.856 50.387 35.91 51.019 ;
     RECT  30.816 50.971 34.326 51.089 ;
     RECT  35.856 51.019 35.946 51.163 ;
     RECT  7.308 50.701 8.586 51.197 ;
     RECT  3.672 50.819 6.354 51.241 ;
     RECT  7.308 51.197 8.097 51.241 ;
     RECT  31.608 51.089 34.326 51.307 ;
     RECT  35.352 51.163 35.946 51.307 ;
     RECT  31.608 51.307 35.946 51.431 ;
     RECT  0.216 51.307 0.234 51.437 ;
     RECT  8.928 51.241 8.946 51.629 ;
     RECT  31.608 51.431 34.434 51.629 ;
     RECT  2.304 50.819 2.862 51.745 ;
     RECT  3.672 51.241 8.097 51.745 ;
     RECT  31.896 51.629 34.434 51.809 ;
     RECT  2.304 51.745 8.097 51.835 ;
     RECT  2.268 51.835 8.097 51.971 ;
     RECT  35.352 51.431 35.946 51.979 ;
     RECT  30.852 51.943 30.87 52.051 ;
     RECT  2.268 51.971 6.102 52.079 ;
     RECT  30.78 52.051 30.87 52.141 ;
     RECT  6.84 51.971 8.097 52.169 ;
     RECT  31.932 51.809 34.434 52.213 ;
     RECT  35.352 51.979 35.982 52.213 ;
     RECT  6.84 52.169 6.93 52.241 ;
     RECT  9.108 52.141 9.126 52.241 ;
     RECT  30.78 52.141 30.942 52.241 ;
     RECT  30.78 52.241 30.87 52.277 ;
     RECT  7.74 52.169 8.097 52.313 ;
     RECT  30.78 52.277 30.798 52.349 ;
     RECT  7.815 52.313 8.097 52.411 ;
     RECT  2.268 52.079 5.85 52.475 ;
     RECT  31.932 52.213 35.982 52.637 ;
     RECT  9.468 52.591 9.486 52.709 ;
     RECT  31.932 52.637 35.946 52.781 ;
     RECT  2.304 52.475 5.85 52.861 ;
     RECT  2.304 52.861 5.994 52.951 ;
     RECT  31.932 52.781 35.37 52.951 ;
     RECT  6.912 52.241 6.93 53.095 ;
     RECT  7.815 52.411 8.154 53.095 ;
     RECT  7.815 53.095 8.55 53.131 ;
     RECT  31.86 52.951 35.37 53.131 ;
     RECT  7.815 53.131 8.586 53.221 ;
     RECT  31.68 53.131 35.37 53.285 ;
     RECT  2.304 52.951 6.066 53.357 ;
     RECT  6.84 53.095 6.93 53.401 ;
     RECT  7.704 53.221 8.586 53.401 ;
     RECT  6.84 53.401 8.586 53.453 ;
     RECT  0.216 53.419 0.234 53.549 ;
     RECT  7.815 53.453 8.586 53.671 ;
     RECT  31.896 53.285 35.37 53.755 ;
     RECT  29.415 13.559 29.697 53.761 ;
     RECT  31.896 53.755 35.406 53.899 ;
     RECT  4.032 53.357 6.066 53.941 ;
     RECT  6.84 53.453 6.93 53.941 ;
     RECT  7.815 53.671 8.622 53.969 ;
     RECT  31.896 53.899 35.946 54.031 ;
     RECT  31.392 54.031 35.946 54.131 ;
     RECT  2.304 53.357 3.294 54.211 ;
     RECT  4.032 53.941 6.93 54.211 ;
     RECT  7.815 53.969 8.154 54.301 ;
     RECT  29.415 53.761 30.222 54.301 ;
     RECT  29.415 54.301 30.942 54.329 ;
     RECT  30.78 54.329 30.942 54.437 ;
     RECT  30.78 54.437 30.87 54.509 ;
     RECT  2.304 54.211 6.93 54.599 ;
     RECT  6.912 54.599 6.93 54.715 ;
     RECT  7.668 54.301 8.154 54.715 ;
     RECT  2.304 54.599 6.174 54.941 ;
     RECT  6.912 54.715 8.154 54.949 ;
     RECT  2.304 54.941 3.15 55.013 ;
     RECT  30.78 54.509 30.798 55.013 ;
     RECT  32.004 54.131 35.946 55.051 ;
     RECT  6.912 54.949 8.694 55.211 ;
     RECT  32.004 55.051 35.982 55.219 ;
     RECT  3.924 54.941 6.174 55.339 ;
     RECT  3.924 55.339 6.282 55.409 ;
     RECT  7.344 55.211 8.097 55.409 ;
     RECT  8.928 55.561 9.018 55.787 ;
     RECT  2.304 55.013 2.97 55.831 ;
     RECT  3.924 55.409 6.21 55.831 ;
     RECT  31.824 55.219 35.982 55.949 ;
     RECT  31.932 55.949 35.982 56.045 ;
     RECT  8.928 55.787 8.946 56.219 ;
     RECT  31.932 56.045 35.946 56.237 ;
     RECT  7.488 55.409 8.097 56.371 ;
     RECT  2.304 55.831 6.21 56.569 ;
     RECT  30.78 55.957 30.798 56.605 ;
     RECT  2.304 56.569 6.354 56.731 ;
     RECT  30.78 56.605 30.834 56.803 ;
     RECT  31.932 56.237 34.434 56.839 ;
     RECT  10.515 42.719 10.797 57.001 ;
     RECT  2.304 56.731 6.462 57.019 ;
     RECT  7.272 56.371 8.442 57.019 ;
     RECT  10.515 57.001 10.854 57.137 ;
     RECT  35.352 56.237 35.946 57.137 ;
     RECT  31.716 56.839 34.434 57.173 ;
     RECT  9.324 57.145 9.342 57.181 ;
     RECT  35.388 57.137 35.946 57.181 ;
     RECT  2.304 57.019 8.442 57.209 ;
     RECT  9.324 57.181 9.666 57.299 ;
     RECT  30.78 56.803 30.906 57.307 ;
     RECT  31.716 57.173 34.362 57.307 ;
     RECT  9.648 57.299 9.666 57.407 ;
     RECT  30.78 57.307 34.362 57.407 ;
     RECT  35.388 57.181 36.054 57.479 ;
     RECT  0.252 56.875 0.27 57.485 ;
     RECT  35.928 57.479 36.054 57.677 ;
     RECT  2.304 57.209 8.226 57.839 ;
     RECT  35.928 57.677 36.018 58.019 ;
     RECT  31.32 57.407 34.362 58.261 ;
     RECT  31.176 58.261 34.362 58.379 ;
     RECT  8.964 58.423 8.982 58.531 ;
     RECT  30.852 58.423 30.87 58.559 ;
     RECT  8.964 58.531 9.018 58.621 ;
     RECT  0.252 58.507 0.27 58.637 ;
     RECT  2.304 57.839 8.154 58.721 ;
     RECT  31.968 58.379 34.362 58.729 ;
     RECT  8.964 58.621 9.054 58.801 ;
     RECT  8.964 58.801 9.09 58.919 ;
     RECT  8.964 58.919 8.982 58.991 ;
     RECT  35.928 58.019 35.982 58.999 ;
     RECT  31.968 58.729 34.398 59.161 ;
     RECT  8.928 59.071 8.946 59.189 ;
     RECT  31.32 59.161 34.398 59.189 ;
     RECT  7.524 58.721 8.154 59.225 ;
     RECT  31.32 59.189 34.362 59.459 ;
     RECT  35.352 58.999 35.982 59.459 ;
     RECT  2.304 58.721 6.786 59.467 ;
     RECT  7.524 59.225 8.097 59.467 ;
     RECT  31.32 59.459 31.338 59.503 ;
     RECT  30.78 59.503 31.338 59.531 ;
     RECT  30.78 59.531 31.158 59.603 ;
     RECT  2.304 59.467 8.097 59.881 ;
     RECT  2.268 59.881 8.097 59.933 ;
     RECT  35.928 59.459 35.982 59.933 ;
     RECT  2.304 59.933 8.097 60.043 ;
     RECT  32.076 59.459 34.362 60.043 ;
     RECT  35.928 59.933 35.946 60.179 ;
     RECT  32.076 60.043 34.758 60.235 ;
     RECT  30.852 59.603 31.158 60.269 ;
     RECT  2.304 60.043 8.226 60.413 ;
     RECT  30.852 60.269 30.87 60.421 ;
     RECT  32.076 60.235 35.37 60.421 ;
     RECT  31.968 60.421 35.37 60.511 ;
     RECT  31.896 60.511 35.37 60.547 ;
     RECT  30.78 60.421 30.87 60.683 ;
     RECT  2.304 60.413 8.154 60.719 ;
     RECT  31.788 60.547 35.37 60.809 ;
     RECT  0.252 60.235 0.27 60.845 ;
     RECT  2.304 60.719 8.097 61.051 ;
     RECT  31.788 60.809 34.794 61.195 ;
     RECT  31.752 61.195 34.794 61.259 ;
     RECT  35.928 61.195 35.946 61.339 ;
     RECT  31.752 61.259 34.29 61.349 ;
     RECT  31.752 61.349 34.254 61.357 ;
     RECT  9 60.961 9.018 61.457 ;
     RECT  2.268 61.051 8.097 61.493 ;
     RECT  2.304 61.493 8.097 61.565 ;
     RECT  30.78 60.683 30.798 61.591 ;
     RECT  31.572 61.357 34.254 61.591 ;
     RECT  2.304 61.565 5.742 61.619 ;
     RECT  6.66 61.565 8.097 61.889 ;
     RECT  35.928 61.339 35.982 62.011 ;
     RECT  6.84 61.889 8.097 62.131 ;
     RECT  35.928 62.011 36.018 62.155 ;
     RECT  30.78 61.591 34.254 62.159 ;
     RECT  2.304 61.619 5.67 62.231 ;
     RECT  35.856 62.155 36.018 62.303 ;
     RECT  31.968 62.159 34.254 62.347 ;
     RECT  4.392 62.231 5.67 62.401 ;
     RECT  0.252 62.347 0.27 62.477 ;
     RECT  4.392 62.401 5.85 62.509 ;
     RECT  6.84 62.131 8.118 62.671 ;
     RECT  6.804 62.671 8.118 62.707 ;
     RECT  4.392 62.509 6.03 62.851 ;
     RECT  9.072 62.743 9.09 62.851 ;
     RECT  6.804 62.707 8.334 62.969 ;
     RECT  35.856 62.303 35.982 62.969 ;
     RECT  31.968 62.347 34.722 62.971 ;
     RECT  4.392 62.851 6.066 63.013 ;
     RECT  6.804 62.969 8.097 63.013 ;
     RECT  30.78 62.159 30.906 63.041 ;
     RECT  9.072 62.851 9.126 63.049 ;
     RECT  9.072 63.049 9.486 63.077 ;
     RECT  30.78 63.041 30.87 63.077 ;
     RECT  2.304 62.231 3.654 63.085 ;
     RECT  4.392 63.013 8.097 63.085 ;
     RECT  31.968 62.971 34.794 63.211 ;
     RECT  2.304 63.085 8.097 63.239 ;
     RECT  9.108 63.077 9.486 63.239 ;
     RECT  30.78 63.077 30.798 63.239 ;
     RECT  0.54 63.121 0.558 63.341 ;
     RECT  31.716 63.211 34.794 63.347 ;
     RECT  31.968 63.347 34.794 63.391 ;
     RECT  35.928 62.969 35.982 63.451 ;
     RECT  9.432 63.239 9.45 63.581 ;
     RECT  35.928 63.451 36.018 63.653 ;
     RECT  31.968 63.391 34.83 63.931 ;
     RECT  35.928 63.653 35.982 63.931 ;
     RECT  30.78 64.021 30.798 64.057 ;
     RECT  7.56 63.239 8.097 64.093 ;
     RECT  30.78 64.057 30.87 64.093 ;
     RECT  31.968 63.931 35.982 64.121 ;
     RECT  2.304 63.239 6.786 64.129 ;
     RECT  7.56 64.093 8.766 64.129 ;
     RECT  30.78 64.093 30.942 64.157 ;
     RECT  2.304 64.129 8.766 64.201 ;
     RECT  30.924 64.157 30.942 64.229 ;
     RECT  31.968 64.121 34.326 64.291 ;
     RECT  2.268 64.201 8.766 64.301 ;
     RECT  2.304 64.301 8.766 64.319 ;
     RECT  31.572 64.291 34.326 64.319 ;
     RECT  2.304 64.319 8.226 64.391 ;
     RECT  35.352 64.121 35.982 64.445 ;
     RECT  31.572 64.319 34.254 64.589 ;
     RECT  6.768 64.391 8.226 65.101 ;
     RECT  9.072 64.831 9.09 65.101 ;
     RECT  31.86 64.589 34.254 65.227 ;
     RECT  35.352 64.445 35.946 65.227 ;
     RECT  2.304 64.391 5.994 65.245 ;
     RECT  6.768 65.101 9.09 65.245 ;
     RECT  2.304 65.245 9.09 65.273 ;
     RECT  31.86 65.227 35.946 65.407 ;
     RECT  31.608 65.407 35.946 65.419 ;
     RECT  2.304 65.273 8.766 65.543 ;
     RECT  30.852 65.443 30.87 65.543 ;
     RECT  31.608 65.419 35.982 65.579 ;
     RECT  3.888 65.543 8.766 65.669 ;
     RECT  31.608 65.579 34.254 65.669 ;
     RECT  2.304 65.543 2.934 65.741 ;
     RECT  10.515 57.137 10.797 65.749 ;
     RECT  35.352 65.579 35.982 65.777 ;
     RECT  10.515 65.749 10.818 65.849 ;
     RECT  30.78 65.551 30.798 65.849 ;
     RECT  3.888 65.669 8.622 65.939 ;
     RECT  31.68 65.669 34.218 65.939 ;
     RECT  7.815 65.939 8.622 66.029 ;
     RECT  35.856 65.777 35.982 66.047 ;
     RECT  7.815 66.029 8.478 66.083 ;
     RECT  7.815 66.083 8.334 66.245 ;
     RECT  3.888 65.939 6.966 66.269 ;
     RECT  2.304 65.741 2.79 66.523 ;
     RECT  31.824 65.939 34.218 66.523 ;
     RECT  2.304 66.523 3.006 66.631 ;
     RECT  35.856 66.047 35.946 66.749 ;
     RECT  2.304 66.631 3.294 66.785 ;
     RECT  35.928 66.749 35.946 66.859 ;
     RECT  4.068 66.269 6.966 66.901 ;
     RECT  7.815 66.245 8.097 66.901 ;
     RECT  2.304 66.785 3.222 67.003 ;
     RECT  4.068 66.901 8.097 67.019 ;
     RECT  9.54 66.091 9.558 67.019 ;
     RECT  30.852 66.487 30.87 67.063 ;
     RECT  2.268 67.003 3.222 67.127 ;
     RECT  4.068 67.019 7.002 67.135 ;
     RECT  30.78 67.063 30.87 67.135 ;
     RECT  31.824 66.523 34.794 67.135 ;
     RECT  7.776 67.019 8.097 67.261 ;
     RECT  4.032 67.135 7.002 67.288 ;
     RECT  35.928 66.859 35.982 67.339 ;
     RECT  30.78 67.135 34.794 67.667 ;
     RECT  35.928 67.339 36.054 67.703 ;
     RECT  2.304 67.127 3.222 67.711 ;
     RECT  3.96 67.288 7.002 67.711 ;
     RECT  35.928 67.703 35.982 67.739 ;
     RECT  2.304 67.711 7.002 67.771 ;
     RECT  7.776 67.261 8.154 67.771 ;
     RECT  35.928 67.739 35.946 67.819 ;
     RECT  2.304 67.771 8.154 67.981 ;
     RECT  2.304 67.981 8.586 68.369 ;
     RECT  7.344 68.369 8.586 68.429 ;
     RECT  7.38 68.429 8.586 68.485 ;
     RECT  30.78 67.667 34.254 68.491 ;
     RECT  35.352 67.819 35.946 68.491 ;
     RECT  7.38 68.485 8.622 68.639 ;
     RECT  30.78 68.491 35.946 68.639 ;
     RECT  29.415 54.329 29.697 68.683 ;
     RECT  30.78 68.639 30.87 68.683 ;
     RECT  31.68 68.639 35.946 68.779 ;
     RECT  31.68 68.779 35.982 68.945 ;
     RECT  31.824 68.945 35.982 68.953 ;
     RECT  29.415 68.683 30.87 69.179 ;
     RECT  31.824 68.953 36.018 69.287 ;
     RECT  2.304 68.369 6.246 69.295 ;
     RECT  7.38 68.639 8.097 69.295 ;
     RECT  35.928 69.287 36.018 69.307 ;
     RECT  35.928 69.307 36.054 69.521 ;
     RECT  2.304 69.295 8.097 69.529 ;
     RECT  8.82 69.421 8.838 69.529 ;
     RECT  2.304 69.529 8.838 69.533 ;
     RECT  7.704 69.533 8.838 69.601 ;
     RECT  0.216 69.457 0.234 69.629 ;
     RECT  2.304 69.533 6.858 69.629 ;
     RECT  7.704 69.601 8.946 69.629 ;
     RECT  8.82 69.629 8.946 69.719 ;
     RECT  30.852 69.179 30.87 69.763 ;
     RECT  31.824 69.287 34.794 69.763 ;
     RECT  7.704 69.629 8.097 69.989 ;
     RECT  30.852 69.763 34.794 69.989 ;
     RECT  32.004 69.989 34.794 70.025 ;
     RECT  32.076 70.025 34.794 70.259 ;
     RECT  32.115 70.259 34.794 70.267 ;
     RECT  7.815 69.989 8.097 70.411 ;
     RECT  35.928 69.521 36.018 70.439 ;
     RECT  2.304 69.629 6.606 70.501 ;
     RECT  2.304 70.501 6.858 70.747 ;
     RECT  2.268 70.747 6.858 70.907 ;
     RECT  7.815 70.411 8.334 70.979 ;
     RECT  32.115 70.267 34.866 71.077 ;
     RECT  35.928 70.439 35.946 71.077 ;
     RECT  30.852 69.989 30.906 71.113 ;
     RECT  32.115 71.077 35.946 71.117 ;
     RECT  30.78 71.113 30.906 71.213 ;
     RECT  0.252 71.131 0.27 71.261 ;
     RECT  2.304 70.907 6.858 71.311 ;
     RECT  7.815 70.979 8.097 71.311 ;
     RECT  32.115 71.117 34.794 71.311 ;
     RECT  32.076 71.311 34.794 71.383 ;
     RECT  2.304 71.311 8.097 71.411 ;
     RECT  8.928 71.455 8.946 71.609 ;
     RECT  31.896 71.383 34.794 71.617 ;
     RECT  2.304 71.411 6.966 71.651 ;
     RECT  35.928 71.117 35.946 71.707 ;
     RECT  2.304 71.651 6.93 71.717 ;
     RECT  7.776 71.411 8.097 71.761 ;
     RECT  7.776 71.761 8.154 71.789 ;
     RECT  31.32 71.617 34.794 71.885 ;
     RECT  35.928 71.707 35.982 72.043 ;
     RECT  9.324 72.031 9.342 72.149 ;
     RECT  31.32 71.885 34.758 72.157 ;
     RECT  2.304 71.717 6.822 72.185 ;
     RECT  7.815 71.789 8.154 72.329 ;
     RECT  30.78 72.157 34.758 72.329 ;
     RECT  35.928 72.043 36.018 72.379 ;
     RECT  10.515 65.849 10.797 72.391 ;
     RECT  3.996 72.185 6.822 72.475 ;
     RECT  10.515 72.391 10.818 72.491 ;
     RECT  30.852 72.329 34.758 72.689 ;
     RECT  30.852 72.689 31.338 72.761 ;
     RECT  26.715 2.413 26.997 72.769 ;
     RECT  30.852 72.761 31.266 72.833 ;
     RECT  3.996 72.475 6.858 72.841 ;
     RECT  7.815 72.329 8.097 72.841 ;
     RECT  32.115 72.689 34.758 72.859 ;
     RECT  26.715 72.769 27.018 72.869 ;
     RECT  2.304 72.185 2.862 72.931 ;
     RECT  3.996 72.841 8.097 72.931 ;
     RECT  35.928 72.379 36.054 72.959 ;
     RECT  2.304 72.931 8.097 73.031 ;
     RECT  9.36 72.463 9.378 73.111 ;
     RECT  32.115 72.859 34.794 73.147 ;
     RECT  35.928 72.959 35.946 73.147 ;
     RECT  9.36 73.111 9.486 73.229 ;
     RECT  3.816 73.031 8.097 73.499 ;
     RECT  31.248 72.833 31.266 73.651 ;
     RECT  30.96 73.651 31.266 73.769 ;
     RECT  32.115 73.147 35.946 73.777 ;
     RECT  32.076 73.777 35.946 73.813 ;
     RECT  31.68 73.813 35.946 73.819 ;
     RECT  2.304 73.031 3.006 73.849 ;
     RECT  3.816 73.499 6.786 73.849 ;
     RECT  7.524 73.499 8.097 73.885 ;
     RECT  7.524 73.885 8.19 73.949 ;
     RECT  31.68 73.819 36.018 73.997 ;
     RECT  31.68 73.997 34.758 74.093 ;
     RECT  31.752 74.093 34.758 74.111 ;
     RECT  2.304 73.849 6.786 74.443 ;
     RECT  2.268 74.443 6.786 74.461 ;
     RECT  7.524 73.949 8.097 74.461 ;
     RECT  2.268 74.461 8.097 74.489 ;
     RECT  35.892 73.997 36.018 74.813 ;
     RECT  30.78 73.885 30.834 74.893 ;
     RECT  31.932 74.111 34.758 74.957 ;
     RECT  32.076 74.957 34.758 74.971 ;
     RECT  30.78 74.893 30.87 75.029 ;
     RECT  35.892 74.813 35.946 75.119 ;
     RECT  2.304 74.489 8.097 75.191 ;
     RECT  32.076 74.971 34.794 75.227 ;
     RECT  6.84 75.191 8.097 75.389 ;
     RECT  32.076 75.227 34.758 75.497 ;
     RECT  2.304 75.191 5.958 75.659 ;
     RECT  7.02 75.389 8.097 75.659 ;
     RECT  7.02 75.659 7.074 75.731 ;
     RECT  30.78 75.029 30.798 75.767 ;
     RECT  2.304 75.659 2.934 75.803 ;
     RECT  7.02 75.731 7.038 75.929 ;
     RECT  35.928 75.119 35.946 76.075 ;
     RECT  7.815 75.659 8.097 76.081 ;
     RECT  3.852 75.659 5.958 76.171 ;
     RECT  32.076 75.497 34.29 76.171 ;
     RECT  7.815 76.081 8.586 76.199 ;
     RECT  31.068 75.811 31.086 76.199 ;
     RECT  31.932 76.171 34.29 76.271 ;
     RECT  3.852 76.171 5.994 76.351 ;
     RECT  32.115 76.271 34.29 76.351 ;
     RECT  9.504 76.081 9.522 76.541 ;
     RECT  3.852 76.351 6.138 76.549 ;
     RECT  2.304 75.803 2.697 76.555 ;
     RECT  3.852 76.549 6.858 76.621 ;
     RECT  7.815 76.199 8.154 76.621 ;
     RECT  32.115 76.351 34.362 76.739 ;
     RECT  3.744 76.621 6.858 76.747 ;
     RECT  35.928 76.075 35.982 76.747 ;
     RECT  3.636 76.747 6.858 76.783 ;
     RECT  7.668 76.621 8.154 76.783 ;
     RECT  3.636 76.783 8.154 76.784 ;
     RECT  2.304 76.555 2.826 76.843 ;
     RECT  3.636 76.784 5.886 76.843 ;
     RECT  6.804 76.784 8.154 76.981 ;
     RECT  32.115 76.739 34.29 77.009 ;
     RECT  35.352 76.747 35.982 77.035 ;
     RECT  32.115 77.009 34.218 77.125 ;
     RECT  6.804 76.981 8.874 77.153 ;
     RECT  31.824 77.125 34.218 77.161 ;
     RECT  0.252 77.227 0.27 77.357 ;
     RECT  35.352 77.035 36.018 77.423 ;
     RECT  6.948 77.153 8.874 77.549 ;
     RECT  31.608 77.161 34.218 77.549 ;
     RECT  31.68 77.549 34.218 77.621 ;
     RECT  2.304 76.843 5.886 77.629 ;
     RECT  8.892 77.701 8.91 77.791 ;
     RECT  32.004 77.621 34.218 77.851 ;
     RECT  35.352 77.423 35.946 77.851 ;
     RECT  2.304 77.629 6.138 77.971 ;
     RECT  6.948 77.549 8.154 77.971 ;
     RECT  32.004 77.851 35.946 78.221 ;
     RECT  2.304 77.971 8.154 78.331 ;
     RECT  2.268 78.331 8.154 78.359 ;
     RECT  32.004 78.221 35.37 78.367 ;
     RECT  10.515 72.491 10.797 78.475 ;
     RECT  8.892 77.791 9.018 78.629 ;
     RECT  10.515 78.475 10.926 78.629 ;
     RECT  30.78 77.827 30.798 78.637 ;
     RECT  31.824 78.367 35.37 78.637 ;
     RECT  7.815 78.359 8.154 78.745 ;
     RECT  7.815 78.745 8.406 79.085 ;
     RECT  9.36 79.051 9.522 79.169 ;
     RECT  30.78 78.637 35.37 79.169 ;
     RECT  2.268 78.359 7.074 79.205 ;
     RECT  30.78 79.169 30.798 79.241 ;
     RECT  2.304 79.205 7.074 79.411 ;
     RECT  7.815 79.085 8.226 79.411 ;
     RECT  2.304 79.411 8.226 79.439 ;
     RECT  31.896 79.169 35.37 79.483 ;
     RECT  9.504 79.169 9.522 79.709 ;
     RECT  31.896 79.483 35.946 79.781 ;
     RECT  31.932 79.781 35.946 79.819 ;
     RECT  31.932 79.819 35.982 80.087 ;
     RECT  35.928 80.087 35.982 80.159 ;
     RECT  2.304 79.439 8.097 80.401 ;
     RECT  10.515 78.629 10.797 80.401 ;
     RECT  2.304 80.401 8.802 80.563 ;
     RECT  30.78 80.527 30.798 80.627 ;
     RECT  10.515 80.401 10.854 80.663 ;
     RECT  31.932 80.087 34.83 80.897 ;
     RECT  2.304 80.563 9.09 80.957 ;
     RECT  3.42 80.957 6.93 81.059 ;
     RECT  31.932 80.897 34.722 81.167 ;
     RECT  6.84 81.059 6.93 81.239 ;
     RECT  7.776 80.957 9.09 81.239 ;
     RECT  9 81.239 9.09 81.329 ;
     RECT  35.928 80.159 35.946 81.595 ;
     RECT  31.932 81.167 34.254 81.715 ;
     RECT  35.928 81.595 35.982 81.751 ;
     RECT  3.492 81.059 5.706 81.841 ;
     RECT  9.36 81.481 9.45 81.869 ;
     RECT  31.392 81.715 34.254 81.869 ;
     RECT  3.492 81.841 5.742 81.979 ;
     RECT  6.84 81.239 6.894 81.985 ;
     RECT  6.552 81.985 6.894 82.075 ;
     RECT  7.776 81.239 8.097 82.075 ;
     RECT  35.928 81.751 36.018 82.109 ;
     RECT  6.552 82.075 8.097 82.139 ;
     RECT  32.04 81.869 34.254 82.175 ;
     RECT  35.928 82.109 35.982 82.219 ;
     RECT  3.42 81.979 5.742 82.291 ;
     RECT  30.924 82.183 30.942 82.291 ;
     RECT  2.304 80.957 2.697 82.445 ;
     RECT  32.076 82.175 34.254 82.453 ;
     RECT  35.352 82.219 35.982 82.453 ;
     RECT  2.34 82.445 2.697 82.459 ;
     RECT  3.42 82.291 5.958 82.459 ;
     RECT  30.852 82.291 30.942 82.489 ;
     RECT  9.18 82.291 9.198 82.517 ;
     RECT  30.78 82.489 30.942 82.517 ;
     RECT  6.876 82.139 8.097 82.679 ;
     RECT  10.515 80.663 10.797 82.957 ;
     RECT  0.252 82.459 0.27 83.021 ;
     RECT  10.515 82.957 10.818 83.102 ;
     RECT  30.78 82.517 30.87 83.129 ;
     RECT  2.34 82.459 5.958 83.179 ;
     RECT  32.076 82.453 35.982 83.213 ;
     RECT  6.876 82.679 7.074 83.219 ;
     RECT  32.076 83.213 34.326 83.299 ;
     RECT  2.304 83.179 5.958 83.371 ;
     RECT  32.04 83.299 34.326 83.371 ;
     RECT  32.004 83.371 34.326 83.533 ;
     RECT  7.815 82.679 8.097 83.569 ;
     RECT  2.304 83.371 6.714 83.707 ;
     RECT  31.932 83.533 34.326 83.731 ;
     RECT  2.268 83.707 6.714 83.759 ;
     RECT  31.86 83.731 34.326 83.789 ;
     RECT  30.852 83.129 30.87 83.795 ;
     RECT  31.932 83.789 34.326 83.831 ;
     RECT  32.04 83.831 34.326 83.867 ;
     RECT  7.596 83.569 8.097 83.911 ;
     RECT  2.268 83.759 6.138 84.029 ;
     RECT  2.268 84.029 5.922 84.065 ;
     RECT  30.816 83.911 30.834 84.073 ;
     RECT  35.352 83.213 35.982 84.101 ;
     RECT  7.596 83.911 8.406 84.145 ;
     RECT  30.78 84.073 30.834 84.173 ;
     RECT  32.112 83.867 34.326 84.181 ;
     RECT  0.216 84.091 0.234 84.187 ;
     RECT  7.056 84.145 8.406 84.335 ;
     RECT  0.216 84.187 0.414 84.365 ;
     RECT  2.268 84.065 5.814 84.371 ;
     RECT  9.216 84.181 9.234 84.371 ;
     RECT  30.816 84.173 30.834 84.371 ;
     RECT  32.112 84.181 34.758 84.371 ;
     RECT  35.928 84.101 35.982 84.475 ;
     RECT  32.112 84.371 34.326 84.685 ;
     RECT  9.612 84.451 9.63 84.749 ;
     RECT  2.268 84.371 4.014 84.845 ;
     RECT  4.752 84.371 5.814 84.847 ;
     RECT  7.815 84.335 8.406 84.883 ;
     RECT  32.04 84.685 34.326 84.883 ;
     RECT  4.752 84.847 5.958 84.955 ;
     RECT  6.768 84.721 6.786 84.955 ;
     RECT  35.928 84.475 36.018 84.955 ;
     RECT  7.815 84.883 8.874 85.109 ;
     RECT  10.515 83.102 10.797 85.117 ;
     RECT  35.928 84.955 36.054 85.181 ;
     RECT  4.752 84.955 6.786 85.189 ;
     RECT  7.815 85.109 8.097 85.189 ;
     RECT  2.304 84.845 4.014 85.225 ;
     RECT  4.752 85.189 8.097 85.225 ;
     RECT  31.284 84.883 34.326 85.261 ;
     RECT  10.515 85.117 10.854 85.289 ;
     RECT  31.284 85.261 34.686 85.627 ;
     RECT  31.284 85.627 34.83 85.685 ;
     RECT  35.928 85.181 36.018 85.757 ;
     RECT  31.284 85.685 31.302 86.197 ;
     RECT  32.115 85.685 34.83 86.251 ;
     RECT  35.928 85.757 35.982 86.251 ;
     RECT  10.515 85.289 10.797 86.305 ;
     RECT  30.924 86.197 31.302 86.305 ;
     RECT  10.515 86.305 10.818 86.459 ;
     RECT  30.78 86.305 31.302 86.459 ;
     RECT  32.115 86.251 35.982 86.639 ;
     RECT  32.115 86.639 34.83 86.737 ;
     RECT  2.304 85.225 8.097 86.909 ;
     RECT  30.78 86.459 30.87 86.909 ;
     RECT  31.788 86.737 34.83 86.909 ;
     RECT  7.632 86.909 8.097 86.999 ;
     RECT  31.788 86.909 34.794 87.107 ;
     RECT  35.928 86.639 35.982 87.377 ;
     RECT  7.704 86.999 8.097 87.421 ;
     RECT  2.304 86.909 5.397 87.691 ;
     RECT  6.228 86.909 6.858 87.691 ;
     RECT  32.076 87.107 34.794 87.739 ;
     RECT  7.704 87.421 8.154 87.809 ;
     RECT  30.78 86.909 30.798 87.817 ;
     RECT  10.515 86.459 10.797 87.853 ;
     RECT  30.78 87.817 30.87 87.853 ;
     RECT  32.076 87.739 34.83 87.883 ;
     RECT  2.304 87.691 6.858 87.889 ;
     RECT  2.304 87.889 6.966 87.925 ;
     RECT  7.704 87.809 8.097 87.925 ;
     RECT  30.78 87.853 30.942 87.925 ;
     RECT  32.076 87.883 34.866 88.087 ;
     RECT  35.964 87.377 35.982 88.123 ;
     RECT  2.304 87.925 8.097 88.151 ;
     RECT  10.515 87.853 10.926 88.151 ;
     RECT  30.78 87.925 31.05 88.205 ;
     RECT  30.78 88.205 30.906 88.223 ;
     RECT  35.928 88.123 35.982 88.259 ;
     RECT  32.04 88.087 34.866 88.321 ;
     RECT  9.576 88.231 9.594 88.349 ;
     RECT  30.78 88.223 30.798 88.349 ;
     RECT  31.86 88.321 34.866 88.363 ;
     RECT  35.928 88.259 35.946 88.363 ;
     RECT  6.12 88.151 8.097 88.619 ;
     RECT  7.38 88.619 8.097 88.655 ;
     RECT  7.524 88.655 8.097 88.889 ;
     RECT  2.304 88.151 5.397 88.891 ;
     RECT  6.12 88.619 6.57 88.891 ;
     RECT  31.86 88.363 35.946 89.179 ;
     RECT  31.86 89.179 35.982 89.303 ;
     RECT  31.86 89.303 35.946 89.357 ;
     RECT  31.86 89.357 34.83 89.401 ;
     RECT  9.252 88.771 9.27 89.429 ;
     RECT  2.304 88.891 6.57 89.509 ;
     RECT  7.815 88.889 8.097 89.509 ;
     RECT  2.304 89.509 6.786 89.659 ;
     RECT  7.815 89.509 8.154 89.659 ;
     RECT  31.68 89.401 34.83 89.699 ;
     RECT  30.78 89.311 30.798 89.743 ;
     RECT  2.268 89.659 8.154 89.815 ;
     RECT  29.415 69.179 29.697 89.977 ;
     RECT  30.78 89.743 30.87 89.977 ;
     RECT  2.268 89.815 8.298 90.005 ;
     RECT  31.932 89.699 34.83 90.311 ;
     RECT  35.928 89.357 35.946 90.331 ;
     RECT  2.304 90.005 8.298 90.383 ;
     RECT  35.928 90.331 35.982 90.475 ;
     RECT  29.415 89.977 30.87 90.509 ;
     RECT  35.352 90.475 35.982 90.515 ;
     RECT  21.315 41.639 21.597 90.517 ;
     RECT  30.78 90.509 30.87 90.617 ;
     RECT  21.096 90.517 21.597 90.689 ;
     RECT  31.068 90.661 31.086 90.751 ;
     RECT  31.932 90.311 34.326 90.751 ;
     RECT  2.304 90.383 8.097 90.779 ;
     RECT  31.068 90.751 34.326 90.779 ;
     RECT  10.515 88.151 10.797 90.787 ;
     RECT  10.515 90.787 10.818 90.887 ;
     RECT  2.304 90.779 6.894 91.049 ;
     RECT  0.216 90.955 0.234 91.085 ;
     RECT  35.928 90.515 35.982 91.147 ;
     RECT  31.428 90.779 34.326 91.193 ;
     RECT  29.415 90.509 29.697 91.291 ;
     RECT  35.928 91.147 36.018 91.291 ;
     RECT  31.86 91.193 34.326 91.399 ;
     RECT  35.352 91.291 36.018 91.399 ;
     RECT  29.415 91.291 30.222 91.633 ;
     RECT  2.304 91.049 6.858 91.771 ;
     RECT  31.86 91.399 36.018 91.805 ;
     RECT  2.268 91.771 6.858 91.861 ;
     RECT  7.668 90.779 8.097 91.861 ;
     RECT  2.268 91.861 8.097 91.931 ;
     RECT  29.415 91.633 30.906 91.967 ;
     RECT  3.672 91.931 3.798 92.129 ;
     RECT  2.268 91.931 2.934 92.165 ;
     RECT  31.86 91.805 34.074 92.587 ;
     RECT  31.86 92.587 34.218 92.641 ;
     RECT  4.752 91.931 8.097 92.669 ;
     RECT  8.892 92.407 8.91 92.669 ;
     RECT  30.78 91.967 30.906 92.677 ;
     RECT  31.752 92.641 34.218 92.677 ;
     RECT  30.78 92.677 34.218 92.777 ;
     RECT  2.304 92.165 2.934 92.821 ;
     RECT  3.672 92.129 3.69 92.821 ;
     RECT  31.572 92.777 34.218 92.849 ;
     RECT  31.752 92.849 34.218 92.983 ;
     RECT  4.752 92.669 6.858 93.011 ;
     RECT  35.352 91.805 36.018 93.067 ;
     RECT  7.596 92.669 8.097 93.091 ;
     RECT  2.304 92.821 3.69 93.217 ;
     RECT  4.752 93.011 6.03 93.217 ;
     RECT  35.352 93.067 36.054 93.245 ;
     RECT  0.216 93.307 0.234 93.437 ;
     RECT  6.84 93.011 6.858 93.499 ;
     RECT  7.596 93.091 8.73 93.499 ;
     RECT  31.752 92.983 34.434 93.547 ;
     RECT  31.752 93.547 34.758 93.595 ;
     RECT  6.84 93.499 8.73 93.659 ;
     RECT  35.928 93.245 36.054 93.857 ;
     RECT  2.304 93.217 6.03 93.883 ;
     RECT  9.108 93.829 9.126 93.929 ;
     RECT  31.716 93.595 34.758 93.991 ;
     RECT  35.928 93.857 35.946 93.991 ;
     RECT  2.268 93.883 6.03 94.055 ;
     RECT  6.84 93.659 8.19 94.061 ;
     RECT  2.304 94.055 6.03 94.064 ;
     RECT  4.032 94.064 6.03 94.099 ;
     RECT  6.84 94.061 6.966 94.099 ;
     RECT  7.815 94.061 8.19 94.441 ;
     RECT  31.716 93.991 35.946 94.541 ;
     RECT  7.815 94.441 8.586 94.559 ;
     RECT  9.36 94.441 9.378 94.559 ;
     RECT  30.78 92.777 30.798 94.639 ;
     RECT  7.815 94.559 8.298 94.703 ;
     RECT  4.032 94.099 6.966 94.829 ;
     RECT  35.928 94.541 35.946 94.873 ;
     RECT  31.716 94.541 34.758 94.901 ;
     RECT  30.78 94.639 30.87 94.937 ;
     RECT  2.304 94.064 3.294 94.981 ;
     RECT  4.032 94.829 6.93 94.981 ;
     RECT  35.928 94.873 35.982 95.021 ;
     RECT  2.304 94.981 6.93 95.171 ;
     RECT  31.932 94.901 34.758 95.323 ;
     RECT  9.108 95.251 9.126 95.369 ;
     RECT  30.852 94.937 30.87 95.377 ;
     RECT  6.768 95.171 6.93 95.513 ;
     RECT  7.815 94.703 8.226 95.513 ;
     RECT  35.928 95.021 35.946 95.659 ;
     RECT  6.804 95.513 6.93 95.683 ;
     RECT  7.815 95.513 8.19 95.683 ;
     RECT  30.852 95.377 30.942 95.683 ;
     RECT  31.932 95.323 34.794 95.683 ;
     RECT  6.804 95.683 8.19 95.741 ;
     RECT  35.892 95.659 35.946 95.819 ;
     RECT  6.804 95.741 8.097 95.909 ;
     RECT  2.304 95.171 5.85 96.061 ;
     RECT  30.852 95.683 34.794 96.139 ;
     RECT  30.852 96.139 35.37 96.151 ;
     RECT  0.252 96.139 0.27 96.269 ;
     RECT  2.304 96.061 5.886 96.283 ;
     RECT  30.78 96.151 35.37 96.323 ;
     RECT  30.78 96.323 34.434 96.449 ;
     RECT  9.072 96.529 9.09 96.601 ;
     RECT  7.092 95.909 8.097 96.719 ;
     RECT  9.072 96.601 9.126 96.719 ;
     RECT  0.216 96.619 0.234 96.749 ;
     RECT  9.072 96.719 9.09 96.755 ;
     RECT  30.78 96.449 34.254 96.791 ;
     RECT  2.304 96.283 6.318 96.799 ;
     RECT  35.352 96.323 35.37 96.811 ;
     RECT  35.352 96.811 35.946 97.291 ;
     RECT  35.352 97.291 35.982 97.367 ;
     RECT  35.892 97.367 35.982 97.435 ;
     RECT  0.252 97.339 0.27 97.469 ;
     RECT  7.596 96.719 8.097 97.501 ;
     RECT  2.304 96.799 6.75 97.609 ;
     RECT  7.524 97.501 8.097 97.609 ;
     RECT  31.428 96.791 34.254 97.609 ;
     RECT  35.892 97.435 36.018 97.709 ;
     RECT  31.068 97.609 34.254 97.799 ;
     RECT  2.304 97.609 8.097 97.835 ;
     RECT  31.86 97.799 34.254 98.059 ;
     RECT  10.515 90.887 10.797 98.113 ;
     RECT  3.816 97.835 8.097 98.221 ;
     RECT  10.515 98.113 10.818 98.249 ;
     RECT  31.86 98.059 34.794 98.339 ;
     RECT  30.996 97.807 31.014 98.383 ;
     RECT  3.816 98.221 8.586 98.411 ;
     RECT  30.78 98.383 31.014 98.447 ;
     RECT  30.78 98.447 30.798 98.519 ;
     RECT  9.468 98.491 9.486 98.581 ;
     RECT  32.115 98.339 34.794 98.587 ;
     RECT  3.816 98.411 8.097 98.621 ;
     RECT  3.816 98.621 5.958 98.717 ;
     RECT  2.304 97.835 2.862 98.761 ;
     RECT  9.468 98.581 9.594 98.851 ;
     RECT  9.252 98.851 9.594 99.149 ;
     RECT  0.216 99.157 0.234 99.245 ;
     RECT  2.304 98.761 3.33 99.355 ;
     RECT  32.115 98.587 34.902 99.355 ;
     RECT  35.892 97.709 35.946 99.355 ;
     RECT  32.115 99.355 35.946 99.427 ;
     RECT  2.268 99.355 3.33 99.563 ;
     RECT  2.304 99.563 3.33 99.571 ;
     RECT  4.068 98.717 5.958 99.571 ;
     RECT  9.36 99.149 9.594 99.599 ;
     RECT  6.804 98.621 8.097 99.661 ;
     RECT  31.644 99.427 35.946 99.697 ;
     RECT  6.804 99.661 8.586 99.739 ;
     RECT  2.304 99.571 5.994 99.841 ;
     RECT  6.732 99.739 8.586 99.841 ;
     RECT  10.515 98.249 10.797 99.841 ;
     RECT  2.304 99.841 8.586 99.959 ;
     RECT  9.36 99.599 9.378 99.959 ;
     RECT  31.572 99.697 35.946 100.003 ;
     RECT  10.515 99.841 10.818 100.067 ;
     RECT  30.852 100.003 35.946 100.067 ;
     RECT  30.852 100.067 30.87 100.103 ;
     RECT  9.54 100.651 9.666 100.769 ;
     RECT  0.252 100.651 0.27 100.829 ;
     RECT  9.648 100.769 9.666 100.841 ;
     RECT  2.304 99.959 8.097 100.921 ;
     RECT  2.304 100.921 8.802 101.047 ;
     RECT  32.04 100.067 35.946 101.191 ;
     RECT  2.304 101.047 8.874 101.357 ;
     RECT  2.304 101.357 6.93 101.579 ;
     RECT  7.815 101.357 8.874 101.623 ;
     RECT  31.968 101.191 35.946 101.623 ;
     RECT  7.815 101.623 9.054 101.731 ;
     RECT  31.824 101.623 35.946 101.803 ;
     RECT  7.815 101.731 9.27 101.849 ;
     RECT  31.824 101.803 35.982 101.849 ;
     RECT  7.815 101.849 8.406 101.885 ;
     RECT  30.78 101.047 30.798 101.893 ;
     RECT  2.304 101.579 6.03 101.921 ;
     RECT  2.304 101.921 5.958 101.957 ;
     RECT  6.84 101.579 6.93 101.957 ;
     RECT  9.252 101.849 9.27 101.957 ;
     RECT  6.912 101.957 6.93 101.993 ;
     RECT  10.515 100.067 10.797 102.091 ;
     RECT  6.948 102.091 6.966 102.155 ;
     RECT  7.815 101.885 8.097 102.163 ;
     RECT  10.515 102.091 10.926 102.299 ;
     RECT  2.304 101.957 5.886 102.389 ;
     RECT  2.304 102.389 3.51 102.605 ;
     RECT  2.304 102.605 3.474 102.619 ;
     RECT  2.268 102.619 3.474 102.659 ;
     RECT  32.04 101.849 35.982 102.739 ;
     RECT  32.04 102.739 36.018 102.775 ;
     RECT  31.932 102.775 36.018 102.797 ;
     RECT  4.284 102.389 5.886 102.811 ;
     RECT  30.78 101.893 30.87 102.937 ;
     RECT  31.932 102.797 35.982 102.937 ;
     RECT  2.268 102.659 3.402 102.965 ;
     RECT  6.984 102.163 8.097 103.081 ;
     RECT  30.78 102.937 35.982 103.133 ;
     RECT  6.984 103.081 8.226 103.243 ;
     RECT  4.284 102.811 5.958 103.315 ;
     RECT  30.78 103.133 34.83 103.469 ;
     RECT  6.768 103.243 8.226 103.549 ;
     RECT  6.768 103.549 8.37 103.621 ;
     RECT  35.928 103.133 35.982 103.649 ;
     RECT  6.768 103.621 8.478 103.739 ;
     RECT  31.824 103.469 34.83 103.739 ;
     RECT  4.212 103.315 5.958 103.747 ;
     RECT  6.768 103.739 6.93 103.747 ;
     RECT  2.304 102.965 3.402 103.891 ;
     RECT  4.212 103.747 6.93 103.891 ;
     RECT  7.704 103.739 8.478 104.089 ;
     RECT  30.78 103.469 30.87 104.153 ;
     RECT  2.304 103.891 6.93 104.189 ;
     RECT  7.704 104.089 8.586 104.189 ;
     RECT  31.932 103.739 34.83 104.251 ;
     RECT  35.928 103.649 35.946 104.251 ;
     RECT  7.704 104.189 8.118 104.315 ;
     RECT  10.515 102.299 10.797 104.431 ;
     RECT  31.932 104.251 35.946 104.459 ;
     RECT  2.415 104.189 6.93 104.491 ;
     RECT  9.036 104.431 9.054 104.549 ;
     RECT  31.932 104.459 35.406 104.557 ;
     RECT  30.852 104.153 30.87 104.629 ;
     RECT  9.072 104.593 9.09 104.635 ;
     RECT  9.072 104.635 9.198 104.669 ;
     RECT  9.108 104.669 9.198 104.693 ;
     RECT  10.515 104.431 10.854 104.693 ;
     RECT  30.852 104.629 30.942 104.693 ;
     RECT  2.415 104.491 7.074 104.819 ;
     RECT  30.924 104.693 30.942 104.827 ;
     RECT  31.68 104.557 35.406 104.827 ;
     RECT  9.108 104.693 9.126 104.855 ;
     RECT  0.252 103.003 0.27 104.861 ;
     RECT  6.732 104.819 7.074 104.891 ;
     RECT  2.415 104.819 5.814 105.019 ;
     RECT  6.804 104.891 7.074 105.169 ;
     RECT  7.815 104.315 8.097 105.169 ;
     RECT  30.924 104.827 35.406 105.233 ;
     RECT  6.804 105.169 8.097 105.241 ;
     RECT  6.804 105.241 8.262 105.269 ;
     RECT  6.804 105.269 7.038 105.437 ;
     RECT  35.352 105.233 35.406 105.511 ;
     RECT  2.304 105.019 5.814 105.601 ;
     RECT  30.924 105.233 34.254 105.601 ;
     RECT  2.304 105.601 5.994 105.745 ;
     RECT  6.804 105.437 6.93 105.745 ;
     RECT  2.304 105.745 6.93 105.781 ;
     RECT  7.815 105.269 8.262 105.781 ;
     RECT  2.268 105.781 6.93 105.869 ;
     RECT  35.352 105.511 35.982 105.869 ;
     RECT  2.304 105.869 6.93 105.899 ;
     RECT  30.78 105.601 34.254 105.899 ;
     RECT  31.824 105.899 34.254 105.979 ;
     RECT  35.352 105.869 35.946 105.979 ;
     RECT  7.815 105.781 9.018 106.015 ;
     RECT  7.815 106.015 9.054 106.285 ;
     RECT  7.776 106.285 9.054 106.349 ;
     RECT  31.824 105.979 35.946 106.439 ;
     RECT  7.776 106.349 8.514 106.493 ;
     RECT  31.824 106.439 34.794 106.547 ;
     RECT  31.968 106.547 34.326 106.619 ;
     RECT  30.78 105.899 30.906 106.817 ;
     RECT  2.304 105.899 6.858 106.861 ;
     RECT  32.115 106.619 34.326 106.979 ;
     RECT  35.928 106.439 35.946 106.987 ;
     RECT  9.324 106.861 9.342 107.051 ;
     RECT  7.815 106.493 8.514 107.069 ;
     RECT  30.78 106.817 30.87 107.123 ;
     RECT  9.36 107.131 9.486 107.249 ;
     RECT  10.515 104.693 10.797 107.293 ;
     RECT  2.304 106.861 6.93 107.401 ;
     RECT  10.515 107.293 10.926 107.429 ;
     RECT  2.304 107.401 7.074 107.467 ;
     RECT  35.928 106.987 35.982 107.467 ;
     RECT  9.36 107.249 9.378 107.519 ;
     RECT  35.928 107.467 36.054 107.611 ;
     RECT  2.268 107.467 7.074 107.627 ;
     RECT  35.352 107.611 36.054 107.627 ;
     RECT  32.115 106.979 34.29 107.635 ;
     RECT  30.852 107.123 30.87 107.797 ;
     RECT  31.716 107.635 34.29 107.941 ;
     RECT  35.352 107.627 35.982 107.941 ;
     RECT  7.815 107.069 8.097 108.067 ;
     RECT  30.852 107.797 30.906 108.067 ;
     RECT  7.815 108.067 8.37 108.239 ;
     RECT  30.78 108.067 30.906 108.239 ;
     RECT  31.716 107.941 35.982 108.239 ;
     RECT  7.815 108.239 8.298 108.329 ;
     RECT  2.304 107.627 7.074 108.473 ;
     RECT  6.768 108.473 7.074 108.481 ;
     RECT  7.815 108.329 8.097 108.481 ;
     RECT  30.78 108.239 30.87 108.509 ;
     RECT  10.515 107.429 10.797 108.679 ;
     RECT  35.928 108.239 35.982 108.715 ;
     RECT  10.515 108.679 10.818 108.749 ;
     RECT  35.928 108.715 36.018 108.941 ;
     RECT  35.928 108.941 35.982 109.013 ;
     RECT  31.716 108.239 34.794 109.099 ;
     RECT  31.716 109.099 34.866 109.147 ;
     RECT  31.68 109.147 34.866 109.243 ;
     RECT  30.78 108.509 30.798 109.283 ;
     RECT  31.68 109.243 34.938 109.319 ;
     RECT  31.932 109.319 34.938 109.409 ;
     RECT  2.304 108.473 6.03 109.417 ;
     RECT  6.768 108.481 8.097 109.417 ;
     RECT  2.304 109.417 8.097 109.561 ;
     RECT  9.036 109.525 9.054 109.561 ;
     RECT  32.115 109.409 34.938 109.561 ;
     RECT  35.928 109.013 35.946 109.561 ;
     RECT  2.304 109.561 9.054 109.589 ;
     RECT  2.304 109.589 6.858 109.679 ;
     RECT  7.815 109.589 9.054 109.679 ;
     RECT  9.036 109.679 9.054 109.723 ;
     RECT  2.304 109.679 6.822 109.859 ;
     RECT  9.036 109.723 9.126 109.859 ;
     RECT  7.815 109.679 8.19 109.949 ;
     RECT  30.852 109.561 30.87 109.949 ;
     RECT  2.304 109.859 2.754 110.203 ;
     RECT  9.252 109.921 9.27 110.219 ;
     RECT  32.115 109.561 35.946 110.299 ;
     RECT  31.68 110.299 35.946 110.429 ;
     RECT  35.352 110.429 35.946 110.489 ;
     RECT  2.268 110.203 2.754 110.525 ;
     RECT  2.304 110.525 2.754 110.641 ;
     RECT  3.672 109.859 6.822 110.669 ;
     RECT  6.552 110.669 6.822 110.731 ;
     RECT  7.815 109.949 8.097 110.731 ;
     RECT  2.304 110.641 2.862 110.779 ;
     RECT  3.672 110.669 5.742 110.779 ;
     RECT  0.216 110.683 0.234 110.813 ;
     RECT  9.36 110.371 9.378 110.867 ;
     RECT  6.552 110.731 8.097 110.911 ;
     RECT  30.78 110.767 30.798 110.939 ;
     RECT  29.415 91.967 29.697 111.037 ;
     RECT  6.552 110.911 8.514 111.145 ;
     RECT  31.68 110.429 34.326 111.211 ;
     RECT  6.552 111.145 9.126 111.299 ;
     RECT  7.344 111.299 9.126 111.335 ;
     RECT  7.344 111.335 9.09 111.407 ;
     RECT  2.304 110.779 5.742 111.451 ;
     RECT  7.704 111.407 9.09 111.569 ;
     RECT  29.415 111.037 30.222 111.569 ;
     RECT  31.68 111.211 34.794 111.613 ;
     RECT  35.928 110.489 35.946 111.691 ;
     RECT  31.14 111.613 34.794 111.721 ;
     RECT  31.068 111.721 34.794 111.835 ;
     RECT  35.928 111.691 36.018 111.835 ;
     RECT  31.068 111.835 36.018 111.839 ;
     RECT  32.004 111.839 36.018 111.947 ;
     RECT  9.036 111.569 9.09 112.081 ;
     RECT  32.004 111.947 35.982 112.109 ;
     RECT  30.78 111.883 30.798 112.217 ;
     RECT  32.115 112.109 35.982 112.217 ;
     RECT  2.304 111.451 6.498 112.423 ;
     RECT  2.304 112.423 6.714 112.531 ;
     RECT  7.815 111.569 8.097 112.531 ;
     RECT  2.304 112.531 8.097 112.691 ;
     RECT  9.036 112.081 9.126 112.757 ;
     RECT  35.352 112.217 35.982 112.795 ;
     RECT  7.815 112.691 8.097 112.801 ;
     RECT  2.304 112.691 6.93 112.829 ;
     RECT  35.352 112.795 36.018 112.829 ;
     RECT  7.815 112.801 8.514 112.919 ;
     RECT  30.852 112.963 30.87 113.063 ;
     RECT  32.115 112.217 34.398 113.131 ;
     RECT  35.928 112.829 36.018 113.275 ;
     RECT  30.78 113.071 30.798 113.297 ;
     RECT  6.732 112.829 6.93 113.419 ;
     RECT  32.115 113.131 34.794 113.431 ;
     RECT  35.928 113.275 36.054 113.603 ;
     RECT  6.732 113.419 6.966 113.611 ;
     RECT  31.86 113.431 34.794 113.611 ;
     RECT  2.304 112.829 5.958 113.701 ;
     RECT  6.696 113.611 7.002 113.701 ;
     RECT  9.36 113.611 9.522 113.729 ;
     RECT  31.86 113.611 34.83 113.737 ;
     RECT  2.304 113.701 7.002 113.881 ;
     RECT  7.815 112.919 8.097 113.881 ;
     RECT  0.216 113.851 0.234 113.981 ;
     RECT  2.304 113.881 8.097 113.999 ;
     RECT  9.36 113.729 9.378 114.151 ;
     RECT  35.928 113.603 36.018 114.179 ;
     RECT  2.304 113.999 5.922 114.269 ;
     RECT  9.108 114.151 9.378 114.269 ;
     RECT  30.78 114.151 30.798 114.277 ;
     RECT  31.68 113.737 34.83 114.277 ;
     RECT  30.78 114.277 34.83 114.341 ;
     RECT  30.78 114.341 34.434 114.377 ;
     RECT  6.732 113.999 8.097 114.449 ;
     RECT  29.415 111.569 29.697 114.547 ;
     RECT  30.78 114.377 34.218 114.547 ;
     RECT  6.804 114.449 8.097 114.575 ;
     RECT  29.415 114.547 34.218 114.683 ;
     RECT  35.928 114.179 35.946 114.763 ;
     RECT  9.108 114.269 9.126 114.809 ;
     RECT  2.304 114.269 5.706 115.051 ;
     RECT  35.352 114.763 35.946 115.085 ;
     RECT  2.268 115.051 5.706 115.123 ;
     RECT  2.268 115.123 5.85 115.223 ;
     RECT  30.78 114.683 34.218 115.349 ;
     RECT  32.04 115.349 34.218 115.387 ;
     RECT  35.352 115.085 35.442 115.387 ;
     RECT  6.804 114.575 6.93 115.429 ;
     RECT  7.668 114.575 8.097 115.429 ;
     RECT  2.304 115.223 5.85 115.501 ;
     RECT  32.04 115.387 35.442 115.529 ;
     RECT  2.304 115.501 5.886 115.579 ;
     RECT  2.304 115.579 6.03 115.591 ;
     RECT  6.804 115.429 8.097 115.591 ;
     RECT  30.78 115.349 30.87 115.619 ;
     RECT  2.304 115.591 8.097 115.691 ;
     RECT  0.252 115.579 0.27 115.709 ;
     RECT  35.352 115.529 35.442 115.867 ;
     RECT  32.04 115.529 34.326 116.167 ;
     RECT  9.036 116.041 9.054 116.231 ;
     RECT  30.852 115.619 30.87 116.267 ;
     RECT  31.752 116.167 34.326 116.339 ;
     RECT  35.352 115.867 35.946 116.347 ;
     RECT  9.108 116.311 9.126 116.537 ;
     RECT  2.304 115.691 2.898 116.581 ;
     RECT  3.816 115.691 8.097 116.581 ;
     RECT  35.316 116.347 35.946 116.609 ;
     RECT  31.968 116.339 34.326 116.683 ;
     RECT  0.252 116.683 0.27 116.813 ;
     RECT  2.304 116.581 8.097 116.813 ;
     RECT  35.928 116.609 35.946 116.827 ;
     RECT  9.468 116.581 9.486 117.113 ;
     RECT  31.968 116.683 34.83 117.247 ;
     RECT  31.32 117.247 34.83 117.499 ;
     RECT  35.928 116.827 35.982 117.499 ;
     RECT  31.32 117.499 35.982 117.553 ;
     RECT  30.852 117.553 35.982 117.625 ;
     RECT  2.304 116.813 5.742 117.787 ;
     RECT  6.516 116.813 8.097 117.787 ;
     RECT  30.78 117.625 35.982 117.887 ;
     RECT  2.304 117.787 8.097 117.931 ;
     RECT  2.304 117.931 8.442 118.049 ;
     RECT  31.5 117.887 35.982 118.123 ;
     RECT  2.304 118.049 7.074 118.157 ;
     RECT  31.5 118.123 36.054 118.157 ;
     RECT  31.5 118.157 34.254 118.319 ;
     RECT  35.316 118.157 36.054 118.499 ;
     RECT  7.815 118.049 8.442 118.669 ;
     RECT  31.788 118.319 34.254 118.895 ;
     RECT  32.004 118.895 34.254 118.975 ;
     RECT  2.304 118.157 6.57 119.131 ;
     RECT  7.815 118.669 8.586 119.131 ;
     RECT  32.004 118.975 34.326 119.131 ;
     RECT  35.316 118.499 35.946 119.131 ;
     RECT  2.304 119.131 8.586 119.201 ;
     RECT  10.515 108.749 10.797 119.209 ;
     RECT  3.96 119.201 8.586 119.281 ;
     RECT  30.78 118.903 30.798 119.443 ;
     RECT  10.515 119.209 10.818 119.471 ;
     RECT  32.004 119.131 35.946 119.515 ;
     RECT  3.96 119.281 8.91 119.579 ;
     RECT  3.96 119.579 8.586 119.669 ;
     RECT  32.004 119.515 35.982 119.677 ;
     RECT  31.932 119.677 35.982 119.789 ;
     RECT  31.932 119.789 35.946 119.813 ;
     RECT  6.84 119.669 8.586 119.939 ;
     RECT  31.932 119.813 34.83 119.941 ;
     RECT  31.86 119.941 34.83 119.981 ;
     RECT  2.304 119.201 3.114 120.091 ;
     RECT  3.96 119.669 5.778 120.091 ;
     RECT  30.78 119.443 30.87 120.119 ;
     RECT  6.84 119.939 8.298 120.389 ;
     RECT  2.304 120.091 5.778 120.559 ;
     RECT  6.84 120.389 8.154 120.559 ;
     RECT  35.928 119.813 35.946 120.571 ;
     RECT  0.216 120.715 0.234 120.845 ;
     RECT  2.304 120.559 8.154 121.019 ;
     RECT  31.932 119.981 34.83 121.019 ;
     RECT  31.932 121.019 33.642 121.027 ;
     RECT  31.428 121.027 33.642 121.063 ;
     RECT  7.815 121.019 8.154 121.171 ;
     RECT  8.892 120.829 8.982 121.171 ;
     RECT  34.776 121.019 34.83 121.171 ;
     RECT  35.928 120.571 35.982 121.171 ;
     RECT  34.776 121.171 35.982 121.229 ;
     RECT  10.515 119.471 10.797 121.261 ;
     RECT  21.315 90.689 21.597 121.333 ;
     RECT  10.515 121.261 10.926 121.361 ;
     RECT  35.856 121.229 35.982 121.387 ;
     RECT  7.815 121.171 9.09 121.397 ;
     RECT  21.096 121.333 21.597 121.559 ;
     RECT  30.78 121.063 33.642 121.559 ;
     RECT  35.856 121.387 36.018 121.667 ;
     RECT  9.072 121.397 9.09 121.711 ;
     RECT  9.072 121.711 9.702 121.739 ;
     RECT  31.788 121.559 33.642 121.801 ;
     RECT  34.776 121.229 34.794 121.801 ;
     RECT  9.684 121.739 9.702 121.829 ;
     RECT  2.304 121.019 7.002 121.837 ;
     RECT  10.515 121.361 10.854 121.937 ;
     RECT  30.78 121.559 30.87 121.937 ;
     RECT  7.815 121.397 8.298 121.949 ;
     RECT  2.304 121.837 7.038 122.011 ;
     RECT  31.788 121.801 34.794 122.011 ;
     RECT  35.856 121.667 35.946 122.011 ;
     RECT  2.268 122.011 7.038 122.207 ;
     RECT  31.788 122.011 35.946 122.279 ;
     RECT  29.415 114.683 29.697 122.341 ;
     RECT  30.78 121.937 30.834 122.341 ;
     RECT  31.788 122.279 34.902 122.369 ;
     RECT  2.304 122.207 7.038 122.449 ;
     RECT  7.815 121.949 8.097 122.449 ;
     RECT  35.856 122.279 35.946 122.818 ;
     RECT  2.304 122.449 8.097 122.819 ;
     RECT  29.415 122.341 30.834 122.881 ;
     RECT  29.415 122.881 30.87 122.909 ;
     RECT  6.804 122.819 8.097 122.981 ;
     RECT  30.78 122.909 30.87 123.017 ;
     RECT  30.78 123.017 30.798 123.089 ;
     RECT  31.896 122.369 34.902 123.151 ;
     RECT  2.304 122.819 5.994 123.163 ;
     RECT  31.788 123.151 34.902 123.163 ;
     RECT  35.856 122.818 35.982 123.163 ;
     RECT  31.788 123.163 35.982 123.307 ;
     RECT  31.788 123.307 36.018 123.449 ;
     RECT  2.268 123.163 5.994 123.601 ;
     RECT  6.804 122.981 6.93 123.601 ;
     RECT  7.815 122.981 8.097 123.601 ;
     RECT  7.815 123.601 8.298 123.719 ;
     RECT  2.268 123.601 6.93 123.755 ;
     RECT  31.896 123.449 36.018 123.899 ;
     RECT  9.18 123.871 9.198 124.033 ;
     RECT  2.304 123.755 6.858 124.061 ;
     RECT  35.352 123.899 36.018 124.097 ;
     RECT  30.852 123.763 30.87 124.141 ;
     RECT  9.18 124.033 9.27 124.169 ;
     RECT  30.78 124.141 30.87 124.231 ;
     RECT  31.896 123.899 34.326 124.231 ;
     RECT  7.815 123.719 8.154 124.261 ;
     RECT  30.78 124.231 34.326 124.301 ;
     RECT  2.304 124.061 6.822 124.439 ;
     RECT  30.78 124.301 31.374 124.529 ;
     RECT  30.78 124.529 30.798 124.637 ;
     RECT  35.352 124.097 35.982 124.637 ;
     RECT  32.115 124.301 34.326 124.795 ;
     RECT  35.352 124.637 35.406 124.795 ;
     RECT  3.852 124.439 6.822 124.807 ;
     RECT  7.812 124.261 8.154 124.807 ;
     RECT  3.852 124.807 8.154 124.835 ;
     RECT  4.968 124.835 8.154 124.891 ;
     RECT  2.304 124.439 2.97 125.069 ;
     RECT  4.968 124.891 8.37 125.069 ;
     RECT  36.468 124.939 36.486 125.179 ;
     RECT  4.968 125.069 6.858 125.213 ;
     RECT  36.468 125.179 36.558 125.213 ;
     RECT  3.852 124.835 4.086 125.221 ;
     RECT  32.115 124.795 35.406 125.221 ;
     RECT  4.968 125.213 6.786 125.411 ;
     RECT  9.324 124.231 9.342 125.609 ;
     RECT  30.852 125.581 30.87 125.653 ;
     RECT  3.636 125.221 4.086 125.689 ;
     RECT  4.968 125.411 6.282 125.689 ;
     RECT  7.776 125.069 8.37 125.741 ;
     RECT  32.076 125.221 35.406 125.755 ;
     RECT  30.78 125.653 30.87 125.789 ;
     RECT  32.076 125.755 35.622 125.789 ;
     RECT  2.304 125.069 2.697 125.899 ;
     RECT  3.636 125.689 6.282 125.899 ;
     RECT  32.076 125.789 34.794 125.923 ;
     RECT  7.02 125.995 7.038 126.149 ;
     RECT  7.776 125.741 8.298 126.149 ;
     RECT  2.304 125.899 6.282 126.221 ;
     RECT  4.5 126.221 6.282 126.229 ;
     RECT  31.968 125.923 34.794 126.229 ;
     RECT  36.54 125.213 36.558 126.235 ;
     RECT  4.5 126.229 7.002 126.329 ;
     RECT  31.392 126.229 34.794 126.329 ;
     RECT  2.304 126.221 3.69 126.379 ;
     RECT  2.268 126.379 3.69 126.527 ;
     RECT  7.812 126.149 8.154 126.869 ;
     RECT  31.392 126.329 34.758 126.967 ;
     RECT  4.5 126.329 5.85 127.051 ;
     RECT  6.624 126.329 7.002 127.051 ;
     RECT  30.78 126.967 34.758 127.051 ;
     RECT  35.604 125.789 35.622 127.051 ;
     RECT  30.78 127.051 35.622 127.067 ;
     RECT  4.5 127.051 7.002 127.099 ;
     RECT  7.812 126.869 8.097 127.099 ;
     RECT  2.304 126.527 3.69 127.111 ;
     RECT  31.392 127.067 35.622 127.229 ;
     RECT  2.304 127.111 3.762 127.265 ;
     RECT  4.5 127.099 8.097 127.265 ;
     RECT  4.5 127.265 7.002 127.381 ;
     RECT  4.176 127.381 7.002 127.499 ;
     RECT  32.115 127.229 35.622 127.499 ;
     RECT  2.304 127.265 3.402 127.535 ;
     RECT  4.176 127.499 6.282 127.535 ;
     RECT  4.392 127.535 6.282 127.571 ;
     RECT  4.644 127.571 6.282 127.769 ;
     RECT  35.352 127.499 35.622 127.769 ;
     RECT  2.34 127.535 3.402 127.805 ;
     RECT  4.644 127.769 6.102 127.841 ;
     RECT  35.604 127.769 35.622 127.877 ;
     RECT  4.716 127.841 5.814 127.913 ;
     RECT  2.415 127.805 3.042 127.949 ;
     RECT  4.716 127.913 5.397 127.949 ;
     RECT  9.504 127.381 9.522 127.949 ;
     RECT  30.852 127.813 30.87 128.039 ;
     RECT  30.78 128.047 30.798 128.147 ;
     RECT  36.432 126.235 36.558 128.579 ;
     RECT  36.432 128.579 36.522 128.849 ;
     RECT  32.115 127.499 34.506 128.885 ;
     RECT  33.948 128.885 34.506 128.957 ;
     RECT  36.504 128.849 36.522 129.029 ;
     RECT  33.948 128.957 34.434 129.119 ;
     RECT  33.948 129.119 34.398 129.155 ;
     RECT  34.38 129.155 34.398 129.299 ;
     RECT  2.415 127.949 2.697 129.347 ;
     RECT  5.115 127.949 5.397 129.347 ;
     RECT  7.815 127.265 8.097 129.347 ;
     RECT  10.515 121.937 10.797 129.347 ;
     RECT  13.215 2.413 13.497 129.347 ;
     RECT  15.915 2.413 16.197 129.347 ;
     RECT  18.615 2.413 18.897 129.347 ;
     RECT  21.315 121.559 21.597 129.347 ;
     RECT  24.015 2.413 24.297 129.347 ;
     RECT  26.715 72.869 26.997 129.347 ;
     RECT  29.415 122.909 29.697 129.347 ;
     RECT  32.115 128.885 32.397 129.347 ;
     RECT  2.415 129.347 2.505 129.617 ;
     RECT  5.115 129.347 5.205 129.617 ;
     RECT  7.815 129.347 7.905 129.617 ;
     RECT  10.515 129.347 10.605 129.617 ;
     RECT  13.215 129.347 13.305 129.617 ;
     RECT  15.915 129.347 16.005 129.617 ;
     RECT  18.615 129.347 18.705 129.617 ;
     RECT  21.315 129.347 21.405 129.617 ;
     RECT  24.015 129.347 24.105 129.617 ;
     RECT  26.715 129.347 26.805 129.617 ;
     RECT  29.415 129.347 29.505 129.617 ;
     RECT  32.115 129.347 32.205 129.617 ;
     RECT  18.18 131.628 18.198 131.645 ;
    LAYER M4 ;
     RECT  0.156 4.416 2.408 127.416 ;
     RECT  2.408 2.148 2.512 129.612 ;
     RECT  2.512 2.418 2.704 129.342 ;
     RECT  2.704 4.512 2.729 4.776 ;
     RECT  2.704 27.648 2.729 31.464 ;
     RECT  2.704 10.128 2.765 11.208 ;
     RECT  2.704 19.632 2.765 19.8 ;
     RECT  2.704 36.912 2.765 37.464 ;
     RECT  2.704 41.76 2.765 43.128 ;
     RECT  2.704 44.352 2.765 48.744 ;
     RECT  2.704 58.512 2.765 63.144 ;
     RECT  2.704 68.208 2.765 71.832 ;
     RECT  2.704 76.56 2.765 88.392 ;
     RECT  2.704 98.88 2.765 104.904 ;
     RECT  2.704 106.176 2.765 107.016 ;
     RECT  2.704 119.424 2.765 126.744 ;
     RECT  2.704 18 2.801 18.024 ;
     RECT  2.765 19.776 2.801 19.8 ;
     RECT  2.729 27.84 2.801 31.464 ;
     RECT  2.704 39.504 2.801 40.344 ;
     RECT  2.765 44.352 2.801 46.824 ;
     RECT  2.765 48.24 2.801 48.744 ;
     RECT  2.704 52.08 2.801 54.12 ;
     RECT  2.704 64.416 2.801 66.552 ;
     RECT  2.765 76.56 2.801 86.664 ;
     RECT  2.765 88.08 2.801 88.392 ;
     RECT  2.704 108.624 2.801 108.648 ;
     RECT  2.704 112.176 2.801 115.704 ;
     RECT  2.704 116.784 2.801 118.344 ;
     RECT  2.765 119.424 2.801 119.448 ;
     RECT  2.765 123.696 2.801 125.928 ;
     RECT  2.801 48.432 2.837 48.744 ;
     RECT  2.765 99.696 2.837 104.904 ;
     RECT  2.704 32.976 2.873 34.68 ;
     RECT  2.801 39.888 2.873 40.344 ;
     RECT  2.704 7.92 2.909 8.808 ;
     RECT  2.704 23.28 2.909 23.304 ;
     RECT  2.704 50.016 2.909 50.568 ;
     RECT  2.801 112.656 2.909 115.704 ;
     RECT  2.801 116.784 2.909 118.296 ;
     RECT  2.801 28.848 2.945 31.464 ;
     RECT  2.801 44.352 2.981 46.008 ;
     RECT  2.704 55.68 2.981 57.384 ;
     RECT  2.909 8.784 3.017 8.808 ;
     RECT  2.981 56.352 3.017 57.384 ;
     RECT  2.765 60.336 3.017 63.144 ;
     RECT  2.801 66.528 3.017 66.552 ;
     RECT  2.801 125.04 3.017 125.928 ;
     RECT  2.801 88.08 3.089 88.104 ;
     RECT  2.704 90 3.089 91.08 ;
     RECT  2.765 120.48 3.089 122.52 ;
     RECT  2.765 11.184 3.125 11.208 ;
     RECT  2.945 28.848 3.125 30.648 ;
     RECT  2.981 44.352 3.125 45.72 ;
     RECT  2.704 110.784 3.125 111.048 ;
     RECT  3.017 56.88 3.161 57.384 ;
     RECT  2.765 10.128 3.197 10.152 ;
     RECT  2.704 12.864 3.197 12.888 ;
     RECT  2.801 76.56 3.197 83.16 ;
     RECT  2.909 112.656 3.197 114.84 ;
     RECT  2.704 15.744 3.233 16.584 ;
     RECT  3.125 44.976 3.233 45.72 ;
     RECT  3.089 121.536 3.233 122.52 ;
     RECT  3.161 57.024 3.269 57.384 ;
     RECT  2.801 52.08 3.305 53.544 ;
     RECT  2.704 92.352 3.305 95.208 ;
     RECT  2.704 96.24 3.305 97.368 ;
     RECT  2.873 32.976 3.341 34.2 ;
     RECT  3.305 92.352 3.341 94.056 ;
     RECT  3.125 110.784 3.377 110.808 ;
     RECT  2.801 123.696 3.395 123.72 ;
     RECT  2.765 69.312 3.413 69.528 ;
     RECT  2.837 100.8 3.413 104.904 ;
     RECT  3.233 121.536 3.413 121.992 ;
     RECT  2.909 50.112 3.443 50.568 ;
     RECT  3.197 113.616 3.443 114.84 ;
     RECT  3.413 121.536 3.443 121.56 ;
     RECT  2.729 4.512 3.529 4.536 ;
     RECT  2.704 6 3.532 6.072 ;
     RECT  3.125 28.848 3.539 30.6 ;
     RECT  3.269 57.024 3.539 57.048 ;
     RECT  3.089 120.48 3.539 120.504 ;
     RECT  2.765 70.656 3.565 71.832 ;
     RECT  3.413 101.712 3.565 104.904 ;
     RECT  3.565 103.104 3.629 104.904 ;
     RECT  3.305 52.08 3.665 53.4 ;
     RECT  2.801 64.992 3.665 65.016 ;
     RECT  2.765 58.512 3.676 59.256 ;
     RECT  3.197 78.096 3.683 83.16 ;
     RECT  3.305 95.136 3.685 95.208 ;
     RECT  3.341 93.456 3.731 94.056 ;
     RECT  3.233 16.56 3.733 16.584 ;
     RECT  3.341 32.976 3.733 33.768 ;
     RECT  3.685 95.136 3.733 95.256 ;
     RECT  3.305 96.24 3.733 96.888 ;
     RECT  2.704 24.576 3.74 24.984 ;
     RECT  3.089 90.048 3.769 91.08 ;
     RECT  3.341 92.352 3.769 92.376 ;
     RECT  3.017 60.384 3.773 63.144 ;
     RECT  3.539 29.904 3.779 30.6 ;
     RECT  2.704 35.808 3.779 35.832 ;
     RECT  2.704 20.976 3.781 21.576 ;
     RECT  3.74 23.76 3.781 24.984 ;
     RECT  2.801 27.84 3.781 27.864 ;
     RECT  3.197 76.56 3.781 76.968 ;
     RECT  3.781 20.976 3.805 22.104 ;
     RECT  2.765 68.208 3.805 68.232 ;
     RECT  3.539 28.848 3.82 28.872 ;
     RECT  3.781 23.76 3.827 26.28 ;
     RECT  3.781 27.312 3.827 27.864 ;
     RECT  3.733 95.136 3.827 96.888 ;
     RECT  2.704 73.92 3.853 74.664 ;
     RECT  2.765 41.76 3.877 41.784 ;
     RECT  2.801 84.768 3.877 86.664 ;
     RECT  2.765 106.992 3.877 107.016 ;
     RECT  3.733 18.816 3.881 18.84 ;
     RECT  3.827 25.056 3.881 26.28 ;
     RECT  3.017 125.04 3.881 125.064 ;
     RECT  3.805 38.784 3.889 38.808 ;
     RECT  2.837 99.696 3.913 99.72 ;
     RECT  3.733 32.352 3.923 33.768 ;
     RECT  3.877 40.992 3.925 41.784 ;
     RECT  3.443 50.16 3.925 50.568 ;
     RECT  3.877 51.888 3.925 51.912 ;
     RECT  3.413 69.504 3.925 69.528 ;
     RECT  3.805 20.592 3.949 22.104 ;
     RECT  3.829 37.44 3.949 37.464 ;
     RECT  3.805 68.208 3.949 68.28 ;
     RECT  3.877 88.32 3.949 88.392 ;
     RECT  3.877 106.992 3.949 107.304 ;
     RECT  3.779 30.24 3.953 30.6 ;
     RECT  3.923 32.352 3.953 32.904 ;
     RECT  3.884 15.456 3.971 15.48 ;
     RECT  3.925 40.992 3.971 43.368 ;
     RECT  3.925 69.504 3.971 70.296 ;
     RECT  3.731 94.032 3.971 94.056 ;
     RECT  2.909 117.216 3.971 117.24 ;
     RECT  3.853 73.92 3.973 74.616 ;
     RECT  3.733 16.56 3.985 17.064 ;
     RECT  3.949 67.296 4.019 68.28 ;
     RECT  3.973 73.488 4.019 74.616 ;
     RECT  3.443 113.616 4.025 114.552 ;
     RECT  3.949 20.592 4.061 22.152 ;
     RECT  3.971 70.032 4.061 70.296 ;
     RECT  4.019 73.488 4.061 73.512 ;
     RECT  3.925 7.824 4.089 7.848 ;
     RECT  3.925 13.824 4.097 13.848 ;
     RECT  3.773 61.008 4.124 63.144 ;
     RECT  4.061 22.128 4.129 22.152 ;
     RECT  4.021 10.032 4.165 10.056 ;
     RECT  3.913 99.696 4.172 100.68 ;
     RECT  3.781 76.464 4.201 76.968 ;
     RECT  4.172 99.168 4.22 100.68 ;
     RECT  4.165 10.032 4.237 11.016 ;
     RECT  4.021 112.32 4.309 112.344 ;
     RECT  4.025 113.616 4.309 113.976 ;
     RECT  4.237 10.032 4.345 11.4 ;
     RECT  3.98 48.624 4.345 48.648 ;
     RECT  3.827 95.136 4.345 95.208 ;
     RECT  3.949 106.464 4.345 107.304 ;
     RECT  3.985 108.288 4.345 108.312 ;
     RECT  3.877 84.768 4.381 86.76 ;
     RECT  4.061 20.592 4.405 21.144 ;
     RECT  4.021 46.176 4.412 46.248 ;
     RECT  4.345 48.48 4.412 49.032 ;
     RECT  3.665 52.992 4.412 53.4 ;
     RECT  4.412 48.384 4.453 49.032 ;
     RECT  3.925 50.16 4.453 51.912 ;
     RECT  4.412 52.992 4.453 53.544 ;
     RECT  4.381 84.336 4.453 86.76 ;
     RECT  3.949 88.32 4.453 88.92 ;
     RECT  3.985 109.968 4.453 109.992 ;
     RECT  3.827 23.76 4.481 23.976 ;
     RECT  4.201 76.368 4.489 76.968 ;
     RECT  3.683 78.096 4.489 80.28 ;
     RECT  4.093 116.208 4.489 116.232 ;
     RECT  4.129 22.128 4.501 22.2 ;
     RECT  4.481 23.376 4.501 23.976 ;
     RECT  4.453 5.712 4.525 5.736 ;
     RECT  3.887 12.48 4.525 12.504 ;
     RECT  4.345 106.464 4.525 108.312 ;
     RECT  4.124 61.008 4.549 63.816 ;
     RECT  4.22 98.208 4.549 100.68 ;
     RECT  3.565 101.712 4.549 101.736 ;
     RECT  3.629 103.104 4.549 104.328 ;
     RECT  4.453 109.968 4.549 110.568 ;
     RECT  4.309 112.08 4.549 113.976 ;
     RECT  4.412 46.176 4.556 46.776 ;
     RECT  4.489 76.368 4.561 80.28 ;
     RECT  4.556 122.064 4.597 122.088 ;
     RECT  4.525 12.48 4.645 12.792 ;
     RECT  4.061 70.272 4.652 70.296 ;
     RECT  3.565 71.328 4.652 71.832 ;
     RECT  4.525 106.032 4.669 108.312 ;
     RECT  3.949 37.008 4.705 37.464 ;
     RECT  3.985 38.736 4.705 38.76 ;
     RECT  4.556 46.176 4.705 47.304 ;
     RECT  3.877 66.24 4.705 66.264 ;
     RECT  3.233 44.976 4.741 45.144 ;
     RECT  3.676 58.512 4.741 58.872 ;
     RECT  3.769 90.048 4.741 92.376 ;
     RECT  3.985 16.56 4.748 17.688 ;
     RECT  4.741 90.048 4.777 92.424 ;
     RECT  2.909 118.272 4.837 118.296 ;
     RECT  4.345 9.072 4.844 11.4 ;
     RECT  4.837 117.984 4.921 118.296 ;
     RECT  4.748 16.416 4.957 17.688 ;
     RECT  3.827 27.312 4.981 27.336 ;
     RECT  3.953 30.24 4.981 30.36 ;
     RECT  3.953 32.88 4.981 32.904 ;
     RECT  4.453 34.224 4.981 34.248 ;
     RECT  4.633 57.024 4.981 57.48 ;
     RECT  4.741 58.512 4.981 59.16 ;
     RECT  4.705 66 4.981 66.264 ;
     RECT  3.971 41.136 5.065 41.16 ;
     RECT  4.525 5.616 5.108 5.736 ;
     RECT  3.769 6.816 5.108 6.84 ;
     RECT  4.844 8.4 5.108 11.4 ;
     RECT  4.645 12.48 5.108 13.08 ;
     RECT  4.489 14.16 5.108 15.432 ;
     RECT  4.957 16.416 5.108 18.168 ;
     RECT  4.405 19.248 5.108 21.144 ;
     RECT  4.501 22.128 5.108 23.976 ;
     RECT  3.881 25.056 5.108 25.896 ;
     RECT  4.981 27.216 5.108 27.336 ;
     RECT  4.597 29.04 5.108 29.064 ;
     RECT  4.981 30.048 5.108 30.36 ;
     RECT  4.381 31.536 5.108 31.56 ;
     RECT  4.981 32.88 5.108 34.248 ;
     RECT  4.705 37.008 5.108 38.76 ;
     RECT  2.873 39.888 5.108 39.912 ;
     RECT  5.065 41.136 5.108 41.208 ;
     RECT  3.971 42.576 5.108 43.368 ;
     RECT  4.741 44.544 5.108 45.144 ;
     RECT  4.705 46.128 5.108 47.304 ;
     RECT  4.453 48.384 5.108 51.912 ;
     RECT  4.453 52.992 5.108 54.168 ;
     RECT  4.981 57.024 5.108 59.16 ;
     RECT  4.549 61.008 5.108 63.864 ;
     RECT  4.165 64.848 5.108 64.872 ;
     RECT  4.981 65.952 5.108 66.264 ;
     RECT  4.019 67.296 5.108 68.232 ;
     RECT  4.981 69.216 5.108 69.24 ;
     RECT  4.652 70.272 5.108 71.832 ;
     RECT  4.019 74.592 5.108 74.616 ;
     RECT  4.561 75.648 5.108 80.28 ;
     RECT  3.683 81.456 5.108 83.16 ;
     RECT  4.453 84.336 5.108 88.92 ;
     RECT  4.777 90.048 5.108 92.712 ;
     RECT  4.345 94.656 5.108 95.208 ;
     RECT  3.827 96.288 5.108 96.84 ;
     RECT  4.549 98.208 5.108 101.736 ;
     RECT  4.549 102.816 5.108 104.328 ;
     RECT  4.669 105.408 5.108 108.312 ;
     RECT  4.549 109.968 5.108 113.976 ;
     RECT  4.489 116.16 5.108 116.232 ;
     RECT  4.921 117.984 5.108 118.584 ;
     RECT  4.981 120.192 5.108 120.216 ;
     RECT  4.597 121.392 5.108 122.088 ;
     RECT  4.417 124.224 5.108 124.248 ;
     RECT  4.517 126 5.108 126.024 ;
     RECT  4.489 127.008 5.108 127.032 ;
     RECT  5.108 2.148 5.212 129.612 ;
     RECT  5.212 2.418 5.404 129.342 ;
     RECT  5.404 29.376 5.465 31.368 ;
     RECT  5.404 84.576 5.501 86.76 ;
     RECT  5.404 108.528 5.555 113.976 ;
     RECT  5.404 121.92 5.555 122.088 ;
     RECT  5.404 124.272 5.555 124.392 ;
     RECT  5.404 6.816 5.573 8.568 ;
     RECT  5.404 101.424 5.573 102.072 ;
     RECT  5.555 110.448 5.596 113.976 ;
     RECT  5.404 53.28 5.603 57.288 ;
     RECT  5.404 14.736 5.699 17.64 ;
     RECT  5.404 61.536 5.699 62.76 ;
     RECT  5.404 75.936 5.699 83.208 ;
     RECT  5.404 93.744 5.699 96.312 ;
     RECT  5.404 63.792 5.717 72.936 ;
     RECT  5.404 88.896 5.717 92.712 ;
     RECT  5.501 84.576 5.725 86.664 ;
     RECT  5.404 115.056 5.747 115.608 ;
     RECT  5.404 59.712 5.753 60.408 ;
     RECT  5.699 94.032 5.753 96.312 ;
     RECT  5.596 111.792 5.753 113.976 ;
     RECT  5.717 63.792 5.789 70.68 ;
     RECT  5.717 88.896 5.789 89.496 ;
     RECT  5.573 101.712 5.789 102.072 ;
     RECT  5.699 15.168 5.825 17.64 ;
     RECT  5.789 63.792 5.825 70.632 ;
     RECT  5.717 72.144 5.825 72.936 ;
     RECT  5.725 84.576 5.825 86.04 ;
     RECT  5.404 40.8 5.861 43.32 ;
     RECT  5.404 116.592 5.861 116.808 ;
     RECT  5.404 125.808 5.861 127.08 ;
     RECT  5.825 65.328 5.933 70.632 ;
     RECT  5.861 127.056 5.933 127.08 ;
     RECT  5.404 25.824 5.939 27.72 ;
     RECT  5.861 40.896 5.939 43.32 ;
     RECT  5.404 44.4 5.939 45.144 ;
     RECT  5.825 72.48 5.939 72.936 ;
     RECT  5.404 74.016 5.939 74.328 ;
     RECT  5.699 75.936 5.939 80.952 ;
     RECT  5.404 98.016 5.939 99.048 ;
     RECT  5.861 125.808 5.939 125.832 ;
     RECT  5.789 101.856 5.941 102.072 ;
     RECT  5.404 20.016 5.987 21.672 ;
     RECT  5.404 119.088 5.987 119.16 ;
     RECT  5.555 122.064 5.987 122.088 ;
     RECT  5.404 12.528 6.005 13.128 ;
     RECT  5.555 108.528 6.041 109.128 ;
     RECT  5.747 115.584 6.041 115.608 ;
     RECT  5.861 116.592 6.041 116.616 ;
     RECT  5.404 23.52 6.083 23.544 ;
     RECT  5.699 61.536 6.083 61.56 ;
     RECT  5.699 62.592 6.083 62.616 ;
     RECT  5.825 15.168 6.113 17.064 ;
     RECT  5.987 20.016 6.113 20.088 ;
     RECT  5.939 45.12 6.113 45.144 ;
     RECT  5.825 63.792 6.149 64.056 ;
     RECT  5.465 30.384 6.179 31.368 ;
     RECT  5.939 40.896 6.179 40.92 ;
     RECT  5.404 50.112 6.185 50.856 ;
     RECT  5.465 29.376 6.275 29.4 ;
     RECT  5.939 74.016 6.293 74.04 ;
     RECT  5.753 96.288 6.293 96.312 ;
     RECT  5.939 98.016 6.293 98.616 ;
     RECT  5.555 124.272 6.293 124.296 ;
     RECT  5.603 53.28 6.323 55.368 ;
     RECT  5.933 65.328 6.323 70.44 ;
     RECT  5.717 90.576 6.323 92.712 ;
     RECT  6.113 20.064 6.329 20.088 ;
     RECT  5.753 60.384 6.329 60.408 ;
     RECT  5.573 7.392 6.337 8.568 ;
     RECT  5.404 46.224 6.365 46.824 ;
     RECT  6.323 90.576 6.365 91.752 ;
     RECT  5.404 37.68 6.397 37.896 ;
     RECT  5.699 82.032 6.397 83.208 ;
     RECT  5.404 10.08 6.428 10.488 ;
     RECT  5.404 48.432 6.428 48.504 ;
     RECT  6.428 47.856 6.469 48.504 ;
     RECT  6.185 50.496 6.469 50.856 ;
     RECT  5.404 51.888 6.469 51.912 ;
     RECT  5.404 105.792 6.469 107.304 ;
     RECT  6.179 30.48 6.473 31.368 ;
     RECT  6.428 9.936 6.515 10.488 ;
     RECT  6.469 47.856 6.515 48.984 ;
     RECT  6.113 15.168 6.545 15.384 ;
     RECT  6.469 105.792 6.545 108.264 ;
     RECT  5.404 35.328 6.572 35.352 ;
     RECT  5.789 89.472 6.581 89.496 ;
     RECT  5.603 56.736 6.613 57.288 ;
     RECT  6.473 30.48 6.617 30.6 ;
     RECT  6.572 35.328 6.653 35.64 ;
     RECT  5.939 42.192 6.653 43.32 ;
     RECT  6.149 63.792 6.653 63.816 ;
     RECT  6.323 65.328 6.653 68.28 ;
     RECT  5.753 94.032 6.653 95.112 ;
     RECT  6.653 35.616 6.659 35.64 ;
     RECT  6.397 37.68 6.659 38.04 ;
     RECT  6.653 42.192 6.659 42.744 ;
     RECT  6.397 82.032 6.659 83.688 ;
     RECT  6.572 97.44 6.659 97.464 ;
     RECT  6.005 13.104 6.685 13.128 ;
     RECT  5.404 103.056 6.685 104.28 ;
     RECT  6.515 48.48 6.689 48.984 ;
     RECT  6.323 53.28 6.689 54.072 ;
     RECT  5.825 84.96 6.689 86.04 ;
     RECT  6.653 66 6.725 68.28 ;
     RECT  6.653 94.032 6.725 94.968 ;
     RECT  5.596 110.448 6.757 110.472 ;
     RECT  6.337 7.92 6.761 8.568 ;
     RECT  6.613 39.888 6.761 39.912 ;
     RECT  6.613 99.744 6.761 99.768 ;
     RECT  6.545 107.04 6.761 108.264 ;
     RECT  6.685 13.104 6.803 14.04 ;
     RECT  6.113 16.512 6.803 17.064 ;
     RECT  6.761 108.192 6.803 108.216 ;
     RECT  5.753 111.792 6.803 113.448 ;
     RECT  6.659 82.08 6.805 83.688 ;
     RECT  6.803 16.992 6.829 17.064 ;
     RECT  5.404 18.768 6.829 18.792 ;
     RECT  5.987 21.456 6.829 21.672 ;
     RECT  6.365 90.576 6.829 91.224 ;
     RECT  6.803 112.656 6.829 113.448 ;
     RECT  6.613 56.736 6.833 57.48 ;
     RECT  6.545 15.36 6.844 15.384 ;
     RECT  6.757 109.392 6.844 110.76 ;
     RECT  5.939 25.824 6.901 26.856 ;
     RECT  6.685 103.056 6.901 104.52 ;
     RECT  6.853 123.648 6.901 123.672 ;
     RECT  5.939 72.48 6.908 72.6 ;
     RECT  5.941 101.856 6.908 101.88 ;
     RECT  6.901 103.056 6.908 105.432 ;
     RECT  6.725 94.032 7.117 94.056 ;
     RECT  6.829 90.48 7.153 91.224 ;
     RECT  7.117 116.928 7.189 116.952 ;
     RECT  6.803 13.104 7.196 13.128 ;
     RECT  6.515 10.464 7.237 10.488 ;
     RECT  6.323 69.456 7.244 70.44 ;
     RECT  6.908 71.616 7.244 72.6 ;
     RECT  6.829 21.456 7.261 21.96 ;
     RECT  6.86 23.136 7.261 23.16 ;
     RECT  6.793 43.728 7.333 44.088 ;
     RECT  6.725 67.344 7.333 68.28 ;
     RECT  7.333 67.344 7.369 68.424 ;
     RECT  7.244 69.456 7.369 72.6 ;
     RECT  7.153 89.664 7.405 91.224 ;
     RECT  6.833 56.736 7.429 57.096 ;
     RECT  6.929 99.168 7.429 99.72 ;
     RECT  7.429 98.592 7.441 99.72 ;
     RECT  6.908 101.856 7.441 105.432 ;
     RECT  6.469 50.496 7.477 51.912 ;
     RECT  7.117 93.504 7.585 94.056 ;
     RECT  7.237 14.208 7.649 14.232 ;
     RECT  7.148 114.528 7.657 114.552 ;
     RECT  7.628 20.208 7.669 20.232 ;
     RECT  7.261 21.456 7.669 23.16 ;
     RECT  6.901 25.104 7.669 26.856 ;
     RECT  6.689 53.28 7.669 53.448 ;
     RECT  6.761 107.04 7.669 107.208 ;
     RECT  6.901 121.392 7.669 121.416 ;
     RECT  6.901 123.12 7.669 123.672 ;
     RECT  6.757 125.376 7.669 125.4 ;
     RECT  5.939 76.752 7.765 80.952 ;
     RECT  6.805 82.08 7.765 84.216 ;
     RECT  6.853 127.104 7.801 127.128 ;
     RECT  7.285 5.856 7.808 5.88 ;
     RECT  6.761 7.92 7.808 7.944 ;
     RECT  7.117 9.408 7.808 9.432 ;
     RECT  7.237 10.464 7.808 11.016 ;
     RECT  7.196 12.912 7.808 13.128 ;
     RECT  7.649 14.208 7.808 15.096 ;
     RECT  6.829 16.992 7.808 18.792 ;
     RECT  7.669 20.208 7.808 26.856 ;
     RECT  6.617 30.576 7.808 30.6 ;
     RECT  7.045 33.984 7.808 34.008 ;
     RECT  6.908 37.2 7.808 37.224 ;
     RECT  7.585 38.688 7.808 38.712 ;
     RECT  6.949 40.464 7.808 40.488 ;
     RECT  6.659 42.72 7.808 42.744 ;
     RECT  7.333 43.728 7.808 44.472 ;
     RECT  6.685 46.128 7.808 46.152 ;
     RECT  6.757 47.232 7.808 47.352 ;
     RECT  6.689 48.48 7.808 48.504 ;
     RECT  7.477 50.496 7.808 52.104 ;
     RECT  7.669 53.28 7.808 53.592 ;
     RECT  7.477 54.72 7.808 54.744 ;
     RECT  7.429 56.352 7.808 57.096 ;
     RECT  6.829 58.656 7.808 58.68 ;
     RECT  7.153 60.816 7.808 60.84 ;
     RECT  7.649 63.216 7.808 63.24 ;
     RECT  7.405 64.896 7.808 64.92 ;
     RECT  6.725 66 7.808 66.36 ;
     RECT  7.369 67.344 7.808 72.6 ;
     RECT  7.151 74.544 7.808 74.568 ;
     RECT  7.765 76.752 7.808 84.216 ;
     RECT  6.689 85.248 7.808 86.04 ;
     RECT  6.649 87.408 7.808 87.432 ;
     RECT  7.333 88.608 7.808 88.632 ;
     RECT  7.405 89.664 7.808 91.896 ;
     RECT  7.585 93.312 7.808 94.056 ;
     RECT  7.669 95.712 7.808 96.6 ;
     RECT  7.441 97.728 7.808 99.72 ;
     RECT  7.441 101.328 7.808 105.432 ;
     RECT  7.669 106.464 7.808 107.208 ;
     RECT  6.844 109.392 7.808 109.416 ;
     RECT  6.844 110.736 7.808 110.76 ;
     RECT  6.829 112.656 7.808 113.544 ;
     RECT  7.657 114.528 7.808 115.224 ;
     RECT  7.189 116.592 7.808 116.952 ;
     RECT  5.404 117.936 7.808 117.96 ;
     RECT  5.987 119.136 7.808 119.16 ;
     RECT  7.669 121.392 7.808 125.4 ;
     RECT  7.801 126.72 7.808 127.128 ;
     RECT  7.808 2.148 7.912 129.612 ;
     RECT  7.912 2.418 8.104 129.342 ;
     RECT  8.104 67.344 8.165 67.368 ;
     RECT  8.104 120.048 8.165 120.264 ;
     RECT  8.104 20.976 8.201 21.48 ;
     RECT  8.104 95.712 8.201 95.736 ;
     RECT  8.104 24.672 8.237 24.744 ;
     RECT  8.104 58.704 8.243 58.728 ;
     RECT  8.104 60.816 8.243 62.472 ;
     RECT  8.104 73.92 8.243 73.944 ;
     RECT  8.104 93.312 8.243 93.336 ;
     RECT  8.104 101.328 8.243 101.88 ;
     RECT  8.104 109.968 8.243 109.992 ;
     RECT  8.104 115.2 8.243 115.224 ;
     RECT  8.165 120.048 8.243 120.072 ;
     RECT  8.104 126.72 8.243 126.744 ;
     RECT  8.104 94.368 8.245 94.392 ;
     RECT  8.243 101.712 8.284 101.88 ;
     RECT  8.104 34.512 8.291 34.92 ;
     RECT  8.104 81.456 8.291 81.48 ;
     RECT  8.104 84.336 8.291 84.36 ;
     RECT  8.104 91.872 8.291 91.896 ;
     RECT  8.104 103.2 8.301 103.224 ;
     RECT  8.104 121.92 8.309 121.944 ;
     RECT  8.104 29.76 8.381 32.472 ;
     RECT  8.104 57.072 8.381 57.096 ;
     RECT  8.104 106.8 8.381 107.064 ;
     RECT  8.104 124.896 8.381 125.736 ;
     RECT  8.237 24.72 8.387 24.744 ;
     RECT  8.104 25.872 8.387 26.664 ;
     RECT  8.104 28.368 8.387 28.392 ;
     RECT  8.381 29.76 8.387 31.8 ;
     RECT  8.104 36.432 8.387 36.456 ;
     RECT  8.104 38.688 8.387 38.712 ;
     RECT  8.104 43.488 8.387 43.512 ;
     RECT  8.104 48.48 8.387 48.504 ;
     RECT  8.284 101.856 8.417 101.88 ;
     RECT  8.104 76.128 8.483 76.152 ;
     RECT  8.104 79.056 8.483 79.08 ;
     RECT  8.104 66 8.489 66.072 ;
     RECT  8.381 107.04 8.525 107.064 ;
     RECT  8.489 66 8.633 66.024 ;
     RECT  8.104 104.64 9.209 104.664 ;
     RECT  8.201 21.456 10.508 21.48 ;
     RECT  8.387 31.776 10.508 31.8 ;
     RECT  8.104 50.832 10.508 50.856 ;
     RECT  10.508 2.148 10.612 129.612 ;
     RECT  10.612 2.418 10.804 129.342 ;
     RECT  10.804 108.72 10.829 108.744 ;
     RECT  10.804 21.456 13.208 21.48 ;
     RECT  10.804 31.776 13.208 31.8 ;
     RECT  10.804 50.832 13.208 50.856 ;
     RECT  13.208 2.148 13.312 129.612 ;
     RECT  13.312 2.418 13.504 129.342 ;
     RECT  13.504 21.456 15.908 21.48 ;
     RECT  13.504 31.776 15.908 31.8 ;
     RECT  13.504 50.832 15.908 50.856 ;
     RECT  15.908 2.148 16.012 129.612 ;
     RECT  16.012 2.418 16.204 129.342 ;
     RECT  5.797 131.616 18.209 131.64 ;
     RECT  16.204 21.456 18.608 21.48 ;
     RECT  16.204 31.776 18.608 31.8 ;
     RECT  16.204 50.832 18.608 50.856 ;
     RECT  18.608 2.148 18.712 129.612 ;
     RECT  18.712 2.418 18.904 129.342 ;
     RECT  18.904 21.456 21.308 21.48 ;
     RECT  18.904 31.776 21.308 31.8 ;
     RECT  18.904 50.832 21.308 50.856 ;
     RECT  21.308 2.148 21.412 129.612 ;
     RECT  21.412 2.418 21.604 129.342 ;
     RECT  21.604 21.456 24.008 21.48 ;
     RECT  21.604 31.776 24.008 31.8 ;
     RECT  21.604 50.832 24.008 50.856 ;
     RECT  24.008 2.148 24.112 129.612 ;
     RECT  24.112 2.418 24.304 129.342 ;
     RECT  24.304 21.456 26.708 21.48 ;
     RECT  24.304 31.776 26.708 31.8 ;
     RECT  24.304 50.832 26.708 50.856 ;
     RECT  26.708 2.148 26.812 129.612 ;
     RECT  26.812 2.418 27.004 129.342 ;
     RECT  27.004 21.456 29.408 21.48 ;
     RECT  27.004 31.776 29.408 31.8 ;
     RECT  27.004 50.832 29.408 50.856 ;
     RECT  29.408 2.148 29.512 129.612 ;
     RECT  29.512 2.418 29.704 129.342 ;
     RECT  30.805 26.4 30.917 26.424 ;
     RECT  30.805 88.176 31.061 88.2 ;
     RECT  29.704 21.456 31.921 21.48 ;
     RECT  31.921 88.896 32.029 88.92 ;
     RECT  31.921 21.456 32.108 21.72 ;
     RECT  29.704 31.776 32.108 31.8 ;
     RECT  31.993 39.264 32.108 39.288 ;
     RECT  32.029 41.664 32.108 41.688 ;
     RECT  31.885 48.432 32.108 48.456 ;
     RECT  29.704 50.832 32.108 50.856 ;
     RECT  31.885 63.264 32.108 63.288 ;
     RECT  31.669 74.064 32.108 74.088 ;
     RECT  31.849 83.76 32.108 83.784 ;
     RECT  32.029 88.128 32.108 88.92 ;
     RECT  31.921 118.032 32.108 118.056 ;
     RECT  31.849 119.952 32.108 119.976 ;
     RECT  32.065 124.272 32.108 124.296 ;
     RECT  32.108 2.148 32.212 129.612 ;
     RECT  32.212 2.418 32.404 129.342 ;
     RECT  32.404 98.448 32.531 98.616 ;
     RECT  32.531 98.592 32.572 98.616 ;
     RECT  32.404 88.08 32.609 88.92 ;
     RECT  32.404 102.72 32.861 103.08 ;
     RECT  32.861 102.72 32.897 102.984 ;
     RECT  32.404 77.424 32.933 78.072 ;
     RECT  32.404 28.224 33.005 28.248 ;
     RECT  32.404 57.024 33.005 57.048 ;
     RECT  32.404 36.48 33.113 39.288 ;
     RECT  32.404 48.432 33.113 48.456 ;
     RECT  32.404 74.064 33.113 74.664 ;
     RECT  32.404 83.76 33.113 83.784 ;
     RECT  32.404 107.856 33.113 108.648 ;
     RECT  32.404 17.616 33.149 18.264 ;
     RECT  32.404 63.024 33.149 64.056 ;
     RECT  33.149 64.032 33.293 64.056 ;
     RECT  32.609 88.896 33.293 88.92 ;
     RECT  32.404 31.68 33.329 31.8 ;
     RECT  32.404 44.88 33.365 44.904 ;
     RECT  32.404 67.536 33.433 68.088 ;
     RECT  32.404 69.456 33.433 69.48 ;
     RECT  33.113 36.48 33.437 38.472 ;
     RECT  32.404 50.832 33.437 50.904 ;
     RECT  32.404 91.584 33.473 91.656 ;
     RECT  33.433 67.536 33.509 69.48 ;
     RECT  32.404 65.952 33.613 65.976 ;
     RECT  33.437 37.584 33.617 38.472 ;
     RECT  33.329 31.728 33.653 31.8 ;
     RECT  33.437 50.832 33.653 50.856 ;
     RECT  32.404 52.56 33.653 52.776 ;
     RECT  33.509 68.928 33.653 69.48 ;
     RECT  33.473 91.632 33.653 91.656 ;
     RECT  32.404 124.032 33.653 124.728 ;
     RECT  32.404 24.912 33.685 24.936 ;
     RECT  33.149 63.024 33.689 63.048 ;
     RECT  33.653 52.752 33.761 52.776 ;
     RECT  32.404 70.656 33.761 70.68 ;
     RECT  33.685 24.912 33.829 24.984 ;
     RECT  33.541 90.528 33.869 90.552 ;
     RECT  33.437 36.48 33.905 36.504 ;
     RECT  33.901 8.64 33.973 8.664 ;
     RECT  32.404 126.576 33.973 126.6 ;
     RECT  33.617 37.584 33.977 37.608 ;
     RECT  33.973 50.688 34.153 50.712 ;
     RECT  33.973 98.88 34.153 98.904 ;
     RECT  33.433 107.136 34.153 107.16 ;
     RECT  33.973 8.112 34.189 8.664 ;
     RECT  33.865 11.856 34.189 11.88 ;
     RECT  32.404 12.864 34.189 13.08 ;
     RECT  32.404 14.88 34.189 14.904 ;
     RECT  33.149 18.24 34.189 18.264 ;
     RECT  32.404 21.456 34.189 21.72 ;
     RECT  33.829 24.624 34.189 24.984 ;
     RECT  33.577 26.4 34.189 26.424 ;
     RECT  33.653 31.776 34.189 31.8 ;
     RECT  32.404 35.424 34.189 35.496 ;
     RECT  32.404 42.192 34.189 42.216 ;
     RECT  34.153 50.544 34.189 50.712 ;
     RECT  32.404 58.08 34.189 58.68 ;
     RECT  33.613 65.808 34.189 65.976 ;
     RECT  33.509 67.536 34.189 67.56 ;
     RECT  32.404 72.576 34.189 72.6 ;
     RECT  33.113 74.352 34.189 74.664 ;
     RECT  32.933 78.048 34.189 78.072 ;
     RECT  32.404 79.152 34.189 79.176 ;
     RECT  32.404 81.024 34.189 81.048 ;
     RECT  33.577 86.592 34.189 86.616 ;
     RECT  32.404 94.416 34.189 94.68 ;
     RECT  32.404 95.856 34.189 96.984 ;
     RECT  34.153 98.4 34.189 98.904 ;
     RECT  32.404 101.424 34.189 101.448 ;
     RECT  32.897 102.96 34.189 102.984 ;
     RECT  34.153 106.32 34.189 107.16 ;
     RECT  34.081 111.024 34.189 111.048 ;
     RECT  32.404 112.656 34.189 114.456 ;
     RECT  32.404 116.16 34.189 116.184 ;
     RECT  32.404 118.944 34.189 118.968 ;
     RECT  34.189 64.752 34.19 67.56 ;
     RECT  34.189 8.112 34.225 9.768 ;
     RECT  34.189 11.856 34.225 18.984 ;
     RECT  34.189 19.968 34.225 26.424 ;
     RECT  34.189 39.696 34.225 40.2 ;
     RECT  34.189 41.616 34.225 42.312 ;
     RECT  34.189 61.056 34.225 61.704 ;
     RECT  34.189 70.896 34.225 70.92 ;
     RECT  33.973 126.576 34.225 126.744 ;
     RECT  34.081 4.752 34.333 4.776 ;
     RECT  34.225 126.576 34.333 126.888 ;
     RECT  33.793 6.048 34.405 6.072 ;
     RECT  33.653 124.32 34.477 124.728 ;
     RECT  34.225 8.112 34.549 9.96 ;
     RECT  34.333 4.56 34.621 4.776 ;
     RECT  34.405 6.048 34.621 6.216 ;
     RECT  34.225 39.696 34.657 42.312 ;
     RECT  34.189 43.728 34.657 44.568 ;
     RECT  34.189 81.024 34.657 81.912 ;
     RECT  34.189 86.112 34.657 86.616 ;
     RECT  34.513 38.688 34.693 38.712 ;
     RECT  34.189 47.952 34.693 48.6 ;
     RECT  34.189 49.872 34.693 50.712 ;
     RECT  34.225 61.056 34.693 61.848 ;
     RECT  34.189 82.896 34.693 82.92 ;
     RECT  34.621 4.56 34.729 6.216 ;
     RECT  34.549 8.112 34.729 10.584 ;
     RECT  34.225 11.856 34.729 26.424 ;
     RECT  34.189 28.848 34.729 29.688 ;
     RECT  34.693 47.616 34.729 50.712 ;
     RECT  34.189 54.72 34.729 55.416 ;
     RECT  34.189 57.792 34.729 59.784 ;
     RECT  34.693 61.056 34.729 62.376 ;
     RECT  34.189 72.576 34.729 72.696 ;
     RECT  34.189 73.68 34.729 76.44 ;
     RECT  34.189 77.712 34.729 79.176 ;
     RECT  34.657 85.296 34.729 86.616 ;
     RECT  34.189 92.592 34.729 98.904 ;
     RECT  34.189 100.368 34.729 107.16 ;
     RECT  33.113 108.624 34.729 108.648 ;
     RECT  34.189 118.8 34.729 118.968 ;
     RECT  34.225 122.208 34.729 122.232 ;
     RECT  34.477 124.32 34.729 125.592 ;
     RECT  34.333 126.576 34.729 127.416 ;
     RECT  34.729 8.112 34.765 26.424 ;
     RECT  34.189 27.552 34.765 27.576 ;
     RECT  34.729 28.848 34.765 29.832 ;
     RECT  34.189 31.776 34.765 33.24 ;
     RECT  34.189 34.992 34.765 35.496 ;
     RECT  34.693 37.728 34.765 38.712 ;
     RECT  34.657 39.696 34.765 44.568 ;
     RECT  34.189 45.984 34.765 46.2 ;
     RECT  34.729 47.472 34.765 50.712 ;
     RECT  34.189 52.8 34.765 53.304 ;
     RECT  34.729 54.384 34.765 55.416 ;
     RECT  34.189 56.496 34.765 56.52 ;
     RECT  33.653 68.928 34.765 68.952 ;
     RECT  34.225 70.896 34.765 71.4 ;
     RECT  34.729 72.528 34.765 76.44 ;
     RECT  34.729 77.712 34.765 79.368 ;
     RECT  34.657 80.448 34.765 81.912 ;
     RECT  34.693 82.896 34.765 83.064 ;
     RECT  34.729 85.296 34.765 86.808 ;
     RECT  34.189 88.56 34.765 88.584 ;
     RECT  34.189 90 34.765 90.168 ;
     RECT  34.729 92.592 34.765 107.16 ;
     RECT  34.729 108.432 34.765 108.648 ;
     RECT  34.189 110.064 34.765 116.184 ;
     RECT  34.189 117.168 34.765 117.192 ;
     RECT  34.729 118.8 34.765 119.976 ;
     RECT  34.729 122.208 34.765 127.416 ;
     RECT  34.729 57.792 34.801 63.336 ;
     RECT  34.765 85.296 34.801 87.576 ;
     RECT  34.765 88.56 34.801 90.168 ;
     RECT  34.765 110.064 34.801 117.192 ;
     RECT  34.765 45.648 34.837 46.2 ;
     RECT  34.765 47.28 34.837 51.336 ;
     RECT  34.765 108.288 34.837 108.648 ;
     RECT  34.801 110.064 34.837 117.672 ;
     RECT  34.729 4.56 34.873 6.552 ;
     RECT  34.873 4.56 34.909 6.696 ;
     RECT  34.765 30.96 35.305 33.24 ;
     RECT  34.909 4.56 35.341 6.84 ;
     RECT  34.765 8.112 35.341 29.832 ;
     RECT  35.305 30.96 35.341 33.384 ;
     RECT  34.765 34.992 35.341 36.456 ;
     RECT  34.765 37.728 35.341 44.568 ;
     RECT  34.837 45.648 35.341 51.336 ;
     RECT  34.765 52.8 35.341 56.52 ;
     RECT  34.801 57.792 35.341 63.672 ;
     RECT  34.19 64.752 35.341 67.512 ;
     RECT  34.765 68.496 35.341 76.44 ;
     RECT  34.765 77.712 35.341 81.912 ;
     RECT  34.765 82.896 35.341 83.208 ;
     RECT  34.801 85.296 35.341 90.168 ;
     RECT  34.765 91.776 35.341 107.16 ;
     RECT  34.837 108.288 35.341 117.672 ;
     RECT  34.765 118.8 35.341 127.416 ;
     RECT  35.341 37.44 35.377 51.336 ;
     RECT  35.341 52.32 35.377 56.52 ;
     RECT  35.341 57.792 35.377 83.4 ;
     RECT  35.341 4.416 35.917 36.456 ;
     RECT  35.377 37.44 35.917 83.736 ;
     RECT  35.341 85.296 35.917 127.416 ;
     RECT  35.917 4.416 36.54 127.416 ;
     RECT  36.54 125.184 36.569 125.208 ;
    LAYER M5 ;
     RECT  2.4 2.137 2.52 2.151 ;
     RECT  5.1 2.137 5.22 2.151 ;
     RECT  7.8 2.137 7.92 2.151 ;
     RECT  10.5 2.137 10.62 2.151 ;
     RECT  13.2 2.137 13.32 2.151 ;
     RECT  15.9 2.137 16.02 2.151 ;
     RECT  18.6 2.137 18.72 2.151 ;
     RECT  21.3 2.137 21.42 2.151 ;
     RECT  24 2.137 24.12 2.151 ;
     RECT  26.7 2.137 26.82 2.151 ;
     RECT  29.4 2.137 29.52 2.151 ;
     RECT  32.1 2.137 32.22 2.151 ;
     RECT  2.4 2.151 2.712 4.501 ;
     RECT  5.1 2.151 5.412 5.605 ;
     RECT  7.8 2.151 8.112 5.845 ;
     RECT  2.4 4.501 3.48 6.035 ;
     RECT  4.896 5.605 5.412 6.805 ;
     RECT  3.936 6.805 5.412 7.381 ;
     RECT  3.936 7.381 6.312 7.859 ;
     RECT  7.296 5.845 8.112 7.955 ;
     RECT  4.032 7.859 6.312 8.147 ;
     RECT  7.392 7.955 8.112 9.397 ;
     RECT  7.248 9.397 8.112 9.925 ;
     RECT  4.032 8.147 5.412 10.067 ;
     RECT  6.48 9.925 8.112 10.499 ;
     RECT  4.128 10.067 5.412 12.469 ;
     RECT  7.248 10.499 8.112 14.005 ;
     RECT  3.936 12.469 5.412 14.725 ;
     RECT  3.936 14.725 5.688 15.443 ;
     RECT  5.1 15.443 5.688 15.925 ;
     RECT  6.768 14.005 8.112 15.925 ;
     RECT  3.936 15.443 3.96 16.405 ;
     RECT  5.1 15.925 8.112 16.405 ;
     RECT  3.936 16.405 8.112 16.595 ;
     RECT  4.8 16.595 8.112 17.651 ;
     RECT  3.744 17.029 3.768 18.851 ;
     RECT  4.992 17.651 8.112 19.237 ;
     RECT  4.416 19.237 8.112 21.155 ;
     RECT  4.8 21.155 8.112 21.971 ;
     RECT  3.792 21.541 3.816 22.165 ;
     RECT  4.8 21.971 6.072 22.165 ;
     RECT  3.792 22.165 6.072 23.125 ;
     RECT  7.68 21.971 8.112 23.125 ;
     RECT  3.792 23.125 8.112 23.411 ;
     RECT  4.992 23.411 8.112 23.987 ;
     RECT  5.1 23.987 8.112 24.709 ;
     RECT  3.792 23.411 3.816 25.045 ;
     RECT  5.1 24.709 8.376 25.045 ;
     RECT  3.792 25.045 8.376 25.139 ;
     RECT  3.792 25.139 6.168 25.907 ;
     RECT  4.992 25.907 6.168 26.101 ;
     RECT  7.8 25.139 8.376 26.101 ;
     RECT  4.992 26.101 8.376 26.867 ;
     RECT  2.4 6.035 2.712 27.829 ;
     RECT  3.792 25.907 3.816 27.829 ;
     RECT  2.4 27.829 3.816 27.875 ;
     RECT  2.4 27.875 3.528 28.837 ;
     RECT  4.992 26.867 6.168 29.365 ;
     RECT  2.4 28.837 3.768 30.565 ;
     RECT  2.4 30.565 3.912 30.611 ;
     RECT  0.192 30.757 0.216 30.899 ;
     RECT  7.8 26.867 8.376 30.995 ;
     RECT  4.992 29.365 6.264 31.379 ;
     RECT  3.744 30.611 3.912 32.869 ;
     RECT  4.992 31.379 6.168 32.869 ;
     RECT  3.744 32.869 6.168 34.259 ;
     RECT  7.8 30.995 8.28 34.931 ;
     RECT  5.1 34.259 6.168 35.605 ;
     RECT  3.744 34.259 3.768 35.843 ;
     RECT  7.8 34.931 8.112 36.421 ;
     RECT  5.1 35.605 6.648 37.189 ;
     RECT  7.8 36.421 8.376 37.189 ;
     RECT  3.84 37.429 3.864 38.819 ;
     RECT  5.1 37.189 8.376 40.499 ;
     RECT  3.936 40.981 3.96 42.709 ;
     RECT  5.1 40.499 6.648 42.709 ;
     RECT  7.8 40.499 8.376 42.709 ;
     RECT  3.936 42.709 8.376 43.379 ;
     RECT  4.464 43.379 8.376 44.099 ;
     RECT  4.464 44.099 6.312 44.965 ;
     RECT  0.288 45.013 0.312 45.731 ;
     RECT  4.32 44.965 6.312 46.117 ;
     RECT  7.8 44.099 8.376 46.117 ;
     RECT  4.32 46.117 8.376 46.165 ;
     RECT  4.032 46.165 8.376 47.267 ;
     RECT  7.8 47.267 8.376 48.469 ;
     RECT  7.68 48.469 8.376 48.515 ;
     RECT  4.032 47.267 6.504 49.619 ;
     RECT  2.4 30.611 2.712 50.101 ;
     RECT  4.032 49.619 4.056 50.101 ;
     RECT  2.4 50.101 4.056 50.579 ;
     RECT  7.68 48.515 8.112 51.253 ;
     RECT  5.1 49.619 6.504 51.347 ;
     RECT  2.4 50.579 3.96 51.923 ;
     RECT  2.4 51.923 3.528 53.509 ;
     RECT  5.1 51.347 6.168 53.509 ;
     RECT  2.4 53.509 6.168 54.179 ;
     RECT  5.1 54.179 6.168 54.565 ;
     RECT  7.488 51.253 8.112 54.755 ;
     RECT  7.8 54.755 8.112 56.341 ;
     RECT  5.1 54.565 6.312 56.771 ;
     RECT  7.44 56.341 8.112 57.059 ;
     RECT  7.8 57.059 8.112 57.061 ;
     RECT  5.1 56.771 6.168 57.445 ;
     RECT  2.4 54.179 3.528 58.501 ;
     RECT  4.992 57.445 6.168 58.501 ;
     RECT  7.8 57.061 8.232 62.483 ;
     RECT  7.8 62.483 8.112 63.205 ;
     RECT  2.4 58.501 6.168 64.883 ;
     RECT  7.68 63.205 8.112 64.931 ;
     RECT  2.4 64.883 3.624 65.027 ;
     RECT  5.1 64.883 6.168 65.941 ;
     RECT  7.8 64.931 8.112 66.037 ;
     RECT  7.68 66.037 8.112 67.427 ;
     RECT  4.992 65.941 6.168 68.917 ;
     RECT  3.984 68.245 4.008 69.493 ;
     RECT  7.8 67.427 8.112 69.493 ;
     RECT  4.992 68.917 6.312 70.405 ;
     RECT  7.296 69.493 8.112 70.405 ;
     RECT  3.936 69.493 4.008 70.597 ;
     RECT  4.992 70.405 8.112 70.597 ;
     RECT  2.4 65.027 2.712 70.645 ;
     RECT  3.936 70.597 8.112 70.645 ;
     RECT  2.4 70.645 8.112 71.843 ;
     RECT  3.984 71.843 8.112 72.515 ;
     RECT  7.296 72.515 8.112 73.909 ;
     RECT  7.296 73.909 8.232 74.533 ;
     RECT  3.984 72.515 6.168 74.629 ;
     RECT  7.2 74.533 8.232 76.117 ;
     RECT  7.2 76.117 8.472 77.027 ;
     RECT  2.4 71.843 2.712 77.701 ;
     RECT  3.792 74.629 6.168 77.701 ;
     RECT  2.4 77.701 6.168 78.515 ;
     RECT  3.792 78.515 6.168 78.611 ;
     RECT  7.8 77.027 8.472 79.091 ;
     RECT  2.4 78.515 2.712 79.717 ;
     RECT  4.224 78.611 6.168 79.717 ;
     RECT  2.4 79.717 6.168 79.811 ;
     RECT  7.8 79.091 8.28 80.341 ;
     RECT  2.4 79.811 3.672 81.445 ;
     RECT  5.1 79.811 6.168 81.445 ;
     RECT  2.4 81.445 6.168 82.021 ;
     RECT  7.44 80.341 8.28 82.021 ;
     RECT  2.4 82.021 8.28 82.787 ;
     RECT  3.696 82.787 8.28 82.835 ;
     RECT  3.696 82.835 3.72 84.325 ;
     RECT  4.896 82.835 8.28 84.325 ;
     RECT  3.696 84.325 8.28 86.675 ;
     RECT  3.888 86.675 8.28 86.771 ;
     RECT  4.512 86.771 8.28 87.443 ;
     RECT  4.512 87.443 6.168 87.827 ;
     RECT  7.344 87.443 8.28 90.565 ;
     RECT  4.032 88.309 4.056 90.659 ;
     RECT  3.984 90.901 4.008 91.717 ;
     RECT  5.1 87.827 6.168 91.717 ;
     RECT  7.2 90.565 8.28 91.717 ;
     RECT  3.984 91.717 8.28 91.907 ;
     RECT  3.984 91.907 8.112 92.387 ;
     RECT  4.752 92.387 8.112 92.435 ;
     RECT  5.1 92.435 8.112 93.301 ;
     RECT  5.1 93.301 8.232 93.539 ;
     RECT  3.696 93.445 3.72 94.021 ;
     RECT  7.8 93.539 8.232 94.403 ;
     RECT  3.696 94.021 3.96 94.645 ;
     RECT  5.1 93.539 6.312 94.645 ;
     RECT  3.696 94.645 6.312 95.267 ;
     RECT  7.8 94.403 8.112 95.701 ;
     RECT  3.792 95.267 6.312 97.429 ;
     RECT  32.1 2.151 32.412 98.437 ;
     RECT  3.792 97.429 6.648 98.581 ;
     RECT  7.68 95.701 8.112 98.581 ;
     RECT  32.1 98.437 32.52 98.627 ;
     RECT  2.4 82.787 2.712 99.685 ;
     RECT  3.792 98.581 8.112 99.685 ;
     RECT  2.4 99.685 8.112 101.317 ;
     RECT  2.4 101.317 8.232 103.235 ;
     RECT  2.4 103.235 8.112 104.051 ;
     RECT  4.56 104.051 8.112 104.339 ;
     RECT  2.4 104.051 3.528 104.915 ;
     RECT  4.992 104.339 8.112 105.397 ;
     RECT  4.752 105.397 8.112 106.355 ;
     RECT  4.752 106.355 5.928 106.549 ;
     RECT  6.912 106.355 8.112 106.789 ;
     RECT  6.912 106.789 8.232 107.219 ;
     RECT  4.608 106.549 5.928 107.795 ;
     RECT  4.848 107.795 5.928 108.181 ;
     RECT  4.848 108.181 6.792 108.323 ;
     RECT  4.992 108.323 6.792 110.485 ;
     RECT  4.704 110.485 6.792 111.445 ;
     RECT  4.56 111.445 6.792 112.645 ;
     RECT  7.8 107.219 8.232 112.645 ;
     RECT  4.56 112.645 8.232 112.691 ;
     RECT  6.864 112.691 8.232 113.555 ;
     RECT  2.4 104.915 2.712 113.605 ;
     RECT  4.56 112.691 5.832 113.651 ;
     RECT  7.8 113.555 8.232 114.517 ;
     RECT  4.848 113.651 5.832 116.581 ;
     RECT  7.2 114.517 8.232 116.963 ;
     RECT  2.4 113.605 3.432 117.205 ;
     RECT  4.848 116.581 5.976 117.205 ;
     RECT  2.4 117.205 5.976 117.251 ;
     RECT  3.936 117.251 5.976 118.019 ;
     RECT  2.4 117.251 2.712 118.261 ;
     RECT  3.936 118.019 3.96 118.261 ;
     RECT  2.4 118.261 3.96 118.307 ;
     RECT  4.944 118.019 5.976 118.595 ;
     RECT  7.8 116.963 8.232 120.083 ;
     RECT  4.992 118.595 5.976 120.227 ;
     RECT  2.4 118.307 3.528 120.515 ;
     RECT  5.1 120.227 5.976 121.381 ;
     RECT  7.8 120.083 8.112 121.381 ;
     RECT  2.4 120.515 3.432 121.571 ;
     RECT  4.608 121.381 8.112 122.099 ;
     RECT  6.912 122.099 8.112 123.637 ;
     RECT  5.1 122.099 5.832 124.213 ;
     RECT  4.56 124.213 5.832 124.261 ;
     RECT  6.864 123.637 8.112 124.261 ;
     RECT  2.4 121.571 3.384 125.075 ;
     RECT  4.56 124.261 8.112 125.701 ;
     RECT  4.56 125.701 8.232 125.843 ;
     RECT  4.56 125.843 5.832 126.035 ;
     RECT  6.864 125.843 8.232 126.755 ;
     RECT  6.864 126.755 8.112 127.139 ;
     RECT  2.4 125.075 2.712 129.609 ;
     RECT  7.8 127.139 8.112 129.609 ;
     RECT  10.5 2.151 10.812 129.609 ;
     RECT  13.2 2.151 13.512 129.609 ;
     RECT  15.9 2.151 16.212 129.609 ;
     RECT  18.6 2.151 18.912 129.609 ;
     RECT  21.3 2.151 21.612 129.609 ;
     RECT  24 2.151 24.312 129.609 ;
     RECT  26.7 2.151 27.012 129.609 ;
     RECT  29.4 2.151 29.712 129.609 ;
     RECT  32.1 98.627 32.412 129.609 ;
     RECT  2.4 129.609 2.52 129.623 ;
     RECT  5.1 126.035 5.832 129.623 ;
     RECT  7.8 129.609 7.92 129.623 ;
     RECT  10.5 129.609 10.62 129.623 ;
     RECT  13.2 129.609 13.32 129.623 ;
     RECT  15.9 129.609 16.02 129.623 ;
     RECT  18.6 129.609 18.72 129.623 ;
     RECT  21.3 129.609 21.42 129.623 ;
     RECT  24 129.609 24.12 129.623 ;
     RECT  26.7 129.609 26.82 129.623 ;
     RECT  29.4 129.609 29.52 129.623 ;
     RECT  32.1 129.609 32.22 129.623 ;
     RECT  5.808 129.623 5.832 131.651 ;
     RECT  3.48 5.605 4.896 6.035 ;
     RECT  2.712 6.035 4.896 6.805 ;
     RECT  2.712 6.805 3.936 7.859 ;
     RECT  6.312 7.381 7.296 7.955 ;
     RECT  2.712 7.859 4.032 10.067 ;
     RECT  6.312 7.955 7.392 8.147 ;
     RECT  7.248 8.147 7.392 9.397 ;
     RECT  5.412 9.925 6.48 10.499 ;
     RECT  2.712 10.067 4.128 12.469 ;
     RECT  2.712 12.469 3.936 16.595 ;
     RECT  5.412 14.005 6.768 14.725 ;
     RECT  5.688 14.725 6.768 15.925 ;
     RECT  3.96 15.443 5.1 16.405 ;
     RECT  2.712 16.595 4.8 17.029 ;
     RECT  2.712 17.029 3.744 18.851 ;
     RECT  3.768 17.029 4.8 17.651 ;
     RECT  3.768 17.651 4.992 18.851 ;
     RECT  4.416 18.851 4.992 19.237 ;
     RECT  4.416 21.155 4.8 21.541 ;
     RECT  2.712 21.541 3.792 27.829 ;
     RECT  3.816 21.541 4.8 22.165 ;
     RECT  6.072 21.971 7.68 23.125 ;
     RECT  3.816 23.411 4.992 23.987 ;
     RECT  3.816 23.987 5.1 25.045 ;
     RECT  6.168 25.139 7.8 26.101 ;
     RECT  3.816 25.907 4.992 27.875 ;
     RECT  3.528 27.875 4.992 28.837 ;
     RECT  3.768 28.837 4.992 30.565 ;
     RECT  3.912 30.565 4.992 32.869 ;
     RECT  2.712 30.611 3.744 35.843 ;
     RECT  3.768 34.259 5.1 35.843 ;
     RECT  8.112 34.931 8.28 36.421 ;
     RECT  6.648 35.605 7.8 37.189 ;
     RECT  2.712 37.429 3.84 38.819 ;
     RECT  3.864 37.429 5.1 38.819 ;
     RECT  6.648 40.499 7.8 42.709 ;
     RECT  2.712 40.981 3.936 43.379 ;
     RECT  3.96 40.981 5.1 42.709 ;
     RECT  6.312 44.099 7.8 46.117 ;
     RECT  2.712 46.165 4.032 50.101 ;
     RECT  6.504 47.267 7.8 48.469 ;
     RECT  6.504 48.469 7.68 51.253 ;
     RECT  4.056 49.619 5.1 50.579 ;
     RECT  3.96 50.579 5.1 51.923 ;
     RECT  6.504 51.253 7.488 51.347 ;
     RECT  6.168 51.347 7.488 54.565 ;
     RECT  6.312 54.565 7.488 54.755 ;
     RECT  6.312 54.755 7.8 56.341 ;
     RECT  6.312 56.341 7.44 56.771 ;
     RECT  6.168 56.771 7.44 57.059 ;
     RECT  3.528 57.445 4.992 58.501 ;
     RECT  6.168 63.205 7.68 64.931 ;
     RECT  3.624 64.883 5.1 65.027 ;
     RECT  6.168 64.931 7.8 66.037 ;
     RECT  4.992 65.027 5.1 65.941 ;
     RECT  6.168 66.037 7.68 67.427 ;
     RECT  6.168 67.427 7.8 68.917 ;
     RECT  2.712 68.245 3.984 69.493 ;
     RECT  4.008 68.245 4.992 70.597 ;
     RECT  6.312 68.917 7.8 69.493 ;
     RECT  2.712 69.493 3.936 70.645 ;
     RECT  6.312 69.493 7.296 70.405 ;
     RECT  2.712 71.843 3.984 74.629 ;
     RECT  6.168 72.515 7.296 74.533 ;
     RECT  6.168 74.533 7.2 77.027 ;
     RECT  2.712 74.629 3.792 77.701 ;
     RECT  2.712 78.515 3.792 78.611 ;
     RECT  2.712 78.611 4.224 79.717 ;
     RECT  3.672 79.811 5.1 81.445 ;
     RECT  6.168 80.341 7.44 82.021 ;
     RECT  2.712 82.787 3.696 86.675 ;
     RECT  3.72 82.835 4.896 84.325 ;
     RECT  2.712 86.675 3.888 86.771 ;
     RECT  6.168 87.443 7.344 90.565 ;
     RECT  4.512 87.827 5.1 88.309 ;
     RECT  2.712 88.309 4.032 90.659 ;
     RECT  4.056 88.309 5.1 90.659 ;
     RECT  6.168 90.565 7.2 91.717 ;
     RECT  2.712 90.659 5.1 90.901 ;
     RECT  2.712 90.901 3.984 92.387 ;
     RECT  4.008 90.901 5.1 91.717 ;
     RECT  8.112 91.907 8.232 93.301 ;
     RECT  2.712 92.387 4.752 92.435 ;
     RECT  2.712 92.435 5.1 93.445 ;
     RECT  2.712 93.445 3.696 95.267 ;
     RECT  3.72 93.445 5.1 94.021 ;
     RECT  6.312 93.539 7.8 95.701 ;
     RECT  3.96 94.021 5.1 94.645 ;
     RECT  2.712 95.267 3.792 99.685 ;
     RECT  6.312 95.701 7.68 97.429 ;
     RECT  6.648 97.429 7.68 98.581 ;
     RECT  3.528 104.051 4.56 104.339 ;
     RECT  3.528 104.339 4.992 104.915 ;
     RECT  4.752 104.915 4.992 105.397 ;
     RECT  5.928 106.355 6.912 107.219 ;
     RECT  5.928 107.219 7.8 108.181 ;
     RECT  6.792 108.181 7.8 112.645 ;
     RECT  5.832 112.691 6.864 113.555 ;
     RECT  5.832 113.555 7.8 114.517 ;
     RECT  3.432 113.605 4.56 113.651 ;
     RECT  3.432 113.651 4.848 117.205 ;
     RECT  5.832 114.517 7.2 116.581 ;
     RECT  5.976 116.581 7.2 116.963 ;
     RECT  2.712 117.251 3.936 118.261 ;
     RECT  3.96 118.019 4.944 118.307 ;
     RECT  3.528 118.307 4.944 118.595 ;
     RECT  3.528 118.595 4.992 120.227 ;
     RECT  3.528 120.227 5.1 120.515 ;
     RECT  3.432 120.515 5.1 121.381 ;
     RECT  3.432 121.381 4.608 121.571 ;
     RECT  3.384 121.571 4.608 122.099 ;
     RECT  5.832 122.099 6.912 123.637 ;
     RECT  5.832 123.637 6.864 124.261 ;
     RECT  3.384 124.213 4.56 125.075 ;
     RECT  5.832 125.843 6.864 127.139 ;
  END
END dsfd_hstnh_761
END LIBRARY
